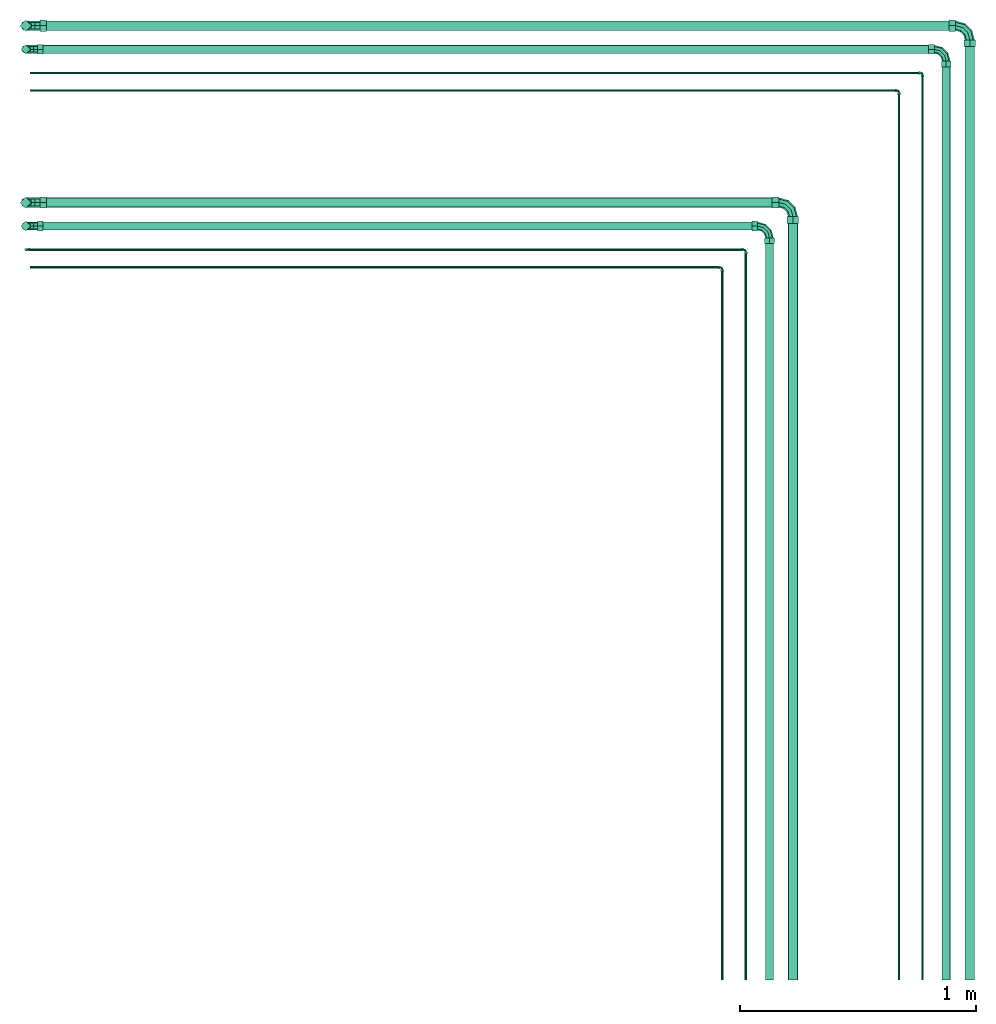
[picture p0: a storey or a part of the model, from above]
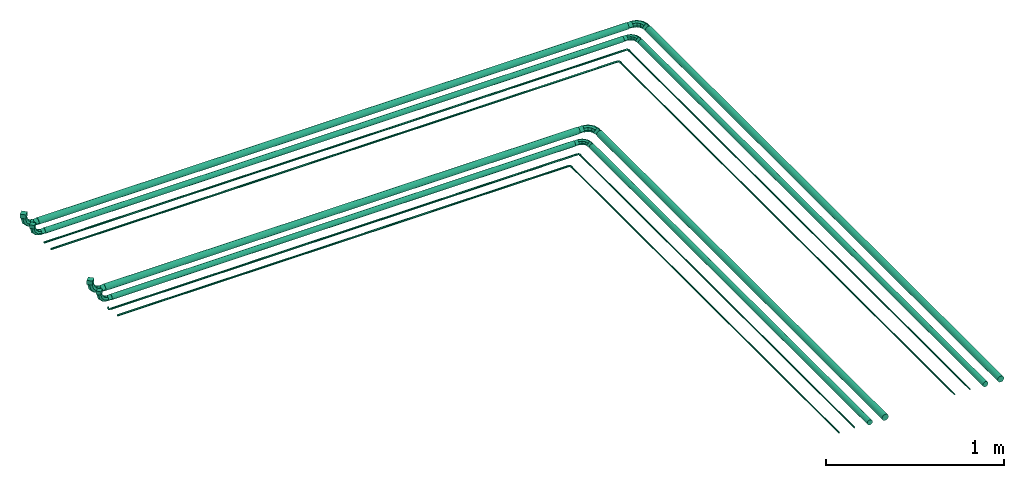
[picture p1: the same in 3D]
Properties of the parts of a building model (IFC2X3), part 1 of 7

# File
Description: ViewDefinition [CoordinationView_V2.0, QuantityTakeOffAddOnView], RevitIdentifiers [ContentGUID: b6227886-03ab-44f0-81d4-b4d026a18376, VersionGUID: a14e6cfa-9476-4cd4-931d-6547d9f84653, NumberOfSaves: 1519], CoordinateReference [CoordinateBase: Interner Ursprung, ProjectSite: Intern]
File name: 593 Vivantes - Ausbau VZ Seidelbastweg.ifc
Time: 2026-07-30T15:20:55+01:00
Author: GIEL Planungsgesellschaft mbH, info@giel.com
Organization: GIEL Planungsgesellschaft mbH
Written by: ODA SDAI 24.12
Made in: Autodesk Revit 25.4.41.14 (DEU) - IFC 25.4.41.14

# IfcProject, 0804
LongName: Mieter-Ausbau der Lagerhalle zu einem Speisenverteilzentrum

# IfcSite, Default
RefLatitude: 50, 46, 31, 241455; RefLongitude: 6, 5, 1, 991844; RefElevation: 0 mm

# IfcSite: ARC_ALL_Koordinationskörper_Doppelpyramide:ARC_ALL_Koordinationskörper_Doppelpyramide, ARC_ALL_Koordinationskörper_Doppelpyramide:ARC_ALL_Koordinationskörper_Doppelpyramide:4717062
Material: KOO_Pyramide
BaseQuantities - GrossArea: 3.23607 m2

# IfcBuildingStorey: Ebene:OKFF (3)
Name | LongName | Elevation (mm)
EG_Technik_FFB | EG_Technik_FFB | 695.653
EG_Produktion_FFB | EG_Produktion_FFB | 1730.7
Wartung_FFB | Wartung_FFB | 7130.7

# IfcCovering: Deckensystem:Kühlraum 100 (6)
In: EG_Produktion_FFB
Type - PredefinedType: CEILING
Material: GPG_Kühlraum 8 mm, GPG_Kühlraum 84 mm, GPG_Kühlraum 8 mm
Pset Bauphysik - OQ_Typ gem. Bauphysik: Pos. 2.4; U = 0,27 W/(m²/K)
Pset_FM-Vivantes - Baujahr: 1; Prüfpflicht: yes; Prüfintervall: 1; Sammelobjekt: yes; rechn. Lebensdauer: 1; Familie und Typ: Deckensystem: Kühlraum 100; Klasse: 471; Bezeichnung: Deckensystem: Kühlraum 100; AKS: i.b.; Standort: i.b.; Hersteller: i.b.; Hersteller-Typ: i.b.; Seriennummer: i.b.; Gewährleistungsgeber: 1; Betriebsstatus: i.b.; technischer Zustand: i.b.; Eigentümer: i.b.; Bemerkung: i.b.
Name (Deckensystem:Kühlraum 100:...) | GrossCeilingArea (m2)
4498795 | 284.674
4499242 | 243.11
4832303 | 16.77
4832498 | 883.613
4832682 | 76.866
4832818 | 9.5834

# IfcCovering: Deckensystem:Kühlraum 150, Deckensystem:Kühlraum 150:4499552
In: EG_Produktion_FFB
Type - PredefinedType: CEILING
Material: GPG_Kühlraum 8 mm, GPG_Kühlraum 134 mm, GPG_Kühlraum 8 mm
Pset Bauphysik - OQ_Typ gem. Bauphysik: Pos. 2.5; U = 0,18 W/(m²/K)
Pset_FM-Vivantes - Baujahr: 1; Prüfpflicht: yes; Prüfintervall: 1; Sammelobjekt: yes; rechn. Lebensdauer: 1; Familie und Typ: Deckensystem: Kühlraum 150; Klasse: 471; Bezeichnung: Deckensystem: Kühlraum 150; AKS: i.b.; Standort: i.b.; Hersteller: i.b.; Hersteller-Typ: i.b.; Seriennummer: i.b.; Gewährleistungsgeber: 1; Betriebsstatus: i.b.; technischer Zustand: i.b.; Eigentümer: i.b.; Bemerkung: i.b.
BaseQuantities - GrossCeilingArea: 107.964 m2

# IfcCovering: Rohrdämmung außen:Armaflex-Schlauch (1548)
Type - PredefinedType: INSULATION
Material: Dämmung - Armaflex-Schlauch
Pset_FM-Vivantes - Baujahr: 1; Prüfpflicht: yes; Prüfintervall: 1; Sammelobjekt: yes; rechn. Lebensdauer: 1; fahrbar: no; Familie und Typ: Rohrdämmung außen: Armaflex-Schlauch; Klasse: 471; Bezeichnung: Armaflex-Schlauch; AKS: i.b.; Standort: i.b.; Hersteller: i.b.; Hersteller-Typ: i.b.; Seriennummer: i.b.; Gewährleistungsgeber: 1; Betriebsstatus: i.b.; technischer Zustand: i.b.; Eigentümer: i.b.; Bemerkung: i.b.
Name (Rohrdämmung außen:Armaflex-Schlauch:...) | In | Systemname
8579191 | EG_Produktion_FFB | A - Kondensatleitung Gaskühler
8579194 | EG_Produktion_FFB | A - Kondensatleitung Gaskühler
8579200 | EG_Produktion_FFB | A - Kondensatleitung Gaskühler | BaseQuantities - GrossCeilingArea: 0.00418476 m2
8579203 | EG_Produktion_FFB | A - Kondensatleitung Gaskühler
8579206 | EG_Produktion_FFB | A - Kondensatleitung Gaskühler
8579212 | EG_Produktion_FFB | A - Kondensatleitung Gaskühler | BaseQuantities - GrossCeilingArea: 0.00418476 m2
8579215 | EG_Produktion_FFB | A - Kondensatleitung Gaskühler | BaseQuantities - GrossCeilingArea: 0.00418476 m2
8579218 | Wartung_FFB | A - Kondensatleitung Gaskühler
8579221 | EG_Produktion_FFB | A - Kondensatleitung Gaskühler
8579224 | EG_Produktion_FFB | A - Kondensatleitung Gaskühler
8579227 | Wartung_FFB | A - Kondensatleitung Gaskühler
8579230 | Wartung_FFB | A - Kondensatleitung Gaskühler
8579233 | Wartung_FFB | A - Kondensatleitung Gaskühler
8579236 | EG_Produktion_FFB | A - Druckleitung Gaskühler
8579239 | EG_Produktion_FFB | A - Druckleitung Gaskühler
8579242 | EG_Produktion_FFB | A - Druckleitung Gaskühler | BaseQuantities - GrossCeilingArea: 0.00502579 m2
8579245 | EG_Produktion_FFB | A - Druckleitung Gaskühler
8579248 | EG_Produktion_FFB | A - Druckleitung Gaskühler | BaseQuantities - GrossCeilingArea: 0.00502579 m2
8579251 | EG_Produktion_FFB | A - Druckleitung Gaskühler | BaseQuantities - GrossCeilingArea: 0.00502579 m2
8579254 | Wartung_FFB | A - Druckleitung Gaskühler
8579257 | Wartung_FFB | A - Druckleitung Gaskühler
8579263 | EG_Produktion_FFB | A - Druckleitung Gaskühler
8579266 | EG_Produktion_FFB | A - Druckleitung Gaskühler
8579281 | Wartung_FFB | B - Kondensatleitung Gaskühler
8579284 | Wartung_FFB | B - Druckleitung Gaskühler
8579287 | Wartung_FFB | B - Kondensatleitung Gaskühler
8579290 | Wartung_FFB | B - Druckleitung Gaskühler
8579293 | Wartung_FFB | B - Kondensatleitung Gaskühler
8579296 | Wartung_FFB | B - Druckleitung Gaskühler
8579297 | EG_Produktion_FFB | B - Druckleitung Gaskühler
8579300 | Wartung_FFB | B - Kondensatleitung Gaskühler
8579303 | Wartung_FFB | B - Druckleitung Gaskühler
8579308 | Wartung_FFB | B - Kondensatleitung Gaskühler
8579309 | Wartung_FFB | B - Kondensatleitung Gaskühler | BaseQuantities - GrossCeilingArea: 0.00418476 m2
8579312 | Wartung_FFB | B - Kondensatleitung Gaskühler
8579317 | Wartung_FFB | B - Druckleitung Gaskühler
8579318 | Wartung_FFB | B - Druckleitung Gaskühler | BaseQuantities - GrossCeilingArea: 0.00502579 m2
8579324 | EG_Produktion_FFB | B - Druckleitung Gaskühler | BaseQuantities - GrossCeilingArea: 0.00502579 m2
8579327 | EG_Produktion_FFB | B - Kondensatleitung Gaskühler | BaseQuantities - GrossCeilingArea: 0.00418476 m2
8579330 | Wartung_FFB | B - Kondensatleitung Gaskühler
8579333 | Wartung_FFB | B - Druckleitung Gaskühler
8579339 | EG_Produktion_FFB | B - Kondensatleitung Gaskühler
8579344 | EG_Produktion_FFB | B - Kondensatleitung Gaskühler
8579349 | EG_Produktion_FFB | B - Kondensatleitung Gaskühler
8579350 | EG_Produktion_FFB | B - Kondensatleitung Gaskühler | BaseQuantities - GrossCeilingArea: 0.00418476 m2
8579359 | EG_Produktion_FFB | B - Druckleitung Gaskühler
8579365 | EG_Produktion_FFB | B - Druckleitung Gaskühler | BaseQuantities - GrossCeilingArea: 0.00502579 m2
8579368 | EG_Produktion_FFB | B - Druckleitung Gaskühler
8579371 | EG_Produktion_FFB | A - FL-Str.01_NK-KK-TK
8579401 | EG_Produktion_FFB | A - FL-Str.01_NK-KK-TK
8579407 | EG_Produktion_FFB | A - FL-Str.01_NK-KK-TK
8579412 | EG_Produktion_FFB | A - FL-Str.01_NK-KK-TK
8579414 | EG_Produktion_FFB | A - FL-Str.01_NK-KK-TK | BaseQuantities - GrossCeilingArea: 0.00865886 m2
8579418 | EG_Produktion_FFB | A - FL-Str.01_NK-KK-TK
8579420 | EG_Produktion_FFB | A - FL-Str.01_NK-KK-TK | BaseQuantities - GrossCeilingArea: 0.00865886 m2
8579427 | EG_Produktion_FFB | A - FL-Str.01_NK-KK-TK
8579429 | EG_Produktion_FFB | A - FL-Str.01_NK-KK-TK | BaseQuantities - GrossCeilingArea: 0.00796711 m2
8579436 | EG_Produktion_FFB | A - FL-Str.01_NK-KK-TK
8579438 | EG_Produktion_FFB | A - FL-Str.01_NK-KK-TK | BaseQuantities - GrossCeilingArea: 0.00865886 m2
8579440 | EG_Produktion_FFB | A - FL-Str.01_NK-KK-TK | BaseQuantities - GrossCeilingArea: 0.00662464 m2
8579453 | EG_Produktion_FFB | A - FL-Str.01_NK-KK-TK
8579455 | EG_Produktion_FFB | A - FL-Str.01_NK-KK-TK | BaseQuantities - GrossCeilingArea: 0.0045539 m2
8579459 | EG_Produktion_FFB | A - FL-Str.01_NK-KK-TK
8579461 | EG_Produktion_FFB | A - FL-Str.01_NK-KK-TK | BaseQuantities - GrossCeilingArea: 0.00376881 m2
8579465 | EG_Produktion_FFB | A - FL-Str.01_NK-KK-TK
8579467 | EG_Produktion_FFB | A - FL-Str.01_NK-KK-TK | BaseQuantities - GrossCeilingArea: 0.00304559 m2
8579501 | EG_Produktion_FFB | A - FL-Str.01_NK-KK-TK
8579503 | EG_Produktion_FFB | A - FL-Str.01_NK-KK-TK | BaseQuantities - GrossCeilingArea: 0.00483791 m2
8579507 | EG_Produktion_FFB | A - FL-Str.01_NK-KK-TK
8579509 | EG_Produktion_FFB | A - FL-Str.01_NK-KK-TK | BaseQuantities - GrossCeilingArea: 0.00599476 m2
8579515 | EG_Produktion_FFB | A - FL-Str.01_NK-KK-TK
8579518 | EG_Produktion_FFB | A - FL-Str.01_NK-KK-TK
8579523 | EG_Produktion_FFB | A - FL-Str.01_NK-KK-TK
8579524 | EG_Produktion_FFB | A - FL-Str.01_NK-KK-TK | BaseQuantities - GrossCeilingArea: 0.00417616 m2
8579533 | EG_Produktion_FFB | B - FL-Str.01_NK-KK-TK
8579536 | EG_Produktion_FFB | B - FL-Str.01_NK-KK-TK
8579541 | EG_Produktion_FFB | B - FL-Str.01_NK-KK-TK
8579542 | EG_Produktion_FFB | B - FL-Str.01_NK-KK-TK | BaseQuantities - GrossCeilingArea: 0.00417616 m2
8579587 | EG_Produktion_FFB | B - FL-Str.01_NK-KK-TK
8579589 | EG_Produktion_FFB | B - FL-Str.01_NK-KK-TK | BaseQuantities - GrossCeilingArea: 0.0045539 m2
8579590 | EG_Produktion_FFB | B - FL-Str.01_NK-KK-TK
8579615 | EG_Produktion_FFB | B - FL-Str.01_NK-KK-TK
8579617 | EG_Produktion_FFB | B - FL-Str.01_NK-KK-TK | BaseQuantities - GrossCeilingArea: 0.00483791 m2
8579621 | EG_Produktion_FFB | B - FL-Str.01_NK-KK-TK
8579623 | EG_Produktion_FFB | B - FL-Str.01_NK-KK-TK | BaseQuantities - GrossCeilingArea: 0.00599476 m2
8579630 | EG_Produktion_FFB | B - FL-Str.01_NK-KK-TK
8579632 | EG_Produktion_FFB | B - FL-Str.01_NK-KK-TK | BaseQuantities - GrossCeilingArea: 0.00304559 m2
8579636 | EG_Produktion_FFB | B - FL-Str.01_NK-KK-TK
8579638 | EG_Produktion_FFB | B - FL-Str.01_NK-KK-TK | BaseQuantities - GrossCeilingArea: 0.00376881 m2
8579645 | EG_Produktion_FFB | B - FL-Str.01_NK-KK-TK
8579647 | EG_Produktion_FFB | B - FL-Str.01_NK-KK-TK | BaseQuantities - GrossCeilingArea: 0.00662464 m2
8579651 | EG_Produktion_FFB | B - FL-Str.01_NK-KK-TK
8579653 | EG_Produktion_FFB | B - FL-Str.01_NK-KK-TK | BaseQuantities - GrossCeilingArea: 0.00662464 m2
8579657 | EG_Produktion_FFB | B - FL-Str.01_NK-KK-TK
8579659 | EG_Produktion_FFB | B - FL-Str.01_NK-KK-TK | BaseQuantities - GrossCeilingArea: 0.00796711 m2
8579663 | EG_Produktion_FFB | B - FL-Str.01_NK-KK-TK
8579665 | EG_Produktion_FFB | B - FL-Str.01_NK-KK-TK | BaseQuantities - GrossCeilingArea: 0.00865886 m2
8579669 | EG_Produktion_FFB | B - FL-Str.01_NK-KK-TK
8579671 | EG_Produktion_FFB | B - FL-Str.01_NK-KK-TK | BaseQuantities - GrossCeilingArea: 0.00865886 m2
8579675 | EG_Produktion_FFB | B - FL-Str.01_NK-KK-TK
8579677 | EG_Produktion_FFB | B - FL-Str.01_NK-KK-TK | BaseQuantities - GrossCeilingArea: 0.00865886 m2
8579702 | EG_Produktion_FFB | B - FL-Str.01_NK-KK-TK
8579704 | EG_Produktion_FFB | B - FL-Str.01_NK-KK-TK | BaseQuantities - GrossCeilingArea: 0.00662464 m2
8579707 | EG_Produktion_FFB | A - FL-Str.03_NK-KK-TK
8579708 | EG_Produktion_FFB | A - FL-Str.03_NK-KK-TK
8579744 | EG_Produktion_FFB | A - FL-Str.03_NK-KK-TK
8579746 | EG_Produktion_FFB | A - FL-Str.03_NK-KK-TK | BaseQuantities - GrossCeilingArea: 0.00796711 m2
8579753 | EG_Produktion_FFB | A - FL-Str.03_NK-KK-TK
8579755 | EG_Produktion_FFB | A - FL-Str.03_NK-KK-TK | BaseQuantities - GrossCeilingArea: 0.00376881 m2
8579759 | EG_Produktion_FFB | A - FL-Str.03_NK-KK-TK
8579761 | EG_Produktion_FFB | A - FL-Str.03_NK-KK-TK | BaseQuantities - GrossCeilingArea: 0.00425419 m2
8579765 | EG_Produktion_FFB | A - FL-Str.03_NK-KK-TK
8579767 | EG_Produktion_FFB | A - FL-Str.03_NK-KK-TK | BaseQuantities - GrossCeilingArea: 0.00599476 m2
8579771 | EG_Produktion_FFB | A - FL-Str.03_NK-KK-TK
8579773 | EG_Produktion_FFB | A - FL-Str.03_NK-KK-TK | BaseQuantities - GrossCeilingArea: 0.00662464 m2
8579776 | EG_Produktion_FFB | B - FL-Str.03_NK-KK-TK
8579806 | EG_Produktion_FFB | B - FL-Str.03_NK-KK-TK | BaseQuantities - GrossCeilingArea: 0.00865886 m2
8579815 | EG_Produktion_FFB | B - FL-Str.03_NK-KK-TK
8579817 | EG_Produktion_FFB | B - FL-Str.03_NK-KK-TK | BaseQuantities - GrossCeilingArea: 0.00865886 m2
8579821 | EG_Produktion_FFB | B - FL-Str.03_NK-KK-TK
8579823 | EG_Produktion_FFB | B - FL-Str.03_NK-KK-TK | BaseQuantities - GrossCeilingArea: 0.00796711 m2
8579830 | EG_Produktion_FFB | B - FL-Str.03_NK-KK-TK
8579832 | EG_Produktion_FFB | B - FL-Str.03_NK-KK-TK | BaseQuantities - GrossCeilingArea: 0.00376881 m2
8579836 | EG_Produktion_FFB | B - FL-Str.03_NK-KK-TK
8579838 | EG_Produktion_FFB | B - FL-Str.03_NK-KK-TK | BaseQuantities - GrossCeilingArea: 0.0045539 m2
8579842 | EG_Produktion_FFB | B - FL-Str.03_NK-KK-TK
8579844 | EG_Produktion_FFB | B - FL-Str.03_NK-KK-TK | BaseQuantities - GrossCeilingArea: 0.00599476 m2
8579848 | EG_Produktion_FFB | B - FL-Str.03_NK-KK-TK
8579850 | EG_Produktion_FFB | B - FL-Str.03_NK-KK-TK | BaseQuantities - GrossCeilingArea: 0.00662464 m2
8579851 | EG_Produktion_FFB | B - FL-Str.03_NK-KK-TK
8579866 | EG_Produktion_FFB | B - FL-Str.02_NK-KK-TK
8579870 | EG_Produktion_FFB | A - FL-Str.03_NK-KK-TK
8579879 | EG_Produktion_FFB | B - FL-Str.02_NK-KK-TK
8579881 | EG_Produktion_FFB | B - FL-Str.02_NK-KK-TK | BaseQuantities - GrossCeilingArea: 0.00796711 m2
8579898 | EG_Produktion_FFB | A - FL-Str.02_NK-KK-TK
8579904 | EG_Produktion_FFB | A - FL-Str.02_NK-KK-TK
8579906 | EG_Produktion_FFB | A - FL-Str.02_NK-KK-TK | BaseQuantities - GrossCeilingArea: 0.00796711 m2
8579909 | EG_Produktion_FFB | A - FL-Str.03_NK-KK-TK
8579910 | EG_Produktion_FFB | A - FL-Str.03_NK-KK-TK
8579913 | EG_Produktion_FFB | A - FL-Str.03_NK-KK-TK
8579914 | EG_Produktion_FFB | B - FL-Str.03_NK-KK-TK
8579915 | EG_Produktion_FFB | B - FL-Str.03_NK-KK-TK
8579920 | EG_Produktion_FFB | B - FL-Str.03_NK-KK-TK
8579925 | EG_Produktion_FFB | B - FL-Str.03_NK-KK-TK | BaseQuantities - GrossCeilingArea: 0.00417616 m2
8579930 | EG_Produktion_FFB | A - FL-Str.03_NK-KK-TK | BaseQuantities - GrossCeilingArea: 0.00417616 m2
8579933 | EG_Produktion_FFB | B - FL-Str.03_NK-KK-TK
8579936 | EG_Produktion_FFB | B - FL-Str.03_NK-KK-TK
8579939 | EG_Produktion_FFB | A - FL-Str.03_NK-KK-TK
8579952 | EG_Produktion_FFB | A - FL-Str.02_NK-KK-TK
8579954 | EG_Produktion_FFB | A - FL-Str.02_NK-KK-TK | BaseQuantities - GrossCeilingArea: 0.00662464 m2
8579958 | EG_Produktion_FFB | B - FL-Str.02_NK-KK-TK
8579960 | EG_Produktion_FFB | B - FL-Str.02_NK-KK-TK | BaseQuantities - GrossCeilingArea: 0.00662464 m2
8579967 | EG_Produktion_FFB | B - FL-Str.02_NK-KK-TK
8579969 | EG_Produktion_FFB | B - FL-Str.02_NK-KK-TK | BaseQuantities - GrossCeilingArea: 0.00662464 m2
8579987 | EG_Produktion_FFB | A - FL-Str.02_NK-KK-TK
8579989 | EG_Produktion_FFB | A - FL-Str.02_NK-KK-TK | BaseQuantities - GrossCeilingArea: 0.00662464 m2
8580011 | EG_Produktion_FFB | B - FL-Str.02_NK-KK-TK
8580013 | EG_Produktion_FFB | B - FL-Str.02_NK-KK-TK | BaseQuantities - GrossCeilingArea: 0.00662464 m2
8580020 | EG_Produktion_FFB | A - FL-Str.02_NK-KK-TK
8580022 | EG_Produktion_FFB | A - FL-Str.02_NK-KK-TK | BaseQuantities - GrossCeilingArea: 0.00662464 m2
8580029 | EG_Produktion_FFB | B - FL-Str.02_NK-KK-TK
8580031 | EG_Produktion_FFB | B - FL-Str.02_NK-KK-TK | BaseQuantities - GrossCeilingArea: 0.00662464 m2
8580065 | EG_Produktion_FFB | A - FL-Str.02_NK-KK-TK
8580067 | EG_Produktion_FFB | A - FL-Str.02_NK-KK-TK | BaseQuantities - GrossCeilingArea: 0.00662464 m2
8580077 | EG_Produktion_FFB | B - FL-Str.02_NK-KK-TK
8580079 | EG_Produktion_FFB | B - FL-Str.02_NK-KK-TK | BaseQuantities - GrossCeilingArea: 0.00599476 m2
8580086 | EG_Produktion_FFB | A - FL-Str.02_NK-KK-TK
8580088 | EG_Produktion_FFB | A - FL-Str.02_NK-KK-TK | BaseQuantities - GrossCeilingArea: 0.00599476 m2
8580122 | EG_Produktion_FFB | B - FL-Str.02_NK-KK-TK
8580124 | EG_Produktion_FFB | B - FL-Str.02_NK-KK-TK | BaseQuantities - GrossCeilingArea: 0.00483791 m2
8580131 | EG_Produktion_FFB | A - FL-Str.02_NK-KK-TK
8580133 | EG_Produktion_FFB | A - FL-Str.02_NK-KK-TK | BaseQuantities - GrossCeilingArea: 0.00483791 m2
8580143 | EG_Produktion_FFB | A - FL-Str.02_NK-KK-TK
8580145 | EG_Produktion_FFB | A - FL-Str.02_NK-KK-TK | BaseQuantities - GrossCeilingArea: 0.00483791 m2
8580539 | Wartung_FFB | B - Druckleitung Gaskühler
8580560 | Wartung_FFB | A - Druckleitung Gaskühler
8580563 | Wartung_FFB | A - Druckleitung Gaskühler
8580672 | EG_Produktion_FFB | B - Kondensatleitung Gaskühler
8580677 | EG_Produktion_FFB | B - Kondensatleitung Gaskühler
8580895 | EG_Produktion_FFB | B - FL-Str.02_NK-KK-TK
8580897 | EG_Produktion_FFB | B - FL-Str.02_NK-KK-TK | BaseQuantities - GrossCeilingArea: 0.00483791 m2
8582852 | EG_Produktion_FFB | A - SL_KK
8582855 | EG_Produktion_FFB | A - SL_KK
8582861 | EG_Produktion_FFB | A - SL_KK | BaseQuantities - GrossCeilingArea: 0.00348054 m2
8582998 | EG_Produktion_FFB | A - SL_KK
8583088 | EG_Produktion_FFB | A - SL_KK
8583112 | EG_Produktion_FFB | A - SL_KK
8583330 | EG_Produktion_FFB | A - SL_KK
8583610 | EG_Produktion_FFB | A - SL_KK
8583612 | EG_Produktion_FFB | A - SL_KK | BaseQuantities - GrossCeilingArea: 0.00304559 m2
8583719 | EG_Produktion_FFB | A - SL_KK
8583721 | EG_Produktion_FFB | A - SL_KK | BaseQuantities - GrossCeilingArea: 0.00238424 m2
8583917 | EG_Produktion_FFB | A - SL_KK
8583919 | EG_Produktion_FFB | A - SL_KK | BaseQuantities - GrossCeilingArea: 0.00483791 m2
8583940 | EG_Produktion_FFB | A - SL_KK
8583942 | EG_Produktion_FFB | A - SL_KK | BaseQuantities - GrossCeilingArea: 0.00483791 m2
8584011 | EG_Produktion_FFB | A - SL_KK
8584013 | EG_Produktion_FFB | A - SL_KK | BaseQuantities - GrossCeilingArea: 0.00662464 m2
8584297 | EG_Produktion_FFB | A - SL_KK
8584299 | EG_Produktion_FFB | A - SL_KK | BaseQuantities - GrossCeilingArea: 0.00483791 m2
8584322 | EG_Produktion_FFB | A - SL_KK
8584324 | EG_Produktion_FFB | A - SL_KK | BaseQuantities - GrossCeilingArea: 0.00599476 m2
8585075 | EG_Produktion_FFB | B - SL_KK
8585077 | EG_Produktion_FFB | B - SL_KK | BaseQuantities - GrossCeilingArea: 0.00238424 m2
8585078 | EG_Produktion_FFB | B - SL_KK
8585103 | EG_Produktion_FFB | B - SL_KK
8585105 | EG_Produktion_FFB | B - SL_KK | BaseQuantities - GrossCeilingArea: 0.00304559 m2
8585109 | EG_Produktion_FFB | B - SL_KK
8585139 | EG_Produktion_FFB | B - SL_KK
8585141 | EG_Produktion_FFB | B - SL_KK | BaseQuantities - GrossCeilingArea: 0.00483791 m2
8585145 | EG_Produktion_FFB | B - SL_KK
8585147 | EG_Produktion_FFB | B - SL_KK | BaseQuantities - GrossCeilingArea: 0.00483791 m2
8585151 | EG_Produktion_FFB | B - SL_KK
8585153 | EG_Produktion_FFB | B - SL_KK | BaseQuantities - GrossCeilingArea: 0.00483791 m2
8585157 | EG_Produktion_FFB | B - SL_KK
8585159 | EG_Produktion_FFB | B - SL_KK | BaseQuantities - GrossCeilingArea: 0.00599476 m2
8585163 | EG_Produktion_FFB | B - SL_KK
8585165 | EG_Produktion_FFB | B - SL_KK | BaseQuantities - GrossCeilingArea: 0.00662464 m2
8585189 | EG_Produktion_FFB | B - SL_KK | BaseQuantities - GrossCeilingArea: 0.00483791 m2
8585996 | EG_Produktion_FFB | B - SL_KK
8585998 | EG_Produktion_FFB | B - SL_KK | BaseQuantities - GrossCeilingArea: 0.00376881 m2
8586325 | EG_Produktion_FFB | B - SL_KK
8586327 | EG_Produktion_FFB | B - SL_KK | BaseQuantities - GrossCeilingArea: 0.0045539 m2
8586419 | EG_Produktion_FFB | B - SL_KK
8586422 | EG_Produktion_FFB | B - SL_KK
8586428 | EG_Produktion_FFB | B - SL_KK | BaseQuantities - GrossCeilingArea: 0.00348054 m2
8586465 | EG_Produktion_FFB | B - SL_KK
8586564 | EG_Produktion_FFB | A - SL_NK-Str.02
8586565 | EG_Produktion_FFB | A - SL_NK-Str.02
8586601 | EG_Produktion_FFB | A - SL_NK-Str.02
8586603 | EG_Produktion_FFB | A - SL_NK-Str.02 | BaseQuantities - GrossCeilingArea: 0.00662464 m2
8586622 | EG_Produktion_FFB | A - SL_NK-Str.02
8586624 | EG_Produktion_FFB | A - SL_NK-Str.02 | BaseQuantities - GrossCeilingArea: 0.0042699 m2
8586628 | EG_Produktion_FFB | A - SL_NK-Str.02
8586630 | EG_Produktion_FFB | A - SL_NK-Str.02 | BaseQuantities - GrossCeilingArea: 0.00599476 m2
8586633 | EG_Produktion_FFB | B - SL_NK-Str.02
8586663 | EG_Produktion_FFB | B - SL_NK-Str.02 | BaseQuantities - GrossCeilingArea: 0.00865886 m2
8586672 | EG_Produktion_FFB | B - SL_NK-Str.02
8586674 | EG_Produktion_FFB | B - SL_NK-Str.02 | BaseQuantities - GrossCeilingArea: 0.00796711 m2
8586678 | EG_Produktion_FFB | B - SL_NK-Str.02
8586680 | EG_Produktion_FFB | B - SL_NK-Str.02 | BaseQuantities - GrossCeilingArea: 0.00662464 m2
8586699 | EG_Produktion_FFB | B - SL_NK-Str.02
8586701 | EG_Produktion_FFB | B - SL_NK-Str.02 | BaseQuantities - GrossCeilingArea: 0.0042699 m2
8586705 | EG_Produktion_FFB | B - SL_NK-Str.02
8586707 | EG_Produktion_FFB | B - SL_NK-Str.02 | BaseQuantities - GrossCeilingArea: 0.00599476 m2
8586708 | EG_Produktion_FFB | B - SL_NK-Str.02
8586723 | EG_Produktion_FFB | B - SL_NK-Str.01
8586755 | EG_Produktion_FFB | A - SL_NK-Str.01
8586808 | EG_Produktion_FFB | A - SL_NK-Str.01
8586850 | EG_Produktion_FFB | B - SL_NK-Str.01
8586898 | EG_Produktion_FFB | B - SL_NK-Str.01
8586900 | EG_Produktion_FFB | B - SL_NK-Str.01 | BaseQuantities - GrossCeilingArea: 0.00865886 m2
8586907 | EG_Produktion_FFB | A - SL_NK-Str.01
8586909 | EG_Produktion_FFB | A - SL_NK-Str.01 | BaseQuantities - GrossCeilingArea: 0.00865886 m2
8586964 | EG_Produktion_FFB | A - SL_NK-Str.01
8586966 | EG_Produktion_FFB | A - SL_NK-Str.01 | BaseQuantities - GrossCeilingArea: 0.00865886 m2
8586973 | EG_Produktion_FFB | B - SL_NK-Str.01
8586975 | EG_Produktion_FFB | B - SL_NK-Str.01 | BaseQuantities - GrossCeilingArea: 0.00865886 m2
8587739 | EG_Produktion_FFB | A - SL_NK-Str.01 | BaseQuantities - GrossCeilingArea: 0.0101869 m2
8587918 | EG_Produktion_FFB | B - SL_NK-Str.01 | BaseQuantities - GrossCeilingArea: 0.0101869 m2
8587940 | EG_Produktion_FFB | A - SL_NK-Str.02
8587941 | EG_Produktion_FFB | A - SL_NK-Str.02
8587945 | EG_Produktion_FFB | B - SL_NK-Str.02
8587946 | EG_Produktion_FFB | B - SL_NK-Str.02
8587956 | EG_Produktion_FFB | B - SL_NK-Str.02 | BaseQuantities - GrossCeilingArea: 0.00493511 m2
8587961 | EG_Produktion_FFB | A - SL_NK-Str.02 | BaseQuantities - GrossCeilingArea: 0.00493511 m2
8588618 | EG_Produktion_FFB | B - SL_NK-Str.02
8588629 | EG_Produktion_FFB | A - SL_NK-Str.02
8588647 | EG_Produktion_FFB | B - SL_NK-Str.02
8588657 | EG_Produktion_FFB | A - SL_NK-Str.02
8589465 | EG_Produktion_FFB | B - SL_TK
8589526 | EG_Produktion_FFB | A - SL_TK
8589761 | EG_Produktion_FFB | A - SL_TK
8589763 | EG_Produktion_FFB | A - SL_TK | BaseQuantities - GrossCeilingArea: 0.0042699 m2
8589856 | EG_Produktion_FFB | B - SL_TK
8589858 | EG_Produktion_FFB | B - SL_TK | BaseQuantities - GrossCeilingArea: 0.0042699 m2
8589893 | EG_Produktion_FFB | B - SL_TK
8589895 | EG_Produktion_FFB | B - SL_TK | BaseQuantities - GrossCeilingArea: 0.00599476 m2
8590505 | EG_Produktion_FFB | B - SL_NK-Str.01
8590507 | EG_Produktion_FFB | B - SL_NK-Str.01 | BaseQuantities - GrossCeilingArea: 0.00865886 m2
8590805 | EG_Produktion_FFB | A - SL_NK-Str.01
8590807 | EG_Produktion_FFB | A - SL_NK-Str.01 | BaseQuantities - GrossCeilingArea: 0.00865886 m2
8591208 | EG_Produktion_FFB | A - SL_TK
8591844 | EG_Produktion_FFB | B - SL_NK-Str.01
8591846 | EG_Produktion_FFB | B - SL_NK-Str.01 | BaseQuantities - GrossCeilingArea: 0.00865886 m2
8591988 | EG_Produktion_FFB | B - SL_NK-Str.01
8591990 | EG_Produktion_FFB | B - SL_NK-Str.01 | BaseQuantities - GrossCeilingArea: 0.00865886 m2
8592019 | EG_Produktion_FFB | B - SL_NK-Str.01
8592021 | EG_Produktion_FFB | B - SL_NK-Str.01 | BaseQuantities - GrossCeilingArea: 0.00865886 m2
8592221 | EG_Produktion_FFB | A - SL_NK-Str.01
8592223 | EG_Produktion_FFB | A - SL_NK-Str.01 | BaseQuantities - GrossCeilingArea: 0.00865886 m2
8592622 | EG_Produktion_FFB | A - SL_NK-Str.01
8592624 | EG_Produktion_FFB | A - SL_NK-Str.01 | BaseQuantities - GrossCeilingArea: 0.00865886 m2
8592664 | EG_Produktion_FFB | A - SL_NK-Str.01
8592666 | EG_Produktion_FFB | A - SL_NK-Str.01 | BaseQuantities - GrossCeilingArea: 0.00865886 m2
8593003 | EG_Produktion_FFB | A - SL_NK-Str.01
8593006 | EG_Produktion_FFB | A - SL_NK-Str.01 | BaseQuantities - GrossCeilingArea: 0.00493511 m2
8593009 | EG_Produktion_FFB | B - SL_NK-Str.01
8593012 | EG_Produktion_FFB | B - SL_NK-Str.01 | BaseQuantities - GrossCeilingArea: 0.00493511 m2
8593015 | EG_Produktion_FFB | A - FL-Str.02_NK-KK-TK
8593018 | EG_Produktion_FFB | A - FL-Str.02_NK-KK-TK | BaseQuantities - GrossCeilingArea: 0.00417616 m2
8593021 | EG_Produktion_FFB | B - FL-Str.02_NK-KK-TK
8593024 | EG_Produktion_FFB | B - FL-Str.02_NK-KK-TK | BaseQuantities - GrossCeilingArea: 0.00417616 m2
8593054 | EG_Produktion_FFB | A - SL_TK
8593057 | EG_Produktion_FFB | A - SL_TK | BaseQuantities - GrossCeilingArea: 0.00348054 m2
8593060 | EG_Produktion_FFB | B - SL_TK
8593063 | EG_Produktion_FFB | B - SL_TK | BaseQuantities - GrossCeilingArea: 0.00348054 m2
8593116 | EG_Produktion_FFB | B - SL_TK
8593131 | EG_Produktion_FFB | A - FL-Str.02_NK-KK-TK
8593203 | EG_Produktion_FFB | A - SL_TK
8593258 | EG_Produktion_FFB | A - SL_NK-Str.01
8593320 | EG_Produktion_FFB | B - SL_NK-Str.01
8593333 | EG_Produktion_FFB | B - FL-Str.02_NK-KK-TK
8593358 | EG_Produktion_FFB | B - SL_TK
8593482 | EG_Produktion_FFB | A - FL-Str.02_NK-KK-TK
8593487 | EG_Produktion_FFB | A - SL_TK
8593497 | EG_Produktion_FFB | B - FL-Str.02_NK-KK-TK
8593507 | EG_Produktion_FFB | B - SL_NK-Str.01
8593512 | EG_Produktion_FFB | B - SL_NK-Str.01
8593517 | EG_Produktion_FFB | B - FL-Str.02_NK-KK-TK
8593520 | EG_Produktion_FFB | B - FL-Str.02_NK-KK-TK
8593525 | EG_Produktion_FFB | B - SL_TK
8593530 | EG_Produktion_FFB | B - SL_TK
8593535 | EG_Produktion_FFB | A - SL_TK
8593543 | EG_Produktion_FFB | A - FL-Str.02_NK-KK-TK
8593546 | EG_Produktion_FFB | A - FL-Str.02_NK-KK-TK
8593551 | EG_Produktion_FFB | A - SL_NK-Str.01
8593556 | EG_Produktion_FFB | A - SL_NK-Str.01
8593917 | EG_Produktion_FFB | B - SL_NK-Str.01
8594326 | EG_Produktion_FFB | B - SL_NK-Str.02
8594527 | EG_Produktion_FFB | A - SL_NK-Str.01
8595026 | EG_Produktion_FFB | A - SL_NK-Str.02
8595057 | EG_Produktion_FFB | A - SL_NK-Str.02
8597166 | EG_Produktion_FFB | A - Druckleitung Gaskühler
8597211 | EG_Produktion_FFB | A - Kondensatleitung Gaskühler
8597212 | EG_Produktion_FFB | A - Druckleitung Gaskühler
8597250 | EG_Produktion_FFB | A - Druckleitung Gaskühler
8597341 | EG_Produktion_FFB | A - Druckleitung Gaskühler
8597344 | EG_Produktion_FFB | A - Druckleitung Gaskühler
8597352 | EG_Produktion_FFB | A - Kondensatleitung Gaskühler
8597357 | EG_Produktion_FFB | A - Kondensatleitung Gaskühler
8598244 | EG_Produktion_FFB | A - SL_KK | BaseQuantities - GrossCeilingArea: 0.00376881 m2
8599351 | EG_Produktion_FFB | A - FL-Str.03_NK-KK-TK
8599354 | EG_Produktion_FFB | A - FL-Str.03_NK-KK-TK
8599357 | EG_Produktion_FFB | A - FL-Str.03_NK-KK-TK
8599360 | EG_Produktion_FFB | A - FL-Str.03_NK-KK-TK
8599363 | EG_Produktion_FFB | A - FL-Str.03_NK-KK-TK
8599366 | EG_Produktion_FFB | A - FL-Str.03_NK-KK-TK
8599371 | EG_Produktion_FFB | A - FL-Str.03_NK-KK-TK
8599372 | EG_Produktion_FFB | A - FL-Str.03_NK-KK-TK
8599375 | EG_Produktion_FFB | A - FL-Str.03_NK-KK-TK
8599378 | EG_Produktion_FFB | B - FL-Str.03_NK-KK-TK
8599381 | EG_Produktion_FFB | B - FL-Str.03_NK-KK-TK
8599384 | EG_Produktion_FFB | B - FL-Str.03_NK-KK-TK
8599387 | EG_Produktion_FFB | B - FL-Str.03_NK-KK-TK
8599390 | EG_Produktion_FFB | B - FL-Str.03_NK-KK-TK
8599393 | EG_Produktion_FFB | B - FL-Str.03_NK-KK-TK
8599396 | EG_Produktion_FFB | B - FL-Str.03_NK-KK-TK
8599402 | EG_Produktion_FFB | A - SL_NK-Str.02
8599405 | EG_Produktion_FFB | A - SL_NK-Str.02
8599408 | EG_Produktion_FFB | A - SL_NK-Str.02
8599411 | EG_Produktion_FFB | A - SL_NK-Str.02
8599416 | EG_Produktion_FFB | A - SL_NK-Str.02
8599417 | EG_Produktion_FFB | A - SL_NK-Str.02
8599420 | EG_Produktion_FFB | A - SL_NK-Str.02
8599425 | EG_Produktion_FFB | B - SL_NK-Str.02
8599428 | EG_Produktion_FFB | B - SL_NK-Str.02
8599431 | EG_Produktion_FFB | B - SL_NK-Str.02
8599434 | EG_Produktion_FFB | B - SL_NK-Str.02
8599437 | EG_Produktion_FFB | B - SL_NK-Str.02
8599440 | EG_Produktion_FFB | B - SL_NK-Str.02
8599443 | EG_Produktion_FFB | B - SL_NK-Str.02
8599446 | EG_Produktion_FFB | B - SL_NK-Str.02
8599449 | EG_Produktion_FFB | A - SL_NK-Str.02
8599452 | EG_Produktion_FFB | A - SL_NK-Str.02
8599453 | EG_Produktion_FFB | A - SL_NK-Str.02
8599457 | EG_Produktion_FFB | B - SL_NK-Str.02
8599459 | EG_Produktion_FFB | B - SL_NK-Str.02 | BaseQuantities - GrossCeilingArea: 0.00398887 m2
8599462 | EG_Produktion_FFB | B - SL_NK-Str.02
8599466 | EG_Produktion_FFB | A - SL_NK-Str.02
8599468 | EG_Produktion_FFB | A - SL_NK-Str.02 | BaseQuantities - GrossCeilingArea: 0.00398887 m2
8599477 | EG_Produktion_FFB | A - SL_NK-Str.02
8599641 | EG_Produktion_FFB | B - SL_NK-Str.02
8599684 | EG_Produktion_FFB | B - SL_NK-Str.02
8599761 | EG_Produktion_FFB | A - FL-Str.03_NK-KK-TK | BaseQuantities - GrossCeilingArea: 0.00865886 m2
8599797 | EG_Produktion_FFB | A - FL-Str.03_NK-KK-TK
8599913 | EG_Produktion_FFB | A - SL_NK-Str.02
8599953 | EG_Produktion_FFB | A - SL_NK-Str.02
8600079 | EG_Produktion_FFB | A - SL_NK-Str.02 | BaseQuantities - GrossCeilingArea: 0.00865886 m2
8600186 | EG_Produktion_FFB | A - SL_NK-Str.02 | BaseQuantities - GrossCeilingArea: 0.00796711 m2
8600295 | EG_Produktion_FFB | A - FL-Str.03_NK-KK-TK | BaseQuantities - GrossCeilingArea: 0.00865886 m2
8601365 | EG_Produktion_FFB | A - FL-Str.03_NK-KK-TK
8602650 | EG_Produktion_FFB | A - FL-Str.01_NK-KK-TK
8602653 | EG_Produktion_FFB | A - FL-Str.01_NK-KK-TK
8602656 | EG_Produktion_FFB | A - FL-Str.01_NK-KK-TK
8602659 | EG_Produktion_FFB | A - FL-Str.01_NK-KK-TK
8602662 | EG_Produktion_FFB | A - FL-Str.01_NK-KK-TK
8602665 | EG_Produktion_FFB | A - FL-Str.01_NK-KK-TK
8602674 | EG_Produktion_FFB | A - FL-Str.01_NK-KK-TK
8602677 | EG_Produktion_FFB | A - FL-Str.01_NK-KK-TK
8602680 | EG_Produktion_FFB | A - FL-Str.01_NK-KK-TK
8602683 | EG_Produktion_FFB | A - FL-Str.01_NK-KK-TK
8602686 | EG_Produktion_FFB | A - FL-Str.01_NK-KK-TK
8602689 | EG_Produktion_FFB | A - FL-Str.01_NK-KK-TK
8602692 | EG_Produktion_FFB | A - FL-Str.01_NK-KK-TK
8602695 | EG_Produktion_FFB | A - FL-Str.01_NK-KK-TK
8602698 | EG_Produktion_FFB | A - FL-Str.01_NK-KK-TK
8602714 | EG_Produktion_FFB | A - SL_KK
8602722 | EG_Produktion_FFB | B - FL-Str.01_NK-KK-TK
8602725 | EG_Produktion_FFB | B - FL-Str.01_NK-KK-TK
8602728 | EG_Produktion_FFB | B - FL-Str.01_NK-KK-TK
8602731 | EG_Produktion_FFB | B - FL-Str.01_NK-KK-TK
8602734 | EG_Produktion_FFB | B - FL-Str.01_NK-KK-TK
8602740 | EG_Produktion_FFB | B - FL-Str.01_NK-KK-TK
8602743 | EG_Produktion_FFB | B - FL-Str.01_NK-KK-TK
8602746 | EG_Produktion_FFB | B - FL-Str.01_NK-KK-TK
8602749 | EG_Produktion_FFB | B - FL-Str.01_NK-KK-TK
8602752 | EG_Produktion_FFB | B - FL-Str.01_NK-KK-TK
8602755 | EG_Produktion_FFB | B - FL-Str.01_NK-KK-TK
8602758 | EG_Produktion_FFB | B - FL-Str.01_NK-KK-TK
8602761 | EG_Produktion_FFB | B - FL-Str.01_NK-KK-TK
8602764 | EG_Produktion_FFB | B - FL-Str.01_NK-KK-TK
8602773 | EG_Produktion_FFB | B - FL-Str.01_NK-KK-TK
8602776 | EG_Produktion_FFB | B - FL-Str.01_NK-KK-TK
8602783 | EG_Produktion_FFB | B - FL-Str.01_NK-KK-TK
8602788 | EG_Produktion_FFB | B - FL-Str.01_NK-KK-TK
8602792 | EG_Produktion_FFB | B - FL-Str.01_NK-KK-TK
8602800 | EG_Produktion_FFB | B - FL-Str.02_NK-KK-TK
8602803 | EG_Produktion_FFB | B - FL-Str.02_NK-KK-TK
8602806 | EG_Produktion_FFB | B - FL-Str.02_NK-KK-TK
8602809 | EG_Produktion_FFB | B - FL-Str.02_NK-KK-TK
8602813 | EG_Produktion_FFB | B - FL-Str.02_NK-KK-TK
8602815 | EG_Produktion_FFB | B - FL-Str.02_NK-KK-TK | BaseQuantities - GrossCeilingArea: 0.00361502 m2
8602818 | EG_Produktion_FFB | A - FL-Str.02_NK-KK-TK
8602822 | EG_Produktion_FFB | A - FL-Str.02_NK-KK-TK
8602829 | EG_Produktion_FFB | A - FL-Str.02_NK-KK-TK
8602831 | EG_Produktion_FFB | A - FL-Str.02_NK-KK-TK | BaseQuantities - GrossCeilingArea: 0.00361502 m2
8602836 | EG_Produktion_FFB | B - FL-Str.02_NK-KK-TK
8602839 | EG_Produktion_FFB | A - FL-Str.02_NK-KK-TK
8602842 | EG_Produktion_FFB | B - FL-Str.02_NK-KK-TK
8602845 | EG_Produktion_FFB | B - FL-Str.02_NK-KK-TK
8602849 | EG_Produktion_FFB | B - FL-Str.02_NK-KK-TK
8602854 | EG_Produktion_FFB | A - FL-Str.02_NK-KK-TK
8602857 | EG_Produktion_FFB | A - FL-Str.02_NK-KK-TK
8602863 | EG_Produktion_FFB | A - FL-Str.02_NK-KK-TK
8602867 | EG_Produktion_FFB | A - FL-Str.02_NK-KK-TK
8602869 | EG_Produktion_FFB | A - FL-Str.02_NK-KK-TK | BaseQuantities - GrossCeilingArea: 0.00177563 m2
8602870 | EG_Produktion_FFB | B - FL-Str.02_NK-KK-TK
8602873 | EG_Produktion_FFB | A - FL-Str.02_NK-KK-TK
8602876 | EG_Produktion_FFB | B - FL-Str.02_NK-KK-TK
8602879 | EG_Produktion_FFB | B - FL-Str.02_NK-KK-TK
8602882 | EG_Produktion_FFB | B - FL-Str.02_NK-KK-TK
8602894 | EG_Produktion_FFB | A - FL-Str.02_NK-KK-TK
8602900 | EG_Produktion_FFB | A - FL-Str.02_NK-KK-TK
8602912 | EG_Produktion_FFB | B - FL-Str.02_NK-KK-TK
8602915 | EG_Produktion_FFB | A - FL-Str.02_NK-KK-TK
8602918 | EG_Produktion_FFB | A - FL-Str.02_NK-KK-TK
8602924 | EG_Produktion_FFB | A - FL-Str.02_NK-KK-TK
8602933 | EG_Produktion_FFB | B - FL-Str.02_NK-KK-TK
8602939 | EG_Produktion_FFB | B - FL-Str.02_NK-KK-TK
8602945 | EG_Produktion_FFB | B - FL-Str.02_NK-KK-TK
8602954 | EG_Produktion_FFB | A - FL-Str.02_NK-KK-TK
8602957 | EG_Produktion_FFB | B - FL-Str.02_NK-KK-TK
8602960 | EG_Produktion_FFB | A - FL-Str.02_NK-KK-TK
8602971 | EG_Produktion_FFB | A - FL-Str.02_NK-KK-TK
8602980 | EG_Produktion_FFB | B - FL-Str.02_NK-KK-TK
8602983 | EG_Produktion_FFB | B - FL-Str.02_NK-KK-TK
8602992 | EG_Produktion_FFB | B - FL-Str.02_NK-KK-TK
8603011 | EG_Produktion_FFB | A - SL_KK
8603014 | EG_Produktion_FFB | A - SL_KK
8603015 | EG_Produktion_FFB | A - SL_KK
8603016 | EG_Produktion_FFB | A - SL_KK
8603017 | EG_Produktion_FFB | A - SL_KK
8603018 | EG_Produktion_FFB | A - SL_KK
8603022 | EG_Produktion_FFB | A - SL_KK
8603025 | EG_Produktion_FFB | A - SL_KK
8603028 | EG_Produktion_FFB | A - SL_KK
8603029 | EG_Produktion_FFB | A - SL_KK
8603034 | EG_Produktion_FFB | A - SL_KK
8603052 | EG_Produktion_FFB | B - SL_KK
8603055 | EG_Produktion_FFB | B - SL_KK
8603058 | EG_Produktion_FFB | B - SL_KK
8603061 | EG_Produktion_FFB | B - SL_KK
8603067 | EG_Produktion_FFB | B - SL_KK
8603070 | EG_Produktion_FFB | B - SL_KK
8603073 | EG_Produktion_FFB | B - SL_KK
8603076 | EG_Produktion_FFB | B - SL_KK
8603079 | EG_Produktion_FFB | B - SL_KK
8603083 | EG_Produktion_FFB | B - SL_KK
8603088 | EG_Produktion_FFB | B - SL_KK
8603092 | EG_Produktion_FFB | B - SL_KK
8603098 | EG_Produktion_FFB | B - SL_KK
8603101 | EG_Produktion_FFB | B - SL_KK
8603106 | EG_Produktion_FFB | B - SL_KK
8603109 | EG_Produktion_FFB | A - SL_NK-Str.01
8603112 | EG_Produktion_FFB | A - SL_NK-Str.01
8603123 | EG_Produktion_FFB | B - SL_NK-Str.01
8603124 | EG_Produktion_FFB | B - SL_NK-Str.01
8603145 | EG_Produktion_FFB | B - SL_TK
8603150 | EG_Produktion_FFB | A - SL_TK
8603152 | EG_Produktion_FFB | B - SL_TK
8603158 | EG_Produktion_FFB | B - SL_TK
8603164 | EG_Produktion_FFB | B - SL_TK
8603167 | EG_Produktion_FFB | A - SL_TK
8603173 | EG_Produktion_FFB | A - SL_TK
8603182 | EG_Produktion_FFB | B - SL_NK-Str.01
8603185 | EG_Produktion_FFB | A - SL_NK-Str.01
8603188 | EG_Produktion_FFB | A - SL_TK
8603194 | EG_Produktion_FFB | A - SL_TK
8603203 | EG_Produktion_FFB | B - SL_TK
8603209 | EG_Produktion_FFB | B - SL_TK
8603215 | EG_Produktion_FFB | B - SL_TK
8603218 | EG_Produktion_FFB | A - SL_NK-Str.01
8603221 | EG_Produktion_FFB | B - SL_NK-Str.01
8603224 | EG_Produktion_FFB | A - SL_NK-Str.01
8603235 | EG_Produktion_FFB | A - SL_NK-Str.01
8603242 | EG_Produktion_FFB | B - SL_NK-Str.01
8603245 | EG_Produktion_FFB | B - SL_NK-Str.01
8603251 | EG_Produktion_FFB | B - SL_NK-Str.01
8603266 | EG_Produktion_FFB | A - SL_NK-Str.01
8603272 | EG_Produktion_FFB | B - SL_NK-Str.01
8603285 | EG_Produktion_FFB | B - SL_NK-Str.01
8603288 | EG_Produktion_FFB | B - SL_NK-Str.01
8603296 | EG_Produktion_FFB | A - SL_NK-Str.01
8603299 | EG_Produktion_FFB | A - SL_NK-Str.01
8603311 | EG_Produktion_FFB | B - SL_NK-Str.01
8603314 | EG_Produktion_FFB | B - SL_NK-Str.01
8603317 | EG_Produktion_FFB | B - SL_NK-Str.01
8603320 | EG_Produktion_FFB | A - SL_NK-Str.01
8603323 | EG_Produktion_FFB | A - SL_NK-Str.01
8603326 | EG_Produktion_FFB | A - SL_NK-Str.01
8603344 | EG_Produktion_FFB | A - SL_NK-Str.01
8603346 | EG_Produktion_FFB | A - SL_NK-Str.01 | BaseQuantities - GrossCeilingArea: 0.004735 m2
8603356 | EG_Produktion_FFB | B - SL_NK-Str.01
8603358 | EG_Produktion_FFB | B - SL_NK-Str.01 | BaseQuantities - GrossCeilingArea: 0.004735 m2
8603871 | EG_Produktion_FFB | A - FL-Str.02_NK-KK-TK | BaseQuantities - GrossCeilingArea: 0.00255585 m2
8603878 | EG_Produktion_FFB | A - FL-Str.02_NK-KK-TK
8603933 | EG_Produktion_FFB | B - FL-Str.02_NK-KK-TK | BaseQuantities - GrossCeilingArea: 0.00255585 m2
8603940 | EG_Produktion_FFB | B - FL-Str.02_NK-KK-TK
8603961 | EG_Produktion_FFB | B - SL_KK
8603962 | EG_Produktion_FFB | B - SL_KK | BaseQuantities - GrossCeilingArea: 0.00348054 m2
8603972 | EG_Produktion_FFB | B - SL_KK
8603977 | EG_Produktion_FFB | B - SL_KK
8603998 | EG_Produktion_FFB | B - FL-Str.01_NK-KK-TK
8603999 | EG_Produktion_FFB | B - FL-Str.01_NK-KK-TK | BaseQuantities - GrossCeilingArea: 0.00417616 m2
8604009 | EG_Produktion_FFB | B - FL-Str.01_NK-KK-TK
8604014 | EG_Produktion_FFB | B - FL-Str.01_NK-KK-TK
8604035 | EG_Produktion_FFB | A - SL_KK
8604036 | EG_Produktion_FFB | A - SL_KK | BaseQuantities - GrossCeilingArea: 0.00348054 m2
8604046 | EG_Produktion_FFB | A - SL_KK
8604051 | EG_Produktion_FFB | A - SL_KK
8604072 | EG_Produktion_FFB | A - FL-Str.01_NK-KK-TK
8604073 | EG_Produktion_FFB | A - FL-Str.01_NK-KK-TK | BaseQuantities - GrossCeilingArea: 0.00417616 m2
8604083 | EG_Produktion_FFB | A - FL-Str.01_NK-KK-TK
8604088 | EG_Produktion_FFB | A - FL-Str.01_NK-KK-TK
8604272 | EG_Produktion_FFB | A - FL-Str.01_NK-KK-TK
8604273 | EG_Produktion_FFB | A - FL-Str.01_NK-KK-TK
8604299 | EG_Produktion_FFB | A - SL_KK
8604300 | EG_Produktion_FFB | A - SL_KK
8604373 | EG_Produktion_FFB | B - FL-Str.01_NK-KK-TK
8604457 | EG_Produktion_FFB | B - FL-Str.01_NK-KK-TK
8604484 | EG_Produktion_FFB | B - SL_KK
8604551 | EG_Produktion_FFB | A - SL_KK
8604578 | EG_Produktion_FFB | A - FL-Str.01_NK-KK-TK
8604605 | EG_Produktion_FFB | B - SL_KK
8604651 | EG_Produktion_FFB | B - FL-Str.02_NK-KK-TK
8604652 | EG_Produktion_FFB | B - FL-Str.02_NK-KK-TK
8604705 | EG_Produktion_FFB | B - SL_KK
8604752 | EG_Produktion_FFB | A - SL_KK
8604821 | EG_Produktion_FFB | A - FL-Str.01_NK-KK-TK
8604829 | EG_Produktion_FFB | A - FL-Str.01_NK-KK-TK
8604951 | EG_Produktion_FFB | A - SL_NK-Str.01
8604959 | EG_Produktion_FFB | A - SL_NK-Str.01
8605024 | EG_Produktion_FFB | B - FL-Str.01_NK-KK-TK
8605032 | EG_Produktion_FFB | B - FL-Str.01_NK-KK-TK
8605077 | EG_Produktion_FFB | B - SL_NK-Str.01
8605085 | EG_Produktion_FFB | B - SL_NK-Str.01
8605155 | EG_Produktion_FFB | A - FL-Str.02_NK-KK-TK
8605156 | EG_Produktion_FFB | A - FL-Str.02_NK-KK-TK
8605209 | EG_Produktion_FFB | B - SL_KK
8605267 | EG_Produktion_FFB | B - FL-Str.01_NK-KK-TK
8605359 | EG_Produktion_FFB | B - FL-Str.01_NK-KK-TK
8605366 | EG_Produktion_FFB | B - FL-Str.01_NK-KK-TK
8605391 | EG_Produktion_FFB | B - SL_KK
8605398 | EG_Produktion_FFB | B - SL_KK
8605483 | EG_Produktion_FFB | A - FL-Str.01_NK-KK-TK
8605515 | EG_Produktion_FFB | A - SL_KK
8605677 | EG_Produktion_FFB | A - FL-Str.01_NK-KK-TK
8605709 | EG_Produktion_FFB | A - SL_KK
8605840 | EG_Produktion_FFB | B - SL_KK
8605841 | EG_Produktion_FFB | B - SL_KK
8605867 | EG_Produktion_FFB | B - FL-Str.01_NK-KK-TK
8605868 | EG_Produktion_FFB | B - FL-Str.01_NK-KK-TK
8605895 | EG_Produktion_FFB | B - SL_KK
8605921 | EG_Produktion_FFB | B - FL-Str.01_NK-KK-TK
8605922 | EG_Produktion_FFB | B - FL-Str.01_NK-KK-TK
8606009 | EG_Produktion_FFB | A - SL_KK
8606036 | EG_Produktion_FFB | A - FL-Str.01_NK-KK-TK
8606112 | EG_Produktion_FFB | B - FL-Str.01_NK-KK-TK
8606113 | EG_Produktion_FFB | B - FL-Str.01_NK-KK-TK
8606179 | EG_Produktion_FFB | B - SL_KK
8606245 | EG_Produktion_FFB | B - SL_KK
8606246 | EG_Produktion_FFB | B - SL_KK
8606272 | EG_Produktion_FFB | B - FL-Str.01_NK-KK-TK
8606273 | EG_Produktion_FFB | B - FL-Str.01_NK-KK-TK
8606360 | EG_Produktion_FFB | A - FL-Str.01_NK-KK-TK
8606387 | EG_Produktion_FFB | A - SL_KK
8606494 | EG_Produktion_FFB | B - SL_KK
8606521 | EG_Produktion_FFB | B - FL-Str.01_NK-KK-TK
8606548 | EG_Produktion_FFB | A - SL_KK
8606575 | EG_Produktion_FFB | A - FL-Str.01_NK-KK-TK
8606698 | EG_Produktion_FFB | A - SL_KK
8606701 | EG_Produktion_FFB | A - FL-Str.01_NK-KK-TK
8606893 | EG_Produktion_FFB | A - FL-Str.01_NK-KK-TK | BaseQuantities - GrossCeilingArea: 0.0020069 m2
8606914 | EG_Produktion_FFB | A - SL_KK
8606916 | EG_Produktion_FFB | A - SL_KK | BaseQuantities - GrossCeilingArea: 0.0020069 m2
8606944 | EG_Produktion_FFB | A - SL_KK | BaseQuantities - GrossCeilingArea: 0.0045539 m2
8606998 | EG_Produktion_FFB | A - FL-Str.01_NK-KK-TK | BaseQuantities - GrossCeilingArea: 0.00662464 m2
8607192 | EG_Produktion_FFB | A - FL-Str.03_NK-KK-TK | BaseQuantities - GrossCeilingArea: 0.00227929 m2
8607258 | EG_Produktion_FFB | B - FL-Str.03_NK-KK-TK
8607259 | EG_Produktion_FFB | B - FL-Str.03_NK-KK-TK | BaseQuantities - GrossCeilingArea: 0.00227929 m2
8607300 | EG_Produktion_FFB | B - SL_NK-Str.02
8607301 | EG_Produktion_FFB | B - SL_NK-Str.02 | BaseQuantities - GrossCeilingArea: 0.00227929 m2
8607313 | EG_Produktion_FFB | B - SL_NK-Str.02
8607373 | EG_Produktion_FFB | B - FL-Str.03_NK-KK-TK
8607374 | EG_Produktion_FFB | B - FL-Str.03_NK-KK-TK | BaseQuantities - GrossCeilingArea: 0.00227929 m2
8607518 | EG_Produktion_FFB | B - SL_NK-Str.02 | BaseQuantities - GrossCeilingArea: 0.00227929 m2
8607575 | EG_Produktion_FFB | B - FL-Str.03_NK-KK-TK | BaseQuantities - GrossCeilingArea: 0.00227929 m2
8607631 | EG_Produktion_FFB | A - SL_NK-Str.02
8607632 | EG_Produktion_FFB | A - SL_NK-Str.02 | BaseQuantities - GrossCeilingArea: 0.00227929 m2
8607688 | EG_Produktion_FFB | A - FL-Str.03_NK-KK-TK
8607689 | EG_Produktion_FFB | A - FL-Str.03_NK-KK-TK | BaseQuantities - GrossCeilingArea: 0.00227929 m2
8607835 | EG_Produktion_FFB | A - SL_NK-Str.02
8607836 | EG_Produktion_FFB | A - SL_NK-Str.02 | BaseQuantities - GrossCeilingArea: 0.00227929 m2
8607862 | EG_Produktion_FFB | A - FL-Str.03_NK-KK-TK
8607863 | EG_Produktion_FFB | A - FL-Str.03_NK-KK-TK | BaseQuantities - GrossCeilingArea: 0.00227929 m2
8607889 | EG_Produktion_FFB | B - SL_NK-Str.02
8607890 | EG_Produktion_FFB | B - SL_NK-Str.02 | BaseQuantities - GrossCeilingArea: 0.00227929 m2
8607916 | EG_Produktion_FFB | B - FL-Str.03_NK-KK-TK
8607917 | EG_Produktion_FFB | B - FL-Str.03_NK-KK-TK | BaseQuantities - GrossCeilingArea: 0.00227929 m2
8608069 | EG_Produktion_FFB | B - FL-Str.03_NK-KK-TK
8608070 | EG_Produktion_FFB | B - FL-Str.03_NK-KK-TK | BaseQuantities - GrossCeilingArea: 0.00227929 m2
8608096 | EG_Produktion_FFB | B - SL_NK-Str.02
8608097 | EG_Produktion_FFB | B - SL_NK-Str.02 | BaseQuantities - GrossCeilingArea: 0.00227929 m2
8608123 | EG_Produktion_FFB | A - SL_NK-Str.02
8608124 | EG_Produktion_FFB | A - SL_NK-Str.02 | BaseQuantities - GrossCeilingArea: 0.00227929 m2
8608150 | EG_Produktion_FFB | A - FL-Str.03_NK-KK-TK
8608151 | EG_Produktion_FFB | A - FL-Str.03_NK-KK-TK | BaseQuantities - GrossCeilingArea: 0.00227929 m2
8608237 | EG_Produktion_FFB | B - SL_NK-Str.02
8608238 | EG_Produktion_FFB | B - SL_NK-Str.02 | BaseQuantities - GrossCeilingArea: 0.00227929 m2
8608282 | EG_Produktion_FFB | B - FL-Str.03_NK-KK-TK | BaseQuantities - GrossCeilingArea: 0.00227929 m2
8608343 | EG_Produktion_FFB | A - SL_NK-Str.02 | BaseQuantities - GrossCeilingArea: 0.00227929 m2
8608346 | EG_Produktion_FFB | A - SL_NK-Str.02
8608351 | EG_Produktion_FFB | A - SL_NK-Str.02
8608406 | EG_Produktion_FFB | A - SL_NK-Str.02 | BaseQuantities - GrossCeilingArea: 0.00227929 m2
8608414 | EG_Produktion_FFB | A - SL_NK-Str.02
8608472 | EG_Produktion_FFB | A - SL_NK-Str.02 | BaseQuantities - GrossCeilingArea: 0.00284825 m2
8608475 | EG_Produktion_FFB | A - SL_NK-Str.02
8608480 | EG_Produktion_FFB | A - SL_NK-Str.02
8608640 | EG_Produktion_FFB | A - FL-Str.03_NK-KK-TK | BaseQuantities - GrossCeilingArea: 0.00227929 m2
8608667 | EG_Produktion_FFB | A - FL-Str.03_NK-KK-TK | BaseQuantities - GrossCeilingArea: 0.00227929 m2
8608670 | EG_Produktion_FFB | A - FL-Str.03_NK-KK-TK
8608675 | EG_Produktion_FFB | A - FL-Str.03_NK-KK-TK
8608720 | EG_Produktion_FFB | B - FL-Str.03_NK-KK-TK
8608723 | EG_Produktion_FFB | B - SL_NK-Str.02
8608911 | EG_Produktion_FFB | B - FL-Str.03_NK-KK-TK | BaseQuantities - GrossCeilingArea: 0.00227929 m2
8608948 | EG_Produktion_FFB | B - SL_NK-Str.02 | BaseQuantities - GrossCeilingArea: 0.00227929 m2
8609158 | EG_Produktion_FFB | A - SL_NK-Str.01
8609161 | EG_Produktion_FFB | A - SL_NK-Str.01
8609166 | EG_Produktion_FFB | A - SL_NK-Str.01
8609191 | EG_Produktion_FFB | A - FL-Str.02_NK-KK-TK
8609198 | EG_Produktion_FFB | A - FL-Str.02_NK-KK-TK
8609363 | EG_Produktion_FFB | B - SL_TK
8609390 | EG_Produktion_FFB | B - SL_NK-Str.01
8609423 | EG_Produktion_FFB | B - FL-Str.02_NK-KK-TK
8609454 | EG_Produktion_FFB | B - FL-Str.02_NK-KK-TK
8609455 | EG_Produktion_FFB | B - FL-Str.02_NK-KK-TK
8609522 | EG_Produktion_FFB | A - FL-Str.02_NK-KK-TK
8609551 | EG_Produktion_FFB | A - SL_NK-Str.01
8609731 | EG_Produktion_FFB | B - FL-Str.02_NK-KK-TK
8609739 | EG_Produktion_FFB | B - FL-Str.02_NK-KK-TK
8609764 | EG_Produktion_FFB | B - SL_TK | BaseQuantities - GrossCeilingArea: 0.00227929 m2
8609772 | EG_Produktion_FFB | B - SL_TK
8609797 | EG_Produktion_FFB | B - SL_NK-Str.01
8609861 | EG_Produktion_FFB | A - SL_TK
8609862 | EG_Produktion_FFB | A - SL_TK | BaseQuantities - GrossCeilingArea: 0.00227929 m2
8609874 | EG_Produktion_FFB | A - SL_TK
8609939 | EG_Produktion_FFB | A - FL-Str.02_NK-KK-TK
8609947 | EG_Produktion_FFB | A - FL-Str.02_NK-KK-TK
8610032 | EG_Produktion_FFB | A - SL_NK-Str.01
8610059 | EG_Produktion_FFB | A - FL-Str.02_NK-KK-TK
8610107 | EG_Produktion_FFB | B - SL_TK
8610108 | EG_Produktion_FFB | B - SL_TK | BaseQuantities - GrossCeilingArea: 0.00227929 m2
8610120 | EG_Produktion_FFB | B - SL_TK
8610191 | EG_Produktion_FFB | B - FL-Str.02_NK-KK-TK
8610199 | EG_Produktion_FFB | B - FL-Str.02_NK-KK-TK
8610343 | EG_Produktion_FFB | A - SL_NK-Str.01
8610344 | EG_Produktion_FFB | A - SL_NK-Str.01
8610371 | EG_Produktion_FFB | A - FL-Str.02_NK-KK-TK
8610379 | EG_Produktion_FFB | A - FL-Str.02_NK-KK-TK
8610404 | EG_Produktion_FFB | A - SL_TK | BaseQuantities - GrossCeilingArea: 0.00227929 m2
8610412 | EG_Produktion_FFB | A - SL_TK
8610437 | EG_Produktion_FFB | A - FL-Str.02_NK-KK-TK
8610464 | EG_Produktion_FFB | A - SL_NK-Str.01
8610550 | EG_Produktion_FFB | B - FL-Str.02_NK-KK-TK
8610551 | EG_Produktion_FFB | B - FL-Str.02_NK-KK-TK
8610577 | EG_Produktion_FFB | B - SL_NK-Str.01
8610578 | EG_Produktion_FFB | B - SL_NK-Str.01
8610853 | EG_Produktion_FFB | A - SL_NK-Str.01
8610855 | EG_Produktion_FFB | A - SL_NK-Str.01 | BaseQuantities - GrossCeilingArea: 0.00450836 m2
8610897 | EG_Produktion_FFB | A - FL-Str.02_NK-KK-TK
8610899 | EG_Produktion_FFB | A - FL-Str.02_NK-KK-TK | BaseQuantities - GrossCeilingArea: 0.00370189 m2
8610981 | EG_Produktion_FFB | A - FL-Str.02_NK-KK-TK
8610990 | EG_Produktion_FFB | A - SL_NK-Str.01
8610998 | EG_Produktion_FFB | A - FL-Str.02_NK-KK-TK
8611004 | EG_Produktion_FFB | B - FL-Str.02_NK-KK-TK
8611005 | EG_Produktion_FFB | B - FL-Str.02_NK-KK-TK
8611015 | EG_Produktion_FFB | A - SL_NK-Str.01
8611018 | EG_Produktion_FFB | A - SL_NK-Str.01
8611019 | EG_Produktion_FFB | A - SL_NK-Str.01
8611024 | EG_Produktion_FFB | B - SL_NK-Str.01
8611027 | EG_Produktion_FFB | B - SL_NK-Str.01
8611028 | EG_Produktion_FFB | B - SL_NK-Str.01
8611031 | EG_Produktion_FFB | A - SL_NK-Str.01
8611047 | EG_Produktion_FFB | B - SL_NK-Str.01
8611049 | EG_Produktion_FFB | B - SL_NK-Str.01 | BaseQuantities - GrossCeilingArea: 0.0042699 m2
8611053 | EG_Produktion_FFB | A - SL_NK-Str.01
8611055 | EG_Produktion_FFB | A - SL_NK-Str.01 | BaseQuantities - GrossCeilingArea: 0.0042699 m2
8611058 | EG_Produktion_FFB | A - SL_NK-Str.01
8611178 | EG_Produktion_FFB | A - FL-Str.02_NK-KK-TK
8611180 | EG_Produktion_FFB | A - FL-Str.02_NK-KK-TK | BaseQuantities - GrossCeilingArea: 0.00279252 m2
8611186 | EG_Produktion_FFB | A - FL-Str.02_NK-KK-TK | BaseQuantities - GrossCeilingArea: 0.00227929 m2
8611193 | EG_Produktion_FFB | A - FL-Str.02_NK-KK-TK
8611215 | EG_Produktion_FFB | A - SL_NK-Str.01
8611217 | EG_Produktion_FFB | A - SL_NK-Str.01 | BaseQuantities - GrossCeilingArea: 0.00279252 m2
8611223 | EG_Produktion_FFB | A - SL_NK-Str.01 | BaseQuantities - GrossCeilingArea: 0.00227929 m2
8611230 | EG_Produktion_FFB | A - SL_NK-Str.01
8611326 | EG_Produktion_FFB | A - SL_NK-Str.01
8611327 | EG_Produktion_FFB | A - SL_NK-Str.01
8611414 | EG_Produktion_FFB | B - FL-Str.02_NK-KK-TK
8611457 | EG_Produktion_FFB | B - SL_NK-Str.01
8611458 | EG_Produktion_FFB | B - SL_NK-Str.01
8611485 | EG_Produktion_FFB | B - SL_NK-Str.01
8611531 | EG_Produktion_FFB | B - SL_NK-Str.01
8611532 | EG_Produktion_FFB | B - SL_NK-Str.01
8611579 | EG_Produktion_FFB | B - SL_KK
8611580 | EG_Produktion_FFB | B - SL_KK
8611633 | EG_Produktion_FFB | A - SL_KK
8611645 | EG_Produktion_FFB | A - SL_KK
8611690 | EG_Produktion_FFB | A - FL-Str.01_NK-KK-TK
8611757 | EG_Produktion_FFB | B - FL-Str.01_NK-KK-TK
8611824 | EG_Produktion_FFB | A - FL-Str.01_NK-KK-TK
8611870 | EG_Produktion_FFB | A - FL-Str.01_NK-KK-TK
8611871 | EG_Produktion_FFB | A - FL-Str.01_NK-KK-TK
8611883 | EG_Produktion_FFB | A - FL-Str.01_NK-KK-TK
8611937 | EG_Produktion_FFB | B - FL-Str.01_NK-KK-TK
8611938 | EG_Produktion_FFB | B - FL-Str.01_NK-KK-TK
8611985 | EG_Produktion_FFB | B - FL-Str.01_NK-KK-TK
8611997 | EG_Produktion_FFB | B - FL-Str.01_NK-KK-TK
8612150 | EG_Produktion_FFB | B - FL-Str.02_NK-KK-TK | BaseQuantities - GrossCeilingArea: 0.0042699 m2
8612156 | EG_Produktion_FFB | B - FL-Str.02_NK-KK-TK
8612237 | EG_Produktion_FFB | B - FL-Str.02_NK-KK-TK
8612239 | EG_Produktion_FFB | B - FL-Str.02_NK-KK-TK | BaseQuantities - GrossCeilingArea: 0.00262184 m2
8612300 | EG_Produktion_FFB | B - SL_NK-Str.01 | BaseQuantities - GrossCeilingArea: 0.00796711 m2
8612306 | EG_Produktion_FFB | B - SL_NK-Str.01 | BaseQuantities - GrossCeilingArea: 0.00227929 m2
8612436 | EG_Produktion_FFB | A - SL_NK-Str.01 | BaseQuantities - GrossCeilingArea: 0.00536488 m2
8612442 | EG_Produktion_FFB | A - SL_NK-Str.01
8612509 | EG_Produktion_FFB | A - FL-Str.02_NK-KK-TK | BaseQuantities - GrossCeilingArea: 0.00279252 m2
8612515 | EG_Produktion_FFB | A - FL-Str.02_NK-KK-TK
8612683 | EG_Produktion_FFB | A - SL_NK-Str.01
8612685 | EG_Produktion_FFB | A - SL_NK-Str.01 | BaseQuantities - GrossCeilingArea: 0.00262184 m2
8612714 | EG_Produktion_FFB | A - FL-Str.02_NK-KK-TK
8612716 | EG_Produktion_FFB | A - FL-Str.02_NK-KK-TK | BaseQuantities - GrossCeilingArea: 0.00262184 m2
8613126 | EG_Produktion_FFB | B - SL_NK-Str.01
8613191 | EG_Produktion_FFB | B - SL_NK-Str.01
8613193 | EG_Produktion_FFB | B - SL_NK-Str.01 | BaseQuantities - GrossCeilingArea: 0.00279252 m2
8613341 | EG_Produktion_FFB | B - SL_NK-Str.01 | BaseQuantities - GrossCeilingArea: 0.00284825 m2
8613348 | EG_Produktion_FFB | B - SL_NK-Str.01
8613395 | EG_Produktion_FFB | A - SL_NK-Str.01 | BaseQuantities - GrossCeilingArea: 0.00284825 m2
8613402 | EG_Produktion_FFB | A - SL_NK-Str.01
8613482 | EG_Produktion_FFB | B - SL_NK-Str.01
8613694 | EG_Produktion_FFB | B - SL_NK-Str.01
8613696 | EG_Produktion_FFB | B - SL_NK-Str.01 | BaseQuantities - GrossCeilingArea: 0.00347525 m2
8613702 | EG_Produktion_FFB | B - SL_NK-Str.01 | BaseQuantities - GrossCeilingArea: 0.00348054 m2
8613739 | EG_Produktion_FFB | B - FL-Str.02_NK-KK-TK
8613741 | EG_Produktion_FFB | B - FL-Str.02_NK-KK-TK | BaseQuantities - GrossCeilingArea: 0.00279252 m2
8613747 | EG_Produktion_FFB | B - FL-Str.02_NK-KK-TK | BaseQuantities - GrossCeilingArea: 0.00227929 m2
8613859 | EG_Produktion_FFB | B - SL_NK-Str.01
8614008 | EG_Produktion_FFB | B - FL-Str.02_NK-KK-TK | BaseQuantities - GrossCeilingArea: 0.00279252 m2
8614639 | EG_Produktion_FFB | A - FL-Str.02_NK-KK-TK | BaseQuantities - GrossCeilingArea: 0.00284825 m2
8614678 | EG_Produktion_FFB | A - SL_NK-Str.01 | BaseQuantities - GrossCeilingArea: 0.00417616 m2
8614850 | EG_Produktion_FFB | A - FL-Str.02_NK-KK-TK
8614851 | EG_Produktion_FFB | B - FL-Str.02_NK-KK-TK
8614856 | EG_Produktion_FFB | A - SL_NK-Str.01
8614857 | EG_Produktion_FFB | B - SL_NK-Str.01
8614889 | EG_Produktion_FFB | B - FL-Str.02_NK-KK-TK
8614890 | EG_Produktion_FFB | B - FL-Str.02_NK-KK-TK | BaseQuantities - GrossCeilingArea: 0.00284825 m2
8614902 | EG_Produktion_FFB | B - FL-Str.02_NK-KK-TK
8614935 | EG_Produktion_FFB | B - SL_NK-Str.01 | BaseQuantities - GrossCeilingArea: 0.00417616 m2
8614947 | EG_Produktion_FFB | B - SL_NK-Str.01
8614983 | EG_Produktion_FFB | A - SL_NK-Str.01 | BaseQuantities - GrossCeilingArea: 0.00417616 m2
8614995 | EG_Produktion_FFB | A - SL_NK-Str.01
8615031 | EG_Produktion_FFB | A - FL-Str.02_NK-KK-TK | BaseQuantities - GrossCeilingArea: 0.00284825 m2
8615043 | EG_Produktion_FFB | A - FL-Str.02_NK-KK-TK
8615070 | EG_Produktion_FFB | A - SL_NK-Str.01
8615075 | EG_Produktion_FFB | A - SL_NK-Str.01
8615098 | EG_Produktion_FFB | A - FL-Str.02_NK-KK-TK
8615103 | EG_Produktion_FFB | A - FL-Str.02_NK-KK-TK
8615110 | EG_Produktion_FFB | B - SL_NK-Str.01
8615115 | EG_Produktion_FFB | B - SL_NK-Str.01
8615118 | EG_Produktion_FFB | B - FL-Str.02_NK-KK-TK
8615451 | EG_Produktion_FFB | A - SL_TK
8615577 | EG_Produktion_FFB | A - SL_TK | BaseQuantities - GrossCeilingArea: 0.00599476 m2
8615583 | EG_Produktion_FFB | A - SL_TK
8615623 | EG_Produktion_FFB | A - SL_TK
8616145 | EG_Produktion_FFB | A - FL-Str.02_NK-KK-TK
8616179 | EG_Produktion_FFB | A - SL_KK
8616211 | EG_Produktion_FFB | A - SL_KK
8616643 | EG_Produktion_FFB | B - SL_KK
8616709 | EG_Produktion_FFB | B - FL-Str.01_NK-KK-TK
8616829 | EG_Produktion_FFB | B - SL_KK
8616832 | EG_Produktion_FFB | B - FL-Str.01_NK-KK-TK
8616853 | EG_Produktion_FFB | B - SL_KK
8617133 | EG_Produktion_FFB | B - FL-Str.01_NK-KK-TK
8617136 | EG_Produktion_FFB | B - SL_KK
8617443 | EG_Produktion_FFB | B - SL_KK
8617468 | EG_Produktion_FFB | B - FL-Str.01_NK-KK-TK
8617703 | EG_Produktion_FFB | A - FL-Str.01_NK-KK-TK
8617706 | EG_Produktion_FFB | A - SL_KK
8617831 | EG_Produktion_FFB | A - SL_KK
8617839 | EG_Produktion_FFB | A - FL-Str.01_NK-KK-TK
8617868 | EG_Produktion_FFB | A - FL-Str.01_NK-KK-TK
8617870 | EG_Produktion_FFB | A - FL-Str.01_NK-KK-TK | BaseQuantities - GrossCeilingArea: 0.00214664 m2
8617876 | EG_Produktion_FFB | A - FL-Str.01_NK-KK-TK
8617879 | EG_Produktion_FFB | A - FL-Str.01_NK-KK-TK
8617884 | EG_Produktion_FFB | A - FL-Str.01_NK-KK-TK
8617904 | EG_Produktion_FFB | A - SL_KK
8617906 | EG_Produktion_FFB | A - SL_KK | BaseQuantities - GrossCeilingArea: 0.00214664 m2
8617912 | EG_Produktion_FFB | A - SL_KK
8617915 | EG_Produktion_FFB | A - SL_KK
8617920 | EG_Produktion_FFB | A - SL_KK
8618022 | EG_Produktion_FFB | A - FL-Str.01_NK-KK-TK
8618024 | EG_Produktion_FFB | A - FL-Str.01_NK-KK-TK | BaseQuantities - GrossCeilingArea: 0.00214664 m2
8618030 | EG_Produktion_FFB | A - FL-Str.01_NK-KK-TK
8618033 | EG_Produktion_FFB | A - FL-Str.01_NK-KK-TK
8618038 | EG_Produktion_FFB | A - FL-Str.01_NK-KK-TK
8618069 | EG_Produktion_FFB | A - SL_NK-Str.01
8618071 | EG_Produktion_FFB | A - SL_NK-Str.01 | BaseQuantities - GrossCeilingArea: 0.00214664 m2
8618077 | EG_Produktion_FFB | A - SL_NK-Str.01
8618080 | EG_Produktion_FFB | A - SL_NK-Str.01
8618085 | EG_Produktion_FFB | A - SL_NK-Str.01
8618203 | EG_Produktion_FFB | B - SL_NK-Str.01
8618205 | EG_Produktion_FFB | B - SL_NK-Str.01 | BaseQuantities - GrossCeilingArea: 0.00214664 m2
8618211 | EG_Produktion_FFB | B - SL_NK-Str.01
8618214 | EG_Produktion_FFB | B - SL_NK-Str.01
8618219 | EG_Produktion_FFB | B - SL_NK-Str.01
8618247 | EG_Produktion_FFB | B - FL-Str.01_NK-KK-TK
8618249 | EG_Produktion_FFB | B - FL-Str.01_NK-KK-TK | BaseQuantities - GrossCeilingArea: 0.00214664 m2
8618255 | EG_Produktion_FFB | B - FL-Str.01_NK-KK-TK
8618258 | EG_Produktion_FFB | B - FL-Str.01_NK-KK-TK
8618263 | EG_Produktion_FFB | B - FL-Str.01_NK-KK-TK
8618364 | EG_Produktion_FFB | A - FL-Str.02_NK-KK-TK
8618602 | EG_Produktion_FFB | B - SL_KK
8618622 | EG_Produktion_FFB | B - FL-Str.01_NK-KK-TK
8618680 | EG_Produktion_FFB | B - FL-Str.01_NK-KK-TK
8618683 | EG_Produktion_FFB | B - SL_KK
8618692 | EG_Produktion_FFB | B - FL-Str.01_NK-KK-TK
8618698 | EG_Produktion_FFB | B - FL-Str.01_NK-KK-TK
8618703 | EG_Produktion_FFB | B - FL-Str.01_NK-KK-TK
8618711 | EG_Produktion_FFB | B - SL_KK
8618714 | EG_Produktion_FFB | B - SL_KK
8618717 | EG_Produktion_FFB | B - SL_KK
8618790 | EG_Produktion_FFB | B - SL_KK
8618793 | EG_Produktion_FFB | B - FL-Str.01_NK-KK-TK
8618806 | EG_Produktion_FFB | B - SL_KK
8618809 | EG_Produktion_FFB | B - FL-Str.01_NK-KK-TK
8619066 | EG_Produktion_FFB | B - FL-Str.01_NK-KK-TK
8619067 | EG_Produktion_FFB | B - FL-Str.01_NK-KK-TK
8619072 | EG_Produktion_FFB | B - FL-Str.01_NK-KK-TK
8619096 | EG_Produktion_FFB | B - SL_KK
8619097 | EG_Produktion_FFB | B - SL_KK
8619102 | EG_Produktion_FFB | B - SL_KK
8619119 | EG_Produktion_FFB | A - FL-Str.01_NK-KK-TK
8619122 | EG_Produktion_FFB | A - SL_KK
8619138 | EG_Produktion_FFB | B - FL-Str.01_NK-KK-TK
8619141 | EG_Produktion_FFB | B - SL_KK
8619155 | EG_Produktion_FFB | A - FL-Str.01_NK-KK-TK
8619158 | EG_Produktion_FFB | A - SL_KK
8619172 | EG_Produktion_FFB | B - FL-Str.01_NK-KK-TK
8619175 | EG_Produktion_FFB | B - SL_KK
8619277 | EG_Produktion_FFB | A - FL-Str.01_NK-KK-TK
8619278 | EG_Produktion_FFB | A - FL-Str.01_NK-KK-TK
8619288 | EG_Produktion_FFB | A - FL-Str.01_NK-KK-TK
8619293 | EG_Produktion_FFB | A - FL-Str.01_NK-KK-TK
8619315 | EG_Produktion_FFB | A - SL_KK
8619316 | EG_Produktion_FFB | A - SL_KK
8619326 | EG_Produktion_FFB | A - SL_KK
8619331 | EG_Produktion_FFB | A - SL_KK
8619383 | EG_Produktion_FFB | B - FL-Str.01_NK-KK-TK
8619384 | EG_Produktion_FFB | B - FL-Str.01_NK-KK-TK
8619394 | EG_Produktion_FFB | B - FL-Str.01_NK-KK-TK
8619399 | EG_Produktion_FFB | B - FL-Str.01_NK-KK-TK
8619420 | EG_Produktion_FFB | B - SL_KK
8619421 | EG_Produktion_FFB | B - SL_KK
8619431 | EG_Produktion_FFB | B - SL_KK
8619436 | EG_Produktion_FFB | B - SL_KK
8619454 | EG_Produktion_FFB | A - FL-Str.01_NK-KK-TK
8619457 | EG_Produktion_FFB | A - SL_KK
8619523 | EG_Produktion_FFB | A - FL-Str.01_NK-KK-TK
8619524 | EG_Produktion_FFB | A - FL-Str.01_NK-KK-TK
8619529 | EG_Produktion_FFB | A - FL-Str.01_NK-KK-TK
8619553 | EG_Produktion_FFB | A - SL_KK
8619554 | EG_Produktion_FFB | A - SL_KK
8619559 | EG_Produktion_FFB | A - SL_KK
8619663 | EG_Produktion_FFB | B - FL-Str.01_NK-KK-TK
8619664 | EG_Produktion_FFB | B - FL-Str.01_NK-KK-TK
8619669 | EG_Produktion_FFB | B - FL-Str.01_NK-KK-TK
8619713 | EG_Produktion_FFB | B - SL_KK
8619714 | EG_Produktion_FFB | B - SL_KK
8619719 | EG_Produktion_FFB | B - SL_KK
8619773 | EG_Produktion_FFB | A - FL-Str.01_NK-KK-TK
8619774 | EG_Produktion_FFB | A - FL-Str.01_NK-KK-TK
8619784 | EG_Produktion_FFB | A - FL-Str.01_NK-KK-TK
8619789 | EG_Produktion_FFB | A - FL-Str.01_NK-KK-TK
8619811 | EG_Produktion_FFB | A - SL_KK
8619812 | EG_Produktion_FFB | A - SL_KK
8619822 | EG_Produktion_FFB | A - SL_KK
8619827 | EG_Produktion_FFB | A - SL_KK
8619892 | EG_Produktion_FFB | B - SL_KK
8619893 | EG_Produktion_FFB | B - SL_KK
8619898 | EG_Produktion_FFB | B - SL_KK
8619923 | EG_Produktion_FFB | B - FL-Str.01_NK-KK-TK
8619924 | EG_Produktion_FFB | B - FL-Str.01_NK-KK-TK
8619929 | EG_Produktion_FFB | B - FL-Str.01_NK-KK-TK
8619949 | EG_Produktion_FFB | B - SL_KK
8619952 | EG_Produktion_FFB | B - FL-Str.01_NK-KK-TK
8619970 | EG_Produktion_FFB | A - SL_KK
8619973 | EG_Produktion_FFB | A - FL-Str.01_NK-KK-TK
8619995 | EG_Produktion_FFB | B - SL_KK
8619998 | EG_Produktion_FFB | B - FL-Str.01_NK-KK-TK
8620090 | EG_Produktion_FFB | B - SL_KK
8620091 | EG_Produktion_FFB | B - SL_KK
8620101 | EG_Produktion_FFB | B - SL_KK
8620106 | EG_Produktion_FFB | B - SL_KK
8620143 | EG_Produktion_FFB | B - FL-Str.01_NK-KK-TK
8620144 | EG_Produktion_FFB | B - FL-Str.01_NK-KK-TK
8620154 | EG_Produktion_FFB | B - FL-Str.01_NK-KK-TK
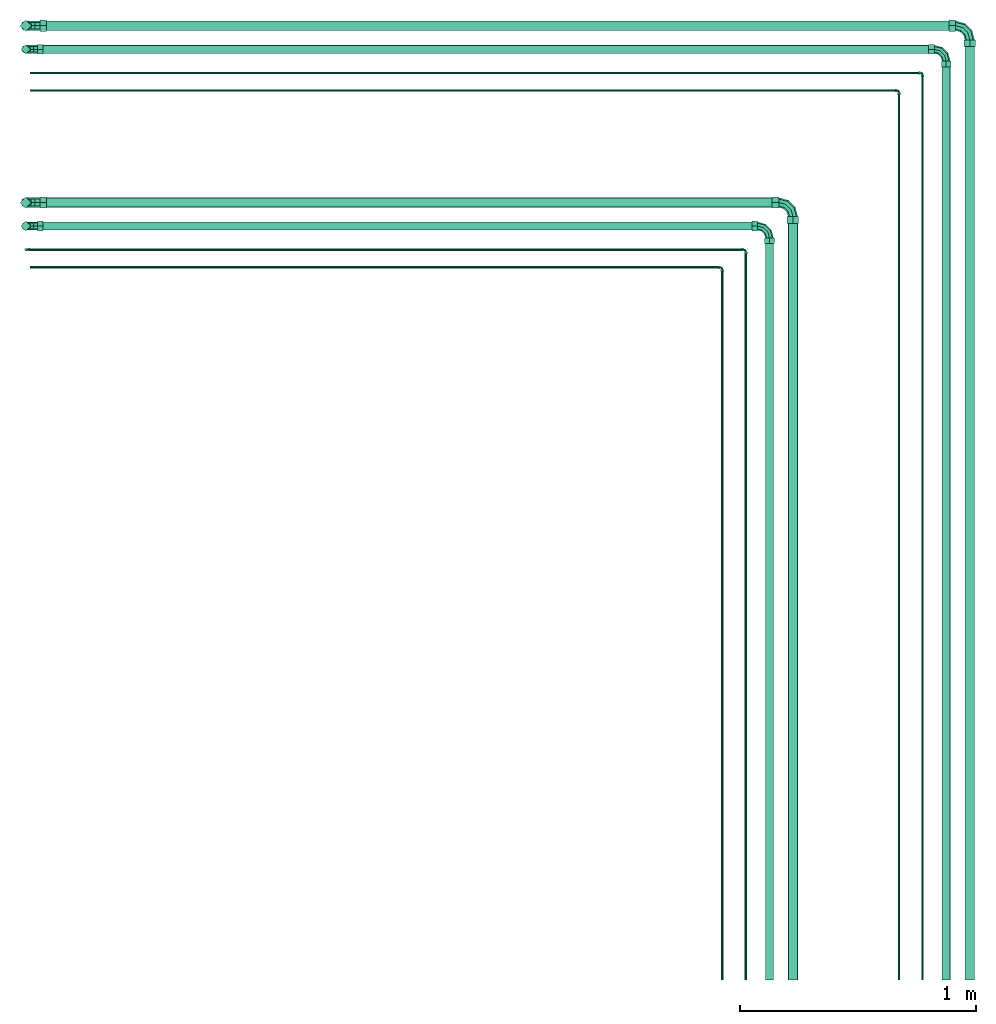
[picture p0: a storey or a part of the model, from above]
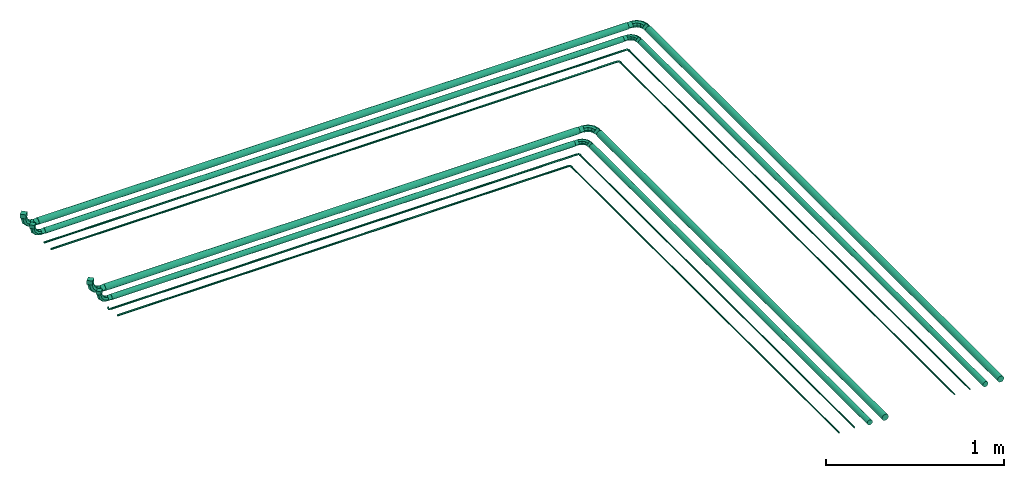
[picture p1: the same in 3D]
Properties of the parts of a building model (IFC2X3), part 2 of 7

# IfcCovering: Rohrdämmung außen:Armaflex-Schlauch (1548)
Name (Rohrdämmung außen:Armaflex-Schlauch:...) | In | Systemname
8620159 | EG_Produktion_FFB | B - FL-Str.01_NK-KK-TK
8620228 | EG_Produktion_FFB | A - SL_KK
8620229 | EG_Produktion_FFB | A - SL_KK
8620239 | EG_Produktion_FFB | A - SL_KK
8620244 | EG_Produktion_FFB | A - SL_KK
8620266 | EG_Produktion_FFB | A - FL-Str.01_NK-KK-TK
8620267 | EG_Produktion_FFB | A - FL-Str.01_NK-KK-TK
8620277 | EG_Produktion_FFB | A - FL-Str.01_NK-KK-TK
8620282 | EG_Produktion_FFB | A - FL-Str.01_NK-KK-TK
8620367 | EG_Produktion_FFB | B - FL-Str.01_NK-KK-TK
8620368 | EG_Produktion_FFB | B - FL-Str.01_NK-KK-TK
8620376 | EG_Produktion_FFB | B - FL-Str.01_NK-KK-TK
8620381 | EG_Produktion_FFB | B - FL-Str.01_NK-KK-TK
8620403 | EG_Produktion_FFB | B - SL_KK
8620404 | EG_Produktion_FFB | B - SL_KK
8620412 | EG_Produktion_FFB | B - SL_KK
8620417 | EG_Produktion_FFB | B - SL_KK
8620451 | EG_Produktion_FFB | A - FL-Str.01_NK-KK-TK
8620512 | EG_Produktion_FFB | A - SL_KK
8620522 | EG_Produktion_FFB | A - SL_KK
8620527 | EG_Produktion_FFB | A - SL_KK
8620550 | EG_Produktion_FFB | A - FL-Str.01_NK-KK-TK
8620551 | EG_Produktion_FFB | A - FL-Str.01_NK-KK-TK
8620561 | EG_Produktion_FFB | A - FL-Str.01_NK-KK-TK
8620566 | EG_Produktion_FFB | A - FL-Str.01_NK-KK-TK
8620639 | EG_Produktion_FFB | A - SL_KK
8620642 | EG_Produktion_FFB | A - FL-Str.01_NK-KK-TK
8620708 | EG_Produktion_FFB | A - SL_KK
8620709 | EG_Produktion_FFB | A - SL_KK
8620721 | EG_Produktion_FFB | A - SL_KK
8620744 | EG_Produktion_FFB | A - FL-Str.01_NK-KK-TK
8620745 | EG_Produktion_FFB | A - FL-Str.01_NK-KK-TK
8620757 | EG_Produktion_FFB | A - FL-Str.01_NK-KK-TK
8620777 | EG_Produktion_FFB | A - FL-Str.01_NK-KK-TK
8620780 | EG_Produktion_FFB | A - SL_KK
8620797 | EG_Produktion_FFB | B - FL-Str.01_NK-KK-TK
8620902 | EG_Produktion_FFB | A - FL-Str.01_NK-KK-TK
8620903 | EG_Produktion_FFB | A - FL-Str.01_NK-KK-TK
8620915 | EG_Produktion_FFB | A - FL-Str.01_NK-KK-TK
8620937 | EG_Produktion_FFB | A - SL_KK
8620938 | EG_Produktion_FFB | A - SL_KK
8620950 | EG_Produktion_FFB | A - SL_KK
8621005 | EG_Produktion_FFB | B - SL_KK
8621008 | EG_Produktion_FFB | B - FL-Str.01_NK-KK-TK
8621059 | EG_Produktion_FFB | B - SL_KK
8621127 | EG_Produktion_FFB | B - SL_KK
8621147 | EG_Produktion_FFB | B - SL_KK
8621148 | EG_Produktion_FFB | B - SL_KK
8621156 | EG_Produktion_FFB | B - SL_KK
8621161 | EG_Produktion_FFB | B - SL_KK
8621185 | EG_Produktion_FFB | B - FL-Str.01_NK-KK-TK
8621186 | EG_Produktion_FFB | B - FL-Str.01_NK-KK-TK
8621194 | EG_Produktion_FFB | B - FL-Str.01_NK-KK-TK
8621199 | EG_Produktion_FFB | B - FL-Str.01_NK-KK-TK
8621266 | EG_Produktion_FFB | A - SL_NK-Str.02
8621269 | EG_Produktion_FFB | A - FL-Str.03_NK-KK-TK
8621303 | EG_Produktion_FFB | A - SL_NK-Str.02
8621306 | EG_Produktion_FFB | A - FL-Str.03_NK-KK-TK
8621322 | EG_Produktion_FFB | A - SL_NK-Str.02
8621325 | EG_Produktion_FFB | A - FL-Str.03_NK-KK-TK
8621343 | EG_Produktion_FFB | A - FL-Str.03_NK-KK-TK
8621346 | EG_Produktion_FFB | A - SL_NK-Str.02
8621360 | EG_Produktion_FFB | A - SL_NK-Str.01
8621363 | EG_Produktion_FFB | A - FL-Str.03_NK-KK-TK
8621379 | EG_Produktion_FFB | A - SL_NK-Str.01
8621382 | EG_Produktion_FFB | A - FL-Str.03_NK-KK-TK
8621396 | EG_Produktion_FFB | B - FL-Str.03_NK-KK-TK
8621399 | EG_Produktion_FFB | B - SL_NK-Str.01
8621413 | EG_Produktion_FFB | B - FL-Str.03_NK-KK-TK
8621416 | EG_Produktion_FFB | B - SL_NK-Str.01
8621434 | EG_Produktion_FFB | B - FL-Str.03_NK-KK-TK
8621437 | EG_Produktion_FFB | B - SL_NK-Str.02
8621453 | EG_Produktion_FFB | B - SL_NK-Str.02
8621456 | EG_Produktion_FFB | B - FL-Str.03_NK-KK-TK
8621474 | EG_Produktion_FFB | B - FL-Str.03_NK-KK-TK
8621477 | EG_Produktion_FFB | B - SL_NK-Str.02
8621491 | EG_Produktion_FFB | B - FL-Str.03_NK-KK-TK
8621494 | EG_Produktion_FFB | B - SL_NK-Str.02
8621508 | EG_Produktion_FFB | B - FL-Str.03_NK-KK-TK
8621511 | EG_Produktion_FFB | B - SL_NK-Str.02
8621614 | EG_Produktion_FFB | B - SL_NK-Str.02
8621616 | EG_Produktion_FFB | B - SL_NK-Str.02 | BaseQuantities - GrossCeilingArea: 0.00227929 m2
8621691 | EG_Produktion_FFB | B - FL-Str.03_NK-KK-TK | BaseQuantities - GrossCeilingArea: 0.00227929 m2
8621701 | EG_Produktion_FFB | B - FL-Str.03_NK-KK-TK
8621706 | EG_Produktion_FFB | B - FL-Str.03_NK-KK-TK
8621797 | EG_Produktion_FFB | B - FL-Str.03_NK-KK-TK
8621799 | EG_Produktion_FFB | B - FL-Str.03_NK-KK-TK | BaseQuantities - GrossCeilingArea: 0.00227929 m2
8621843 | EG_Produktion_FFB | B - SL_NK-Str.02
8621845 | EG_Produktion_FFB | B - SL_NK-Str.02 | BaseQuantities - GrossCeilingArea: 0.00227929 m2
8621938 | EG_Produktion_FFB | B - FL-Str.03_NK-KK-TK
8621940 | EG_Produktion_FFB | B - FL-Str.03_NK-KK-TK | BaseQuantities - GrossCeilingArea: 0.00227929 m2
8621945 | EG_Produktion_FFB | B - FL-Str.03_NK-KK-TK
8621984 | EG_Produktion_FFB | B - SL_NK-Str.02
8621986 | EG_Produktion_FFB | B - SL_NK-Str.02 | BaseQuantities - GrossCeilingArea: 0.00227929 m2
8621991 | EG_Produktion_FFB | B - SL_NK-Str.02
8622044 | EG_Produktion_FFB | B - SL_NK-Str.02
8622047 | EG_Produktion_FFB | B - FL-Str.03_NK-KK-TK
8622283 | EG_Produktion_FFB | B - FL-Str.03_NK-KK-TK
8622284 | EG_Produktion_FFB | B - FL-Str.03_NK-KK-TK | BaseQuantities - GrossCeilingArea: 0.00227929 m2
8622289 | EG_Produktion_FFB | B - FL-Str.03_NK-KK-TK
8622327 | EG_Produktion_FFB | B - SL_NK-Str.02
8622328 | EG_Produktion_FFB | B - SL_NK-Str.02 | BaseQuantities - GrossCeilingArea: 0.00227929 m2
8622333 | EG_Produktion_FFB | B - SL_NK-Str.02
8622346 | EG_Produktion_FFB | B - SL_NK-Str.02
8622351 | EG_Produktion_FFB | B - SL_NK-Str.02
8622354 | EG_Produktion_FFB | B - FL-Str.03_NK-KK-TK
8622359 | EG_Produktion_FFB | B - FL-Str.03_NK-KK-TK
8622383 | EG_Produktion_FFB | B - FL-Str.03_NK-KK-TK | BaseQuantities - GrossCeilingArea: 0.0026581 m2
8622386 | EG_Produktion_FFB | B - FL-Str.03_NK-KK-TK
8622389 | EG_Produktion_FFB | B - SL_NK-Str.02 | BaseQuantities - GrossCeilingArea: 0.0026581 m2
8622392 | EG_Produktion_FFB | B - SL_NK-Str.02
8622429 | EG_Produktion_FFB | B - SL_NK-Str.02
8622449 | EG_Produktion_FFB | B - FL-Str.03_NK-KK-TK
8622483 | EG_Produktion_FFB | B - SL_NK-Str.02
8622511 | EG_Produktion_FFB | B - FL-Str.03_NK-KK-TK
8622599 | EG_Produktion_FFB | A - FL-Str.03_NK-KK-TK
8622600 | EG_Produktion_FFB | A - FL-Str.03_NK-KK-TK | BaseQuantities - GrossCeilingArea: 0.00227929 m2
8622605 | EG_Produktion_FFB | A - FL-Str.03_NK-KK-TK
8622638 | EG_Produktion_FFB | A - SL_NK-Str.02
8622639 | EG_Produktion_FFB | A - SL_NK-Str.02 | BaseQuantities - GrossCeilingArea: 0.00227929 m2
8622644 | EG_Produktion_FFB | A - SL_NK-Str.02
8622731 | EG_Produktion_FFB | A - FL-Str.03_NK-KK-TK
8622732 | EG_Produktion_FFB | A - FL-Str.03_NK-KK-TK | BaseQuantities - GrossCeilingArea: 0.00227929 m2
8622737 | EG_Produktion_FFB | A - FL-Str.03_NK-KK-TK
8622770 | EG_Produktion_FFB | A - SL_NK-Str.02
8622771 | EG_Produktion_FFB | A - SL_NK-Str.02 | BaseQuantities - GrossCeilingArea: 0.00227929 m2
8622863 | EG_Produktion_FFB | A - SL_NK-Str.02
8622864 | EG_Produktion_FFB | A - SL_NK-Str.02 | BaseQuantities - GrossCeilingArea: 0.00227929 m2
8622869 | EG_Produktion_FFB | A - SL_NK-Str.02
8622902 | EG_Produktion_FFB | A - FL-Str.03_NK-KK-TK
8622903 | EG_Produktion_FFB | A - FL-Str.03_NK-KK-TK | BaseQuantities - GrossCeilingArea: 0.00227929 m2
8622908 | EG_Produktion_FFB | A - FL-Str.03_NK-KK-TK
8623220 | EG_Produktion_FFB | A - FL-Str.03_NK-KK-TK
8623221 | EG_Produktion_FFB | A - FL-Str.03_NK-KK-TK | BaseQuantities - GrossCeilingArea: 0.00227929 m2
8623231 | EG_Produktion_FFB | A - FL-Str.03_NK-KK-TK
8623236 | EG_Produktion_FFB | A - FL-Str.03_NK-KK-TK
8623293 | EG_Produktion_FFB | A - SL_NK-Str.01
8623294 | EG_Produktion_FFB | A - SL_NK-Str.01 | BaseQuantities - GrossCeilingArea: 0.00227929 m2
8623299 | EG_Produktion_FFB | A - SL_NK-Str.01
8623387 | EG_Produktion_FFB | A - FL-Str.03_NK-KK-TK
8623388 | EG_Produktion_FFB | A - FL-Str.03_NK-KK-TK | BaseQuantities - GrossCeilingArea: 0.00227929 m2
8623393 | EG_Produktion_FFB | A - FL-Str.03_NK-KK-TK
8623427 | EG_Produktion_FFB | A - SL_NK-Str.01 | BaseQuantities - GrossCeilingArea: 0.00227929 m2
8623432 | EG_Produktion_FFB | A - SL_NK-Str.01
8623540 | EG_Produktion_FFB | B - FL-Str.03_NK-KK-TK
8623543 | EG_Produktion_FFB | B - SL_NK-Str.01
8623605 | EG_Produktion_FFB | B - FL-Str.03_NK-KK-TK
8623656 | EG_Produktion_FFB | B - FL-Str.03_NK-KK-TK
8623657 | EG_Produktion_FFB | B - FL-Str.03_NK-KK-TK | BaseQuantities - GrossCeilingArea: 0.00227929 m2
8623665 | EG_Produktion_FFB | B - FL-Str.03_NK-KK-TK
8623670 | EG_Produktion_FFB | B - FL-Str.03_NK-KK-TK
8623702 | EG_Produktion_FFB | B - SL_NK-Str.01
8623703 | EG_Produktion_FFB | B - SL_NK-Str.01 | BaseQuantities - GrossCeilingArea: 0.00227929 m2
8623716 | EG_Produktion_FFB | B - SL_NK-Str.01
8623859 | EG_Produktion_FFB | B - SL_NK-Str.01
8623860 | EG_Produktion_FFB | B - SL_NK-Str.01 | BaseQuantities - GrossCeilingArea: 0.00227929 m2
8623865 | EG_Produktion_FFB | B - SL_NK-Str.01
8623897 | EG_Produktion_FFB | B - FL-Str.03_NK-KK-TK
8623898 | EG_Produktion_FFB | B - FL-Str.03_NK-KK-TK | BaseQuantities - GrossCeilingArea: 0.00227929 m2
8623903 | EG_Produktion_FFB | B - FL-Str.03_NK-KK-TK
8623989 | EG_Produktion_FFB | B - SL_NK-Str.02
8623990 | EG_Produktion_FFB | B - SL_NK-Str.02 | BaseQuantities - GrossCeilingArea: 0.00227929 m2
8623995 | EG_Produktion_FFB | B - SL_NK-Str.02
8624027 | EG_Produktion_FFB | B - FL-Str.03_NK-KK-TK
8624028 | EG_Produktion_FFB | B - FL-Str.03_NK-KK-TK | BaseQuantities - GrossCeilingArea: 0.00227929 m2
8624033 | EG_Produktion_FFB | B - FL-Str.03_NK-KK-TK
8624141 | EG_Produktion_FFB | A - SL_NK-Str.01 | BaseQuantities - GrossCeilingArea: 0.00227929 m2
8624146 | EG_Produktion_FFB | A - SL_NK-Str.01
8624151 | EG_Produktion_FFB | A - SL_NK-Str.01
8624273 | EG_Produktion_FFB | B - SL_NK-Str.01 | BaseQuantities - GrossCeilingArea: 0.00227929 m2
8624276 | EG_Produktion_FFB | B - SL_NK-Str.01
8624281 | EG_Produktion_FFB | B - SL_NK-Str.01
8624373 | EG_Produktion_FFB | B - SL_NK-Str.01
8624374 | EG_Produktion_FFB | B - SL_NK-Str.01 | BaseQuantities - GrossCeilingArea: 0.00227929 m2
8624386 | EG_Produktion_FFB | B - SL_NK-Str.01
8624487 | EG_Produktion_FFB | B - SL_NK-Str.02
8624488 | EG_Produktion_FFB | B - FL-Str.02_NK-KK-TK
8624656 | EG_Produktion_FFB | B - SL_NK-Str.02
8624657 | EG_Produktion_FFB | B - FL-Str.02_NK-KK-TK
8624675 | EG_Produktion_FFB | B - FL-Str.03_NK-KK-TK
8624676 | EG_Produktion_FFB | B - SL_NK-Str.02
8624692 | EG_Produktion_FFB | A - FL-Str.03_NK-KK-TK
8624693 | EG_Produktion_FFB | A - SL_NK-Str.02
8624709 | EG_Produktion_FFB | A - FL-Str.03_NK-KK-TK
8624710 | EG_Produktion_FFB | A - SL_NK-Str.02
8624828 | EG_Produktion_FFB | A - SL_NK-Str.02
8624829 | EG_Produktion_FFB | A - SL_NK-Str.02 | BaseQuantities - GrossCeilingArea: 0.00227929 m2
8624834 | EG_Produktion_FFB | A - SL_NK-Str.02
8624869 | EG_Produktion_FFB | A - FL-Str.03_NK-KK-TK
8624870 | EG_Produktion_FFB | A - FL-Str.03_NK-KK-TK | BaseQuantities - GrossCeilingArea: 0.00227929 m2
8624875 | EG_Produktion_FFB | A - FL-Str.03_NK-KK-TK
8624958 | EG_Produktion_FFB | A - FL-Str.03_NK-KK-TK
8624959 | EG_Produktion_FFB | A - FL-Str.03_NK-KK-TK | BaseQuantities - GrossCeilingArea: 0.00227929 m2
8624969 | EG_Produktion_FFB | A - FL-Str.03_NK-KK-TK
8624974 | EG_Produktion_FFB | A - FL-Str.03_NK-KK-TK
8625014 | EG_Produktion_FFB | A - SL_NK-Str.02
8625015 | EG_Produktion_FFB | A - SL_NK-Str.02 | BaseQuantities - GrossCeilingArea: 0.00227929 m2
8625023 | EG_Produktion_FFB | A - SL_NK-Str.02
8625028 | EG_Produktion_FFB | A - SL_NK-Str.02
8625082 | EG_Produktion_FFB | B - SL_NK-Str.02
8625083 | EG_Produktion_FFB | B - SL_NK-Str.02 | BaseQuantities - GrossCeilingArea: 0.00227929 m2
8625093 | EG_Produktion_FFB | B - SL_NK-Str.02
8625098 | EG_Produktion_FFB | B - SL_NK-Str.02
8625140 | EG_Produktion_FFB | B - FL-Str.03_NK-KK-TK
8625141 | EG_Produktion_FFB | B - FL-Str.03_NK-KK-TK | BaseQuantities - GrossCeilingArea: 0.00227929 m2
8625151 | EG_Produktion_FFB | B - FL-Str.03_NK-KK-TK
8625156 | EG_Produktion_FFB | B - FL-Str.03_NK-KK-TK
8625255 | EG_Produktion_FFB | B - FL-Str.02_NK-KK-TK
8625256 | EG_Produktion_FFB | B - FL-Str.02_NK-KK-TK | BaseQuantities - GrossCeilingArea: 0.00227929 m2
8625261 | EG_Produktion_FFB | B - FL-Str.02_NK-KK-TK
8625295 | EG_Produktion_FFB | B - SL_NK-Str.02
8625296 | EG_Produktion_FFB | B - SL_NK-Str.02 | BaseQuantities - GrossCeilingArea: 0.00227929 m2
8625308 | EG_Produktion_FFB | B - SL_NK-Str.02
8625399 | EG_Produktion_FFB | B - SL_NK-Str.02
8625400 | EG_Produktion_FFB | B - SL_NK-Str.02 | BaseQuantities - GrossCeilingArea: 0.00227929 m2
8625405 | EG_Produktion_FFB | B - SL_NK-Str.02
8625439 | EG_Produktion_FFB | B - FL-Str.02_NK-KK-TK
8625440 | EG_Produktion_FFB | B - FL-Str.02_NK-KK-TK | BaseQuantities - GrossCeilingArea: 0.00227929 m2
8625445 | EG_Produktion_FFB | B - FL-Str.02_NK-KK-TK
8625876 | EG_Produktion_FFB | B - SL_NK-Str.02 | BaseQuantities - GrossCeilingArea: 0.00284825 m2
8625883 | EG_Produktion_FFB | B - SL_NK-Str.02
8625980 | EG_Produktion_FFB | A - FL-Str.02_NK-KK-TK
8625981 | EG_Produktion_FFB | A - SL_NK-Str.02
8626139 | EG_Produktion_FFB | A - FL-Str.02_NK-KK-TK
8626140 | EG_Produktion_FFB | A - FL-Str.02_NK-KK-TK | BaseQuantities - GrossCeilingArea: 0.00227929 m2
8626145 | EG_Produktion_FFB | A - FL-Str.02_NK-KK-TK
8626177 | EG_Produktion_FFB | A - SL_NK-Str.02
8626178 | EG_Produktion_FFB | A - SL_NK-Str.02 | BaseQuantities - GrossCeilingArea: 0.00227929 m2
8626183 | EG_Produktion_FFB | A - SL_NK-Str.02
8626216 | EG_Produktion_FFB | A - FL-Str.02_NK-KK-TK
8626217 | EG_Produktion_FFB | A - SL_NK-Str.02
8626290 | EG_Produktion_FFB | A - FL-Str.02_NK-KK-TK
8626314 | EG_Produktion_FFB | A - SL_NK-Str.02 | BaseQuantities - GrossCeilingArea: 0.00227929 m2
8626319 | EG_Produktion_FFB | A - SL_NK-Str.02
8626354 | EG_Produktion_FFB | A - FL-Str.02_NK-KK-TK | BaseQuantities - GrossCeilingArea: 0.00227929 m2
8626359 | EG_Produktion_FFB | A - FL-Str.02_NK-KK-TK
8626502 | EG_Produktion_FFB | A - FL-Str.03_NK-KK-TK
8626505 | EG_Produktion_FFB | A - SL_NK-Str.02
8626668 | EG_Produktion_FFB | A - SL_NK-Str.02
8626669 | EG_Produktion_FFB | A - SL_NK-Str.02 | BaseQuantities - GrossCeilingArea: 0.00227929 m2
8626677 | EG_Produktion_FFB | A - SL_NK-Str.02
8626682 | EG_Produktion_FFB | A - SL_NK-Str.02
8626714 | EG_Produktion_FFB | A - FL-Str.03_NK-KK-TK
8626715 | EG_Produktion_FFB | A - FL-Str.03_NK-KK-TK | BaseQuantities - GrossCeilingArea: 0.00227929 m2
8626728 | EG_Produktion_FFB | A - FL-Str.03_NK-KK-TK
8626829 | EG_Produktion_FFB | A - FL-Str.03_NK-KK-TK
8626886 | EG_Produktion_FFB | B - FL-Str.02_NK-KK-TK
8626887 | EG_Produktion_FFB | B - SL_TK
8627043 | EG_Produktion_FFB | B - FL-Str.02_NK-KK-TK
8627044 | EG_Produktion_FFB | B - FL-Str.02_NK-KK-TK
8627056 | EG_Produktion_FFB | B - FL-Str.02_NK-KK-TK
8627088 | EG_Produktion_FFB | B - SL_TK
8627089 | EG_Produktion_FFB | B - SL_TK
8627099 | EG_Produktion_FFB | B - SL_TK
8627104 | EG_Produktion_FFB | B - SL_TK
8627152 | EG_Produktion_FFB | B - FL-Str.02_NK-KK-TK
8627154 | EG_Produktion_FFB | B - FL-Str.02_NK-KK-TK | BaseQuantities - GrossCeilingArea: 0.0020069 m2
8627160 | EG_Produktion_FFB | B - FL-Str.02_NK-KK-TK
8627163 | EG_Produktion_FFB | B - FL-Str.02_NK-KK-TK
8627168 | EG_Produktion_FFB | B - FL-Str.02_NK-KK-TK
8627198 | EG_Produktion_FFB | B - SL_TK
8627200 | EG_Produktion_FFB | B - SL_TK | BaseQuantities - GrossCeilingArea: 0.00228639 m2
8627206 | EG_Produktion_FFB | B - SL_TK | BaseQuantities - GrossCeilingArea: 0.00227929 m2
8627209 | EG_Produktion_FFB | B - SL_TK
8627214 | EG_Produktion_FFB | B - SL_TK
8627294 | EG_Produktion_FFB | A - SL_TK
8627295 | EG_Produktion_FFB | A - SL_TK
8627305 | EG_Produktion_FFB | A - SL_TK
8627310 | EG_Produktion_FFB | A - SL_TK
8627340 | EG_Produktion_FFB | A - FL-Str.02_NK-KK-TK
8627341 | EG_Produktion_FFB | A - FL-Str.02_NK-KK-TK
8627353 | EG_Produktion_FFB | A - FL-Str.02_NK-KK-TK
8627544 | EG_Produktion_FFB | B - FL-Str.02_NK-KK-TK | BaseQuantities - GrossCeilingArea: 0.0020069 m2
8627549 | EG_Produktion_FFB | B - FL-Str.02_NK-KK-TK
8627550 | EG_Produktion_FFB | B - FL-Str.02_NK-KK-TK
8627594 | EG_Produktion_FFB | B - FL-Str.02_NK-KK-TK
8627625 | EG_Produktion_FFB | B - SL_NK-Str.01
8627626 | EG_Produktion_FFB | B - SL_NK-Str.01
8627636 | EG_Produktion_FFB | B - SL_NK-Str.01
8627641 | EG_Produktion_FFB | B - SL_NK-Str.01
8627682 | EG_Produktion_FFB | B - FL-Str.01_NK-KK-TK
8627685 | EG_Produktion_FFB | B - SL_KK
8627802 | EG_Produktion_FFB | B - SL_KK
8627803 | EG_Produktion_FFB | B - SL_KK
8627811 | EG_Produktion_FFB | B - SL_KK
8627816 | EG_Produktion_FFB | B - SL_KK
8627840 | EG_Produktion_FFB | B - FL-Str.01_NK-KK-TK
8627841 | EG_Produktion_FFB | B - FL-Str.01_NK-KK-TK
8627849 | EG_Produktion_FFB | B - FL-Str.01_NK-KK-TK
8627854 | EG_Produktion_FFB | B - FL-Str.01_NK-KK-TK
8627913 | EG_Produktion_FFB | A - FL-Str.01_NK-KK-TK
8627916 | EG_Produktion_FFB | A - FL-Str.01_NK-KK-TK
8628218 | EG_Produktion_FFB | B - FL-Str.01_NK-KK-TK
8628219 | EG_Produktion_FFB | B - SL_KK
8628377 | EG_Produktion_FFB | B - FL-Str.01_NK-KK-TK
8628378 | EG_Produktion_FFB | B - FL-Str.01_NK-KK-TK
8628411 | EG_Produktion_FFB | B - SL_KK
8628412 | EG_Produktion_FFB | B - SL_KK
8628543 | EG_Produktion_FFB | B - SL_KK | BaseQuantities - GrossCeilingArea: 0.00238424 m2
8628549 | EG_Produktion_FFB | B - SL_KK
8628554 | EG_Produktion_FFB | B - SL_KK
8628559 | EG_Produktion_FFB | B - SL_KK
8628601 | EG_Produktion_FFB | B - SL_KK
8628688 | EG_Produktion_FFB | B - FL-Str.01_NK-KK-TK | BaseQuantities - GrossCeilingArea: 0.00238424 m2
8628694 | EG_Produktion_FFB | B - FL-Str.01_NK-KK-TK
8628699 | EG_Produktion_FFB | B - FL-Str.01_NK-KK-TK
8628704 | EG_Produktion_FFB | B - FL-Str.01_NK-KK-TK
8628756 | EG_Produktion_FFB | B - FL-Str.01_NK-KK-TK
8628797 | EG_Produktion_FFB | A - SL_KK
8628799 | EG_Produktion_FFB | A - SL_KK | BaseQuantities - GrossCeilingArea: 0.00214664 m2
8628805 | EG_Produktion_FFB | A - SL_KK
8628810 | EG_Produktion_FFB | A - SL_KK
8628815 | EG_Produktion_FFB | A - SL_KK
8628850 | EG_Produktion_FFB | A - FL-Str.01_NK-KK-TK
8628852 | EG_Produktion_FFB | A - FL-Str.01_NK-KK-TK | BaseQuantities - GrossCeilingArea: 0.00214664 m2
8628858 | EG_Produktion_FFB | A - FL-Str.01_NK-KK-TK
8628863 | EG_Produktion_FFB | A - FL-Str.01_NK-KK-TK
8628868 | EG_Produktion_FFB | A - FL-Str.01_NK-KK-TK
8629113 | EG_Produktion_FFB | B - SL_KK | BaseQuantities - GrossCeilingArea: 0.00238424 m2
8629118 | EG_Produktion_FFB | B - SL_KK
8629119 | EG_Produktion_FFB | B - SL_KK
8629152 | EG_Produktion_FFB | B - FL-Str.01_NK-KK-TK | BaseQuantities - GrossCeilingArea: 0.00238424 m2
8629157 | EG_Produktion_FFB | B - FL-Str.01_NK-KK-TK
8629158 | EG_Produktion_FFB | B - FL-Str.01_NK-KK-TK
8629235 | EG_Produktion_FFB | B - SL_KK
8629238 | EG_Produktion_FFB | B - FL-Str.01_NK-KK-TK
8629306 | EG_Produktion_FFB | B - FL-Str.01_NK-KK-TK
8629307 | EG_Produktion_FFB | B - FL-Str.01_NK-KK-TK
8629319 | EG_Produktion_FFB | B - FL-Str.01_NK-KK-TK
8629342 | EG_Produktion_FFB | B - SL_KK
8629343 | EG_Produktion_FFB | B - SL_KK
8629355 | EG_Produktion_FFB | B - SL_KK
8629660 | EG_Produktion_FFB | B - FL-Str.02_NK-KK-TK
8629662 | EG_Produktion_FFB | B - FL-Str.02_NK-KK-TK | BaseQuantities - GrossCeilingArea: 0.0020069 m2
8629668 | EG_Produktion_FFB | B - FL-Str.02_NK-KK-TK
8629671 | EG_Produktion_FFB | B - FL-Str.02_NK-KK-TK
8629676 | EG_Produktion_FFB | B - FL-Str.02_NK-KK-TK
8629704 | EG_Produktion_FFB | B - SL_TK
8629706 | EG_Produktion_FFB | B - SL_TK | BaseQuantities - GrossCeilingArea: 0.00228639 m2
8629712 | EG_Produktion_FFB | B - SL_TK | BaseQuantities - GrossCeilingArea: 0.00227929 m2
8629715 | EG_Produktion_FFB | B - SL_TK
8629720 | EG_Produktion_FFB | B - SL_TK
8629750 | EG_Produktion_FFB | A - FL-Str.02_NK-KK-TK
8629751 | EG_Produktion_FFB | A - SL_TK
8629833 | EG_Produktion_FFB | A - SL_TK
8629835 | EG_Produktion_FFB | A - SL_TK | BaseQuantities - GrossCeilingArea: 0.00228639 m2
8629841 | EG_Produktion_FFB | A - SL_TK | BaseQuantities - GrossCeilingArea: 0.00227929 m2
8629844 | EG_Produktion_FFB | A - SL_TK
8629849 | EG_Produktion_FFB | A - SL_TK
8629877 | EG_Produktion_FFB | A - FL-Str.02_NK-KK-TK
8629879 | EG_Produktion_FFB | A - FL-Str.02_NK-KK-TK | BaseQuantities - GrossCeilingArea: 0.0020069 m2
8629885 | EG_Produktion_FFB | A - FL-Str.02_NK-KK-TK
8629888 | EG_Produktion_FFB | A - FL-Str.02_NK-KK-TK
8629893 | EG_Produktion_FFB | A - FL-Str.02_NK-KK-TK
8629946 | EG_Produktion_FFB | A - FL-Str.02_NK-KK-TK
8629947 | EG_Produktion_FFB | A - SL_TK
8630046 | EG_Produktion_FFB | A - SL_TK
8630048 | EG_Produktion_FFB | A - SL_TK | BaseQuantities - GrossCeilingArea: 0.00228639 m2
8630054 | EG_Produktion_FFB | A - SL_TK | BaseQuantities - GrossCeilingArea: 0.00227929 m2
8630057 | EG_Produktion_FFB | A - SL_TK
8630062 | EG_Produktion_FFB | A - SL_TK
8630090 | EG_Produktion_FFB | A - FL-Str.02_NK-KK-TK
8630092 | EG_Produktion_FFB | A - FL-Str.02_NK-KK-TK | BaseQuantities - GrossCeilingArea: 0.0020069 m2
8630098 | EG_Produktion_FFB | A - FL-Str.02_NK-KK-TK
8630101 | EG_Produktion_FFB | A - FL-Str.02_NK-KK-TK
8630106 | EG_Produktion_FFB | A - FL-Str.02_NK-KK-TK
8630297 | EG_Produktion_FFB | B - SL_KK
8630341 | EG_Produktion_FFB | B - SL_KK
8630342 | EG_Produktion_FFB | B - SL_KK
8630352 | EG_Produktion_FFB | B - SL_KK
8630357 | EG_Produktion_FFB | B - SL_KK
8630495 | EG_Produktion_FFB | A - SL_KK
8630545 | EG_Produktion_FFB | A - SL_KK
8630615 | EG_Produktion_FFB | A - FL-Str.02_NK-KK-TK
8630845 | EG_Produktion_FFB | A - SL_KK
8630846 | EG_Produktion_FFB | A - SL_KK
8630851 | EG_Produktion_FFB | A - SL_KK
8630876 | EG_Produktion_FFB | A - FL-Str.02_NK-KK-TK
8630877 | EG_Produktion_FFB | A - FL-Str.02_NK-KK-TK
8630882 | EG_Produktion_FFB | A - FL-Str.02_NK-KK-TK
8630995 | EG_Produktion_FFB | A - SL_KK
8630996 | EG_Produktion_FFB | A - SL_KK
8631001 | EG_Produktion_FFB | A - SL_KK
8631027 | EG_Produktion_FFB | A - FL-Str.02_NK-KK-TK
8631028 | EG_Produktion_FFB | A - FL-Str.02_NK-KK-TK
8631033 | EG_Produktion_FFB | A - FL-Str.02_NK-KK-TK
8631106 | EG_Produktion_FFB | B - SL_KK
8631144 | EG_Produktion_FFB | B - SL_KK
8631145 | EG_Produktion_FFB | B - SL_KK
8631155 | EG_Produktion_FFB | B - SL_KK
8631160 | EG_Produktion_FFB | B - SL_KK
8631172 | EG_Produktion_FFB | B - FL-Str.01_NK-KK-TK
8631175 | EG_Produktion_FFB | B - SL_NK-Str.01
8631258 | EG_Produktion_FFB | B - FL-Str.01_NK-KK-TK
8631259 | EG_Produktion_FFB | B - FL-Str.01_NK-KK-TK | BaseQuantities - GrossCeilingArea: 0.0023431 m2
8631260 | EG_Produktion_FFB | B - FL-Str.01_NK-KK-TK
8631270 | EG_Produktion_FFB | B - FL-Str.01_NK-KK-TK
8631275 | EG_Produktion_FFB | B - FL-Str.01_NK-KK-TK
8631308 | EG_Produktion_FFB | B - SL_NK-Str.01
8631309 | EG_Produktion_FFB | B - SL_NK-Str.01 | BaseQuantities - GrossCeilingArea: 0.0023431 m2
8631310 | EG_Produktion_FFB | B - SL_NK-Str.01
8631320 | EG_Produktion_FFB | B - SL_NK-Str.01
8631325 | EG_Produktion_FFB | B - SL_NK-Str.01
8631347 | EG_Produktion_FFB | B - FL-Str.01_NK-KK-TK
8631350 | EG_Produktion_FFB | B - SL_NK-Str.01
8631370 | EG_Produktion_FFB | B - FL-Str.01_NK-KK-TK
8631373 | EG_Produktion_FFB | B - SL_NK-Str.01
8631387 | EG_Produktion_FFB | A - SL_NK-Str.01
8631390 | EG_Produktion_FFB | A - FL-Str.01_NK-KK-TK
8631414 | EG_Produktion_FFB | A - FL-Str.01_NK-KK-TK
8631417 | EG_Produktion_FFB | A - SL_NK-Str.01
8631433 | EG_Produktion_FFB | A - SL_NK-Str.01
8631436 | EG_Produktion_FFB | A - FL-Str.01_NK-KK-TK
8631548 | EG_Produktion_FFB | A - SL_NK-Str.01
8631549 | EG_Produktion_FFB | A - SL_NK-Str.01 | BaseQuantities - GrossCeilingArea: 0.0023431 m2
8631550 | EG_Produktion_FFB | A - SL_NK-Str.01
8631560 | EG_Produktion_FFB | A - SL_NK-Str.01
8631565 | EG_Produktion_FFB | A - SL_NK-Str.01
8631598 | EG_Produktion_FFB | A - FL-Str.01_NK-KK-TK
8631599 | EG_Produktion_FFB | A - FL-Str.01_NK-KK-TK | BaseQuantities - GrossCeilingArea: 0.0023431 m2
8631600 | EG_Produktion_FFB | A - FL-Str.01_NK-KK-TK
8631610 | EG_Produktion_FFB | A - FL-Str.01_NK-KK-TK
8631615 | EG_Produktion_FFB | A - FL-Str.01_NK-KK-TK
8631706 | EG_Produktion_FFB | A - FL-Str.01_NK-KK-TK
8631707 | EG_Produktion_FFB | A - FL-Str.01_NK-KK-TK | BaseQuantities - GrossCeilingArea: 0.0023431 m2
8631708 | EG_Produktion_FFB | A - FL-Str.01_NK-KK-TK
8631718 | EG_Produktion_FFB | A - FL-Str.01_NK-KK-TK
8631723 | EG_Produktion_FFB | A - FL-Str.01_NK-KK-TK
8631758 | EG_Produktion_FFB | A - SL_NK-Str.01
8631759 | EG_Produktion_FFB | A - SL_NK-Str.01 | BaseQuantities - GrossCeilingArea: 0.0023431 m2
8631760 | EG_Produktion_FFB | A - SL_NK-Str.01
8631765 | EG_Produktion_FFB | A - SL_NK-Str.01
8631906 | EG_Produktion_FFB | A - SL_NK-Str.01
8631907 | EG_Produktion_FFB | A - SL_NK-Str.01 | BaseQuantities - GrossCeilingArea: 0.0023431 m2
8631908 | EG_Produktion_FFB | A - SL_NK-Str.01
8631913 | EG_Produktion_FFB | A - SL_NK-Str.01
8631948 | EG_Produktion_FFB | A - FL-Str.01_NK-KK-TK
8631949 | EG_Produktion_FFB | A - FL-Str.01_NK-KK-TK | BaseQuantities - GrossCeilingArea: 0.0023431 m2
8631950 | EG_Produktion_FFB | A - FL-Str.01_NK-KK-TK
8631955 | EG_Produktion_FFB | A - FL-Str.01_NK-KK-TK
8632072 | EG_Produktion_FFB | B - FL-Str.01_NK-KK-TK
8632073 | EG_Produktion_FFB | B - FL-Str.01_NK-KK-TK | BaseQuantities - GrossCeilingArea: 0.0023431 m2
8632074 | EG_Produktion_FFB | B - FL-Str.01_NK-KK-TK
8632084 | EG_Produktion_FFB | B - FL-Str.01_NK-KK-TK
8632089 | EG_Produktion_FFB | B - FL-Str.01_NK-KK-TK
8632122 | EG_Produktion_FFB | B - SL_NK-Str.01
8632123 | EG_Produktion_FFB | B - SL_NK-Str.01 | BaseQuantities - GrossCeilingArea: 0.0023431 m2
8632124 | EG_Produktion_FFB | B - SL_NK-Str.01
8632134 | EG_Produktion_FFB | B - SL_NK-Str.01
8632139 | EG_Produktion_FFB | B - SL_NK-Str.01
8632257 | EG_Produktion_FFB | B - FL-Str.01_NK-KK-TK
8632258 | EG_Produktion_FFB | B - FL-Str.01_NK-KK-TK | BaseQuantities - GrossCeilingArea: 0.0023431 m2
8632259 | EG_Produktion_FFB | B - FL-Str.01_NK-KK-TK
8632264 | EG_Produktion_FFB | B - FL-Str.01_NK-KK-TK
8632298 | EG_Produktion_FFB | B - SL_NK-Str.01
8632299 | EG_Produktion_FFB | B - SL_NK-Str.01 | BaseQuantities - GrossCeilingArea: 0.0023431 m2
8632300 | EG_Produktion_FFB | B - SL_NK-Str.01
8632305 | EG_Produktion_FFB | B - SL_NK-Str.01
8632409 | EG_Produktion_FFB | A - FL-Str.02_NK-KK-TK
8632412 | EG_Produktion_FFB | A - SL_NK-Str.01
8632426 | EG_Produktion_FFB | B - FL-Str.02_NK-KK-TK
8632429 | EG_Produktion_FFB | B - SL_NK-Str.01
8632541 | EG_Produktion_FFB | B - FL-Str.02_NK-KK-TK
8632542 | EG_Produktion_FFB | B - FL-Str.02_NK-KK-TK
8632552 | EG_Produktion_FFB | B - FL-Str.02_NK-KK-TK
8632557 | EG_Produktion_FFB | B - FL-Str.02_NK-KK-TK
8632588 | EG_Produktion_FFB | B - SL_NK-Str.01
8632589 | EG_Produktion_FFB | B - SL_NK-Str.01
8632594 | EG_Produktion_FFB | B - SL_NK-Str.01
8632692 | EG_Produktion_FFB | A - SL_NK-Str.01
8632695 | EG_Produktion_FFB | A - FL-Str.02_NK-KK-TK
8632786 | EG_Produktion_FFB | A - FL-Str.02_NK-KK-TK
8632787 | EG_Produktion_FFB | A - FL-Str.02_NK-KK-TK
8632797 | EG_Produktion_FFB | A - FL-Str.02_NK-KK-TK
8632802 | EG_Produktion_FFB | A - FL-Str.02_NK-KK-TK
8632832 | EG_Produktion_FFB | A - SL_NK-Str.01
8632833 | EG_Produktion_FFB | A - SL_NK-Str.01
8632843 | EG_Produktion_FFB | A - SL_NK-Str.01
8632848 | EG_Produktion_FFB | A - SL_NK-Str.01
8632864 | EG_Produktion_FFB | B - SL_NK-Str.01
8632867 | EG_Produktion_FFB | B - FL-Str.02_NK-KK-TK
8632955 | EG_Produktion_FFB | B - FL-Str.02_NK-KK-TK
8632956 | EG_Produktion_FFB | B - FL-Str.02_NK-KK-TK
8632961 | EG_Produktion_FFB | B - FL-Str.02_NK-KK-TK
8632990 | EG_Produktion_FFB | B - SL_NK-Str.01
8632991 | EG_Produktion_FFB | B - SL_NK-Str.01
8632996 | EG_Produktion_FFB | B - SL_NK-Str.01
8633112 | EG_Produktion_FFB | A - SL_NK-Str.01
8633113 | EG_Produktion_FFB | A - SL_NK-Str.01
8633123 | EG_Produktion_FFB | A - SL_NK-Str.01
8633128 | EG_Produktion_FFB | A - SL_NK-Str.01
8633160 | EG_Produktion_FFB | A - FL-Str.02_NK-KK-TK
8633161 | EG_Produktion_FFB | A - FL-Str.02_NK-KK-TK
8633171 | EG_Produktion_FFB | A - FL-Str.02_NK-KK-TK
8633176 | EG_Produktion_FFB | A - FL-Str.02_NK-KK-TK
8633219 | EG_Produktion_FFB | A - FL-Str.02_NK-KK-TK
8633220 | EG_Produktion_FFB | A - SL_NK-Str.01
8633438 | EG_Produktion_FFB | A - SL_NK-Str.01
8633470 | EG_Produktion_FFB | A - FL-Str.02_NK-KK-TK
8633471 | EG_Produktion_FFB | A - SL_NK-Str.01
8633478 | EG_Produktion_FFB | A - SL_NK-Str.01
8633560 | EG_Produktion_FFB | A - SL_NK-Str.01
8633561 | EG_Produktion_FFB | A - SL_NK-Str.01
8633569 | EG_Produktion_FFB | A - SL_NK-Str.01
8633574 | EG_Produktion_FFB | A - SL_NK-Str.01
8633629 | EG_Produktion_FFB | A - FL-Str.02_NK-KK-TK
8633630 | EG_Produktion_FFB | A - FL-Str.02_NK-KK-TK
8633638 | EG_Produktion_FFB | A - FL-Str.02_NK-KK-TK
8633643 | EG_Produktion_FFB | A - FL-Str.02_NK-KK-TK
8633666 | EG_Produktion_FFB | B - SL_NK-Str.01
8633671 | EG_Produktion_FFB | B - FL-Str.02_NK-KK-TK
8633672 | EG_Produktion_FFB | B - SL_NK-Str.01
8633678 | EG_Produktion_FFB | B - SL_NK-Str.01
8633681 | EG_Produktion_FFB | B - SL_NK-Str.01
8633684 | EG_Produktion_FFB | B - SL_NK-Str.01
8633690 | EG_Produktion_FFB | B - FL-Str.02_NK-KK-TK
8633710 | EG_Produktion_FFB | B - FL-Str.02_NK-KK-TK
8633715 | EG_Produktion_FFB | B - FL-Str.02_NK-KK-TK
8633718 | EG_Produktion_FFB | B - SL_NK-Str.01
8634066 | EG_Produktion_FFB | A - FL-Str.01_NK-KK-TK
8634069 | EG_Produktion_FFB | A - SL_KK
8634091 | EG_Produktion_FFB | A - SL_KK
8634154 | EG_Produktion_FFB | A - FL-Str.01_NK-KK-TK
8634320 | EG_Produktion_FFB | A - SL_KK
8634321 | EG_Produktion_FFB | A - SL_KK
8634348 | EG_Produktion_FFB | A - SL_KK
8634349 | EG_Produktion_FFB | A - SL_KK
8634359 | EG_Produktion_FFB | A - SL_KK
8634364 | EG_Produktion_FFB | A - SL_KK
8634388 | EG_Produktion_FFB | A - FL-Str.01_NK-KK-TK
8634389 | EG_Produktion_FFB | A - FL-Str.01_NK-KK-TK | BaseQuantities - GrossCeilingArea: 0.00284825 m2
8634467 | EG_Produktion_FFB | A - FL-Str.01_NK-KK-TK
8634468 | EG_Produktion_FFB | A - FL-Str.01_NK-KK-TK | BaseQuantities - GrossCeilingArea: 0.00284825 m2
8634478 | EG_Produktion_FFB | A - FL-Str.01_NK-KK-TK
8634483 | EG_Produktion_FFB | A - FL-Str.01_NK-KK-TK
8634744 | EG_Produktion_FFB | A - SL_NK-Str.02
8634755 | EG_Produktion_FFB | A - FL-Str.02_NK-KK-TK
8634760 | EG_Produktion_FFB | A - FL-Str.02_NK-KK-TK
8634843 | EG_Produktion_FFB | A - SL_NK-Str.02
8634861 | EG_Produktion_FFB | A - SL_NK-Str.02
8679506 | EG_Produktion_FFB | B - FL-Str.04_NK
8679534 | EG_Produktion_FFB | B - FL-Str.04_NK
8679566 | EG_Produktion_FFB | B - FL-Str.04_NK
8679633 | EG_Produktion_FFB | B - FL-Str.04_NK
8679634 | EG_Produktion_FFB | B - FL-Str.04_NK
8679819 | EG_Produktion_FFB | B - FL-Str.04_NK
8679842 | EG_Produktion_FFB | B - FL-Str.04_NK
8680024 | EG_Produktion_FFB | B - SL_NK-Str.03
8680055 | EG_Produktion_FFB | B - SL_NK-Str.03
8680058 | EG_Produktion_FFB | B - SL_NK-Str.03
8680066 | EG_Produktion_FFB | B - SL_NK-Str.03
8680069 | EG_Produktion_FFB | B - SL_NK-Str.03
8680090 | EG_Produktion_FFB | B - SL_NK-Str.03
8680109 | EG_Produktion_FFB | B - SL_NK-Str.03
8680114 | EG_Produktion_FFB | B - SL_NK-Str.03
8680133 | EG_Produktion_FFB | A - FL-Str.04_NK
8680159 | EG_Produktion_FFB | A - FL-Str.04_NK
8680184 | EG_Produktion_FFB | A - FL-Str.04_NK
8680187 | EG_Produktion_FFB | A - FL-Str.04_NK
8680192 | EG_Produktion_FFB | A - FL-Str.04_NK
8680195 | EG_Produktion_FFB | A - FL-Str.04_NK
8680210 | EG_Produktion_FFB | A - FL-Str.04_NK
8680215 | EG_Produktion_FFB | A - FL-Str.04_NK
8680230 | EG_Produktion_FFB | A - SL_NK-Str.03
8680260 | EG_Produktion_FFB | A - SL_NK-Str.03
8680285 | EG_Produktion_FFB | A - SL_NK-Str.03
8680288 | EG_Produktion_FFB | A - SL_NK-Str.03
8680293 | EG_Produktion_FFB | A - SL_NK-Str.03
8680311 | EG_Produktion_FFB | A - SL_NK-Str.03
8680316 | EG_Produktion_FFB | A - SL_NK-Str.03
8680495 | EG_Produktion_FFB | B - SL_NK-Str.03
8680496 | EG_Produktion_FFB | B - SL_NK-Str.03
8680501 | EG_Produktion_FFB | B - SL_NK-Str.03
8680522 | EG_Produktion_FFB | B - FL-Str.04_NK
8680523 | EG_Produktion_FFB | B - FL-Str.04_NK
8680533 | EG_Produktion_FFB | B - FL-Str.04_NK
8680538 | EG_Produktion_FFB | B - FL-Str.04_NK
8680584 | EG_Produktion_FFB | A - SL_NK-Str.03
8680585 | EG_Produktion_FFB | A - SL_NK-Str.03
8680595 | EG_Produktion_FFB | A - SL_NK-Str.03
8680600 | EG_Produktion_FFB | A - SL_NK-Str.03
8680639 | EG_Produktion_FFB | A - FL-Str.04_NK
8680640 | EG_Produktion_FFB | A - FL-Str.04_NK
8680645 | EG_Produktion_FFB | A - FL-Str.04_NK
10081970 | EG_Produktion_FFB | B - Druckleitung Gaskühler
10082038 | EG_Produktion_FFB | B - Druckleitung Gaskühler
10082041 | EG_Produktion_FFB | B - Druckleitung Gaskühler
10082053 | EG_Produktion_FFB | B - Druckleitung Gaskühler
10082103 | EG_Produktion_FFB | B - Druckleitung Gaskühler
10082106 | EG_Produktion_FFB | B - Druckleitung Gaskühler
10082162 | EG_Produktion_FFB | A - Kondensatleitung Gaskühler
10082181 | EG_Produktion_FFB | A - Kondensatleitung Gaskühler
10082186 | EG_Produktion_FFB | A - Kondensatleitung Gaskühler
10082201 | EG_Produktion_FFB | A - Druckleitung Gaskühler
10082242 | EG_Produktion_FFB | A - Druckleitung Gaskühler
10082272 | EG_Produktion_FFB | A - Druckleitung Gaskühler | BaseQuantities - GrossCeilingArea: 0.00600406 m2
10082273 | EG_Produktion_FFB | A - Druckleitung Gaskühler
10082278 | EG_Produktion_FFB | A - Druckleitung Gaskühler
10082316 | EG_Produktion_FFB | A - Druckleitung Gaskühler
10082321 | EG_Produktion_FFB | A - Druckleitung Gaskühler
10082322 | EG_Produktion_FFB | A - Druckleitung Gaskühler

# IfcDistributionPort (3410)
Description: Flow
Name | FlowDirection | Group
OutPort_5125915_2 | SOURCE | K_Rücklauf 1
InPort_5125915_3 | SINK | K_Vorlauf 2
OutPort_5139542_2 | SOURCE
InPort_5139542_3 | SINK
OutPort_5139601_2 | SOURCE
InPort_5139601_3 | SINK
OutPort_5139609_2 | SOURCE
InPort_5139609_3 | SINK
OutPort_5139617_2 | SOURCE
InPort_5139617_3 | SINK
OutPort_5140140_2 | SOURCE
InPort_5140140_3 | SINK
OutPort_5140294_2 | SOURCE
InPort_5140294_3 | SINK
OutPort_5140409_2 | SOURCE
InPort_5140409_3 | SINK
OutPort_5140547_2 | SOURCE
InPort_5140547_3 | SINK
OutPort_5140553_2 | SOURCE
InPort_5140553_3 | SINK
OutPort_5140563_2 | SOURCE
InPort_5140563_3 | SINK
OutPort_5140571_2 | SOURCE
InPort_5140571_3 | SINK
OutPort_5140577_2 | SOURCE
InPort_5140577_3 | SINK
OutPort_5140737_2 | SOURCE
InPort_5140737_3 | SINK
OutPort_5140738_2 | SOURCE
InPort_5140738_3 | SINK
OutPort_5140739_2 | SOURCE
InPort_5140739_3 | SINK
OutPort_5140740_2 | SOURCE
InPort_5140740_3 | SINK
OutPort_5140776_2 | SOURCE
InPort_5140776_3 | SINK
OutPort_5140777_2 | SOURCE
InPort_5140777_3 | SINK
OutPort_5140803_2 | SOURCE
InPort_5140803_3 | SINK
OutPort_5140856_2 | SOURCE
InPort_5140856_3 | SINK
OutPort_5140974_2 | SOURCE
InPort_5140974_3 | SINK
OutPort_5140982_2 | SOURCE
InPort_5140982_3 | SINK
OutPort_5141008_2 | SOURCE
InPort_5141008_3 | SINK
OutPort_5141046_2 | SOURCE
InPort_5141046_3 | SINK
OutPort_5141189_2 | SOURCE
InPort_5141189_3 | SINK
OutPort_5141258_2 | SOURCE
InPort_5141258_3 | SINK
OutPort_5141259_2 | SOURCE
InPort_5141259_3 | SINK
OutPort_5141293_2 | SOURCE
InPort_5141293_3 | SINK
OutPort_5141294_2 | SOURCE
InPort_5141294_3 | SINK
OutPort_5141310_2 | SOURCE
InPort_5141310_3 | SINK
OutPort_5141311_2 | SOURCE
InPort_5141311_3 | SINK
OutPort_5141345_2 | SOURCE
InPort_5141345_3 | SINK
OutPort_5141451_2 | SOURCE
InPort_5141451_3 | SINK
OutPort_5141511_2 | SOURCE
InPort_5141511_3 | SINK
OutPort_5141537_2 | SOURCE
InPort_5141537_3 | SINK
OutPort_5141585_2 | SOURCE
InPort_5141585_3 | SINK
OutPort_5141593_2 | SOURCE
InPort_5141593_3 | SINK
OutPort_5141601_2 | SOURCE
InPort_5141601_3 | SINK
OutPort_5141887_2 | SOURCE
InPort_5141887_3 | SINK
OutPort_5141888_2 | SOURCE
InPort_5141888_3 | SINK
OutPort_5141889_2 | SOURCE
InPort_5141889_3 | SINK
OutPort_5141922_2 | SOURCE
InPort_5141922_3 | SINK
OutPort_5141998_2 | SOURCE
InPort_5141998_3 | SINK
OutPort_5142062_2 | SOURCE
InPort_5142062_3 | SINK
OutPort_5142063_2 | SOURCE
InPort_5142063_3 | SINK
OutPort_5142081_2 | SOURCE
InPort_5142081_3 | SINK
OutPort_5142082_2 | SOURCE
InPort_5142082_3 | SINK
OutPort_5142105_2 | SOURCE
InPort_5142105_3 | SINK
OutPort_5142106_2 | SOURCE
InPort_5142106_3 | SINK
OutPort_5142135_2 | SOURCE
InPort_5142135_3 | SINK
OutPort_5142229_2 | SOURCE
InPort_5142229_3 | SINK
OutPort_5142267_2 | SOURCE
InPort_5142267_3 | SINK
OutPort_5142391_2 | SOURCE
InPort_5142391_3 | SINK
OutPort_5142507_2 | SOURCE
InPort_5142507_3 | SINK
OutPort_5142508_2 | SOURCE
InPort_5142508_3 | SINK
OutPort_5142534_2 | SOURCE
InPort_5142534_3 | SINK
OutPort_5142905_2 | SOURCE
InPort_5142905_3 | SINK
OutPort_5142951_2 | SOURCE
InPort_5142951_3 | SINK
OutPort_5143086_2 | SOURCE
InPort_5143086_3 | SINK
OutPort_5143160_2 | SOURCE
InPort_5143160_3 | SINK
OutPort_5143203_2 | SOURCE
InPort_5143203_3 | SINK
OutPort_5143227_2 | SOURCE
InPort_5143227_3 | SINK
OutPort_5143228_2 | SOURCE
InPort_5143228_3 | SINK
OutPort_5143268_2 | SOURCE
InPort_5143268_3 | SINK
OutPort_5143334_2 | SOURCE
InPort_5143334_3 | SINK
OutPort_5143444_2 | SOURCE
InPort_5143444_3 | SINK
OutPort_5143445_2 | SOURCE
InPort_5143445_3 | SINK
OutPort_5143575_2 | SOURCE
InPort_5143575_3 | SINK
OutPort_5143665_2 | SOURCE
InPort_5143665_3 | SINK
OutPort_5143673_2 | SOURCE
InPort_5143673_3 | SINK
OutPort_5143817_2 | SOURCE
InPort_5143817_3 | SINK
OutPort_5143825_2 | SOURCE
InPort_5143825_3 | SINK
OutPort_5143833_2 | SOURCE
InPort_5143833_3 | SINK
OutPort_5144114_2 | SOURCE
InPort_5144114_3 | SINK
OutPort_5144115_2 | SOURCE
InPort_5144115_3 | SINK
OutPort_5144116_2 | SOURCE
InPort_5144116_3 | SINK
OutPort_5144117_2 | SOURCE
InPort_5144117_3 | SINK
OutPort_5144118_2 | SOURCE
InPort_5144118_3 | SINK
OutPort_5144119_2 | SOURCE
InPort_5144119_3 | SINK
OutPort_5144147_2 | SOURCE
InPort_5144147_3 | SINK
OutPort_5144148_2 | SOURCE
InPort_5144148_3 | SINK
Port_8579189_0 | SOURCEANDSINK | A - Kondensatleitung Gaskühler
Port_8597350_2 | SOURCEANDSINK | A - Kondensatleitung Gaskühler
Port_8579189_1 | SOURCEANDSINK | A - Kondensatleitung Gaskühler
Port_10082179_1 | SOURCEANDSINK | A - Kondensatleitung Gaskühler
Port_8579192_0 | SOURCEANDSINK | A - Kondensatleitung Gaskühler
Port_8579201_2 | SOURCEANDSINK | A - Kondensatleitung Gaskühler
Port_8579192_1 | SOURCEANDSINK | A - Kondensatleitung Gaskühler
Port_8579195_0 | SOURCEANDSINK | A - Kondensatleitung Gaskühler
Port_10082182_1 | SOURCEANDSINK | A - Kondensatleitung Gaskühler
Port_8579195_1 | SOURCEANDSINK | A - Kondensatleitung Gaskühler
Port_8579201_1 | SOURCEANDSINK | A - Kondensatleitung Gaskühler
Port_8579204_0 | SOURCEANDSINK | A - Kondensatleitung Gaskühler
Port_8579222_1 | SOURCEANDSINK | A - Kondensatleitung Gaskühler
Port_8579204_1 | SOURCEANDSINK | A - Kondensatleitung Gaskühler
Port_8579219_2 | SOURCEANDSINK | A - Kondensatleitung Gaskühler
Port_8579207_0 | SOURCEANDSINK | A - Kondensatleitung Gaskühler
Port_8597353_1 | SOURCEANDSINK | A - Kondensatleitung Gaskühler
Port_8579207_1 | SOURCEANDSINK | A - Kondensatleitung Gaskühler
Port_8579219_1 | SOURCEANDSINK | A - Kondensatleitung Gaskühler
Port_8579213_0 | SOURCEANDSINK | A - Kondensatleitung Gaskühler
Port_8579231_1 | SOURCEANDSINK | A - Kondensatleitung Gaskühler
Port_8579213_1 | SOURCEANDSINK | A - Kondensatleitung Gaskühler
Port_8579222_2 | SOURCEANDSINK | A - Kondensatleitung Gaskühler
Port_8579216_0 | SOURCEANDSINK | A - Kondensatleitung Gaskühler
Port_8579228_2 | SOURCEANDSINK | A - Kondensatleitung Gaskühler
Port_8579216_1 | SOURCEANDSINK | A - Kondensatleitung Gaskühler
Port_8579231_2 | SOURCEANDSINK | A - Kondensatleitung Gaskühler
Port_8579225_0 | SOURCEANDSINK | A - Kondensatleitung Gaskühler
Port_8579225_1 | SOURCEANDSINK | A - Kondensatleitung Gaskühler
Port_8579228_1 | SOURCEANDSINK | A - Kondensatleitung Gaskühler
Port_8579234_0 | SOURCEANDSINK | A - Druckleitung Gaskühler
Port_8597248_2 | SOURCEANDSINK | A - Druckleitung Gaskühler
Port_8579234_1 | SOURCEANDSINK | A - Druckleitung Gaskühler
Port_10082319_1 | SOURCEANDSINK | A - Druckleitung Gaskühler
Port_8579237_0 | SOURCEANDSINK | A - Druckleitung Gaskühler
Port_10082274_1 | SOURCEANDSINK | A - Druckleitung Gaskühler
Port_8579237_1 | SOURCEANDSINK | A - Druckleitung Gaskühler
Port_8579240_0 | SOURCEANDSINK | A - Druckleitung Gaskühler
Port_10082269_2 | SOURCEANDSINK | A - Druckleitung Gaskühler
Port_8579240_1 | SOURCEANDSINK | A - Druckleitung Gaskühler
Port_10082274_2 | SOURCEANDSINK | A - Druckleitung Gaskühler
Port_8579243_0 | SOURCEANDSINK | A - Druckleitung Gaskühler
Port_8579264_1 | SOURCEANDSINK | A - Druckleitung Gaskühler
Port_8579243_1 | SOURCEANDSINK | A - Druckleitung Gaskühler
Port_8579261_2 | SOURCEANDSINK | A - Druckleitung Gaskühler
Port_8579246_0 | SOURCEANDSINK | A - Druckleitung Gaskühler
Port_8597337_1 | SOURCEANDSINK | A - Druckleitung Gaskühler
Port_8579246_1 | SOURCEANDSINK | A - Druckleitung Gaskühler
Port_8579264_2 | SOURCEANDSINK | A - Druckleitung Gaskühler
Port_8579249_0 | SOURCEANDSINK | A - Druckleitung Gaskühler
Port_8579261_1 | SOURCEANDSINK | A - Druckleitung Gaskühler
Port_8579249_1 | SOURCEANDSINK | A - Druckleitung Gaskühler
Port_8580556_1 | SOURCEANDSINK | A - Druckleitung Gaskühler
Port_8579252_0 | SOURCEANDSINK | A - Druckleitung Gaskühler
Port_8580556_2 | SOURCEANDSINK | A - Druckleitung Gaskühler
Port_8579252_1 | SOURCEANDSINK | A - Druckleitung Gaskühler
Port_8580561_2 | SOURCEANDSINK | A - Druckleitung Gaskühler
Port_8579255_0 | SOURCEANDSINK | A - Druckleitung Gaskühler
Port_8580561_1 | SOURCEANDSINK | A - Druckleitung Gaskühler
Port_8579255_1 | SOURCEANDSINK | A - Druckleitung Gaskühler
Port_8579279_0 | SOURCEANDSINK | B - Kondensatleitung Gaskühler
Port_8579310_2 | SOURCEANDSINK | B - Kondensatleitung Gaskühler
Port_8579279_1 | SOURCEANDSINK | B - Kondensatleitung Gaskühler
Port_8579282_0 | SOURCEANDSINK | B - Druckleitung Gaskühler
Port_8580535_2 | SOURCEANDSINK | B - Druckleitung Gaskühler
Port_8579282_1 | SOURCEANDSINK | B - Druckleitung Gaskühler
Port_8579285_0 | SOURCEANDSINK | B - Kondensatleitung Gaskühler
Port_8579298_1 | SOURCEANDSINK | B - Kondensatleitung Gaskühler
Port_8579285_1 | SOURCEANDSINK | B - Kondensatleitung Gaskühler
Port_8579306_1 | SOURCEANDSINK | B - Kondensatleitung Gaskühler
Port_8579288_0 | SOURCEANDSINK | B - Druckleitung Gaskühler
Port_8579301_1 | SOURCEANDSINK | B - Druckleitung Gaskühler
Port_8579288_1 | SOURCEANDSINK | B - Druckleitung Gaskühler
Port_8579315_1 | SOURCEANDSINK | B - Druckleitung Gaskühler
Port_8579291_0 | SOURCEANDSINK | B - Kondensatleitung Gaskühler
Port_8579328_1 | SOURCEANDSINK | B - Kondensatleitung Gaskühler
Port_8579291_1 | SOURCEANDSINK | B - Kondensatleitung Gaskühler
Port_8579298_2 | SOURCEANDSINK | B - Kondensatleitung Gaskühler
Port_8579294_0 | SOURCEANDSINK | B - Druckleitung Gaskühler
Port_8579301_2 | SOURCEANDSINK | B - Druckleitung Gaskühler
Port_8579294_1 | SOURCEANDSINK | B - Druckleitung Gaskühler
Port_8579331_1 | SOURCEANDSINK | B - Druckleitung Gaskühler
Port_8579304_0 | SOURCEANDSINK | B - Kondensatleitung Gaskühler
Port_8579306_2 | SOURCEANDSINK | B - Kondensatleitung Gaskühler
Port_8579304_1 | SOURCEANDSINK | B - Kondensatleitung Gaskühler
Port_8579310_1 | SOURCEANDSINK | B - Kondensatleitung Gaskühler
Port_8579313_0 | SOURCEANDSINK | B - Druckleitung Gaskühler
Port_8579315_2 | SOURCEANDSINK | B - Druckleitung Gaskühler
Port_8579313_1 | SOURCEANDSINK | B - Druckleitung Gaskühler
Port_8580535_1 | SOURCEANDSINK | B - Druckleitung Gaskühler
Port_8579322_0 | SOURCEANDSINK | B - Druckleitung Gaskühler
Port_8579331_2 | SOURCEANDSINK | B - Druckleitung Gaskühler
Port_8579322_1 | SOURCEANDSINK | B - Druckleitung Gaskühler
Port_10082099_1 | SOURCEANDSINK | B - Druckleitung Gaskühler
Port_8579325_0 | SOURCEANDSINK | B - Kondensatleitung Gaskühler
Port_8579328_2 | SOURCEANDSINK | B - Kondensatleitung Gaskühler
Port_8579325_1 | SOURCEANDSINK | B - Kondensatleitung Gaskühler
Port_8580673_1 | SOURCEANDSINK | B - Kondensatleitung Gaskühler
Port_8579337_0 | SOURCEANDSINK | B - Kondensatleitung Gaskühler
Port_8579347_1 | SOURCEANDSINK | B - Kondensatleitung Gaskühler
Port_8579337_1 | SOURCEANDSINK | B - Kondensatleitung Gaskühler
Port_8579340_0 | SOURCEANDSINK | B - Druckleitung Gaskühler
Port_10082039_2 | SOURCEANDSINK | B - Druckleitung Gaskühler
Port_8579340_1 | SOURCEANDSINK | B - Druckleitung Gaskühler
Port_10082104_1 | SOURCEANDSINK | B - Druckleitung Gaskühler
Port_8579342_0 | SOURCEANDSINK | B - Kondensatleitung Gaskühler
Port_8580668_2 | SOURCEANDSINK | B - Kondensatleitung Gaskühler
Port_8579342_1 | SOURCEANDSINK | B - Kondensatleitung Gaskühler
Port_8580673_2 | SOURCEANDSINK | B - Kondensatleitung Gaskühler
Port_8579345_0 | SOURCEANDSINK | B - Kondensatleitung Gaskühler
Port_8579347_2 | SOURCEANDSINK | B - Kondensatleitung Gaskühler
Port_8579345_1 | SOURCEANDSINK | B - Kondensatleitung Gaskühler
Port_8580668_1 | SOURCEANDSINK | B - Kondensatleitung Gaskühler
Port_8579357_0 | SOURCEANDSINK | B - Druckleitung Gaskühler
Port_8579366_2 | SOURCEANDSINK | B - Druckleitung Gaskühler
Port_8579357_1 | SOURCEANDSINK | B - Druckleitung Gaskühler
Port_8579360_0 | SOURCEANDSINK | B - Druckleitung Gaskühler
Port_10082034_1 | SOURCEANDSINK | B - Druckleitung Gaskühler
Port_8579360_1 | SOURCEANDSINK | B - Druckleitung Gaskühler
Port_8579366_1 | SOURCEANDSINK | B - Druckleitung Gaskühler
Port_8579369_0 | SOURCEANDSINK | A - FL-Str.01_NK-KK-TK
Port_8579415_4 | SOURCEANDSINK | A - FL-Str.01_NK-KK-TK
Port_8579369_1 | SOURCEANDSINK | A - FL-Str.01_NK-KK-TK
Port_8604070_1 | SOURCEANDSINK | A - FL-Str.01_NK-KK-TK
Port_8579399_0 | SOURCEANDSINK | A - FL-Str.01_NK-KK-TK
Port_8579504_4 | SOURCEANDSINK | A - FL-Str.01_NK-KK-TK
Port_8579399_1 | SOURCEANDSINK | A - FL-Str.01_NK-KK-TK
Port_8606993_4 | SOURCEANDSINK | A - FL-Str.01_NK-KK-TK
Port_8579404_4 | SOURCEANDSINK | A - FL-Str.01_NK-KK-TK
Port_8579425_0 | SOURCEANDSINK | A - FL-Str.01_NK-KK-TK
Port_8579404_5 | SOURCEANDSINK | A - FL-Str.01_NK-KK-TK
Port_8606994_0 | SOURCEANDSINK | A - FL-Str.01_NK-KK-TK
Port_8579404_6 | SOURCEANDSINK | A - FL-Str.01_NK-KK-TK
Port_8606029_0 | SOURCEANDSINK | A - FL-Str.01_NK-KK-TK
Port_8579409_4 | SOURCEANDSINK | A - FL-Str.01_NK-KK-TK
Port_8579434_0 | SOURCEANDSINK | A - FL-Str.01_NK-KK-TK
Port_8579409_5 | SOURCEANDSINK | A - FL-Str.01_NK-KK-TK
Port_8579410_1 | SOURCEANDSINK | A - FL-Str.01_NK-KK-TK
Port_8579409_6 | SOURCEANDSINK | A - FL-Str.01_NK-KK-TK
Port_8606568_0 | SOURCEANDSINK | A - FL-Str.01_NK-KK-TK
Port_8579410_0 | SOURCEANDSINK | A - FL-Str.01_NK-KK-TK
Port_8579424_4 | SOURCEANDSINK | A - FL-Str.01_NK-KK-TK
Port_8579415_5 | SOURCEANDSINK | A - FL-Str.01_NK-KK-TK
Port_8579416_1 | SOURCEANDSINK | A - FL-Str.01_NK-KK-TK
Port_8579415_6 | SOURCEANDSINK | A - FL-Str.01_NK-KK-TK
Port_8604266_0 | SOURCEANDSINK | A - FL-Str.01_NK-KK-TK
Port_8579416_0 | SOURCEANDSINK | A - FL-Str.01_NK-KK-TK
Port_8579433_4 | SOURCEANDSINK | A - FL-Str.01_NK-KK-TK
Port_8579424_5 | SOURCEANDSINK | A - FL-Str.01_NK-KK-TK
Port_8579425_1 | SOURCEANDSINK | A - FL-Str.01_NK-KK-TK
Port_8579424_6 | SOURCEANDSINK | A - FL-Str.01_NK-KK-TK
Port_8606353_0 | SOURCEANDSINK | A - FL-Str.01_NK-KK-TK
Port_8579433_5 | SOURCEANDSINK | A - FL-Str.01_NK-KK-TK
Port_8579434_1 | SOURCEANDSINK | A - FL-Str.01_NK-KK-TK
Port_8579433_6 | SOURCEANDSINK | A - FL-Str.01_NK-KK-TK
Port_8604571_0 | SOURCEANDSINK | A - FL-Str.01_NK-KK-TK
Port_8579450_4 | SOURCEANDSINK | A - FL-Str.01_NK-KK-TK
Port_8634119_0 | SOURCEANDSINK | A - FL-Str.01_NK-KK-TK
Port_8579450_5 | SOURCEANDSINK | A - FL-Str.01_NK-KK-TK
Port_8579451_1 | SOURCEANDSINK | A - FL-Str.01_NK-KK-TK
Port_8579450_6 | SOURCEANDSINK | A - FL-Str.01_NK-KK-TK
Port_8605670_0 | SOURCEANDSINK | A - FL-Str.01_NK-KK-TK
Port_8579451_0 | SOURCEANDSINK | A - FL-Str.01_NK-KK-TK
Port_8579456_4 | SOURCEANDSINK | A - FL-Str.01_NK-KK-TK
Port_8579456_5 | SOURCEANDSINK | A - FL-Str.01_NK-KK-TK
Port_8579457_1 | SOURCEANDSINK | A - FL-Str.01_NK-KK-TK
Port_8579456_6 | SOURCEANDSINK | A - FL-Str.01_NK-KK-TK
Port_8611683_0 | SOURCEANDSINK | A - FL-Str.01_NK-KK-TK
Port_8579457_0 | SOURCEANDSINK | A - FL-Str.01_NK-KK-TK
Port_8579462_4 | SOURCEANDSINK | A - FL-Str.01_NK-KK-TK
Port_8579462_5 | SOURCEANDSINK | A - FL-Str.01_NK-KK-TK
Port_8579463_0 | SOURCEANDSINK | A - FL-Str.01_NK-KK-TK
Port_8579462_6 | SOURCEANDSINK | A - FL-Str.01_NK-KK-TK
Port_8611817_0 | SOURCEANDSINK | A - FL-Str.01_NK-KK-TK
Port_8579463_1 | SOURCEANDSINK | A - FL-Str.01_NK-KK-TK
Port_8611879_2 | SOURCEANDSINK | A - FL-Str.01_NK-KK-TK
Port_8579498_4 | SOURCEANDSINK | A - FL-Str.01_NK-KK-TK
Port_8579505_0 | SOURCEANDSINK | A - FL-Str.01_NK-KK-TK
Port_8579498_5 | SOURCEANDSINK | A - FL-Str.01_NK-KK-TK
Port_8579499_0 | SOURCEANDSINK | A - FL-Str.01_NK-KK-TK
Port_8579498_6 | SOURCEANDSINK | A - FL-Str.01_NK-KK-TK
Port_8605476_0 | SOURCEANDSINK | A - FL-Str.01_NK-KK-TK
Port_8579499_1 | SOURCEANDSINK | A - FL-Str.01_NK-KK-TK
Port_8634384_1 | SOURCEANDSINK | A - FL-Str.01_NK-KK-TK
Port_8579504_5 | SOURCEANDSINK | A - FL-Str.01_NK-KK-TK
Port_8579505_1 | SOURCEANDSINK | A - FL-Str.01_NK-KK-TK
Port_8579504_6 | SOURCEANDSINK | A - FL-Str.01_NK-KK-TK
Port_8604814_0 | SOURCEANDSINK | A - FL-Str.01_NK-KK-TK
Port_8579513_0 | SOURCEANDSINK | A - FL-Str.01_NK-KK-TK
Port_8579521_1 | SOURCEANDSINK | A - FL-Str.01_NK-KK-TK
Port_8579513_1 | SOURCEANDSINK | A - FL-Str.01_NK-KK-TK
Port_8579516_0 | SOURCEANDSINK | A - FL-Str.01_NK-KK-TK
Port_8604079_2 | SOURCEANDSINK | A - FL-Str.01_NK-KK-TK
Port_8579516_1 | SOURCEANDSINK | A - FL-Str.01_NK-KK-TK
Port_8604084_2 | SOURCEANDSINK | A - FL-Str.01_NK-KK-TK
Port_8579519_0 | SOURCEANDSINK | A - FL-Str.01_NK-KK-TK
Port_8579521_2 | SOURCEANDSINK | A - FL-Str.01_NK-KK-TK
Port_8579519_1 | SOURCEANDSINK | A - FL-Str.01_NK-KK-TK
Port_8604079_1 | SOURCEANDSINK | A - FL-Str.01_NK-KK-TK
Port_8579531_0 | SOURCEANDSINK | B - FL-Str.01_NK-KK-TK
Port_8579539_1 | SOURCEANDSINK | B - FL-Str.01_NK-KK-TK
Port_8579531_1 | SOURCEANDSINK | B - FL-Str.01_NK-KK-TK
Port_8579534_0 | SOURCEANDSINK | B - FL-Str.01_NK-KK-TK
Port_8604005_2 | SOURCEANDSINK | B - FL-Str.01_NK-KK-TK
Port_8579534_1 | SOURCEANDSINK | B - FL-Str.01_NK-KK-TK
Port_8604010_2 | SOURCEANDSINK | B - FL-Str.01_NK-KK-TK
Port_8579537_0 | SOURCEANDSINK | B - FL-Str.01_NK-KK-TK
Port_8579539_2 | SOURCEANDSINK | B - FL-Str.01_NK-KK-TK
Port_8579537_1 | SOURCEANDSINK | B - FL-Str.01_NK-KK-TK
Port_8604005_1 | SOURCEANDSINK | B - FL-Str.01_NK-KK-TK
Port_8579567_0 | SOURCEANDSINK | B - FL-Str.01_NK-KK-TK
Port_8579642_4 | SOURCEANDSINK | B - FL-Str.01_NK-KK-TK
Port_8579567_1 | SOURCEANDSINK | B - FL-Str.01_NK-KK-TK
Port_8579618_4 | SOURCEANDSINK | B - FL-Str.01_NK-KK-TK
Port_8579584_4 | SOURCEANDSINK | B - FL-Str.01_NK-KK-TK
Port_8579613_0 | SOURCEANDSINK | B - FL-Str.01_NK-KK-TK
Port_8579584_5 | SOURCEANDSINK | B - FL-Str.01_NK-KK-TK
Port_8579634_0 | SOURCEANDSINK | B - FL-Str.01_NK-KK-TK
Port_8579584_6 | SOURCEANDSINK | B - FL-Str.01_NK-KK-TK
Port_8605352_0 | SOURCEANDSINK | B - FL-Str.01_NK-KK-TK
Port_8579585_0 | SOURCEANDSINK | B - FL-Str.01_NK-KK-TK
Port_8579627_4 | SOURCEANDSINK | B - FL-Str.01_NK-KK-TK
Port_8579585_1 | SOURCEANDSINK | B - FL-Str.01_NK-KK-TK
Port_8611993_2 | SOURCEANDSINK | B - FL-Str.01_NK-KK-TK
Port_8579612_4 | SOURCEANDSINK | B - FL-Str.01_NK-KK-TK
Port_8579619_0 | SOURCEANDSINK | B - FL-Str.01_NK-KK-TK
Port_8579612_5 | SOURCEANDSINK | B - FL-Str.01_NK-KK-TK
Port_8579613_1 | SOURCEANDSINK | B - FL-Str.01_NK-KK-TK
Port_8579612_6 | SOURCEANDSINK | B - FL-Str.01_NK-KK-TK
Port_8605260_0 | SOURCEANDSINK | B - FL-Str.01_NK-KK-TK
Port_8579618_5 | SOURCEANDSINK | B - FL-Str.01_NK-KK-TK
Port_8579619_1 | SOURCEANDSINK | B - FL-Str.01_NK-KK-TK
Port_8579618_6 | SOURCEANDSINK | B - FL-Str.01_NK-KK-TK
Port_8605017_0 | SOURCEANDSINK | B - FL-Str.01_NK-KK-TK
Port_8579627_5 | SOURCEANDSINK | B - FL-Str.01_NK-KK-TK
Port_8579628_1 | SOURCEANDSINK | B - FL-Str.01_NK-KK-TK
Port_8579627_6 | SOURCEANDSINK | B - FL-Str.01_NK-KK-TK
Port_8611931_0 | SOURCEANDSINK | B - FL-Str.01_NK-KK-TK
Port_8579628_0 | SOURCEANDSINK | B - FL-Str.01_NK-KK-TK
Port_8579633_4 | SOURCEANDSINK | B - FL-Str.01_NK-KK-TK
Port_8579633_5 | SOURCEANDSINK | B - FL-Str.01_NK-KK-TK
Port_8579634_1 | SOURCEANDSINK | B - FL-Str.01_NK-KK-TK
Port_8579633_6 | SOURCEANDSINK | B - FL-Str.01_NK-KK-TK
Port_8611750_0 | SOURCEANDSINK | B - FL-Str.01_NK-KK-TK
Port_8579642_5 | SOURCEANDSINK | B - FL-Str.01_NK-KK-TK
Port_8579643_1 | SOURCEANDSINK | B - FL-Str.01_NK-KK-TK
Port_8579642_6 | SOURCEANDSINK | B - FL-Str.01_NK-KK-TK
Port_8605861_0 | SOURCEANDSINK | B - FL-Str.01_NK-KK-TK
Port_8579643_0 | SOURCEANDSINK | B - FL-Str.01_NK-KK-TK
Port_8579699_4 | SOURCEANDSINK | B - FL-Str.01_NK-KK-TK
Port_8579648_4 | SOURCEANDSINK | B - FL-Str.01_NK-KK-TK
Port_8579700_0 | SOURCEANDSINK | B - FL-Str.01_NK-KK-TK
Port_8579648_5 | SOURCEANDSINK | B - FL-Str.01_NK-KK-TK
Port_8579649_1 | SOURCEANDSINK | B - FL-Str.01_NK-KK-TK
Port_8579648_6 | SOURCEANDSINK | B - FL-Str.01_NK-KK-TK
Port_8606106_0 | SOURCEANDSINK | B - FL-Str.01_NK-KK-TK
Port_8579649_0 | SOURCEANDSINK | B - FL-Str.01_NK-KK-TK
Port_8579654_4 | SOURCEANDSINK | B - FL-Str.01_NK-KK-TK
Port_8579654_5 | SOURCEANDSINK | B - FL-Str.01_NK-KK-TK
Port_8579655_0 | SOURCEANDSINK | B - FL-Str.01_NK-KK-TK
Port_8579654_6 | SOURCEANDSINK | B - FL-Str.01_NK-KK-TK
Port_8606266_0 | SOURCEANDSINK | B - FL-Str.01_NK-KK-TK
Port_8579655_1 | SOURCEANDSINK | B - FL-Str.01_NK-KK-TK
Port_8579660_4 | SOURCEANDSINK | B - FL-Str.01_NK-KK-TK
Port_8579660_5 | SOURCEANDSINK | B - FL-Str.01_NK-KK-TK
Port_8579661_1 | SOURCEANDSINK | B - FL-Str.01_NK-KK-TK
Port_8579660_6 | SOURCEANDSINK | B - FL-Str.01_NK-KK-TK
Port_8606514_0 | SOURCEANDSINK | B - FL-Str.01_NK-KK-TK
Port_8579661_0 | SOURCEANDSINK | B - FL-Str.01_NK-KK-TK
Port_8579666_4 | SOURCEANDSINK | B - FL-Str.01_NK-KK-TK
Port_8579666_5 | SOURCEANDSINK | B - FL-Str.01_NK-KK-TK
Port_8579667_1 | SOURCEANDSINK | B - FL-Str.01_NK-KK-TK
Port_8579666_6 | SOURCEANDSINK | B - FL-Str.01_NK-KK-TK
Port_8604450_0 | SOURCEANDSINK | B - FL-Str.01_NK-KK-TK
Port_8579667_0 | SOURCEANDSINK | B - FL-Str.01_NK-KK-TK
Port_8579672_4 | SOURCEANDSINK | B - FL-Str.01_NK-KK-TK
Port_8579672_5 | SOURCEANDSINK | B - FL-Str.01_NK-KK-TK
Port_8579673_1 | SOURCEANDSINK | B - FL-Str.01_NK-KK-TK
Port_8579672_6 | SOURCEANDSINK | B - FL-Str.01_NK-KK-TK
Port_8604366_0 | SOURCEANDSINK | B - FL-Str.01_NK-KK-TK
Port_8579673_0 | SOURCEANDSINK | B - FL-Str.01_NK-KK-TK
Port_8603996_1 | SOURCEANDSINK | B - FL-Str.01_NK-KK-TK
Port_8579699_5 | SOURCEANDSINK | B - FL-Str.01_NK-KK-TK
Port_8579700_1 | SOURCEANDSINK | B - FL-Str.01_NK-KK-TK
Port_8579699_6 | SOURCEANDSINK | B - FL-Str.01_NK-KK-TK
Port_8605915_0 | SOURCEANDSINK | B - FL-Str.01_NK-KK-TK
Port_8579705_0 | SOURCEANDSINK | A - FL-Str.03_NK-KK-TK
Port_8579750_4 | SOURCEANDSINK | A - FL-Str.03_NK-KK-TK
Port_8579705_1 | SOURCEANDSINK | A - FL-Str.03_NK-KK-TK
Port_8601363_2 | SOURCEANDSINK | A - FL-Str.03_NK-KK-TK
Port_8579741_0 | SOURCEANDSINK | A - FL-Str.03_NK-KK-TK
Port_8579743_5 | SOURCEANDSINK | A - FL-Str.03_NK-KK-TK
Port_8579741_1 | SOURCEANDSINK | A - FL-Str.03_NK-KK-TK
Port_8600290_4 | SOURCEANDSINK | A - FL-Str.03_NK-KK-TK
Port_8579743_4 | SOURCEANDSINK | A - FL-Str.03_NK-KK-TK
Port_8579769_0 | SOURCEANDSINK | A - FL-Str.03_NK-KK-TK
Port_8579743_6 | SOURCEANDSINK | A - FL-Str.03_NK-KK-TK
Port_8608144_0 | SOURCEANDSINK | A - FL-Str.03_NK-KK-TK
Port_8579750_5 | SOURCEANDSINK | A - FL-Str.03_NK-KK-TK
Port_8579751_1 | SOURCEANDSINK | A - FL-Str.03_NK-KK-TK
Port_8579750_6 | SOURCEANDSINK | A - FL-Str.03_NK-KK-TK
Port_8607185_0 | SOURCEANDSINK | A - FL-Str.03_NK-KK-TK
Port_8579751_0 | SOURCEANDSINK | A - FL-Str.03_NK-KK-TK
Port_8579756_4 | SOURCEANDSINK | A - FL-Str.03_NK-KK-TK
Port_8579756_5 | SOURCEANDSINK | A - FL-Str.03_NK-KK-TK
Port_8579757_1 | SOURCEANDSINK | A - FL-Str.03_NK-KK-TK
Port_8579756_6 | SOURCEANDSINK | A - FL-Str.03_NK-KK-TK
Port_8599358_1 | SOURCEANDSINK | A - FL-Str.03_NK-KK-TK
Port_8579757_0 | SOURCEANDSINK | A - FL-Str.03_NK-KK-TK
Port_8579762_4 | SOURCEANDSINK | A - FL-Str.03_NK-KK-TK
Port_8579762_5 | SOURCEANDSINK | A - FL-Str.03_NK-KK-TK
Port_8579763_1 | SOURCEANDSINK | A - FL-Str.03_NK-KK-TK
Port_8579762_6 | SOURCEANDSINK | A - FL-Str.03_NK-KK-TK
Port_8607682_0 | SOURCEANDSINK | A - FL-Str.03_NK-KK-TK
Port_8579763_0 | SOURCEANDSINK | A - FL-Str.03_NK-KK-TK
Port_8579768_4 | SOURCEANDSINK | A - FL-Str.03_NK-KK-TK
Port_8579768_5 | SOURCEANDSINK | A - FL-Str.03_NK-KK-TK
Port_8579769_1 | SOURCEANDSINK | A - FL-Str.03_NK-KK-TK
Port_8579768_6 | SOURCEANDSINK | A - FL-Str.03_NK-KK-TK
Port_8607856_0 | SOURCEANDSINK | A - FL-Str.03_NK-KK-TK
Port_8579774_0 | SOURCEANDSINK | B - FL-Str.03_NK-KK-TK
Port_8579827_4 | SOURCEANDSINK | B - FL-Str.03_NK-KK-TK
Port_8579774_1 | SOURCEANDSINK | B - FL-Str.03_NK-KK-TK
Port_8623603_1 | SOURCEANDSINK | B - FL-Str.03_NK-KK-TK
Port_8579802_4 | SOURCEANDSINK | B - FL-Str.03_NK-KK-TK
Port_8579813_0 | SOURCEANDSINK | B - FL-Str.03_NK-KK-TK
Port_8579802_5 | SOURCEANDSINK | B - FL-Str.03_NK-KK-TK
Port_8579803_0 | SOURCEANDSINK | B - FL-Str.03_NK-KK-TK
Port_8579802_6 | SOURCEANDSINK | B - FL-Str.03_NK-KK-TK
Port_8608904_0 | SOURCEANDSINK | B - FL-Str.03_NK-KK-TK
Port_8579803_1 | SOURCEANDSINK | B - FL-Str.03_NK-KK-TK
Port_8579934_1 | SOURCEANDSINK | B - FL-Str.03_NK-KK-TK
Port_8579812_4 | SOURCEANDSINK | B - FL-Str.03_NK-KK-TK
Port_8579819_0 | SOURCEANDSINK | B - FL-Str.03_NK-KK-TK
Port_8579812_5 | SOURCEANDSINK | B - FL-Str.03_NK-KK-TK
Port_8579813_1 | SOURCEANDSINK | B - FL-Str.03_NK-KK-TK
Port_8579812_6 | SOURCEANDSINK | B - FL-Str.03_NK-KK-TK
Port_8608275_0 | SOURCEANDSINK | B - FL-Str.03_NK-KK-TK
Port_8579818_4 | SOURCEANDSINK | B - FL-Str.03_NK-KK-TK
Port_8579846_0 | SOURCEANDSINK | B - FL-Str.03_NK-KK-TK
Port_8579818_5 | SOURCEANDSINK | B - FL-Str.03_NK-KK-TK
Port_8579819_1 | SOURCEANDSINK | B - FL-Str.03_NK-KK-TK
Port_8579818_6 | SOURCEANDSINK | B - FL-Str.03_NK-KK-TK
Port_8608063_0 | SOURCEANDSINK | B - FL-Str.03_NK-KK-TK
Port_8579827_5 | SOURCEANDSINK | B - FL-Str.03_NK-KK-TK
Port_8579828_1 | SOURCEANDSINK | B - FL-Str.03_NK-KK-TK
Port_8579827_6 | SOURCEANDSINK | B - FL-Str.03_NK-KK-TK
Port_8607252_0 | SOURCEANDSINK | B - FL-Str.03_NK-KK-TK
Port_8579828_0 | SOURCEANDSINK | B - FL-Str.03_NK-KK-TK
Port_8579833_4 | SOURCEANDSINK | B - FL-Str.03_NK-KK-TK
Port_8579833_5 | SOURCEANDSINK | B - FL-Str.03_NK-KK-TK
Port_8579834_1 | SOURCEANDSINK | B - FL-Str.03_NK-KK-TK
Port_8579833_6 | SOURCEANDSINK | B - FL-Str.03_NK-KK-TK
Port_8607367_0 | SOURCEANDSINK | B - FL-Str.03_NK-KK-TK
Port_8579834_0 | SOURCEANDSINK | B - FL-Str.03_NK-KK-TK
Port_8579839_4 | SOURCEANDSINK | B - FL-Str.03_NK-KK-TK
Port_8579839_5 | SOURCEANDSINK | B - FL-Str.03_NK-KK-TK
Port_8579840_1 | SOURCEANDSINK | B - FL-Str.03_NK-KK-TK
Port_8579839_6 | SOURCEANDSINK | B - FL-Str.03_NK-KK-TK
Port_8607568_0 | SOURCEANDSINK | B - FL-Str.03_NK-KK-TK
Port_8579840_0 | SOURCEANDSINK | B - FL-Str.03_NK-KK-TK
Port_8579845_4 | SOURCEANDSINK | B - FL-Str.03_NK-KK-TK
Port_8579845_5 | SOURCEANDSINK | B - FL-Str.03_NK-KK-TK
Port_8579846_1 | SOURCEANDSINK | B - FL-Str.03_NK-KK-TK
Port_8579845_6 | SOURCEANDSINK | B - FL-Str.03_NK-KK-TK
Port_8607910_0 | SOURCEANDSINK | B - FL-Str.03_NK-KK-TK
Port_8579868_0 | SOURCEANDSINK | A - FL-Str.03_NK-KK-TK
Port_8599793_2 | SOURCEANDSINK | A - FL-Str.03_NK-KK-TK
Port_8579868_1 | SOURCEANDSINK | A - FL-Str.03_NK-KK-TK
Port_8599756_4 | SOURCEANDSINK | A - FL-Str.03_NK-KK-TK
Port_8579876_4 | SOURCEANDSINK | B - FL-Str.02_NK-KK-TK
Port_8579956_0 | SOURCEANDSINK | B - FL-Str.02_NK-KK-TK
Port_8579876_5 | SOURCEANDSINK | B - FL-Str.02_NK-KK-TK
Port_8579877_1 | SOURCEANDSINK | B - FL-Str.02_NK-KK-TK
Port_8579876_6 | SOURCEANDSINK | B - FL-Str.02_NK-KK-TK
Port_8603926_0 | SOURCEANDSINK | B - FL-Str.02_NK-KK-TK
Port_8579877_0 | SOURCEANDSINK | B - FL-Str.02_NK-KK-TK
Port_8593518_2 | SOURCEANDSINK | B - FL-Str.02_NK-KK-TK
Port_8579901_4 | SOURCEANDSINK | A - FL-Str.02_NK-KK-TK
Port_8579950_0 | SOURCEANDSINK | A - FL-Str.02_NK-KK-TK
Port_8579901_5 | SOURCEANDSINK | A - FL-Str.02_NK-KK-TK
Port_8579902_0 | SOURCEANDSINK | A - FL-Str.02_NK-KK-TK
Port_8579901_6 | SOURCEANDSINK | A - FL-Str.02_NK-KK-TK
Port_8603864_0 | SOURCEANDSINK | A - FL-Str.02_NK-KK-TK
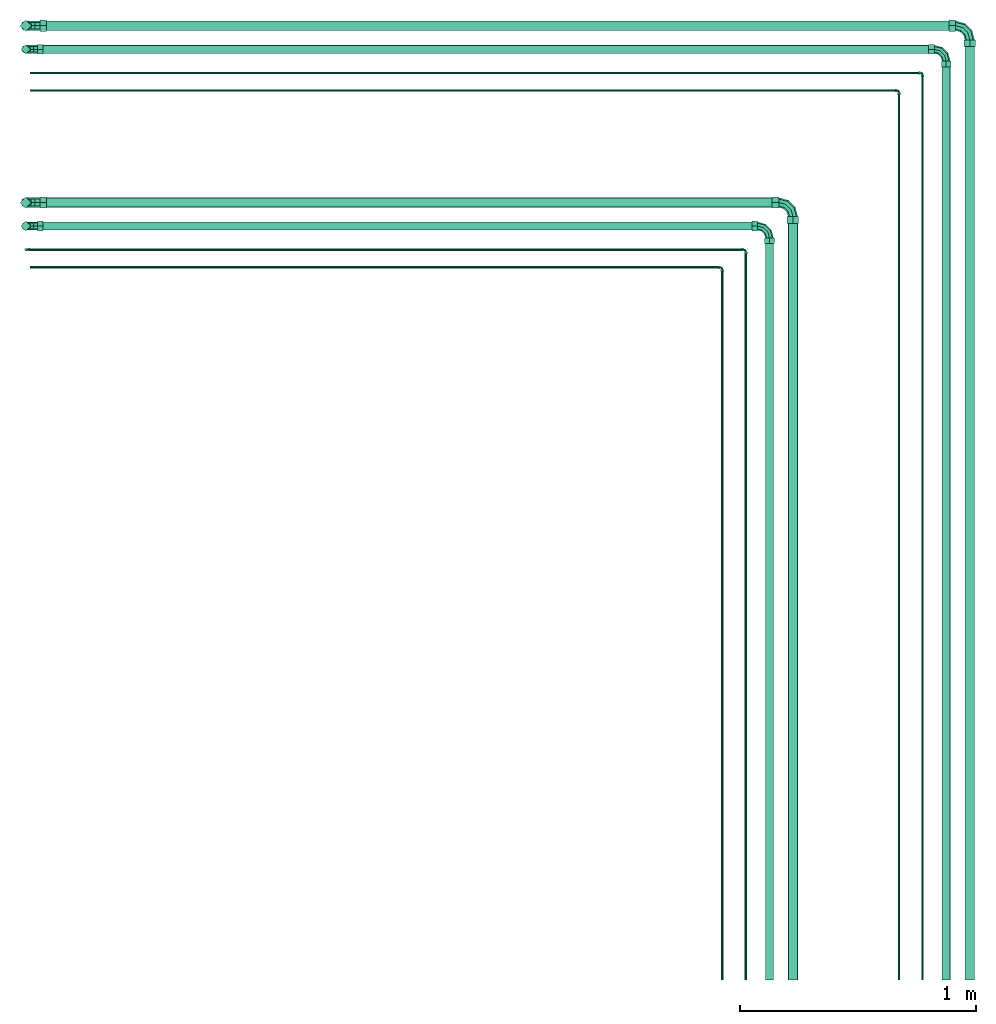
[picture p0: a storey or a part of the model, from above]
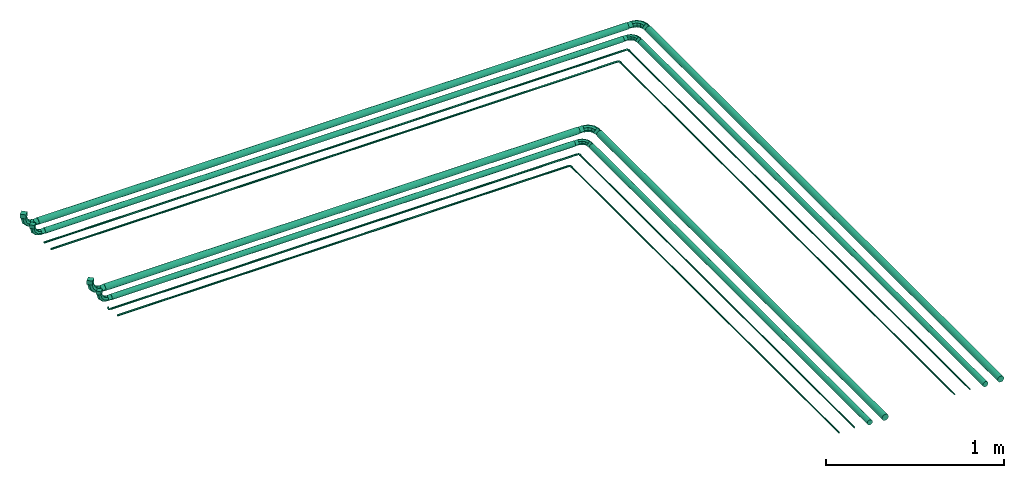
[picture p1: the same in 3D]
Properties of the parts of a building model (IFC2X3), part 3 of 7

# IfcDistributionPort (3410)
Name | FlowDirection | Group
Port_8579902_1 | SOURCEANDSINK | A - FL-Str.02_NK-KK-TK
Port_8593544_2 | SOURCEANDSINK | A - FL-Str.02_NK-KK-TK
Port_8579907_0 | SOURCEANDSINK | A - FL-Str.03_NK-KK-TK
Port_8579911_1 | SOURCEANDSINK | A - FL-Str.03_NK-KK-TK
Port_8579907_1 | SOURCEANDSINK | A - FL-Str.03_NK-KK-TK
Port_8579911_2 | SOURCEANDSINK | A - FL-Str.03_NK-KK-TK
Port_8579928_0 | SOURCEANDSINK | A - FL-Str.03_NK-KK-TK
Port_8579916_0 | SOURCEANDSINK | B - FL-Str.03_NK-KK-TK
Port_8579918_1 | SOURCEANDSINK | B - FL-Str.03_NK-KK-TK
Port_8579916_1 | SOURCEANDSINK | B - FL-Str.03_NK-KK-TK
Port_8579918_2 | SOURCEANDSINK | B - FL-Str.03_NK-KK-TK
Port_8579923_0 | SOURCEANDSINK | B - FL-Str.03_NK-KK-TK
Port_8579921_0 | SOURCEANDSINK | B - FL-Str.03_NK-KK-TK
Port_8579931_2 | SOURCEANDSINK | B - FL-Str.03_NK-KK-TK
Port_8579921_1 | SOURCEANDSINK | B - FL-Str.03_NK-KK-TK
Port_8579934_2 | SOURCEANDSINK | B - FL-Str.03_NK-KK-TK
Port_8579923_1 | SOURCEANDSINK | B - FL-Str.03_NK-KK-TK
Port_8579931_1 | SOURCEANDSINK | B - FL-Str.03_NK-KK-TK
Port_8579926_0 | SOURCEANDSINK | A - FL-Str.03_NK-KK-TK
Port_8579937_2 | SOURCEANDSINK | A - FL-Str.03_NK-KK-TK
Port_8579926_1 | SOURCEANDSINK | A - FL-Str.03_NK-KK-TK
Port_8599793_1 | SOURCEANDSINK | A - FL-Str.03_NK-KK-TK
Port_8579928_1 | SOURCEANDSINK | A - FL-Str.03_NK-KK-TK
Port_8579937_1 | SOURCEANDSINK | A - FL-Str.03_NK-KK-TK
Port_8579949_4 | SOURCEANDSINK | A - FL-Str.02_NK-KK-TK
Port_8579985_0 | SOURCEANDSINK | A - FL-Str.02_NK-KK-TK
Port_8579949_5 | SOURCEANDSINK | A - FL-Str.02_NK-KK-TK
Port_8579950_1 | SOURCEANDSINK | A - FL-Str.02_NK-KK-TK
Port_8579949_6 | SOURCEANDSINK | A - FL-Str.02_NK-KK-TK
Port_8605149_0 | SOURCEANDSINK | A - FL-Str.02_NK-KK-TK
Port_8579955_4 | SOURCEANDSINK | B - FL-Str.02_NK-KK-TK
Port_8579965_0 | SOURCEANDSINK | B - FL-Str.02_NK-KK-TK
Port_8579955_5 | SOURCEANDSINK | B - FL-Str.02_NK-KK-TK
Port_8579956_1 | SOURCEANDSINK | B - FL-Str.02_NK-KK-TK
Port_8579955_6 | SOURCEANDSINK | B - FL-Str.02_NK-KK-TK
Port_8604645_0 | SOURCEANDSINK | B - FL-Str.02_NK-KK-TK
Port_8579964_4 | SOURCEANDSINK | B - FL-Str.02_NK-KK-TK
Port_8580009_0 | SOURCEANDSINK | B - FL-Str.02_NK-KK-TK
Port_8579964_5 | SOURCEANDSINK | B - FL-Str.02_NK-KK-TK
Port_8579965_1 | SOURCEANDSINK | B - FL-Str.02_NK-KK-TK
Port_8579964_6 | SOURCEANDSINK | B - FL-Str.02_NK-KK-TK
Port_8609416_0 | SOURCEANDSINK | B - FL-Str.02_NK-KK-TK
Port_8579984_4 | SOURCEANDSINK | A - FL-Str.02_NK-KK-TK
Port_8580018_0 | SOURCEANDSINK | A - FL-Str.02_NK-KK-TK
Port_8579984_5 | SOURCEANDSINK | A - FL-Str.02_NK-KK-TK
Port_8579985_1 | SOURCEANDSINK | A - FL-Str.02_NK-KK-TK
Port_8579984_6 | SOURCEANDSINK | A - FL-Str.02_NK-KK-TK
Port_8609184_0 | SOURCEANDSINK | A - FL-Str.02_NK-KK-TK
Port_8580008_4 | SOURCEANDSINK | B - FL-Str.02_NK-KK-TK
Port_8580027_0 | SOURCEANDSINK | B - FL-Str.02_NK-KK-TK
Port_8580008_5 | SOURCEANDSINK | B - FL-Str.02_NK-KK-TK
Port_8580009_1 | SOURCEANDSINK | B - FL-Str.02_NK-KK-TK
Port_8580008_6 | SOURCEANDSINK | B - FL-Str.02_NK-KK-TK
Port_8609448_0 | SOURCEANDSINK | B - FL-Str.02_NK-KK-TK
Port_8580017_4 | SOURCEANDSINK | A - FL-Str.02_NK-KK-TK
Port_8580063_0 | SOURCEANDSINK | A - FL-Str.02_NK-KK-TK
Port_8580017_5 | SOURCEANDSINK | A - FL-Str.02_NK-KK-TK
Port_8580018_1 | SOURCEANDSINK | A - FL-Str.02_NK-KK-TK
Port_8580017_6 | SOURCEANDSINK | A - FL-Str.02_NK-KK-TK
Port_8609515_0 | SOURCEANDSINK | A - FL-Str.02_NK-KK-TK
Port_8580026_4 | SOURCEANDSINK | B - FL-Str.02_NK-KK-TK
Port_8580075_0 | SOURCEANDSINK | B - FL-Str.02_NK-KK-TK
Port_8580026_5 | SOURCEANDSINK | B - FL-Str.02_NK-KK-TK
Port_8580027_1 | SOURCEANDSINK | B - FL-Str.02_NK-KK-TK
Port_8580026_6 | SOURCEANDSINK | B - FL-Str.02_NK-KK-TK
Port_8609724_0 | SOURCEANDSINK | B - FL-Str.02_NK-KK-TK
Port_8580062_4 | SOURCEANDSINK | A - FL-Str.02_NK-KK-TK
Port_8580084_0 | SOURCEANDSINK | A - FL-Str.02_NK-KK-TK
Port_8580062_5 | SOURCEANDSINK | A - FL-Str.02_NK-KK-TK
Port_8580063_1 | SOURCEANDSINK | A - FL-Str.02_NK-KK-TK
Port_8580062_6 | SOURCEANDSINK | A - FL-Str.02_NK-KK-TK
Port_8610364_0 | SOURCEANDSINK | A - FL-Str.02_NK-KK-TK
Port_8580074_4 | SOURCEANDSINK | B - FL-Str.02_NK-KK-TK
Port_8580120_0 | SOURCEANDSINK | B - FL-Str.02_NK-KK-TK
Port_8580074_5 | SOURCEANDSINK | B - FL-Str.02_NK-KK-TK
Port_8580075_1 | SOURCEANDSINK | B - FL-Str.02_NK-KK-TK
Port_8580074_6 | SOURCEANDSINK | B - FL-Str.02_NK-KK-TK
Port_8610544_0 | SOURCEANDSINK | B - FL-Str.02_NK-KK-TK
Port_8580083_4 | SOURCEANDSINK | A - FL-Str.02_NK-KK-TK
Port_8580129_0 | SOURCEANDSINK | A - FL-Str.02_NK-KK-TK
Port_8580083_5 | SOURCEANDSINK | A - FL-Str.02_NK-KK-TK
Port_8580084_1 | SOURCEANDSINK | A - FL-Str.02_NK-KK-TK
Port_8580083_6 | SOURCEANDSINK | A - FL-Str.02_NK-KK-TK
Port_8610430_0 | SOURCEANDSINK | A - FL-Str.02_NK-KK-TK
Port_8580119_4 | SOURCEANDSINK | B - FL-Str.02_NK-KK-TK
Port_8580893_0 | SOURCEANDSINK | B - FL-Str.02_NK-KK-TK
Port_8580119_5 | SOURCEANDSINK | B - FL-Str.02_NK-KK-TK
Port_8580120_1 | SOURCEANDSINK | B - FL-Str.02_NK-KK-TK
Port_8580119_6 | SOURCEANDSINK | B - FL-Str.02_NK-KK-TK
Port_8610184_0 | SOURCEANDSINK | B - FL-Str.02_NK-KK-TK
Port_8580128_4 | SOURCEANDSINK | A - FL-Str.02_NK-KK-TK
Port_8580141_0 | SOURCEANDSINK | A - FL-Str.02_NK-KK-TK
Port_8580128_5 | SOURCEANDSINK | A - FL-Str.02_NK-KK-TK
Port_8580129_1 | SOURCEANDSINK | A - FL-Str.02_NK-KK-TK
Port_8580128_6 | SOURCEANDSINK | A - FL-Str.02_NK-KK-TK
Port_8609932_0 | SOURCEANDSINK | A - FL-Str.02_NK-KK-TK
Port_8580140_4 | SOURCEANDSINK | A - FL-Str.02_NK-KK-TK
Port_8614428_0 | SOURCEANDSINK | A - FL-Str.02_NK-KK-TK
Port_8580140_5 | SOURCEANDSINK | A - FL-Str.02_NK-KK-TK
Port_8580141_1 | SOURCEANDSINK | A - FL-Str.02_NK-KK-TK
Port_8580140_6 | SOURCEANDSINK | A - FL-Str.02_NK-KK-TK
Port_8610052_0 | SOURCEANDSINK | A - FL-Str.02_NK-KK-TK
Port_8580892_4 | SOURCEANDSINK | B - FL-Str.02_NK-KK-TK
Port_8614490_0 | SOURCEANDSINK | B - FL-Str.02_NK-KK-TK
Port_8580892_5 | SOURCEANDSINK | B - FL-Str.02_NK-KK-TK
Port_8580893_1 | SOURCEANDSINK | B - FL-Str.02_NK-KK-TK
Port_8580892_6 | SOURCEANDSINK | B - FL-Str.02_NK-KK-TK
Port_8611407_0 | SOURCEANDSINK | B - FL-Str.02_NK-KK-TK
Port_8582813_0 | SOURCEANDSINK | A - SL_KK
Port_8583716_4 | SOURCEANDSINK | A - SL_KK
Port_8582813_1 | SOURCEANDSINK | A - SL_KK
Port_8611641_2 | SOURCEANDSINK | A - SL_KK
Port_8582850_0 | SOURCEANDSINK | A - SL_KK
Port_8582994_2 | SOURCEANDSINK | A - SL_KK
Port_8582850_1 | SOURCEANDSINK | A - SL_KK
Port_8582853_0 | SOURCEANDSINK | A - SL_KK
Port_8604042_2 | SOURCEANDSINK | A - SL_KK
Port_8582853_1 | SOURCEANDSINK | A - SL_KK
Port_8604047_2 | SOURCEANDSINK | A - SL_KK
Port_8582856_0 | SOURCEANDSINK | A - SL_KK
Port_8582994_1 | SOURCEANDSINK | A - SL_KK
Port_8582856_1 | SOURCEANDSINK | A - SL_KK
Port_8604042_1 | SOURCEANDSINK | A - SL_KK
Port_8583607_4 | SOURCEANDSINK | A - SL_KK
Port_8634135_0 | SOURCEANDSINK | A - SL_KK
Port_8583607_5 | SOURCEANDSINK | A - SL_KK
Port_8583608_0 | SOURCEANDSINK | A - SL_KK
Port_8583607_6 | SOURCEANDSINK | A - SL_KK
Port_8605508_0 | SOURCEANDSINK | A - SL_KK
Port_8583608_1 | SOURCEANDSINK | A - SL_KK
Port_8598239_4 | SOURCEANDSINK | A - SL_KK
Port_8583716_5 | SOURCEANDSINK | A - SL_KK
Port_8583717_0 | SOURCEANDSINK | A - SL_KK
Port_8583716_6 | SOURCEANDSINK | A - SL_KK
Port_8605702_0 | SOURCEANDSINK | A - SL_KK
Port_8583717_1 | SOURCEANDSINK | A - SL_KK
Port_8634316_1 | SOURCEANDSINK | A - SL_KK
Port_8583914_4 | SOURCEANDSINK | A - SL_KK
Port_8606940_0 | SOURCEANDSINK | A - SL_KK
Port_8583914_5 | SOURCEANDSINK | A - SL_KK
Port_8583915_1 | SOURCEANDSINK | A - SL_KK
Port_8583914_6 | SOURCEANDSINK | A - SL_KK
Port_8606002_0 | SOURCEANDSINK | A - SL_KK
Port_8583915_0 | SOURCEANDSINK | A - SL_KK
Port_8584294_4 | SOURCEANDSINK | A - SL_KK
Port_8583937_4 | SOURCEANDSINK | A - SL_KK
Port_8584295_0 | SOURCEANDSINK | A - SL_KK
Port_8583937_5 | SOURCEANDSINK | A - SL_KK
Port_8584320_0 | SOURCEANDSINK | A - SL_KK
Port_8583937_6 | SOURCEANDSINK | A - SL_KK
Port_8606541_0 | SOURCEANDSINK | A - SL_KK
Port_8583938_0 | SOURCEANDSINK | A - SL_KK
Port_8584008_4 | SOURCEANDSINK | A - SL_KK
Port_8583938_1 | SOURCEANDSINK | A - SL_KK
Port_8604033_1 | SOURCEANDSINK | A - SL_KK
Port_8584008_5 | SOURCEANDSINK | A - SL_KK
Port_8584009_1 | SOURCEANDSINK | A - SL_KK
Port_8584008_6 | SOURCEANDSINK | A - SL_KK
Port_8604293_0 | SOURCEANDSINK | A - SL_KK
Port_8584009_0 | SOURCEANDSINK | A - SL_KK
Port_8584319_4 | SOURCEANDSINK | A - SL_KK
Port_8584294_5 | SOURCEANDSINK | A - SL_KK
Port_8584295_1 | SOURCEANDSINK | A - SL_KK
Port_8584294_6 | SOURCEANDSINK | A - SL_KK
Port_8606380_0 | SOURCEANDSINK | A - SL_KK
Port_8584319_5 | SOURCEANDSINK | A - SL_KK
Port_8584320_1 | SOURCEANDSINK | A - SL_KK
Port_8584319_6 | SOURCEANDSINK | A - SL_KK
Port_8604544_0 | SOURCEANDSINK | A - SL_KK
Port_8585072_4 | SOURCEANDSINK | B - SL_KK
Port_8585101_0 | SOURCEANDSINK | B - SL_KK
Port_8585072_5 | SOURCEANDSINK | B - SL_KK
Port_8585122_0 | SOURCEANDSINK | B - SL_KK
Port_8585072_6 | SOURCEANDSINK | B - SL_KK
Port_8605384_0 | SOURCEANDSINK | B - SL_KK
Port_8585100_4 | SOURCEANDSINK | B - SL_KK
Port_8585994_0 | SOURCEANDSINK | B - SL_KK
Port_8585100_5 | SOURCEANDSINK | B - SL_KK
Port_8585101_1 | SOURCEANDSINK | B - SL_KK
Port_8585100_6 | SOURCEANDSINK | B - SL_KK
Port_8605202_0 | SOURCEANDSINK | B - SL_KK
Port_8585107_0 | SOURCEANDSINK | B - SL_KK
Port_8586322_4 | SOURCEANDSINK | B - SL_KK
Port_8585107_1 | SOURCEANDSINK | B - SL_KK
Port_8585184_4 | SOURCEANDSINK | B - SL_KK
Port_8585122_1 | SOURCEANDSINK | B - SL_KK
Port_8611577_1 | SOURCEANDSINK | B - SL_KK
Port_8585136_4 | SOURCEANDSINK | B - SL_KK
Port_8585185_0 | SOURCEANDSINK | B - SL_KK
Port_8585136_5 | SOURCEANDSINK | B - SL_KK
Port_8585137_1 | SOURCEANDSINK | B - SL_KK
Port_8585136_6 | SOURCEANDSINK | B - SL_KK
Port_8606172_0 | SOURCEANDSINK | B - SL_KK
Port_8585137_0 | SOURCEANDSINK | B - SL_KK
Port_8585142_4 | SOURCEANDSINK | B - SL_KK
Port_8585142_5 | SOURCEANDSINK | B - SL_KK
Port_8585143_0 | SOURCEANDSINK | B - SL_KK
Port_8585142_6 | SOURCEANDSINK | B - SL_KK
Port_8606239_0 | SOURCEANDSINK | B - SL_KK
Port_8585143_1 | SOURCEANDSINK | B - SL_KK
Port_8585148_4 | SOURCEANDSINK | B - SL_KK
Port_8585148_5 | SOURCEANDSINK | B - SL_KK
Port_8585149_1 | SOURCEANDSINK | B - SL_KK
Port_8585148_6 | SOURCEANDSINK | B - SL_KK
Port_8606487_0 | SOURCEANDSINK | B - SL_KK
Port_8585149_0 | SOURCEANDSINK | B - SL_KK
Port_8585154_4 | SOURCEANDSINK | B - SL_KK
Port_8585154_5 | SOURCEANDSINK | B - SL_KK
Port_8585155_1 | SOURCEANDSINK | B - SL_KK
Port_8585154_6 | SOURCEANDSINK | B - SL_KK
Port_8604477_0 | SOURCEANDSINK | B - SL_KK
Port_8585155_0 | SOURCEANDSINK | B - SL_KK
Port_8585160_4 | SOURCEANDSINK | B - SL_KK
Port_8585160_5 | SOURCEANDSINK | B - SL_KK
Port_8585161_1 | SOURCEANDSINK | B - SL_KK
Port_8585160_6 | SOURCEANDSINK | B - SL_KK
Port_8604598_0 | SOURCEANDSINK | B - SL_KK
Port_8585161_0 | SOURCEANDSINK | B - SL_KK
Port_8603959_1 | SOURCEANDSINK | B - SL_KK
Port_8585184_5 | SOURCEANDSINK | B - SL_KK
Port_8585185_1 | SOURCEANDSINK | B - SL_KK
Port_8585184_6 | SOURCEANDSINK | B - SL_KK
Port_8605888_0 | SOURCEANDSINK | B - SL_KK
Port_8585993_4 | SOURCEANDSINK | B - SL_KK
Port_8586323_0 | SOURCEANDSINK | B - SL_KK
Port_8585993_5 | SOURCEANDSINK | B - SL_KK
Port_8585994_1 | SOURCEANDSINK | B - SL_KK
Port_8585993_6 | SOURCEANDSINK | B - SL_KK
Port_8604698_0 | SOURCEANDSINK | B - SL_KK
Port_8586322_5 | SOURCEANDSINK | B - SL_KK
Port_8586323_1 | SOURCEANDSINK | B - SL_KK
Port_8586322_6 | SOURCEANDSINK | B - SL_KK
Port_8605834_0 | SOURCEANDSINK | B - SL_KK
Port_8586417_0 | SOURCEANDSINK | B - SL_KK
Port_8586461_2 | SOURCEANDSINK | B - SL_KK
Port_8586417_1 | SOURCEANDSINK | B - SL_KK
Port_8586420_0 | SOURCEANDSINK | B - SL_KK
Port_8603968_2 | SOURCEANDSINK | B - SL_KK
Port_8586420_1 | SOURCEANDSINK | B - SL_KK
Port_8603973_2 | SOURCEANDSINK | B - SL_KK
Port_8586423_0 | SOURCEANDSINK | B - SL_KK
Port_8586461_1 | SOURCEANDSINK | B - SL_KK
Port_8586423_1 | SOURCEANDSINK | B - SL_KK
Port_8603968_1 | SOURCEANDSINK | B - SL_KK
Port_8586600_4 | SOURCEANDSINK | A - SL_NK-Str.02
Port_8586626_0 | SOURCEANDSINK | A - SL_NK-Str.02
Port_8586600_5 | SOURCEANDSINK | A - SL_NK-Str.02
Port_8595055_0 | SOURCEANDSINK | A - SL_NK-Str.02
Port_8586600_6 | SOURCEANDSINK | A - SL_NK-Str.02
Port_8608117_0 | SOURCEANDSINK | A - SL_NK-Str.02
Port_8586614_0 | SOURCEANDSINK | A - SL_NK-Str.02
Port_8586619_4 | SOURCEANDSINK | A - SL_NK-Str.02
Port_8586614_1 | SOURCEANDSINK | A - SL_NK-Str.02
Port_8634841_2 | SOURCEANDSINK | A - SL_NK-Str.02
Port_8586619_5 | SOURCEANDSINK | A - SL_NK-Str.02
Port_8586620_1 | SOURCEANDSINK | A - SL_NK-Str.02
Port_8586619_6 | SOURCEANDSINK | A - SL_NK-Str.02
Port_8607625_0 | SOURCEANDSINK | A - SL_NK-Str.02
Port_8586620_0 | SOURCEANDSINK | A - SL_NK-Str.02
Port_8586625_4 | SOURCEANDSINK | A - SL_NK-Str.02
Port_8586625_5 | SOURCEANDSINK | A - SL_NK-Str.02
Port_8586626_1 | SOURCEANDSINK | A - SL_NK-Str.02
Port_8586625_6 | SOURCEANDSINK | A - SL_NK-Str.02
Port_8607829_0 | SOURCEANDSINK | A - SL_NK-Str.02
Port_8586659_4 | SOURCEANDSINK | B - SL_NK-Str.02
Port_8586670_0 | SOURCEANDSINK | B - SL_NK-Str.02
Port_8586659_5 | SOURCEANDSINK | B - SL_NK-Str.02
Port_8599637_0 | SOURCEANDSINK | B - SL_NK-Str.02
Port_8586659_6 | SOURCEANDSINK | B - SL_NK-Str.02
Port_8608941_0 | SOURCEANDSINK | B - SL_NK-Str.02
Port_8586660_0 | SOURCEANDSINK | B - SL_NK-Str.02
Port_8599680_2 | SOURCEANDSINK | B - SL_NK-Str.02
Port_8586660_1 | SOURCEANDSINK | B - SL_NK-Str.02
Port_8599636_4 | SOURCEANDSINK | B - SL_NK-Str.02
Port_8586669_4 | SOURCEANDSINK | B - SL_NK-Str.02
Port_8586676_0 | SOURCEANDSINK | B - SL_NK-Str.02
Port_8586669_5 | SOURCEANDSINK | B - SL_NK-Str.02
Port_8586670_1 | SOURCEANDSINK | B - SL_NK-Str.02
Port_8586669_6 | SOURCEANDSINK | B - SL_NK-Str.02
Port_8608231_0 | SOURCEANDSINK | B - SL_NK-Str.02
Port_8586675_4 | SOURCEANDSINK | B - SL_NK-Str.02
Port_8586703_0 | SOURCEANDSINK | B - SL_NK-Str.02
Port_8586675_5 | SOURCEANDSINK | B - SL_NK-Str.02
Port_8586676_1 | SOURCEANDSINK | B - SL_NK-Str.02
Port_8586675_6 | SOURCEANDSINK | B - SL_NK-Str.02
Port_8608090_0 | SOURCEANDSINK | B - SL_NK-Str.02
Port_8586691_0 | SOURCEANDSINK | B - SL_NK-Str.02
Port_8586696_4 | SOURCEANDSINK | B - SL_NK-Str.02
Port_8586691_1 | SOURCEANDSINK | B - SL_NK-Str.02
Port_8607309_2 | SOURCEANDSINK | B - SL_NK-Str.02
Port_8586696_5 | SOURCEANDSINK | B - SL_NK-Str.02
Port_8586697_1 | SOURCEANDSINK | B - SL_NK-Str.02
Port_8586696_6 | SOURCEANDSINK | B - SL_NK-Str.02
Port_8607511_0 | SOURCEANDSINK | B - SL_NK-Str.02
Port_8586697_0 | SOURCEANDSINK | B - SL_NK-Str.02
Port_8586702_4 | SOURCEANDSINK | B - SL_NK-Str.02
Port_8586702_5 | SOURCEANDSINK | B - SL_NK-Str.02
Port_8586703_1 | SOURCEANDSINK | B - SL_NK-Str.02
Port_8586702_6 | SOURCEANDSINK | B - SL_NK-Str.02
Port_8607883_0 | SOURCEANDSINK | B - SL_NK-Str.02
Port_8586725_0 | SOURCEANDSINK | A - SL_NK-Str.02
Port_8599949_2 | SOURCEANDSINK | A - SL_NK-Str.02
Port_8586725_1 | SOURCEANDSINK | A - SL_NK-Str.02
Port_8599907_4 | SOURCEANDSINK | A - SL_NK-Str.02
Port_8586734_0 | SOURCEANDSINK | B - SL_NK-Str.01
Port_8593915_2 | SOURCEANDSINK | B - SL_NK-Str.01
Port_8586734_1 | SOURCEANDSINK | B - SL_NK-Str.01
Port_8587913_4 | SOURCEANDSINK | B - SL_NK-Str.01
Port_8586759_0 | SOURCEANDSINK | A - SL_NK-Str.01
Port_8594525_2 | SOURCEANDSINK | A - SL_NK-Str.01
Port_8586759_1 | SOURCEANDSINK | A - SL_NK-Str.01
Port_8587733_4 | SOURCEANDSINK | A - SL_NK-Str.01
Port_8586839_0 | SOURCEANDSINK | A - SL_NK-Str.01
Port_8590802_4 | SOURCEANDSINK | A - SL_NK-Str.01
Port_8586839_1 | SOURCEANDSINK | A - SL_NK-Str.01
Port_8587733_5 | SOURCEANDSINK | A - SL_NK-Str.01
Port_8586895_4 | SOURCEANDSINK | B - SL_NK-Str.01
Port_8591986_0 | SOURCEANDSINK | B - SL_NK-Str.01
Port_8586895_5 | SOURCEANDSINK | B - SL_NK-Str.01
Port_8591842_0 | SOURCEANDSINK | B - SL_NK-Str.01
Port_8586895_6 | SOURCEANDSINK | B - SL_NK-Str.01
Port_8610571_0 | SOURCEANDSINK | B - SL_NK-Str.01
Port_8586896_0 | SOURCEANDSINK | B - SL_NK-Str.01
Port_8590502_4 | SOURCEANDSINK | B - SL_NK-Str.01
Port_8586896_1 | SOURCEANDSINK | B - SL_NK-Str.01
Port_8587913_5 | SOURCEANDSINK | B - SL_NK-Str.01
Port_8586904_4 | SOURCEANDSINK | A - SL_NK-Str.01
Port_8592219_0 | SOURCEANDSINK | A - SL_NK-Str.01
Port_8586904_5 | SOURCEANDSINK | A - SL_NK-Str.01
Port_8592620_0 | SOURCEANDSINK | A - SL_NK-Str.01
Port_8586904_6 | SOURCEANDSINK | A - SL_NK-Str.01
Port_8610457_0 | SOURCEANDSINK | A - SL_NK-Str.01
Port_8586941_0 | SOURCEANDSINK | B - SL_NK-Str.01
Port_8591985_4 | SOURCEANDSINK | B - SL_NK-Str.01
Port_8586941_1 | SOURCEANDSINK | B - SL_NK-Str.01
Port_8586970_5 | SOURCEANDSINK | B - SL_NK-Str.01
Port_8586950_0 | SOURCEANDSINK | A - SL_NK-Str.01
Port_8592218_4 | SOURCEANDSINK | A - SL_NK-Str.01
Port_8586950_1 | SOURCEANDSINK | A - SL_NK-Str.01
Port_8586961_5 | SOURCEANDSINK | A - SL_NK-Str.01
Port_8586961_4 | SOURCEANDSINK | A - SL_NK-Str.01
Port_8614468_0 | SOURCEANDSINK | A - SL_NK-Str.01
Port_8586961_6 | SOURCEANDSINK | A - SL_NK-Str.01
Port_8610025_0 | SOURCEANDSINK | A - SL_NK-Str.01
Port_8586970_4 | SOURCEANDSINK | B - SL_NK-Str.01
Port_8592017_0 | SOURCEANDSINK | B - SL_NK-Str.01
Port_8586970_6 | SOURCEANDSINK | B - SL_NK-Str.01
Port_8611451_0 | SOURCEANDSINK | B - SL_NK-Str.01
Port_8587733_6 | SOURCEANDSINK | A - SL_NK-Str.01
Port_8604944_0 | SOURCEANDSINK | A - SL_NK-Str.01
Port_8587913_6 | SOURCEANDSINK | B - SL_NK-Str.01
Port_8605070_0 | SOURCEANDSINK | B - SL_NK-Str.01
Port_8587938_0 | SOURCEANDSINK | A - SL_NK-Str.02
Port_8588627_1 | SOURCEANDSINK | A - SL_NK-Str.02
Port_8587938_1 | SOURCEANDSINK | A - SL_NK-Str.02
Port_8587947_0 | SOURCEANDSINK | B - SL_NK-Str.02
Port_8588616_1 | SOURCEANDSINK | B - SL_NK-Str.02
Port_8587947_1 | SOURCEANDSINK | B - SL_NK-Str.02
Port_8587952_0 | SOURCEANDSINK | B - SL_NK-Str.02
Port_8599680_1 | SOURCEANDSINK | B - SL_NK-Str.02
Port_8587952_1 | SOURCEANDSINK | B - SL_NK-Str.02
Port_8588643_2 | SOURCEANDSINK | B - SL_NK-Str.02
Port_8587954_0 | SOURCEANDSINK | B - SL_NK-Str.02
Port_8588616_2 | SOURCEANDSINK | B - SL_NK-Str.02
Port_8587954_1 | SOURCEANDSINK | B - SL_NK-Str.02
Port_8588643_1 | SOURCEANDSINK | B - SL_NK-Str.02
Port_8587957_0 | SOURCEANDSINK | A - SL_NK-Str.02
Port_8599949_1 | SOURCEANDSINK | A - SL_NK-Str.02
Port_8587957_1 | SOURCEANDSINK | A - SL_NK-Str.02
Port_8588653_2 | SOURCEANDSINK | A - SL_NK-Str.02
Port_8587959_0 | SOURCEANDSINK | A - SL_NK-Str.02
Port_8588653_1 | SOURCEANDSINK | A - SL_NK-Str.02
Port_8587959_1 | SOURCEANDSINK | A - SL_NK-Str.02
Port_8588627_2 | SOURCEANDSINK | A - SL_NK-Str.02
Port_8589466_0 | SOURCEANDSINK | B - SL_TK
Port_8593114_2 | SOURCEANDSINK | B - SL_TK
Port_8589466_1 | SOURCEANDSINK | B - SL_TK
Port_8589890_4 | SOURCEANDSINK | B - SL_TK
Port_8589527_0 | SOURCEANDSINK | A - SL_TK
Port_8589758_4 | SOURCEANDSINK | A - SL_TK
Port_8589527_1 | SOURCEANDSINK | A - SL_TK
Port_8609870_2 | SOURCEANDSINK | A - SL_TK
Port_8589758_5 | SOURCEANDSINK | A - SL_TK
Port_8615573_0 | SOURCEANDSINK | A - SL_TK
Port_8589758_6 | SOURCEANDSINK | A - SL_TK
Port_8610397_0 | SOURCEANDSINK | A - SL_TK
Port_8589759_0 | SOURCEANDSINK | A - SL_TK
Port_8615621_2 | SOURCEANDSINK | A - SL_TK
Port_8589759_1 | SOURCEANDSINK | A - SL_TK
Port_8615572_4 | SOURCEANDSINK | A - SL_TK
Port_8589853_4 | SOURCEANDSINK | B - SL_TK
Port_8589891_0 | SOURCEANDSINK | B - SL_TK
Port_8589853_5 | SOURCEANDSINK | B - SL_TK
Port_8589854_0 | SOURCEANDSINK | B - SL_TK
Port_8589853_6 | SOURCEANDSINK | B - SL_TK
Port_8609757_0 | SOURCEANDSINK | B - SL_TK
Port_8589854_1 | SOURCEANDSINK | B - SL_TK
Port_8610116_2 | SOURCEANDSINK | B - SL_TK
Port_8589890_5 | SOURCEANDSINK | B - SL_TK
Port_8589891_1 | SOURCEANDSINK | B - SL_TK
Port_8589890_6 | SOURCEANDSINK | B - SL_TK
Port_8609356_0 | SOURCEANDSINK | B - SL_TK
Port_8590502_5 | SOURCEANDSINK | B - SL_NK-Str.01
Port_8590503_1 | SOURCEANDSINK | B - SL_NK-Str.01
Port_8590502_6 | SOURCEANDSINK | B - SL_NK-Str.01
Port_8609383_0 | SOURCEANDSINK | B - SL_NK-Str.01
Port_8590503_0 | SOURCEANDSINK | B - SL_NK-Str.01
Port_8591841_4 | SOURCEANDSINK | B - SL_NK-Str.01
Port_8590802_5 | SOURCEANDSINK | A - SL_NK-Str.01
Port_8590803_1 | SOURCEANDSINK | A - SL_NK-Str.01
Port_8590802_6 | SOURCEANDSINK | A - SL_NK-Str.01
Port_8609151_0 | SOURCEANDSINK | A - SL_NK-Str.01
Port_8590803_0 | SOURCEANDSINK | A - SL_NK-Str.01
Port_8592661_4 | SOURCEANDSINK | A - SL_NK-Str.01
Port_8591841_5 | SOURCEANDSINK | B - SL_NK-Str.01
Port_8591842_1 | SOURCEANDSINK | B - SL_NK-Str.01
Port_8591841_6 | SOURCEANDSINK | B - SL_NK-Str.01
Port_8609790_0 | SOURCEANDSINK | B - SL_NK-Str.01
Port_8591985_5 | SOURCEANDSINK | B - SL_NK-Str.01
Port_8591986_1 | SOURCEANDSINK | B - SL_NK-Str.01
Port_8591985_6 | SOURCEANDSINK | B - SL_NK-Str.01
Port_8611525_0 | SOURCEANDSINK | B - SL_NK-Str.01
Port_8592016_4 | SOURCEANDSINK | B - SL_NK-Str.01
Port_8614603_0 | SOURCEANDSINK | B - SL_NK-Str.01
Port_8592016_5 | SOURCEANDSINK | B - SL_NK-Str.01
Port_8592017_1 | SOURCEANDSINK | B - SL_NK-Str.01
Port_8592016_6 | SOURCEANDSINK | B - SL_NK-Str.01
Port_8611478_0 | SOURCEANDSINK | B - SL_NK-Str.01
Port_8592218_5 | SOURCEANDSINK | A - SL_NK-Str.01
Port_8592219_1 | SOURCEANDSINK | A - SL_NK-Str.01
Port_8592218_6 | SOURCEANDSINK | A - SL_NK-Str.01
Port_8611320_0 | SOURCEANDSINK | A - SL_NK-Str.01
Port_8592619_4 | SOURCEANDSINK | A - SL_NK-Str.01
Port_8592662_0 | SOURCEANDSINK | A - SL_NK-Str.01
Port_8592619_5 | SOURCEANDSINK | A - SL_NK-Str.01
Port_8592620_1 | SOURCEANDSINK | A - SL_NK-Str.01
Port_8592619_6 | SOURCEANDSINK | A - SL_NK-Str.01
Port_8610337_0 | SOURCEANDSINK | A - SL_NK-Str.01
Port_8592661_5 | SOURCEANDSINK | A - SL_NK-Str.01
Port_8592662_1 | SOURCEANDSINK | A - SL_NK-Str.01
Port_8592661_6 | SOURCEANDSINK | A - SL_NK-Str.01
Port_8609544_0 | SOURCEANDSINK | A - SL_NK-Str.01
Port_8593001_0 | SOURCEANDSINK | A - SL_NK-Str.01
Port_8593552_1 | SOURCEANDSINK | A - SL_NK-Str.01
Port_8593001_1 | SOURCEANDSINK | A - SL_NK-Str.01
Port_8593004_0 | SOURCEANDSINK | A - SL_NK-Str.01
Port_8593547_2 | SOURCEANDSINK | A - SL_NK-Str.01
Port_8593004_1 | SOURCEANDSINK | A - SL_NK-Str.01
Port_8593552_2 | SOURCEANDSINK | A - SL_NK-Str.01
Port_8593007_0 | SOURCEANDSINK | B - SL_NK-Str.01
Port_8593508_1 | SOURCEANDSINK | B - SL_NK-Str.01
Port_8593007_1 | SOURCEANDSINK | B - SL_NK-Str.01
Port_8593010_0 | SOURCEANDSINK | B - SL_NK-Str.01
Port_8593503_2 | SOURCEANDSINK | B - SL_NK-Str.01
Port_8593010_1 | SOURCEANDSINK | B - SL_NK-Str.01
Port_8593508_2 | SOURCEANDSINK | B - SL_NK-Str.01
Port_8593013_0 | SOURCEANDSINK | A - FL-Str.02_NK-KK-TK
Port_8593478_1 | SOURCEANDSINK | A - FL-Str.02_NK-KK-TK
Port_8593013_1 | SOURCEANDSINK | A - FL-Str.02_NK-KK-TK
Port_8593016_0 | SOURCEANDSINK | A - FL-Str.02_NK-KK-TK
Port_8593478_2 | SOURCEANDSINK | A - FL-Str.02_NK-KK-TK
Port_8593016_1 | SOURCEANDSINK | A - FL-Str.02_NK-KK-TK
Port_8593539_1 | SOURCEANDSINK | A - FL-Str.02_NK-KK-TK
Port_8593019_0 | SOURCEANDSINK | B - FL-Str.02_NK-KK-TK
Port_8593493_1 | SOURCEANDSINK | B - FL-Str.02_NK-KK-TK
Port_8593019_1 | SOURCEANDSINK | B - FL-Str.02_NK-KK-TK
Port_8593022_0 | SOURCEANDSINK | B - FL-Str.02_NK-KK-TK
Port_8593493_2 | SOURCEANDSINK | B - FL-Str.02_NK-KK-TK
Port_8593022_1 | SOURCEANDSINK | B - FL-Str.02_NK-KK-TK
Port_8593513_1 | SOURCEANDSINK | B - FL-Str.02_NK-KK-TK
Port_8593052_0 | SOURCEANDSINK | A - SL_TK
Port_8593483_1 | SOURCEANDSINK | A - SL_TK
Port_8593052_1 | SOURCEANDSINK | A - SL_TK
Port_8593055_0 | SOURCEANDSINK | A - SL_TK
Port_8593483_2 | SOURCEANDSINK | A - SL_TK
Port_8593055_1 | SOURCEANDSINK | A - SL_TK
Port_8593531_1 | SOURCEANDSINK | A - SL_TK
Port_8593058_0 | SOURCEANDSINK | B - SL_TK
Port_8593526_1 | SOURCEANDSINK | B - SL_TK
Port_8593058_1 | SOURCEANDSINK | B - SL_TK
Port_8593061_0 | SOURCEANDSINK | B - SL_TK
Port_8593521_2 | SOURCEANDSINK | B - SL_TK
Port_8593061_1 | SOURCEANDSINK | B - SL_TK
Port_8593526_2 | SOURCEANDSINK | B - SL_TK
Port_8593085_0 | SOURCEANDSINK | B - FL-Str.02_NK-KK-TK
Port_8593513_2 | SOURCEANDSINK | B - FL-Str.02_NK-KK-TK
Port_8593085_1 | SOURCEANDSINK | B - FL-Str.02_NK-KK-TK
Port_8593518_1 | SOURCEANDSINK | B - FL-Str.02_NK-KK-TK
Port_8593088_0 | SOURCEANDSINK | B - SL_NK-Str.01
Port_8593503_1 | SOURCEANDSINK | B - SL_NK-Str.01
Port_8593088_1 | SOURCEANDSINK | B - SL_NK-Str.01
Port_8593915_1 | SOURCEANDSINK | B - SL_NK-Str.01
Port_8593090_0 | SOURCEANDSINK | B - SL_TK
Port_8593521_1 | SOURCEANDSINK | B - SL_TK
Port_8593090_1 | SOURCEANDSINK | B - SL_TK
Port_8593114_1 | SOURCEANDSINK | B - SL_TK
Port_8593135_0 | SOURCEANDSINK | A - SL_NK-Str.01
Port_8593547_1 | SOURCEANDSINK | A - SL_NK-Str.01
Port_8593135_1 | SOURCEANDSINK | A - SL_NK-Str.01
Port_8594525_1 | SOURCEANDSINK | A - SL_NK-Str.01
Port_8593137_0 | SOURCEANDSINK | A - SL_TK
Port_8593531_2 | SOURCEANDSINK | A - SL_TK
Port_8593137_1 | SOURCEANDSINK | A - SL_TK
Port_8615621_1 | SOURCEANDSINK | A - SL_TK
Port_8593230_0 | SOURCEANDSINK | A - FL-Str.02_NK-KK-TK
Port_8593539_2 | SOURCEANDSINK | A - FL-Str.02_NK-KK-TK
Port_8593230_1 | SOURCEANDSINK | A - FL-Str.02_NK-KK-TK
Port_8593544_1 | SOURCEANDSINK | A - FL-Str.02_NK-KK-TK
Port_8595055_1 | SOURCEANDSINK | A - SL_NK-Str.02
Port_8600181_4 | SOURCEANDSINK | A - SL_NK-Str.02
Port_8596979_0 | SOURCEANDSINK | A - Druckleitung Gaskühler
Port_8597337_2 | SOURCEANDSINK | A - Druckleitung Gaskühler
Port_8596979_1 | SOURCEANDSINK | A - Druckleitung Gaskühler
Port_8597342_2 | SOURCEANDSINK | A - Druckleitung Gaskühler
Port_8597207_0 | SOURCEANDSINK | A - Kondensatleitung Gaskühler
Port_8597350_1 | SOURCEANDSINK | A - Kondensatleitung Gaskühler
Port_8597207_1 | SOURCEANDSINK | A - Kondensatleitung Gaskühler
Port_8597353_2 | SOURCEANDSINK | A - Kondensatleitung Gaskühler
Port_8597209_0 | SOURCEANDSINK | A - Druckleitung Gaskühler
Port_8597342_1 | SOURCEANDSINK | A - Druckleitung Gaskühler
Port_8597209_1 | SOURCEANDSINK | A - Druckleitung Gaskühler
Port_8597248_1 | SOURCEANDSINK | A - Druckleitung Gaskühler
Port_8598239_5 | SOURCEANDSINK | A - SL_KK
Port_8598240_0 | SOURCEANDSINK | A - SL_KK
Port_8598239_6 | SOURCEANDSINK | A - SL_KK
Port_8604745_0 | SOURCEANDSINK | A - SL_KK
Port_8598240_1 | SOURCEANDSINK | A - SL_KK
Port_8606939_4 | SOURCEANDSINK | A - SL_KK
Port_8599349_0 | SOURCEANDSINK | A - FL-Str.03_NK-KK-TK
Port_8608146_2 | SOURCEANDSINK | A - FL-Str.03_NK-KK-TK
Port_8599349_1 | SOURCEANDSINK | A - FL-Str.03_NK-KK-TK
Port_8622729_1 | SOURCEANDSINK | A - FL-Str.03_NK-KK-TK
Port_8599352_0 | SOURCEANDSINK | A - FL-Str.03_NK-KK-TK
Port_8607858_2 | SOURCEANDSINK | A - FL-Str.03_NK-KK-TK
Port_8599352_1 | SOURCEANDSINK | A - FL-Str.03_NK-KK-TK
Port_8622597_1 | SOURCEANDSINK | A - FL-Str.03_NK-KK-TK
Port_8599355_0 | SOURCEANDSINK | A - FL-Str.03_NK-KK-TK
Port_8607684_2 | SOURCEANDSINK | A - FL-Str.03_NK-KK-TK
Port_8599355_1 | SOURCEANDSINK | A - FL-Str.03_NK-KK-TK
Port_8622900_1 | SOURCEANDSINK | A - FL-Str.03_NK-KK-TK
Port_8599358_0 | SOURCEANDSINK | A - FL-Str.03_NK-KK-TK
Port_8626827_1 | SOURCEANDSINK | A - FL-Str.03_NK-KK-TK
Port_8599361_0 | SOURCEANDSINK | A - FL-Str.03_NK-KK-TK
Port_8623227_2 | SOURCEANDSINK | A - FL-Str.03_NK-KK-TK
Port_8599361_1 | SOURCEANDSINK | A - FL-Str.03_NK-KK-TK
Port_8623232_2 | SOURCEANDSINK | A - FL-Str.03_NK-KK-TK
Port_8599364_0 | SOURCEANDSINK | A - FL-Str.03_NK-KK-TK
Port_8601363_1 | SOURCEANDSINK | A - FL-Str.03_NK-KK-TK
Port_8599364_1 | SOURCEANDSINK | A - FL-Str.03_NK-KK-TK
Port_8623385_1 | SOURCEANDSINK | A - FL-Str.03_NK-KK-TK
Port_8599367_0 | SOURCEANDSINK | A - FL-Str.03_NK-KK-TK
Port_8608668_1 | SOURCEANDSINK | A - FL-Str.03_NK-KK-TK
Port_8599367_1 | SOURCEANDSINK | A - FL-Str.03_NK-KK-TK
Port_8608671_2 | SOURCEANDSINK | A - FL-Str.03_NK-KK-TK
Port_8599369_0 | SOURCEANDSINK | A - FL-Str.03_NK-KK-TK
Port_8624965_2 | SOURCEANDSINK | A - FL-Str.03_NK-KK-TK
Port_8599369_1 | SOURCEANDSINK | A - FL-Str.03_NK-KK-TK
Port_8624970_2 | SOURCEANDSINK | A - FL-Str.03_NK-KK-TK
Port_8599373_0 | SOURCEANDSINK | A - FL-Str.03_NK-KK-TK
Port_8608668_2 | SOURCEANDSINK | A - FL-Str.03_NK-KK-TK
Port_8599373_1 | SOURCEANDSINK | A - FL-Str.03_NK-KK-TK
Port_8624867_1 | SOURCEANDSINK | A - FL-Str.03_NK-KK-TK
Port_8599376_0 | SOURCEANDSINK | B - FL-Str.03_NK-KK-TK
Port_8621697_2 | SOURCEANDSINK | B - FL-Str.03_NK-KK-TK
Port_8599376_1 | SOURCEANDSINK | B - FL-Str.03_NK-KK-TK
Port_8621702_2 | SOURCEANDSINK | B - FL-Str.03_NK-KK-TK
Port_8599379_0 | SOURCEANDSINK | B - FL-Str.03_NK-KK-TK
Port_8608065_2 | SOURCEANDSINK | B - FL-Str.03_NK-KK-TK
Port_8599379_1 | SOURCEANDSINK | B - FL-Str.03_NK-KK-TK
Port_8621793_1 | SOURCEANDSINK | B - FL-Str.03_NK-KK-TK
Port_8599382_0 | SOURCEANDSINK | B - FL-Str.03_NK-KK-TK
Port_8607912_2 | SOURCEANDSINK | B - FL-Str.03_NK-KK-TK
Port_8599382_1 | SOURCEANDSINK | B - FL-Str.03_NK-KK-TK
Port_8621934_1 | SOURCEANDSINK | B - FL-Str.03_NK-KK-TK
Port_8599385_0 | SOURCEANDSINK | B - FL-Str.03_NK-KK-TK
Port_8622352_1 | SOURCEANDSINK | B - FL-Str.03_NK-KK-TK
Port_8599385_1 | SOURCEANDSINK | B - FL-Str.03_NK-KK-TK
Port_8622355_2 | SOURCEANDSINK | B - FL-Str.03_NK-KK-TK
Port_8599388_0 | SOURCEANDSINK | B - FL-Str.03_NK-KK-TK
Port_8607369_2 | SOURCEANDSINK | B - FL-Str.03_NK-KK-TK
Port_8599388_1 | SOURCEANDSINK | B - FL-Str.03_NK-KK-TK
Port_8624025_1 | SOURCEANDSINK | B - FL-Str.03_NK-KK-TK
Port_8599391_0 | SOURCEANDSINK | B - FL-Str.03_NK-KK-TK
Port_8607254_2 | SOURCEANDSINK | B - FL-Str.03_NK-KK-TK
Port_8599391_1 | SOURCEANDSINK | B - FL-Str.03_NK-KK-TK
Port_8623895_1 | SOURCEANDSINK | B - FL-Str.03_NK-KK-TK
Port_8599394_0 | SOURCEANDSINK | B - FL-Str.03_NK-KK-TK
Port_8623663_2 | SOURCEANDSINK | B - FL-Str.03_NK-KK-TK
Port_8599394_1 | SOURCEANDSINK | B - FL-Str.03_NK-KK-TK
Port_8623603_2 | SOURCEANDSINK | B - FL-Str.03_NK-KK-TK
Port_8599400_0 | SOURCEANDSINK | A - SL_NK-Str.02
Port_8608119_2 | SOURCEANDSINK | A - SL_NK-Str.02
Port_8599400_1 | SOURCEANDSINK | A - SL_NK-Str.02
Port_8622768_1 | SOURCEANDSINK | A - SL_NK-Str.02
Port_8599403_0 | SOURCEANDSINK | A - SL_NK-Str.02
Port_8607831_2 | SOURCEANDSINK | A - SL_NK-Str.02
Port_8599403_1 | SOURCEANDSINK | A - SL_NK-Str.02
Port_8622636_1 | SOURCEANDSINK | A - SL_NK-Str.02
Port_8599406_0 | SOURCEANDSINK | A - SL_NK-Str.02
Port_8607627_2 | SOURCEANDSINK | A - SL_NK-Str.02
Port_8599406_1 | SOURCEANDSINK | A - SL_NK-Str.02
Port_8622861_1 | SOURCEANDSINK | A - SL_NK-Str.02
Port_8599409_0 | SOURCEANDSINK | A - SL_NK-Str.02
Port_8626675_1 | SOURCEANDSINK | A - SL_NK-Str.02
Port_8599409_1 | SOURCEANDSINK | A - SL_NK-Str.02
Port_8634841_1 | SOURCEANDSINK | A - SL_NK-Str.02
Port_8599412_0 | SOURCEANDSINK | A - SL_NK-Str.02
Port_8608344_1 | SOURCEANDSINK | A - SL_NK-Str.02
Port_8599412_1 | SOURCEANDSINK | A - SL_NK-Str.02
Port_8608347_2 | SOURCEANDSINK | A - SL_NK-Str.02
Port_8599414_0 | SOURCEANDSINK | A - SL_NK-Str.02
Port_8625021_1 | SOURCEANDSINK | A - SL_NK-Str.02
Port_8599414_1 | SOURCEANDSINK | A - SL_NK-Str.02
Port_8608410_2 | SOURCEANDSINK | A - SL_NK-Str.02
Port_8599418_0 | SOURCEANDSINK | A - SL_NK-Str.02
Port_8608344_2 | SOURCEANDSINK | A - SL_NK-Str.02
Port_8599418_1 | SOURCEANDSINK | A - SL_NK-Str.02
Port_8624826_1 | SOURCEANDSINK | A - SL_NK-Str.02
Port_8599421_0 | SOURCEANDSINK | B - SL_NK-Str.02
Port_8599456_5 | SOURCEANDSINK | B - SL_NK-Str.02
Port_8599421_1 | SOURCEANDSINK | B - SL_NK-Str.02
Port_8625879_2 | SOURCEANDSINK | B - SL_NK-Str.02
Port_8599423_0 | SOURCEANDSINK | B - SL_NK-Str.02
Port_8608233_2 | SOURCEANDSINK | B - SL_NK-Str.02
Port_8599423_1 | SOURCEANDSINK | B - SL_NK-Str.02
Port_8621609_1 | SOURCEANDSINK | B - SL_NK-Str.02
Port_8599426_0 | SOURCEANDSINK | B - SL_NK-Str.02
Port_8608092_2 | SOURCEANDSINK | B - SL_NK-Str.02
Port_8599426_1 | SOURCEANDSINK | B - SL_NK-Str.02
Port_8621839_1 | SOURCEANDSINK | B - SL_NK-Str.02
Port_8599429_0 | SOURCEANDSINK | B - SL_NK-Str.02
Port_8607885_2 | SOURCEANDSINK | B - SL_NK-Str.02
Port_8599429_1 | SOURCEANDSINK | B - SL_NK-Str.02
Port_8621980_1 | SOURCEANDSINK | B - SL_NK-Str.02
Port_8599432_0 | SOURCEANDSINK | B - SL_NK-Str.02
Port_8622344_1 | SOURCEANDSINK | B - SL_NK-Str.02
Port_8599432_1 | SOURCEANDSINK | B - SL_NK-Str.02
Port_8622347_2 | SOURCEANDSINK | B - SL_NK-Str.02
Port_8599435_0 | SOURCEANDSINK | B - SL_NK-Str.02
Port_8607298_1 | SOURCEANDSINK | B - SL_NK-Str.02
Port_8599435_1 | SOURCEANDSINK | B - SL_NK-Str.02
Port_8623987_1 | SOURCEANDSINK | B - SL_NK-Str.02
Port_8599438_0 | SOURCEANDSINK | B - SL_NK-Str.02
Port_8599456_6 | SOURCEANDSINK | B - SL_NK-Str.02
Port_8599438_1 | SOURCEANDSINK | B - SL_NK-Str.02
Port_8625304_2 | SOURCEANDSINK | B - SL_NK-Str.02
Port_8599441_0 | SOURCEANDSINK | B - SL_NK-Str.02
Port_8599460_2 | SOURCEANDSINK | B - SL_NK-Str.02
Port_8599441_1 | SOURCEANDSINK | B - SL_NK-Str.02
Port_8625397_1 | SOURCEANDSINK | B - SL_NK-Str.02
Port_8599444_0 | SOURCEANDSINK | B - SL_NK-Str.02
Port_8599456_4 | SOURCEANDSINK | B - SL_NK-Str.02
Port_8599444_1 | SOURCEANDSINK | B - SL_NK-Str.02
Port_8599460_1 | SOURCEANDSINK | B - SL_NK-Str.02
Port_8599447_0 | SOURCEANDSINK | A - SL_NK-Str.02
Port_8599463_6 | SOURCEANDSINK | A - SL_NK-Str.02
Port_8599447_1 | SOURCEANDSINK | A - SL_NK-Str.02
Port_8626175_1 | SOURCEANDSINK | A - SL_NK-Str.02
Port_8599454_0 | SOURCEANDSINK | A - SL_NK-Str.02
Port_8608473_1 | SOURCEANDSINK | A - SL_NK-Str.02
Port_8599454_1 | SOURCEANDSINK | A - SL_NK-Str.02
Port_8608476_2 | SOURCEANDSINK | A - SL_NK-Str.02
Port_8599463_4 | SOURCEANDSINK | A - SL_NK-Str.02
Port_8626285_0 | SOURCEANDSINK | A - SL_NK-Str.02
Port_8599463_5 | SOURCEANDSINK | A - SL_NK-Str.02
Port_8599464_1 | SOURCEANDSINK | A - SL_NK-Str.02
Port_8599464_0 | SOURCEANDSINK | A - SL_NK-Str.02
Port_8608473_2 | SOURCEANDSINK | A - SL_NK-Str.02
Port_8599475_0 | SOURCEANDSINK | A - SL_NK-Str.02
Port_8625021_2 | SOURCEANDSINK | A - SL_NK-Str.02
Port_8599475_1 | SOURCEANDSINK | A - SL_NK-Str.02
Port_8625024_2 | SOURCEANDSINK | A - SL_NK-Str.02
Port_8599636_5 | SOURCEANDSINK | B - SL_NK-Str.02
Port_8599637_1 | SOURCEANDSINK | B - SL_NK-Str.02
Port_8599636_6 | SOURCEANDSINK | B - SL_NK-Str.02
Port_8625869_0 | SOURCEANDSINK | B - SL_NK-Str.02
Port_8599756_5 | SOURCEANDSINK | A - FL-Str.03_NK-KK-TK
Port_8600291_0 | SOURCEANDSINK | A - FL-Str.03_NK-KK-TK
Port_8599756_6 | SOURCEANDSINK | A - FL-Str.03_NK-KK-TK
Port_8608633_0 | SOURCEANDSINK | A - FL-Str.03_NK-KK-TK
Port_8599907_5 | SOURCEANDSINK | A - SL_NK-Str.02
Port_8600075_1 | SOURCEANDSINK | A - SL_NK-Str.02
Port_8599907_6 | SOURCEANDSINK | A - SL_NK-Str.02
Port_8608465_0 | SOURCEANDSINK | A - SL_NK-Str.02
Port_8600074_4 | SOURCEANDSINK | A - SL_NK-Str.02
Port_8600182_0 | SOURCEANDSINK | A - SL_NK-Str.02
Port_8600074_5 | SOURCEANDSINK | A - SL_NK-Str.02
Port_8600075_0 | SOURCEANDSINK | A - SL_NK-Str.02
Port_8600074_6 | SOURCEANDSINK | A - SL_NK-Str.02
Port_8608399_0 | SOURCEANDSINK | A - SL_NK-Str.02
Port_8600181_5 | SOURCEANDSINK | A - SL_NK-Str.02
Port_8600182_1 | SOURCEANDSINK | A - SL_NK-Str.02
Port_8600181_6 | SOURCEANDSINK | A - SL_NK-Str.02
Port_8608336_0 | SOURCEANDSINK | A - SL_NK-Str.02
Port_8600290_5 | SOURCEANDSINK | A - FL-Str.03_NK-KK-TK
Port_8600291_1 | SOURCEANDSINK | A - FL-Str.03_NK-KK-TK
Port_8600290_6 | SOURCEANDSINK | A - FL-Str.03_NK-KK-TK
Port_8608660_0 | SOURCEANDSINK | A - FL-Str.03_NK-KK-TK
Port_8602648_0 | SOURCEANDSINK | A - FL-Str.01_NK-KK-TK
Port_8604268_2 | SOURCEANDSINK | A - FL-Str.01_NK-KK-TK
Port_8602648_1 | SOURCEANDSINK | A - FL-Str.01_NK-KK-TK
Port_8619521_1 | SOURCEANDSINK | A - FL-Str.01_NK-KK-TK
Port_8602651_0 | SOURCEANDSINK | A - FL-Str.01_NK-KK-TK
Port_8619284_2 | SOURCEANDSINK | A - FL-Str.01_NK-KK-TK
Port_8602651_1 | SOURCEANDSINK | A - FL-Str.01_NK-KK-TK
Port_8619289_2 | SOURCEANDSINK | A - FL-Str.01_NK-KK-TK
Port_8602654_0 | SOURCEANDSINK | A - FL-Str.01_NK-KK-TK
Port_8619780_2 | SOURCEANDSINK | A - FL-Str.01_NK-KK-TK
Port_8602654_1 | SOURCEANDSINK | A - FL-Str.01_NK-KK-TK
Port_8619785_2 | SOURCEANDSINK | A - FL-Str.01_NK-KK-TK
Port_8602657_0 | SOURCEANDSINK | A - FL-Str.01_NK-KK-TK
Port_8606888_4 | SOURCEANDSINK | A - FL-Str.01_NK-KK-TK
Port_8602657_1 | SOURCEANDSINK | A - FL-Str.01_NK-KK-TK
Port_8620911_2 | SOURCEANDSINK | A - FL-Str.01_NK-KK-TK
Port_8602660_0 | SOURCEANDSINK | A - FL-Str.01_NK-KK-TK
Port_8617877_2 | SOURCEANDSINK | A - FL-Str.01_NK-KK-TK
Port_8602660_1 | SOURCEANDSINK | A - FL-Str.01_NK-KK-TK
Port_8617835_2 | SOURCEANDSINK | A - FL-Str.01_NK-KK-TK
Port_8602667_0 | SOURCEANDSINK | A - FL-Str.01_NK-KK-TK
Port_8617865_4 | SOURCEANDSINK | A - FL-Str.01_NK-KK-TK
Port_8602667_1 | SOURCEANDSINK | A - FL-Str.01_NK-KK-TK
Port_8602675_0 | SOURCEANDSINK | A - FL-Str.01_NK-KK-TK
Port_8620557_2 | SOURCEANDSINK | A - FL-Str.01_NK-KK-TK
Port_8602675_1 | SOURCEANDSINK | A - FL-Str.01_NK-KK-TK
Port_8620562_2 | SOURCEANDSINK | A - FL-Str.01_NK-KK-TK
Port_8602678_0 | SOURCEANDSINK | A - FL-Str.01_NK-KK-TK
Port_8620273_2 | SOURCEANDSINK | A - FL-Str.01_NK-KK-TK
Port_8602678_1 | SOURCEANDSINK | A - FL-Str.01_NK-KK-TK
Port_8620278_2 | SOURCEANDSINK | A - FL-Str.01_NK-KK-TK
Port_8602681_0 | SOURCEANDSINK | A - FL-Str.01_NK-KK-TK
Port_8631606_2 | SOURCEANDSINK | A - FL-Str.01_NK-KK-TK
Port_8602681_1 | SOURCEANDSINK | A - FL-Str.01_NK-KK-TK
Port_8631611_2 | SOURCEANDSINK | A - FL-Str.01_NK-KK-TK
Port_8602684_0 | SOURCEANDSINK | A - FL-Str.01_NK-KK-TK
Port_8631714_2 | SOURCEANDSINK | A - FL-Str.01_NK-KK-TK
Port_8602684_1 | SOURCEANDSINK | A - FL-Str.01_NK-KK-TK
Port_8631719_2 | SOURCEANDSINK | A - FL-Str.01_NK-KK-TK
Port_8602687_0 | SOURCEANDSINK | A - FL-Str.01_NK-KK-TK
Port_8611868_1 | SOURCEANDSINK | A - FL-Str.01_NK-KK-TK
Port_8602687_1 | SOURCEANDSINK | A - FL-Str.01_NK-KK-TK
Port_8631944_1 | SOURCEANDSINK | A - FL-Str.01_NK-KK-TK
Port_8602690_0 | SOURCEANDSINK | A - FL-Str.01_NK-KK-TK
Port_8618031_2 | SOURCEANDSINK | A - FL-Str.01_NK-KK-TK
Port_8602690_1 | SOURCEANDSINK | A - FL-Str.01_NK-KK-TK
Port_8604825_2 | SOURCEANDSINK | A - FL-Str.01_NK-KK-TK
Port_8602696_0 | SOURCEANDSINK | A - FL-Str.01_NK-KK-TK
Port_8618031_1 | SOURCEANDSINK | A - FL-Str.01_NK-KK-TK
Port_8602696_1 | SOURCEANDSINK | A - FL-Str.01_NK-KK-TK
Port_8618034_2 | SOURCEANDSINK | A - FL-Str.01_NK-KK-TK
Port_8602700_0 | SOURCEANDSINK | A - FL-Str.01_NK-KK-TK
Port_8618019_4 | SOURCEANDSINK | A - FL-Str.01_NK-KK-TK
Port_8602700_1 | SOURCEANDSINK | A - FL-Str.01_NK-KK-TK
Port_8602705_0 | SOURCEANDSINK | A - FL-Str.01_NK-KK-TK
Port_8628859_2 | SOURCEANDSINK | A - FL-Str.01_NK-KK-TK
Port_8602705_1 | SOURCEANDSINK | A - FL-Str.01_NK-KK-TK
Port_8628864_2 | SOURCEANDSINK | A - FL-Str.01_NK-KK-TK
Port_8602708_0 | SOURCEANDSINK | A - SL_KK
Port_8628794_4 | SOURCEANDSINK | A - SL_KK
Port_8602708_1 | SOURCEANDSINK | A - SL_KK
Port_8602720_0 | SOURCEANDSINK | B - FL-Str.01_NK-KK-TK
Port_8619390_2 | SOURCEANDSINK | B - FL-Str.01_NK-KK-TK
Port_8602720_1 | SOURCEANDSINK | B - FL-Str.01_NK-KK-TK
Port_8619395_2 | SOURCEANDSINK | B - FL-Str.01_NK-KK-TK
Port_8602723_0 | SOURCEANDSINK | B - FL-Str.01_NK-KK-TK
Port_8606268_2 | SOURCEANDSINK | B - FL-Str.01_NK-KK-TK
Port_8602723_1 | SOURCEANDSINK | B - FL-Str.01_NK-KK-TK
Port_8619661_1 | SOURCEANDSINK | B - FL-Str.01_NK-KK-TK
Port_8602726_0 | SOURCEANDSINK | B - FL-Str.01_NK-KK-TK
Port_8605863_2 | SOURCEANDSINK | B - FL-Str.01_NK-KK-TK
Port_8602726_1 | SOURCEANDSINK | B - FL-Str.01_NK-KK-TK
Port_8619064_1 | SOURCEANDSINK | B - FL-Str.01_NK-KK-TK
Port_8602729_0 | SOURCEANDSINK | B - FL-Str.01_NK-KK-TK
Port_8605917_2 | SOURCEANDSINK | B - FL-Str.01_NK-KK-TK
Port_8602729_1 | SOURCEANDSINK | B - FL-Str.01_NK-KK-TK
Port_8621192_1 | SOURCEANDSINK | B - FL-Str.01_NK-KK-TK
Port_8602738_0 | SOURCEANDSINK | B - FL-Str.01_NK-KK-TK
Port_8606108_2 | SOURCEANDSINK | B - FL-Str.01_NK-KK-TK
Port_8602738_1 | SOURCEANDSINK | B - FL-Str.01_NK-KK-TK
Port_8619921_1 | SOURCEANDSINK | B - FL-Str.01_NK-KK-TK
Port_8602741_0 | SOURCEANDSINK | B - FL-Str.01_NK-KK-TK
Port_8618696_1 | SOURCEANDSINK | B - FL-Str.01_NK-KK-TK
Port_8602741_1 | SOURCEANDSINK | B - FL-Str.01_NK-KK-TK
Port_8618699_2 | SOURCEANDSINK | B - FL-Str.01_NK-KK-TK
Port_8602744_0 | SOURCEANDSINK | B - FL-Str.01_NK-KK-TK
Port_8620150_2 | SOURCEANDSINK | B - FL-Str.01_NK-KK-TK
Port_8602744_1 | SOURCEANDSINK | B - FL-Str.01_NK-KK-TK
Port_8620155_2 | SOURCEANDSINK | B - FL-Str.01_NK-KK-TK
Port_8602747_0 | SOURCEANDSINK | B - FL-Str.01_NK-KK-TK
Port_8631266_2 | SOURCEANDSINK | B - FL-Str.01_NK-KK-TK
Port_8602747_1 | SOURCEANDSINK | B - FL-Str.01_NK-KK-TK
Port_8631271_2 | SOURCEANDSINK | B - FL-Str.01_NK-KK-TK
Port_8602750_0 | SOURCEANDSINK | B - FL-Str.01_NK-KK-TK
Port_8611933_2 | SOURCEANDSINK | B - FL-Str.01_NK-KK-TK
Port_8602750_1 | SOURCEANDSINK | B - FL-Str.01_NK-KK-TK
Port_8632253_1 | SOURCEANDSINK | B - FL-Str.01_NK-KK-TK
Port_8602753_0 | SOURCEANDSINK | B - FL-Str.01_NK-KK-TK
Port_8632080_2 | SOURCEANDSINK | B - FL-Str.01_NK-KK-TK
Port_8602753_1 | SOURCEANDSINK | B - FL-Str.01_NK-KK-TK
Port_8632085_2 | SOURCEANDSINK | B - FL-Str.01_NK-KK-TK
Port_8602756_0 | SOURCEANDSINK | B - FL-Str.01_NK-KK-TK
Port_8618256_2 | SOURCEANDSINK | B - FL-Str.01_NK-KK-TK
Port_8602756_1 | SOURCEANDSINK | B - FL-Str.01_NK-KK-TK
Port_8605028_2 | SOURCEANDSINK | B - FL-Str.01_NK-KK-TK
Port_8602762_0 | SOURCEANDSINK | B - FL-Str.01_NK-KK-TK
Port_8618256_1 | SOURCEANDSINK | B - FL-Str.01_NK-KK-TK
Port_8602762_1 | SOURCEANDSINK | B - FL-Str.01_NK-KK-TK
Port_8618259_2 | SOURCEANDSINK | B - FL-Str.01_NK-KK-TK
Port_8602766_0 | SOURCEANDSINK | B - FL-Str.01_NK-KK-TK
Port_8618244_4 | SOURCEANDSINK | B - FL-Str.01_NK-KK-TK
Port_8602766_1 | SOURCEANDSINK | B - FL-Str.01_NK-KK-TK
Port_8602774_0 | SOURCEANDSINK | B - FL-Str.01_NK-KK-TK
Port_8628695_2 | SOURCEANDSINK | B - FL-Str.01_NK-KK-TK
Port_8602774_1 | SOURCEANDSINK | B - FL-Str.01_NK-KK-TK
Port_8628700_2 | SOURCEANDSINK | B - FL-Str.01_NK-KK-TK
Port_8602781_0 | SOURCEANDSINK | B - FL-Str.01_NK-KK-TK
Port_8628752_2 | SOURCEANDSINK | B - FL-Str.01_NK-KK-TK
Port_8602781_1 | SOURCEANDSINK | B - FL-Str.01_NK-KK-TK
Port_8628683_4 | SOURCEANDSINK | B - FL-Str.01_NK-KK-TK
Port_8602786_0 | SOURCEANDSINK | B - FL-Str.01_NK-KK-TK
Port_8629153_2 | SOURCEANDSINK | B - FL-Str.01_NK-KK-TK
Port_8602786_1 | SOURCEANDSINK | B - FL-Str.01_NK-KK-TK
Port_8602790_0 | SOURCEANDSINK | B - FL-Str.01_NK-KK-TK
Port_8629147_4 | SOURCEANDSINK | B - FL-Str.01_NK-KK-TK
Port_8602790_1 | SOURCEANDSINK | B - FL-Str.01_NK-KK-TK
Port_8629315_2 | SOURCEANDSINK | B - FL-Str.01_NK-KK-TK
Port_8602798_0 | SOURCEANDSINK | B - FL-Str.02_NK-KK-TK
Port_8602810_4 | SOURCEANDSINK | B - FL-Str.02_NK-KK-TK
Port_8602798_1 | SOURCEANDSINK | B - FL-Str.02_NK-KK-TK
Port_8603936_2 | SOURCEANDSINK | B - FL-Str.02_NK-KK-TK
Port_8602801_0 | SOURCEANDSINK | B - FL-Str.02_NK-KK-TK
Port_8602807_2 | SOURCEANDSINK | B - FL-Str.02_NK-KK-TK
Port_8602801_1 | SOURCEANDSINK | B - FL-Str.02_NK-KK-TK
Port_8625253_1 | SOURCEANDSINK | B - FL-Str.02_NK-KK-TK
Port_8602804_0 | SOURCEANDSINK | B - FL-Str.02_NK-KK-TK
Port_8602810_6 | SOURCEANDSINK | B - FL-Str.02_NK-KK-TK
Port_8602804_1 | SOURCEANDSINK | B - FL-Str.02_NK-KK-TK
Port_8625437_1 | SOURCEANDSINK | B - FL-Str.02_NK-KK-TK
Port_8602807_1 | SOURCEANDSINK | B - FL-Str.02_NK-KK-TK
Port_8602811_0 | SOURCEANDSINK | B - FL-Str.02_NK-KK-TK
Port_8602810_5 | SOURCEANDSINK | B - FL-Str.02_NK-KK-TK
Port_8602811_1 | SOURCEANDSINK | B - FL-Str.02_NK-KK-TK
Port_8602816_0 | SOURCEANDSINK | A - FL-Str.02_NK-KK-TK
Port_8602826_6 | SOURCEANDSINK | A - FL-Str.02_NK-KK-TK
Port_8602816_1 | SOURCEANDSINK | A - FL-Str.02_NK-KK-TK
Port_8626135_1 | SOURCEANDSINK | A - FL-Str.02_NK-KK-TK
Port_8602820_0 | SOURCEANDSINK | A - FL-Str.02_NK-KK-TK
Port_8634753_1 | SOURCEANDSINK | A - FL-Str.02_NK-KK-TK
Port_8602820_1 | SOURCEANDSINK | A - FL-Str.02_NK-KK-TK
Port_8634756_2 | SOURCEANDSINK | A - FL-Str.02_NK-KK-TK
Port_8602826_4 | SOURCEANDSINK | A - FL-Str.02_NK-KK-TK
Port_8602832_0 | SOURCEANDSINK | A - FL-Str.02_NK-KK-TK
Port_8602826_5 | SOURCEANDSINK | A - FL-Str.02_NK-KK-TK
Port_8602827_0 | SOURCEANDSINK | A - FL-Str.02_NK-KK-TK
Port_8602827_1 | SOURCEANDSINK | A - FL-Str.02_NK-KK-TK
Port_8634753_2 | SOURCEANDSINK | A - FL-Str.02_NK-KK-TK
Port_8602832_1 | SOURCEANDSINK | A - FL-Str.02_NK-KK-TK
Port_8603874_2 | SOURCEANDSINK | A - FL-Str.02_NK-KK-TK
Port_8602834_0 | SOURCEANDSINK | B - FL-Str.02_NK-KK-TK
Port_8604647_2 | SOURCEANDSINK | B - FL-Str.02_NK-KK-TK
Port_8602834_1 | SOURCEANDSINK | B - FL-Str.02_NK-KK-TK
Port_8602837_0 | SOURCEANDSINK | A - FL-Str.02_NK-KK-TK
Port_8605151_2 | SOURCEANDSINK | A - FL-Str.02_NK-KK-TK
Port_8602837_1 | SOURCEANDSINK | A - FL-Str.02_NK-KK-TK
Port_8630874_1 | SOURCEANDSINK | A - FL-Str.02_NK-KK-TK
Port_8602843_0 | SOURCEANDSINK | B - FL-Str.02_NK-KK-TK
Port_8627545_2 | SOURCEANDSINK | B - FL-Str.02_NK-KK-TK
Port_8602843_1 | SOURCEANDSINK | B - FL-Str.02_NK-KK-TK
Port_8602847_0 | SOURCEANDSINK | B - FL-Str.02_NK-KK-TK
Port_8627590_2 | SOURCEANDSINK | B - FL-Str.02_NK-KK-TK
Port_8602847_1 | SOURCEANDSINK | B - FL-Str.02_NK-KK-TK
Port_8627539_4 | SOURCEANDSINK | B - FL-Str.02_NK-KK-TK
Port_8602852_0 | SOURCEANDSINK | A - FL-Str.02_NK-KK-TK
Port_8602864_4 | SOURCEANDSINK | A - FL-Str.02_NK-KK-TK
Port_8602852_1 | SOURCEANDSINK | A - FL-Str.02_NK-KK-TK
Port_8627349_2 | SOURCEANDSINK | A - FL-Str.02_NK-KK-TK
Port_8602855_0 | SOURCEANDSINK | A - FL-Str.02_NK-KK-TK
Port_8627338_1 | SOURCEANDSINK | A - FL-Str.02_NK-KK-TK
Port_8602855_1 | SOURCEANDSINK | A - FL-Str.02_NK-KK-TK
Port_8602861_0 | SOURCEANDSINK | A - FL-Str.02_NK-KK-TK
Port_8602864_6 | SOURCEANDSINK | A - FL-Str.02_NK-KK-TK
Port_8602861_1 | SOURCEANDSINK | A - FL-Str.02_NK-KK-TK
Port_8602864_5 | SOURCEANDSINK | A - FL-Str.02_NK-KK-TK
Port_8602865_0 | SOURCEANDSINK | A - FL-Str.02_NK-KK-TK
Port_8602865_1 | SOURCEANDSINK | A - FL-Str.02_NK-KK-TK
Port_8609194_2 | SOURCEANDSINK | A - FL-Str.02_NK-KK-TK
Port_8602871_0 | SOURCEANDSINK | B - FL-Str.02_NK-KK-TK
Port_8609450_2 | SOURCEANDSINK | B - FL-Str.02_NK-KK-TK
Port_8602871_1 | SOURCEANDSINK | B - FL-Str.02_NK-KK-TK
Port_8602874_0 | SOURCEANDSINK | A - FL-Str.02_NK-KK-TK
Port_8616141_2 | SOURCEANDSINK | A - FL-Str.02_NK-KK-TK
Port_8602874_1 | SOURCEANDSINK | A - FL-Str.02_NK-KK-TK
Port_8631025_1 | SOURCEANDSINK | A - FL-Str.02_NK-KK-TK
Port_8602877_0 | SOURCEANDSINK | B - FL-Str.02_NK-KK-TK
Port_8627161_1 | SOURCEANDSINK | B - FL-Str.02_NK-KK-TK
Port_8602877_1 | SOURCEANDSINK | B - FL-Str.02_NK-KK-TK
Port_8609735_2 | SOURCEANDSINK | B - FL-Str.02_NK-KK-TK
Port_8602883_0 | SOURCEANDSINK | B - FL-Str.02_NK-KK-TK
Port_8627161_2 | SOURCEANDSINK | B - FL-Str.02_NK-KK-TK
Port_8602883_1 | SOURCEANDSINK | B - FL-Str.02_NK-KK-TK
Port_8627164_2 | SOURCEANDSINK | B - FL-Str.02_NK-KK-TK
Port_8602886_0 | SOURCEANDSINK | B - FL-Str.02_NK-KK-TK
Port_8627149_4 | SOURCEANDSINK | B - FL-Str.02_NK-KK-TK
Port_8602886_1 | SOURCEANDSINK | B - FL-Str.02_NK-KK-TK
Port_8602895_0 | SOURCEANDSINK | A - FL-Str.02_NK-KK-TK
Port_8629886_2 | SOURCEANDSINK | A - FL-Str.02_NK-KK-TK
Port_8602895_1 | SOURCEANDSINK | A - FL-Str.02_NK-KK-TK
Port_8610375_2 | SOURCEANDSINK | A - FL-Str.02_NK-KK-TK
Port_8602901_0 | SOURCEANDSINK | A - FL-Str.02_NK-KK-TK
Port_8629886_1 | SOURCEANDSINK | A - FL-Str.02_NK-KK-TK
Port_8602901_1 | SOURCEANDSINK | A - FL-Str.02_NK-KK-TK
Port_8629889_2 | SOURCEANDSINK | A - FL-Str.02_NK-KK-TK
Port_8602913_0 | SOURCEANDSINK | B - FL-Str.02_NK-KK-TK
Port_8610546_2 | SOURCEANDSINK | B - FL-Str.02_NK-KK-TK
Port_8602913_1 | SOURCEANDSINK | B - FL-Str.02_NK-KK-TK
Port_8632953_1 | SOURCEANDSINK | B - FL-Str.02_NK-KK-TK
Port_8602916_0 | SOURCEANDSINK | A - FL-Str.02_NK-KK-TK
Port_8632793_2 | SOURCEANDSINK | A - FL-Str.02_NK-KK-TK
Port_8602916_1 | SOURCEANDSINK | A - FL-Str.02_NK-KK-TK
Port_8632798_2 | SOURCEANDSINK | A - FL-Str.02_NK-KK-TK
Port_8602919_0 | SOURCEANDSINK | A - FL-Str.02_NK-KK-TK
Port_8630099_2 | SOURCEANDSINK | A - FL-Str.02_NK-KK-TK
Port_8602919_1 | SOURCEANDSINK | A - FL-Str.02_NK-KK-TK
Port_8609943_2 | SOURCEANDSINK | A - FL-Str.02_NK-KK-TK
Port_8602925_0 | SOURCEANDSINK | A - FL-Str.02_NK-KK-TK
Port_8630099_1 | SOURCEANDSINK | A - FL-Str.02_NK-KK-TK
Port_8602925_1 | SOURCEANDSINK | A - FL-Str.02_NK-KK-TK
Port_8630102_2 | SOURCEANDSINK | A - FL-Str.02_NK-KK-TK
Port_8602934_0 | SOURCEANDSINK | B - FL-Str.02_NK-KK-TK
Port_8629669_1 | SOURCEANDSINK | B - FL-Str.02_NK-KK-TK
Port_8602934_1 | SOURCEANDSINK | B - FL-Str.02_NK-KK-TK
Port_8610195_2 | SOURCEANDSINK | B - FL-Str.02_NK-KK-TK
Port_8602937_0 | SOURCEANDSINK | B - FL-Str.02_NK-KK-TK
Port_8629657_4 | SOURCEANDSINK | B - FL-Str.02_NK-KK-TK
Port_8602937_1 | SOURCEANDSINK | B - FL-Str.02_NK-KK-TK
Port_8602940_0 | SOURCEANDSINK | B - FL-Str.02_NK-KK-TK
Port_8629669_2 | SOURCEANDSINK | B - FL-Str.02_NK-KK-TK
Port_8602940_1 | SOURCEANDSINK | B - FL-Str.02_NK-KK-TK
Port_8629672_2 | SOURCEANDSINK | B - FL-Str.02_NK-KK-TK
Port_8602955_0 | SOURCEANDSINK | A - FL-Str.02_NK-KK-TK
Port_8633167_2 | SOURCEANDSINK | A - FL-Str.02_NK-KK-TK
Port_8602955_1 | SOURCEANDSINK | A - FL-Str.02_NK-KK-TK
Port_8633172_2 | SOURCEANDSINK | A - FL-Str.02_NK-KK-TK
Port_8602958_0 | SOURCEANDSINK | B - FL-Str.02_NK-KK-TK
Port_8632548_2 | SOURCEANDSINK | B - FL-Str.02_NK-KK-TK
Port_8602958_1 | SOURCEANDSINK | B - FL-Str.02_NK-KK-TK
Port_8632553_2 | SOURCEANDSINK | B - FL-Str.02_NK-KK-TK
Port_8602961_0 | SOURCEANDSINK | A - FL-Str.02_NK-KK-TK
Port_8612504_4 | SOURCEANDSINK | A - FL-Str.02_NK-KK-TK
Port_8602961_1 | SOURCEANDSINK | A - FL-Str.02_NK-KK-TK
Port_8633636_2 | SOURCEANDSINK | A - FL-Str.02_NK-KK-TK
Port_8602972_0 | SOURCEANDSINK | A - FL-Str.02_NK-KK-TK
Port_8610894_5 | SOURCEANDSINK | A - FL-Str.02_NK-KK-TK
Port_8602972_1 | SOURCEANDSINK | A - FL-Str.02_NK-KK-TK
Port_8611189_2 | SOURCEANDSINK | A - FL-Str.02_NK-KK-TK
Port_8602981_0 | SOURCEANDSINK | B - FL-Str.02_NK-KK-TK
Port_8614003_4 | SOURCEANDSINK | B - FL-Str.02_NK-KK-TK
Port_8602981_1 | SOURCEANDSINK | B - FL-Str.02_NK-KK-TK
Port_8633708_2 | SOURCEANDSINK | B - FL-Str.02_NK-KK-TK
Port_8602998_0 | SOURCEANDSINK | A - SL_KK
Port_8604295_2 | SOURCEANDSINK | A - SL_KK
Port_8602998_1 | SOURCEANDSINK | A - SL_KK
Port_8619551_1 | SOURCEANDSINK | A - SL_KK
Port_8603000_0 | SOURCEANDSINK | A - SL_KK
Port_8619322_2 | SOURCEANDSINK | A - SL_KK
Port_8603000_1 | SOURCEANDSINK | A - SL_KK
Port_8619327_2 | SOURCEANDSINK | A - SL_KK
Port_8603002_0 | SOURCEANDSINK | A - SL_KK
Port_8619818_2 | SOURCEANDSINK | A - SL_KK
Port_8603002_1 | SOURCEANDSINK | A - SL_KK
Port_8619823_2 | SOURCEANDSINK | A - SL_KK
Port_8603004_0 | SOURCEANDSINK | A - SL_KK
Port_8606911_5 | SOURCEANDSINK | A - SL_KK
Port_8603004_1 | SOURCEANDSINK | A - SL_KK
Port_8620946_2 | SOURCEANDSINK | A - SL_KK
Port_8603007_0 | SOURCEANDSINK | A - SL_KK
Port_8606911_4 | SOURCEANDSINK | A - SL_KK
Port_8603007_1 | SOURCEANDSINK | A - SL_KK
Port_8620717_2 | SOURCEANDSINK | A - SL_KK
Port_8603009_0 | SOURCEANDSINK | A - SL_KK
Port_8620518_2 | SOURCEANDSINK | A - SL_KK
Port_8603009_1 | SOURCEANDSINK | A - SL_KK
Port_8620523_2 | SOURCEANDSINK | A - SL_KK
Port_8603012_0 | SOURCEANDSINK | A - SL_KK
Port_8620235_2 | SOURCEANDSINK | A - SL_KK
Port_8603012_1 | SOURCEANDSINK | A - SL_KK
Port_8620240_2 | SOURCEANDSINK | A - SL_KK
Port_8603020_0 | SOURCEANDSINK | A - SL_KK
Port_8630491_2 | SOURCEANDSINK | A - SL_KK
Port_8603020_1 | SOURCEANDSINK | A - SL_KK
Port_8630843_1 | SOURCEANDSINK | A - SL_KK
Port_8603023_0 | SOURCEANDSINK | A - SL_KK
Port_8616207_2 | SOURCEANDSINK | A - SL_KK
Port_8603023_1 | SOURCEANDSINK | A - SL_KK
Port_8630993_1 | SOURCEANDSINK | A - SL_KK
Port_8603026_0 | SOURCEANDSINK | A - SL_KK
Port_8617913_2 | SOURCEANDSINK | A - SL_KK
Port_8603026_1 | SOURCEANDSINK | A - SL_KK
Port_8617827_2 | SOURCEANDSINK | A - SL_KK
Port_8603032_0 | SOURCEANDSINK | A - SL_KK
Port_8628806_2 | SOURCEANDSINK | A - SL_KK
Port_8603032_1 | SOURCEANDSINK | A - SL_KK
Port_8628811_2 | SOURCEANDSINK | A - SL_KK
Port_8603035_0 | SOURCEANDSINK | A - FL-Str.01_NK-KK-TK
Port_8628847_4 | SOURCEANDSINK | A - FL-Str.01_NK-KK-TK
Port_8603035_1 | SOURCEANDSINK | A - FL-Str.01_NK-KK-TK
Port_8603039_0 | SOURCEANDSINK | A - SL_KK
Port_8617901_4 | SOURCEANDSINK | A - SL_KK
Port_8603039_1 | SOURCEANDSINK | A - SL_KK
Port_8603050_0 | SOURCEANDSINK | B - SL_KK
Port_8619427_2 | SOURCEANDSINK | B - SL_KK
Port_8603050_1 | SOURCEANDSINK | B - SL_KK
Port_8619432_2 | SOURCEANDSINK | B - SL_KK
Port_8603053_0 | SOURCEANDSINK | B - SL_KK
Port_8606241_2 | SOURCEANDSINK | B - SL_KK
Port_8603053_1 | SOURCEANDSINK | B - SL_KK
Port_8619711_1 | SOURCEANDSINK | B - SL_KK
Port_8603056_0 | SOURCEANDSINK | B - SL_KK
Port_8621154_1 | SOURCEANDSINK | B - SL_KK
Port_8603056_1 | SOURCEANDSINK | B - SL_KK
Port_8621123_2 | SOURCEANDSINK | B - SL_KK
Port_8603065_0 | SOURCEANDSINK | B - SL_KK
Port_8616849_2 | SOURCEANDSINK | B - SL_KK
Port_8603065_1 | SOURCEANDSINK | B - SL_KK
Port_8619890_1 | SOURCEANDSINK | B - SL_KK
Port_8603068_0 | SOURCEANDSINK | B - SL_KK
Port_8618712_1 | SOURCEANDSINK | B - SL_KK
Port_8603068_1 | SOURCEANDSINK | B - SL_KK
Port_8618804_1 | SOURCEANDSINK | B - SL_KK
Port_8603071_0 | SOURCEANDSINK | B - SL_KK
Port_8620097_2 | SOURCEANDSINK | B - SL_KK
Port_8603071_1 | SOURCEANDSINK | B - SL_KK
Port_8620102_2 | SOURCEANDSINK | B - SL_KK
Port_8603077_0 | SOURCEANDSINK | B - SL_KK
Port_8628550_2 | SOURCEANDSINK | B - SL_KK
Port_8603077_1 | SOURCEANDSINK | B - SL_KK
Port_8628555_2 | SOURCEANDSINK | B - SL_KK
Port_8603081_0 | SOURCEANDSINK | B - SL_KK
Port_8628597_2 | SOURCEANDSINK | B - SL_KK
Port_8603081_1 | SOURCEANDSINK | B - SL_KK
Port_8628538_4 | SOURCEANDSINK | B - SL_KK
Port_8603086_0 | SOURCEANDSINK | B - SL_KK
Port_8629114_2 | SOURCEANDSINK | B - SL_KK
Port_8603086_1 | SOURCEANDSINK | B - SL_KK
Port_8603090_0 | SOURCEANDSINK | B - SL_KK
Port_8629107_4 | SOURCEANDSINK | B - SL_KK
Port_8603090_1 | SOURCEANDSINK | B - SL_KK
Port_8629351_2 | SOURCEANDSINK | B - SL_KK
Port_8603099_0 | SOURCEANDSINK | B - SL_KK
Port_8631151_2 | SOURCEANDSINK | B - SL_KK
Port_8603099_1 | SOURCEANDSINK | B - SL_KK
Port_8631156_2 | SOURCEANDSINK | B - SL_KK
Port_8603102_0 | SOURCEANDSINK | B - SL_KK
Port_8630348_2 | SOURCEANDSINK | B - SL_KK
Port_8603102_1 | SOURCEANDSINK | B - SL_KK
Port_8630353_2 | SOURCEANDSINK | B - SL_KK
Port_8603104_0 | SOURCEANDSINK | B - SL_KK
Port_8605836_2 | SOURCEANDSINK | B - SL_KK
Port_8603104_1 | SOURCEANDSINK | B - SL_KK
Port_8619094_1 | SOURCEANDSINK | B - SL_KK
Port_8603110_0 | SOURCEANDSINK | A - SL_NK-Str.01
Port_8618078_2 | SOURCEANDSINK | A - SL_NK-Str.01
Port_8603110_1 | SOURCEANDSINK | A - SL_NK-Str.01
Port_8618081_2 | SOURCEANDSINK | A - SL_NK-Str.01
Port_8603114_0 | SOURCEANDSINK | A - SL_NK-Str.01
Port_8618066_4 | SOURCEANDSINK | A - SL_NK-Str.01
Port_8603114_1 | SOURCEANDSINK | A - SL_NK-Str.01
Port_8603121_0 | SOURCEANDSINK | B - SL_NK-Str.01
Port_8618212_1 | SOURCEANDSINK | B - SL_NK-Str.01
Port_8603121_1 | SOURCEANDSINK | B - SL_NK-Str.01
Port_8618215_2 | SOURCEANDSINK | B - SL_NK-Str.01
Port_8603143_0 | SOURCEANDSINK | B - SL_TK
Port_8627095_2 | SOURCEANDSINK | B - SL_TK
Port_8603143_1 | SOURCEANDSINK | B - SL_TK
Port_8627100_2 | SOURCEANDSINK | B - SL_TK
Port_8603148_0 | SOURCEANDSINK | A - SL_TK
Port_8627292_1 | SOURCEANDSINK | A - SL_TK
Port_8603148_1 | SOURCEANDSINK | A - SL_TK
Port_8603153_0 | SOURCEANDSINK | B - SL_TK
Port_8627207_1 | SOURCEANDSINK | B - SL_TK
Port_8603153_1 | SOURCEANDSINK | B - SL_TK
Port_8609768_2 | SOURCEANDSINK | B - SL_TK
Port_8603156_0 | SOURCEANDSINK | B - SL_TK
Port_8627195_4 | SOURCEANDSINK | B - SL_TK
Port_8603156_1 | SOURCEANDSINK | B - SL_TK
Port_8603159_0 | SOURCEANDSINK | B - SL_TK
Port_8627207_2 | SOURCEANDSINK | B - SL_TK
Port_8603159_1 | SOURCEANDSINK | B - SL_TK
Port_8627210_2 | SOURCEANDSINK | B - SL_TK
Port_8603168_0 | SOURCEANDSINK | A - SL_TK
Port_8629842_2 | SOURCEANDSINK | A - SL_TK
Port_8603168_1 | SOURCEANDSINK | A - SL_TK
Port_8610408_2 | SOURCEANDSINK | A - SL_TK
Port_8603174_0 | SOURCEANDSINK | A - SL_TK
Port_8629842_1 | SOURCEANDSINK | A - SL_TK
Port_8603174_1 | SOURCEANDSINK | A - SL_TK
Port_8629845_2 | SOURCEANDSINK | A - SL_TK
Port_8603183_0 | SOURCEANDSINK | B - SL_NK-Str.01
Port_8610573_2 | SOURCEANDSINK | B - SL_NK-Str.01
Port_8603183_1 | SOURCEANDSINK | B - SL_NK-Str.01
Port_8632988_1 | SOURCEANDSINK | B - SL_NK-Str.01
Port_8603186_0 | SOURCEANDSINK | A - SL_NK-Str.01
Port_8632839_2 | SOURCEANDSINK | A - SL_NK-Str.01
Port_8603186_1 | SOURCEANDSINK | A - SL_NK-Str.01
Port_8632844_2 | SOURCEANDSINK | A - SL_NK-Str.01
Port_8603189_0 | SOURCEANDSINK | A - SL_TK
Port_8630055_2 | SOURCEANDSINK | A - SL_TK
Port_8603189_1 | SOURCEANDSINK | A - SL_TK
Port_8609859_1 | SOURCEANDSINK | A - SL_TK
Port_8603195_0 | SOURCEANDSINK | A - SL_TK
Port_8630055_1 | SOURCEANDSINK | A - SL_TK
Port_8603195_1 | SOURCEANDSINK | A - SL_TK
Port_8630058_2 | SOURCEANDSINK | A - SL_TK
Port_8603204_0 | SOURCEANDSINK | B - SL_TK
Port_8629713_1 | SOURCEANDSINK | B - SL_TK
Port_8603204_1 | SOURCEANDSINK | B - SL_TK
Port_8610105_1 | SOURCEANDSINK | B - SL_TK
Port_8603207_0 | SOURCEANDSINK | B - SL_TK
Port_8629701_4 | SOURCEANDSINK | B - SL_TK
Port_8603207_1 | SOURCEANDSINK | B - SL_TK
Port_8603210_0 | SOURCEANDSINK | B - SL_TK
Port_8629713_2 | SOURCEANDSINK | B - SL_TK
Port_8603210_1 | SOURCEANDSINK | B - SL_TK
Port_8629716_2 | SOURCEANDSINK | B - SL_TK
Port_8603219_0 | SOURCEANDSINK | A - SL_NK-Str.01
Port_8633119_2 | SOURCEANDSINK | A - SL_NK-Str.01
Port_8603219_1 | SOURCEANDSINK | A - SL_NK-Str.01
Port_8633124_2 | SOURCEANDSINK | A - SL_NK-Str.01
Port_8603222_0 | SOURCEANDSINK | B - SL_NK-Str.01
Port_8611453_2 | SOURCEANDSINK | B - SL_NK-Str.01
Port_8603222_1 | SOURCEANDSINK | B - SL_NK-Str.01
Port_8632586_1 | SOURCEANDSINK | B - SL_NK-Str.01
Port_8603225_0 | SOURCEANDSINK | A - SL_NK-Str.01
Port_8633476_2 | SOURCEANDSINK | A - SL_NK-Str.01
Port_8603225_1 | SOURCEANDSINK | A - SL_NK-Str.01
Port_8603341_4 | SOURCEANDSINK | A - SL_NK-Str.01
Port_8603236_0 | SOURCEANDSINK | A - SL_NK-Str.01
Port_8610850_5 | SOURCEANDSINK | A - SL_NK-Str.01
Port_8603236_1 | SOURCEANDSINK | A - SL_NK-Str.01
Port_8611226_2 | SOURCEANDSINK | A - SL_NK-Str.01
Port_8603243_0 | SOURCEANDSINK | B - SL_NK-Str.01
Port_8633716_2 | SOURCEANDSINK | B - SL_NK-Str.01
Port_8603243_1 | SOURCEANDSINK | B - SL_NK-Str.01
Port_8603353_4 | SOURCEANDSINK | B - SL_NK-Str.01
Port_8603259_0 | SOURCEANDSINK | B - SL_NK-Str.01
Port_8618200_4 | SOURCEANDSINK | B - SL_NK-Str.01
Port_8603259_1 | SOURCEANDSINK | B - SL_NK-Str.01
Port_8603264_0 | SOURCEANDSINK | A - SL_NK-Str.01
Port_8618078_1 | SOURCEANDSINK | A - SL_NK-Str.01
Port_8603264_1 | SOURCEANDSINK | A - SL_NK-Str.01
Port_8604955_2 | SOURCEANDSINK | A - SL_NK-Str.01
Port_8603270_0 | SOURCEANDSINK | B - SL_NK-Str.01
Port_8618212_2 | SOURCEANDSINK | B - SL_NK-Str.01
Port_8603270_1 | SOURCEANDSINK | B - SL_NK-Str.01
Port_8605081_2 | SOURCEANDSINK | B - SL_NK-Str.01
Port_8603286_0 | SOURCEANDSINK | B - SL_NK-Str.01
Port_8627632_2 | SOURCEANDSINK | B - SL_NK-Str.01
Port_8603286_1 | SOURCEANDSINK | B - SL_NK-Str.01
Port_8627637_2 | SOURCEANDSINK | B - SL_NK-Str.01
Port_8603289_0 | SOURCEANDSINK | B - SL_NK-Str.01
Port_8627623_1 | SOURCEANDSINK | B - SL_NK-Str.01
Port_8603289_1 | SOURCEANDSINK | B - SL_NK-Str.01
Port_8603294_0 | SOURCEANDSINK | A - SL_NK-Str.01
Port_8609159_2 | SOURCEANDSINK | A - SL_NK-Str.01
Port_8603294_1 | SOURCEANDSINK | A - SL_NK-Str.01
Port_8609162_2 | SOURCEANDSINK | A - SL_NK-Str.01
Port_8603297_0 | SOURCEANDSINK | A - SL_NK-Str.01
Port_8609159_1 | SOURCEANDSINK | A - SL_NK-Str.01
Port_8603297_1 | SOURCEANDSINK | A - SL_NK-Str.01
Port_8603309_0 | SOURCEANDSINK | B - SL_NK-Str.01
Port_8631316_2 | SOURCEANDSINK | B - SL_NK-Str.01
Port_8603309_1 | SOURCEANDSINK | B - SL_NK-Str.01
Port_8631321_2 | SOURCEANDSINK | B - SL_NK-Str.01
Port_8603312_0 | SOURCEANDSINK | B - SL_NK-Str.01
Port_8611527_2 | SOURCEANDSINK | B - SL_NK-Str.01
Port_8603312_1 | SOURCEANDSINK | B - SL_NK-Str.01
Port_8632294_1 | SOURCEANDSINK | B - SL_NK-Str.01
Port_8603315_0 | SOURCEANDSINK | B - SL_NK-Str.01
Port_8632130_2 | SOURCEANDSINK | B - SL_NK-Str.01
Port_8603315_1 | SOURCEANDSINK | B - SL_NK-Str.01
Port_8632135_2 | SOURCEANDSINK | B - SL_NK-Str.01
Port_8603318_0 | SOURCEANDSINK | A - SL_NK-Str.01
Port_8611322_2 | SOURCEANDSINK | A - SL_NK-Str.01
Port_8603318_1 | SOURCEANDSINK | A - SL_NK-Str.01
Port_8631902_1 | SOURCEANDSINK | A - SL_NK-Str.01
Port_8603321_0 | SOURCEANDSINK | A - SL_NK-Str.01
Port_8610339_2 | SOURCEANDSINK | A - SL_NK-Str.01
Port_8603321_1 | SOURCEANDSINK | A - SL_NK-Str.01
Port_8631753_1 | SOURCEANDSINK | A - SL_NK-Str.01
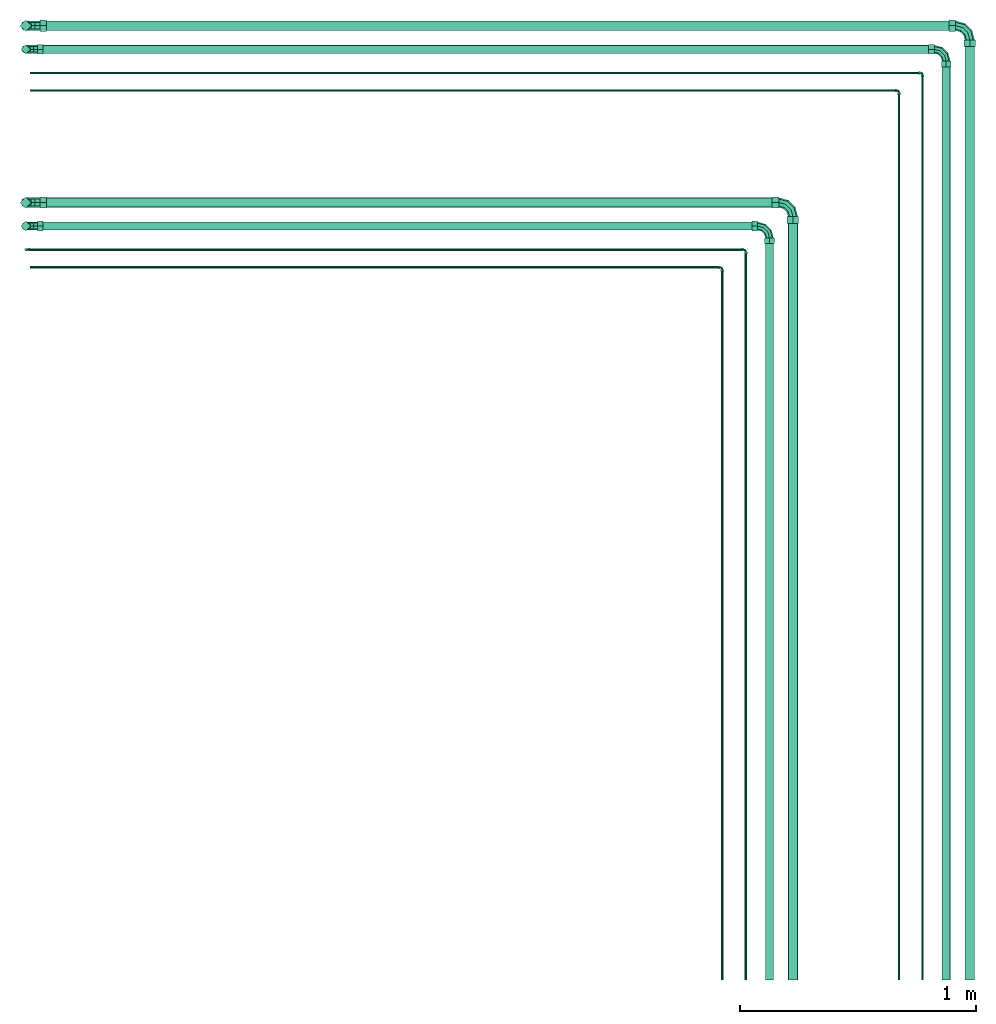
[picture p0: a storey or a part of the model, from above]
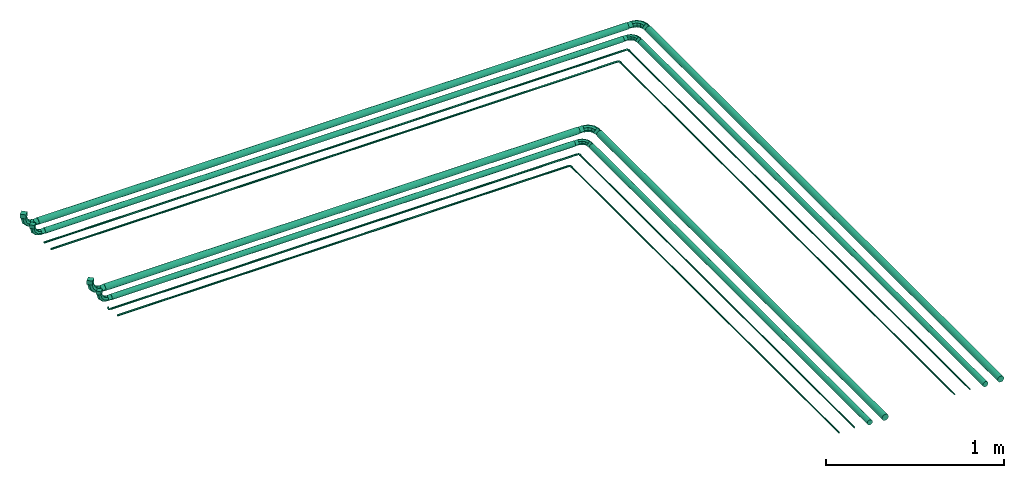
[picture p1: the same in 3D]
Properties of the parts of a building model (IFC2X3), part 4 of 7

# IfcDistributionPort (3410)
Name | FlowDirection | Group
Port_8603324_0 | SOURCEANDSINK | A - SL_NK-Str.01
Port_8631556_2 | SOURCEANDSINK | A - SL_NK-Str.01
Port_8603324_1 | SOURCEANDSINK | A - SL_NK-Str.01
Port_8631561_2 | SOURCEANDSINK | A - SL_NK-Str.01
Port_8603341_5 | SOURCEANDSINK | A - SL_NK-Str.01
Port_8603342_0 | SOURCEANDSINK | A - SL_NK-Str.01
Port_8603341_6 | SOURCEANDSINK | A - SL_NK-Str.01
Port_8613388_0 | SOURCEANDSINK | A - SL_NK-Str.01
Port_8603342_1 | SOURCEANDSINK | A - SL_NK-Str.01
Port_8612431_4 | SOURCEANDSINK | A - SL_NK-Str.01
Port_8603353_5 | SOURCEANDSINK | B - SL_NK-Str.01
Port_8603354_0 | SOURCEANDSINK | B - SL_NK-Str.01
Port_8603353_6 | SOURCEANDSINK | B - SL_NK-Str.01
Port_8613334_0 | SOURCEANDSINK | B - SL_NK-Str.01
Port_8603354_1 | SOURCEANDSINK | B - SL_NK-Str.01
Port_8613854_4 | SOURCEANDSINK | B - SL_NK-Str.01
Port_8603864_1 | SOURCEANDSINK | A - FL-Str.02_NK-KK-TK
Port_8603874_1 | SOURCEANDSINK | A - FL-Str.02_NK-KK-TK
Port_8603926_1 | SOURCEANDSINK | B - FL-Str.02_NK-KK-TK
Port_8603936_1 | SOURCEANDSINK | B - FL-Str.02_NK-KK-TK
Port_8603957_0 | SOURCEANDSINK | B - SL_KK
Port_8603959_2 | SOURCEANDSINK | B - SL_KK
Port_8603957_1 | SOURCEANDSINK | B - SL_KK
Port_8603973_1 | SOURCEANDSINK | B - SL_KK
Port_8603994_0 | SOURCEANDSINK | B - FL-Str.01_NK-KK-TK
Port_8603996_2 | SOURCEANDSINK | B - FL-Str.01_NK-KK-TK
Port_8603994_1 | SOURCEANDSINK | B - FL-Str.01_NK-KK-TK
Port_8604010_1 | SOURCEANDSINK | B - FL-Str.01_NK-KK-TK
Port_8604031_0 | SOURCEANDSINK | A - SL_KK
Port_8604033_2 | SOURCEANDSINK | A - SL_KK
Port_8604031_1 | SOURCEANDSINK | A - SL_KK
Port_8604047_1 | SOURCEANDSINK | A - SL_KK
Port_8604068_0 | SOURCEANDSINK | A - FL-Str.01_NK-KK-TK
Port_8604070_2 | SOURCEANDSINK | A - FL-Str.01_NK-KK-TK
Port_8604068_1 | SOURCEANDSINK | A - FL-Str.01_NK-KK-TK
Port_8604084_1 | SOURCEANDSINK | A - FL-Str.01_NK-KK-TK
Port_8604266_1 | SOURCEANDSINK | A - FL-Str.01_NK-KK-TK
Port_8604268_1 | SOURCEANDSINK | A - FL-Str.01_NK-KK-TK
Port_8604293_1 | SOURCEANDSINK | A - SL_KK
Port_8604295_1 | SOURCEANDSINK | A - SL_KK
Port_8604366_1 | SOURCEANDSINK | B - FL-Str.01_NK-KK-TK
Port_8620150_1 | SOURCEANDSINK | B - FL-Str.01_NK-KK-TK
Port_8604450_1 | SOURCEANDSINK | B - FL-Str.01_NK-KK-TK
Port_8619390_1 | SOURCEANDSINK | B - FL-Str.01_NK-KK-TK
Port_8604477_1 | SOURCEANDSINK | B - SL_KK
Port_8619427_1 | SOURCEANDSINK | B - SL_KK
Port_8604544_1 | SOURCEANDSINK | A - SL_KK
Port_8620235_1 | SOURCEANDSINK | A - SL_KK
Port_8604571_1 | SOURCEANDSINK | A - FL-Str.01_NK-KK-TK
Port_8620273_1 | SOURCEANDSINK | A - FL-Str.01_NK-KK-TK
Port_8604598_1 | SOURCEANDSINK | B - SL_KK
Port_8620097_1 | SOURCEANDSINK | B - SL_KK
Port_8604645_1 | SOURCEANDSINK | B - FL-Str.02_NK-KK-TK
Port_8604647_1 | SOURCEANDSINK | B - FL-Str.02_NK-KK-TK
Port_8604698_1 | SOURCEANDSINK | B - SL_KK
Port_8630348_1 | SOURCEANDSINK | B - SL_KK
Port_8604745_1 | SOURCEANDSINK | A - SL_KK
Port_8630491_1 | SOURCEANDSINK | A - SL_KK
Port_8604814_1 | SOURCEANDSINK | A - FL-Str.01_NK-KK-TK
Port_8604825_1 | SOURCEANDSINK | A - FL-Str.01_NK-KK-TK
Port_8604944_1 | SOURCEANDSINK | A - SL_NK-Str.01
Port_8604955_1 | SOURCEANDSINK | A - SL_NK-Str.01
Port_8605017_1 | SOURCEANDSINK | B - FL-Str.01_NK-KK-TK
Port_8605028_1 | SOURCEANDSINK | B - FL-Str.01_NK-KK-TK
Port_8605070_1 | SOURCEANDSINK | B - SL_NK-Str.01
Port_8605081_1 | SOURCEANDSINK | B - SL_NK-Str.01
Port_8605149_1 | SOURCEANDSINK | A - FL-Str.02_NK-KK-TK
Port_8605151_1 | SOURCEANDSINK | A - FL-Str.02_NK-KK-TK
Port_8605202_1 | SOURCEANDSINK | B - SL_KK
Port_8628597_1 | SOURCEANDSINK | B - SL_KK
Port_8605260_1 | SOURCEANDSINK | B - FL-Str.01_NK-KK-TK
Port_8628752_1 | SOURCEANDSINK | B - FL-Str.01_NK-KK-TK
Port_8605352_1 | SOURCEANDSINK | B - FL-Str.01_NK-KK-TK
Port_8605362_1 | SOURCEANDSINK | B - FL-Str.01_NK-KK-TK
Port_8605362_2 | SOURCEANDSINK | B - FL-Str.01_NK-KK-TK
Port_8629148_0 | SOURCEANDSINK | B - FL-Str.01_NK-KK-TK
Port_8605384_1 | SOURCEANDSINK | B - SL_KK
Port_8605394_1 | SOURCEANDSINK | B - SL_KK
Port_8605394_2 | SOURCEANDSINK | B - SL_KK
Port_8629108_0 | SOURCEANDSINK | B - SL_KK
Port_8605476_1 | SOURCEANDSINK | A - FL-Str.01_NK-KK-TK
Port_8628859_1 | SOURCEANDSINK | A - FL-Str.01_NK-KK-TK
Port_8605508_1 | SOURCEANDSINK | A - SL_KK
Port_8628806_1 | SOURCEANDSINK | A - SL_KK
Port_8605670_1 | SOURCEANDSINK | A - FL-Str.01_NK-KK-TK
Port_8617835_1 | SOURCEANDSINK | A - FL-Str.01_NK-KK-TK
Port_8605702_1 | SOURCEANDSINK | A - SL_KK
Port_8617827_1 | SOURCEANDSINK | A - SL_KK
Port_8605834_1 | SOURCEANDSINK | B - SL_KK
Port_8605836_1 | SOURCEANDSINK | B - SL_KK
Port_8605861_1 | SOURCEANDSINK | B - FL-Str.01_NK-KK-TK
Port_8605863_1 | SOURCEANDSINK | B - FL-Str.01_NK-KK-TK
Port_8605888_1 | SOURCEANDSINK | B - SL_KK
Port_8621123_1 | SOURCEANDSINK | B - SL_KK
Port_8605915_1 | SOURCEANDSINK | B - FL-Str.01_NK-KK-TK
Port_8605917_1 | SOURCEANDSINK | B - FL-Str.01_NK-KK-TK
Port_8606002_1 | SOURCEANDSINK | A - SL_KK
Port_8619818_1 | SOURCEANDSINK | A - SL_KK
Port_8606029_1 | SOURCEANDSINK | A - FL-Str.01_NK-KK-TK
Port_8619780_1 | SOURCEANDSINK | A - FL-Str.01_NK-KK-TK
Port_8606106_1 | SOURCEANDSINK | B - FL-Str.01_NK-KK-TK
Port_8606108_1 | SOURCEANDSINK | B - FL-Str.01_NK-KK-TK
Port_8606172_1 | SOURCEANDSINK | B - SL_KK
Port_8616849_1 | SOURCEANDSINK | B - SL_KK
Port_8606239_1 | SOURCEANDSINK | B - SL_KK
Port_8606241_1 | SOURCEANDSINK | B - SL_KK
Port_8606266_1 | SOURCEANDSINK | B - FL-Str.01_NK-KK-TK
Port_8606268_1 | SOURCEANDSINK | B - FL-Str.01_NK-KK-TK
Port_8606353_1 | SOURCEANDSINK | A - FL-Str.01_NK-KK-TK
Port_8620557_1 | SOURCEANDSINK | A - FL-Str.01_NK-KK-TK
Port_8606380_1 | SOURCEANDSINK | A - SL_KK
Port_8620518_1 | SOURCEANDSINK | A - SL_KK
Port_8606487_1 | SOURCEANDSINK | B - SL_KK
Port_8618707_1 | SOURCEANDSINK | B - SL_KK
Port_8606514_1 | SOURCEANDSINK | B - FL-Str.01_NK-KK-TK
Port_8618699_1 | SOURCEANDSINK | B - FL-Str.01_NK-KK-TK
Port_8606541_1 | SOURCEANDSINK | A - SL_KK
Port_8619322_1 | SOURCEANDSINK | A - SL_KK
Port_8606568_1 | SOURCEANDSINK | A - FL-Str.01_NK-KK-TK
Port_8619284_1 | SOURCEANDSINK | A - FL-Str.01_NK-KK-TK
Port_8606696_0 | SOURCEANDSINK | A - SL_KK
Port_8606911_6 | SOURCEANDSINK | A - SL_KK
Port_8606696_1 | SOURCEANDSINK | A - SL_KK
Port_8606939_6 | SOURCEANDSINK | A - SL_KK
Port_8606699_0 | SOURCEANDSINK | A - FL-Str.01_NK-KK-TK
Port_8606888_6 | SOURCEANDSINK | A - FL-Str.01_NK-KK-TK
Port_8606699_1 | SOURCEANDSINK | A - FL-Str.01_NK-KK-TK
Port_8606993_6 | SOURCEANDSINK | A - FL-Str.01_NK-KK-TK
Port_8606888_5 | SOURCEANDSINK | A - FL-Str.01_NK-KK-TK
Port_8606889_0 | SOURCEANDSINK | A - FL-Str.01_NK-KK-TK
Port_8606889_1 | SOURCEANDSINK | A - FL-Str.01_NK-KK-TK
Port_8620753_2 | SOURCEANDSINK | A - FL-Str.01_NK-KK-TK
Port_8606939_5 | SOURCEANDSINK | A - SL_KK
Port_8606940_1 | SOURCEANDSINK | A - SL_KK
Port_8606993_5 | SOURCEANDSINK | A - FL-Str.01_NK-KK-TK
Port_8606994_1 | SOURCEANDSINK | A - FL-Str.01_NK-KK-TK
Port_8607185_1 | SOURCEANDSINK | A - FL-Str.03_NK-KK-TK
Port_8623227_1 | SOURCEANDSINK | A - FL-Str.03_NK-KK-TK
Port_8607252_1 | SOURCEANDSINK | B - FL-Str.03_NK-KK-TK
Port_8607254_1 | SOURCEANDSINK | B - FL-Str.03_NK-KK-TK
Port_8607296_0 | SOURCEANDSINK | B - SL_NK-Str.02
Port_8607298_2 | SOURCEANDSINK | B - SL_NK-Str.02
Port_8607296_1 | SOURCEANDSINK | B - SL_NK-Str.02
Port_8607309_1 | SOURCEANDSINK | B - SL_NK-Str.02
Port_8607367_1 | SOURCEANDSINK | B - FL-Str.03_NK-KK-TK
Port_8607369_1 | SOURCEANDSINK | B - FL-Str.03_NK-KK-TK
Port_8607511_1 | SOURCEANDSINK | B - SL_NK-Str.02
Port_8622347_1 | SOURCEANDSINK | B - SL_NK-Str.02
Port_8607568_1 | SOURCEANDSINK | B - FL-Str.03_NK-KK-TK
Port_8622355_1 | SOURCEANDSINK | B - FL-Str.03_NK-KK-TK
Port_8607625_1 | SOURCEANDSINK | A - SL_NK-Str.02
Port_8607627_1 | SOURCEANDSINK | A - SL_NK-Str.02
Port_8607682_1 | SOURCEANDSINK | A - FL-Str.03_NK-KK-TK
Port_8607684_1 | SOURCEANDSINK | A - FL-Str.03_NK-KK-TK
Port_8607829_1 | SOURCEANDSINK | A - SL_NK-Str.02
Port_8607831_1 | SOURCEANDSINK | A - SL_NK-Str.02
Port_8607856_1 | SOURCEANDSINK | A - FL-Str.03_NK-KK-TK
Port_8607858_1 | SOURCEANDSINK | A - FL-Str.03_NK-KK-TK
Port_8607883_1 | SOURCEANDSINK | B - SL_NK-Str.02
Port_8607885_1 | SOURCEANDSINK | B - SL_NK-Str.02
Port_8607910_1 | SOURCEANDSINK | B - FL-Str.03_NK-KK-TK
Port_8607912_1 | SOURCEANDSINK | B - FL-Str.03_NK-KK-TK
Port_8608063_1 | SOURCEANDSINK | B - FL-Str.03_NK-KK-TK
Port_8608065_1 | SOURCEANDSINK | B - FL-Str.03_NK-KK-TK
Port_8608090_1 | SOURCEANDSINK | B - SL_NK-Str.02
Port_8608092_1 | SOURCEANDSINK | B - SL_NK-Str.02
Port_8608117_1 | SOURCEANDSINK | A - SL_NK-Str.02
Port_8608119_1 | SOURCEANDSINK | A - SL_NK-Str.02
Port_8608144_1 | SOURCEANDSINK | A - FL-Str.03_NK-KK-TK
Port_8608146_1 | SOURCEANDSINK | A - FL-Str.03_NK-KK-TK
Port_8608231_1 | SOURCEANDSINK | B - SL_NK-Str.02
Port_8608233_1 | SOURCEANDSINK | B - SL_NK-Str.02
Port_8608275_1 | SOURCEANDSINK | B - FL-Str.03_NK-KK-TK
Port_8621697_1 | SOURCEANDSINK | B - FL-Str.03_NK-KK-TK
Port_8608336_1 | SOURCEANDSINK | A - SL_NK-Str.02
Port_8608347_1 | SOURCEANDSINK | A - SL_NK-Str.02
Port_8608399_1 | SOURCEANDSINK | A - SL_NK-Str.02
Port_8608410_1 | SOURCEANDSINK | A - SL_NK-Str.02
Port_8608465_1 | SOURCEANDSINK | A - SL_NK-Str.02
Port_8608476_1 | SOURCEANDSINK | A - SL_NK-Str.02
Port_8608633_1 | SOURCEANDSINK | A - FL-Str.03_NK-KK-TK
Port_8624965_1 | SOURCEANDSINK | A - FL-Str.03_NK-KK-TK
Port_8608660_1 | SOURCEANDSINK | A - FL-Str.03_NK-KK-TK
Port_8608671_1 | SOURCEANDSINK | A - FL-Str.03_NK-KK-TK
Port_8608766_0 | SOURCEANDSINK | B - SL_NK-Str.02
Port_8625089_2 | SOURCEANDSINK | B - SL_NK-Str.02
Port_8608766_1 | SOURCEANDSINK | B - SL_NK-Str.02
Port_8625094_2 | SOURCEANDSINK | B - SL_NK-Str.02
Port_8608801_0 | SOURCEANDSINK | B - FL-Str.03_NK-KK-TK
Port_8625147_2 | SOURCEANDSINK | B - FL-Str.03_NK-KK-TK
Port_8608801_1 | SOURCEANDSINK | B - FL-Str.03_NK-KK-TK
Port_8625152_2 | SOURCEANDSINK | B - FL-Str.03_NK-KK-TK
Port_8608904_1 | SOURCEANDSINK | B - FL-Str.03_NK-KK-TK
Port_8625147_1 | SOURCEANDSINK | B - FL-Str.03_NK-KK-TK
Port_8608941_1 | SOURCEANDSINK | B - SL_NK-Str.02
Port_8625089_1 | SOURCEANDSINK | B - SL_NK-Str.02
Port_8609151_1 | SOURCEANDSINK | A - SL_NK-Str.01
Port_8609162_1 | SOURCEANDSINK | A - SL_NK-Str.01
Port_8609184_1 | SOURCEANDSINK | A - FL-Str.02_NK-KK-TK
Port_8609194_1 | SOURCEANDSINK | A - FL-Str.02_NK-KK-TK
Port_8609356_1 | SOURCEANDSINK | B - SL_TK
Port_8627095_1 | SOURCEANDSINK | B - SL_TK
Port_8609383_1 | SOURCEANDSINK | B - SL_NK-Str.01
Port_8627632_1 | SOURCEANDSINK | B - SL_NK-Str.01
Port_8609416_1 | SOURCEANDSINK | B - FL-Str.02_NK-KK-TK
Port_8627590_1 | SOURCEANDSINK | B - FL-Str.02_NK-KK-TK
Port_8609448_1 | SOURCEANDSINK | B - FL-Str.02_NK-KK-TK
Port_8609450_1 | SOURCEANDSINK | B - FL-Str.02_NK-KK-TK
Port_8609515_1 | SOURCEANDSINK | A - FL-Str.02_NK-KK-TK
Port_8616141_1 | SOURCEANDSINK | A - FL-Str.02_NK-KK-TK
Port_8609544_1 | SOURCEANDSINK | A - SL_NK-Str.01
Port_8631556_1 | SOURCEANDSINK | A - SL_NK-Str.01
Port_8609724_1 | SOURCEANDSINK | B - FL-Str.02_NK-KK-TK
Port_8609735_1 | SOURCEANDSINK | B - FL-Str.02_NK-KK-TK
Port_8609757_1 | SOURCEANDSINK | B - SL_TK
Port_8609768_1 | SOURCEANDSINK | B - SL_TK
Port_8609790_1 | SOURCEANDSINK | B - SL_NK-Str.01
Port_8631316_1 | SOURCEANDSINK | B - SL_NK-Str.01
Port_8609857_0 | SOURCEANDSINK | A - SL_TK
Port_8609859_2 | SOURCEANDSINK | A - SL_TK
Port_8609857_1 | SOURCEANDSINK | A - SL_TK
Port_8609870_1 | SOURCEANDSINK | A - SL_TK
Port_8609932_1 | SOURCEANDSINK | A - FL-Str.02_NK-KK-TK
Port_8609943_1 | SOURCEANDSINK | A - FL-Str.02_NK-KK-TK
Port_8610025_1 | SOURCEANDSINK | A - SL_NK-Str.01
Port_8633119_1 | SOURCEANDSINK | A - SL_NK-Str.01
Port_8610052_1 | SOURCEANDSINK | A - FL-Str.02_NK-KK-TK
Port_8633167_1 | SOURCEANDSINK | A - FL-Str.02_NK-KK-TK
Port_8610103_0 | SOURCEANDSINK | B - SL_TK
Port_8610105_2 | SOURCEANDSINK | B - SL_TK
Port_8610103_1 | SOURCEANDSINK | B - SL_TK
Port_8610116_1 | SOURCEANDSINK | B - SL_TK
Port_8610184_1 | SOURCEANDSINK | B - FL-Str.02_NK-KK-TK
Port_8610195_1 | SOURCEANDSINK | B - FL-Str.02_NK-KK-TK
Port_8610337_1 | SOURCEANDSINK | A - SL_NK-Str.01
Port_8610339_1 | SOURCEANDSINK | A - SL_NK-Str.01
Port_8610364_1 | SOURCEANDSINK | A - FL-Str.02_NK-KK-TK
Port_8610375_1 | SOURCEANDSINK | A - FL-Str.02_NK-KK-TK
Port_8610397_1 | SOURCEANDSINK | A - SL_TK
Port_8610408_1 | SOURCEANDSINK | A - SL_TK
Port_8610430_1 | SOURCEANDSINK | A - FL-Str.02_NK-KK-TK
Port_8632793_1 | SOURCEANDSINK | A - FL-Str.02_NK-KK-TK
Port_8610457_1 | SOURCEANDSINK | A - SL_NK-Str.01
Port_8632839_1 | SOURCEANDSINK | A - SL_NK-Str.01
Port_8610544_1 | SOURCEANDSINK | B - FL-Str.02_NK-KK-TK
Port_8610546_1 | SOURCEANDSINK | B - FL-Str.02_NK-KK-TK
Port_8610571_1 | SOURCEANDSINK | B - SL_NK-Str.01
Port_8610573_1 | SOURCEANDSINK | B - SL_NK-Str.01
Port_8610850_4 | SOURCEANDSINK | A - SL_NK-Str.01
Port_8612432_0 | SOURCEANDSINK | A - SL_NK-Str.01
Port_8610850_6 | SOURCEANDSINK | A - SL_NK-Str.01
Port_8614671_0 | SOURCEANDSINK | A - SL_NK-Str.01
Port_8610894_4 | SOURCEANDSINK | A - FL-Str.02_NK-KK-TK
Port_8612505_0 | SOURCEANDSINK | A - FL-Str.02_NK-KK-TK
Port_8610894_6 | SOURCEANDSINK | A - FL-Str.02_NK-KK-TK
Port_8614632_0 | SOURCEANDSINK | A - FL-Str.02_NK-KK-TK
Port_8610976_0 | SOURCEANDSINK | A - FL-Str.02_NK-KK-TK
Port_8611175_4 | SOURCEANDSINK | A - FL-Str.02_NK-KK-TK
Port_8610976_1 | SOURCEANDSINK | A - FL-Str.02_NK-KK-TK
Port_8610985_0 | SOURCEANDSINK | A - SL_NK-Str.01
Port_8611212_4 | SOURCEANDSINK | A - SL_NK-Str.01
Port_8610985_1 | SOURCEANDSINK | A - SL_NK-Str.01
Port_8610993_0 | SOURCEANDSINK | A - FL-Str.02_NK-KK-TK
Port_8612711_5 | SOURCEANDSINK | A - FL-Str.02_NK-KK-TK
Port_8610993_1 | SOURCEANDSINK | A - FL-Str.02_NK-KK-TK
Port_8610996_0 | SOURCEANDSINK | A - FL-Str.02_NK-KK-TK
Port_8612711_4 | SOURCEANDSINK | A - FL-Str.02_NK-KK-TK
Port_8610996_1 | SOURCEANDSINK | A - FL-Str.02_NK-KK-TK
Port_8611000_0 | SOURCEANDSINK | B - FL-Str.02_NK-KK-TK
Port_8612234_5 | SOURCEANDSINK | B - FL-Str.02_NK-KK-TK
Port_8611000_1 | SOURCEANDSINK | B - FL-Str.02_NK-KK-TK
Port_8611002_0 | SOURCEANDSINK | B - FL-Str.02_NK-KK-TK
Port_8612234_4 | SOURCEANDSINK | B - FL-Str.02_NK-KK-TK
Port_8611002_1 | SOURCEANDSINK | B - FL-Str.02_NK-KK-TK
Port_8611008_0 | SOURCEANDSINK | B - FL-Str.02_NK-KK-TK
Port_8613736_4 | SOURCEANDSINK | B - FL-Str.02_NK-KK-TK
Port_8611008_1 | SOURCEANDSINK | B - FL-Str.02_NK-KK-TK
Port_8611011_0 | SOURCEANDSINK | A - SL_NK-Str.01
Port_8611050_4 | SOURCEANDSINK | A - SL_NK-Str.01
Port_8611011_1 | SOURCEANDSINK | A - SL_NK-Str.01
Port_8613398_2 | SOURCEANDSINK | A - SL_NK-Str.01
Port_8611013_0 | SOURCEANDSINK | A - SL_NK-Str.01
Port_8611056_2 | SOURCEANDSINK | A - SL_NK-Str.01
Port_8611013_1 | SOURCEANDSINK | A - SL_NK-Str.01
Port_8623291_1 | SOURCEANDSINK | A - SL_NK-Str.01
Port_8611016_0 | SOURCEANDSINK | A - SL_NK-Str.01
Port_8624142_2 | SOURCEANDSINK | A - SL_NK-Str.01
Port_8611016_1 | SOURCEANDSINK | A - SL_NK-Str.01
Port_8624147_2 | SOURCEANDSINK | A - SL_NK-Str.01
Port_8611020_0 | SOURCEANDSINK | B - SL_NK-Str.01
Port_8611044_4 | SOURCEANDSINK | B - SL_NK-Str.01
Port_8611020_1 | SOURCEANDSINK | B - SL_NK-Str.01
Port_8613344_2 | SOURCEANDSINK | B - SL_NK-Str.01
Port_8611022_0 | SOURCEANDSINK | B - SL_NK-Str.01
Port_8623857_1 | SOURCEANDSINK | B - SL_NK-Str.01
Port_8611022_1 | SOURCEANDSINK | B - SL_NK-Str.01
Port_8624371_1 | SOURCEANDSINK | B - SL_NK-Str.01
Port_8611025_0 | SOURCEANDSINK | B - SL_NK-Str.01
Port_8624274_2 | SOURCEANDSINK | B - SL_NK-Str.01
Port_8611025_1 | SOURCEANDSINK | B - SL_NK-Str.01
Port_8624277_2 | SOURCEANDSINK | B - SL_NK-Str.01
Port_8611029_0 | SOURCEANDSINK | A - SL_NK-Str.01
Port_8612680_4 | SOURCEANDSINK | A - SL_NK-Str.01
Port_8611029_1 | SOURCEANDSINK | A - SL_NK-Str.01
Port_8611032_0 | SOURCEANDSINK | A - SL_NK-Str.01
Port_8612680_5 | SOURCEANDSINK | A - SL_NK-Str.01
Port_8611032_1 | SOURCEANDSINK | A - SL_NK-Str.01
Port_8611044_5 | SOURCEANDSINK | B - SL_NK-Str.01
Port_8611045_0 | SOURCEANDSINK | B - SL_NK-Str.01
Port_8611044_6 | SOURCEANDSINK | B - SL_NK-Str.01
Port_8624266_0 | SOURCEANDSINK | B - SL_NK-Str.01
Port_8611045_1 | SOURCEANDSINK | B - SL_NK-Str.01
Port_8624382_2 | SOURCEANDSINK | B - SL_NK-Str.01
Port_8611050_5 | SOURCEANDSINK | A - SL_NK-Str.01
Port_8611051_1 | SOURCEANDSINK | A - SL_NK-Str.01
Port_8611050_6 | SOURCEANDSINK | A - SL_NK-Str.01
Port_8624134_0 | SOURCEANDSINK | A - SL_NK-Str.01
Port_8611051_0 | SOURCEANDSINK | A - SL_NK-Str.01
Port_8611056_1 | SOURCEANDSINK | A - SL_NK-Str.01
Port_8611173_0 | SOURCEANDSINK | A - FL-Str.02_NK-KK-TK
Port_8611175_6 | SOURCEANDSINK | A - FL-Str.02_NK-KK-TK
Port_8611173_1 | SOURCEANDSINK | A - FL-Str.02_NK-KK-TK
Port_8611189_1 | SOURCEANDSINK | A - FL-Str.02_NK-KK-TK
Port_8611175_5 | SOURCEANDSINK | A - FL-Str.02_NK-KK-TK
Port_8611176_1 | SOURCEANDSINK | A - FL-Str.02_NK-KK-TK
Port_8611176_0 | SOURCEANDSINK | A - FL-Str.02_NK-KK-TK
Port_8611210_0 | SOURCEANDSINK | A - SL_NK-Str.01
Port_8611212_6 | SOURCEANDSINK | A - SL_NK-Str.01
Port_8611210_1 | SOURCEANDSINK | A - SL_NK-Str.01
Port_8611226_1 | SOURCEANDSINK | A - SL_NK-Str.01
Port_8611212_5 | SOURCEANDSINK | A - SL_NK-Str.01
Port_8611213_1 | SOURCEANDSINK | A - SL_NK-Str.01
Port_8611213_0 | SOURCEANDSINK | A - SL_NK-Str.01
Port_8611320_1 | SOURCEANDSINK | A - SL_NK-Str.01
Port_8611322_1 | SOURCEANDSINK | A - SL_NK-Str.01
Port_8611407_1 | SOURCEANDSINK | B - FL-Str.02_NK-KK-TK
Port_8632548_1 | SOURCEANDSINK | B - FL-Str.02_NK-KK-TK
Port_8611451_1 | SOURCEANDSINK | B - SL_NK-Str.01
Port_8611453_1 | SOURCEANDSINK | B - SL_NK-Str.01
Port_8611478_1 | SOURCEANDSINK | B - SL_NK-Str.01
Port_8632130_1 | SOURCEANDSINK | B - SL_NK-Str.01
Port_8611525_1 | SOURCEANDSINK | B - SL_NK-Str.01
Port_8611527_1 | SOURCEANDSINK | B - SL_NK-Str.01
Port_8611575_0 | SOURCEANDSINK | B - SL_KK
Port_8611577_2 | SOURCEANDSINK | B - SL_KK
Port_8611575_1 | SOURCEANDSINK | B - SL_KK
Port_8631151_1 | SOURCEANDSINK | B - SL_KK
Port_8611628_0 | SOURCEANDSINK | A - SL_KK
Port_8616207_1 | SOURCEANDSINK | A - SL_KK
Port_8611628_1 | SOURCEANDSINK | A - SL_KK
Port_8611641_1 | SOURCEANDSINK | A - SL_KK
Port_8611683_1 | SOURCEANDSINK | A - FL-Str.01_NK-KK-TK
Port_8631606_1 | SOURCEANDSINK | A - FL-Str.01_NK-KK-TK
Port_8611750_1 | SOURCEANDSINK | B - FL-Str.01_NK-KK-TK
Port_8631266_1 | SOURCEANDSINK | B - FL-Str.01_NK-KK-TK
Port_8611817_1 | SOURCEANDSINK | A - FL-Str.01_NK-KK-TK
Port_8631714_1 | SOURCEANDSINK | A - FL-Str.01_NK-KK-TK
Port_8611866_0 | SOURCEANDSINK | A - FL-Str.01_NK-KK-TK
Port_8611868_2 | SOURCEANDSINK | A - FL-Str.01_NK-KK-TK
Port_8611866_1 | SOURCEANDSINK | A - FL-Str.01_NK-KK-TK
Port_8611879_1 | SOURCEANDSINK | A - FL-Str.01_NK-KK-TK
Port_8611931_1 | SOURCEANDSINK | B - FL-Str.01_NK-KK-TK
Port_8611933_1 | SOURCEANDSINK | B - FL-Str.01_NK-KK-TK
Port_8611980_0 | SOURCEANDSINK | B - FL-Str.01_NK-KK-TK
Port_8632080_1 | SOURCEANDSINK | B - FL-Str.01_NK-KK-TK
Port_8611980_1 | SOURCEANDSINK | B - FL-Str.01_NK-KK-TK
Port_8611993_1 | SOURCEANDSINK | B - FL-Str.01_NK-KK-TK
Port_8612143_0 | SOURCEANDSINK | B - FL-Str.02_NK-KK-TK
Port_8612145_6 | SOURCEANDSINK | B - FL-Str.02_NK-KK-TK
Port_8612143_1 | SOURCEANDSINK | B - FL-Str.02_NK-KK-TK
Port_8612234_6 | SOURCEANDSINK | B - FL-Str.02_NK-KK-TK
Port_8612145_4 | SOURCEANDSINK | B - FL-Str.02_NK-KK-TK
Port_8614004_0 | SOURCEANDSINK | B - FL-Str.02_NK-KK-TK
Port_8612145_5 | SOURCEANDSINK | B - FL-Str.02_NK-KK-TK
Port_8612146_1 | SOURCEANDSINK | B - FL-Str.02_NK-KK-TK
Port_8612146_0 | SOURCEANDSINK | B - FL-Str.02_NK-KK-TK
Port_8615116_2 | SOURCEANDSINK | B - FL-Str.02_NK-KK-TK
Port_8612293_0 | SOURCEANDSINK | B - SL_NK-Str.01
Port_8612295_6 | SOURCEANDSINK | B - SL_NK-Str.01
Port_8612293_1 | SOURCEANDSINK | B - SL_NK-Str.01
Port_8613188_6 | SOURCEANDSINK | B - SL_NK-Str.01
Port_8612295_4 | SOURCEANDSINK | B - SL_NK-Str.01
Port_8613855_0 | SOURCEANDSINK | B - SL_NK-Str.01
Port_8612295_5 | SOURCEANDSINK | B - SL_NK-Str.01
Port_8612296_1 | SOURCEANDSINK | B - SL_NK-Str.01
Port_8612296_0 | SOURCEANDSINK | B - SL_NK-Str.01
Port_8615108_2 | SOURCEANDSINK | B - SL_NK-Str.01
Port_8612429_0 | SOURCEANDSINK | A - SL_NK-Str.01
Port_8612431_6 | SOURCEANDSINK | A - SL_NK-Str.01
Port_8612429_1 | SOURCEANDSINK | A - SL_NK-Str.01
Port_8612680_6 | SOURCEANDSINK | A - SL_NK-Str.01
Port_8612431_5 | SOURCEANDSINK | A - SL_NK-Str.01
Port_8612432_1 | SOURCEANDSINK | A - SL_NK-Str.01
Port_8612502_0 | SOURCEANDSINK | A - FL-Str.02_NK-KK-TK
Port_8612504_6 | SOURCEANDSINK | A - FL-Str.02_NK-KK-TK
Port_8612502_1 | SOURCEANDSINK | A - FL-Str.02_NK-KK-TK
Port_8612711_6 | SOURCEANDSINK | A - FL-Str.02_NK-KK-TK
Port_8612504_5 | SOURCEANDSINK | A - FL-Str.02_NK-KK-TK
Port_8612505_1 | SOURCEANDSINK | A - FL-Str.02_NK-KK-TK
Port_8613124_0 | SOURCEANDSINK | B - SL_NK-Str.01
Port_8613188_4 | SOURCEANDSINK | B - SL_NK-Str.01
Port_8613124_1 | SOURCEANDSINK | B - SL_NK-Str.01
Port_8613188_5 | SOURCEANDSINK | B - SL_NK-Str.01
Port_8613189_1 | SOURCEANDSINK | B - SL_NK-Str.01
Port_8613189_0 | SOURCEANDSINK | B - SL_NK-Str.01
Port_8613334_1 | SOURCEANDSINK | B - SL_NK-Str.01
Port_8613344_1 | SOURCEANDSINK | B - SL_NK-Str.01
Port_8613388_1 | SOURCEANDSINK | A - SL_NK-Str.01
Port_8613398_1 | SOURCEANDSINK | A - SL_NK-Str.01
Port_8613485_0 | SOURCEANDSINK | B - SL_NK-Str.01
Port_8613691_4 | SOURCEANDSINK | B - SL_NK-Str.01
Port_8613485_1 | SOURCEANDSINK | B - SL_NK-Str.01
Port_8613689_0 | SOURCEANDSINK | B - SL_NK-Str.01
Port_8613691_6 | SOURCEANDSINK | B - SL_NK-Str.01
Port_8613689_1 | SOURCEANDSINK | B - SL_NK-Str.01
Port_8613854_6 | SOURCEANDSINK | B - SL_NK-Str.01
Port_8613691_5 | SOURCEANDSINK | B - SL_NK-Str.01
Port_8613692_1 | SOURCEANDSINK | B - SL_NK-Str.01
Port_8613692_0 | SOURCEANDSINK | B - SL_NK-Str.01
Port_8613734_0 | SOURCEANDSINK | B - FL-Str.02_NK-KK-TK
Port_8613736_6 | SOURCEANDSINK | B - FL-Str.02_NK-KK-TK
Port_8613734_1 | SOURCEANDSINK | B - FL-Str.02_NK-KK-TK
Port_8614003_6 | SOURCEANDSINK | B - FL-Str.02_NK-KK-TK
Port_8613736_5 | SOURCEANDSINK | B - FL-Str.02_NK-KK-TK
Port_8613737_1 | SOURCEANDSINK | B - FL-Str.02_NK-KK-TK
Port_8613737_0 | SOURCEANDSINK | B - FL-Str.02_NK-KK-TK
Port_8613854_5 | SOURCEANDSINK | B - SL_NK-Str.01
Port_8613855_1 | SOURCEANDSINK | B - SL_NK-Str.01
Port_8614003_5 | SOURCEANDSINK | B - FL-Str.02_NK-KK-TK
Port_8614004_1 | SOURCEANDSINK | B - FL-Str.02_NK-KK-TK
Port_8614428_1 | SOURCEANDSINK | A - FL-Str.02_NK-KK-TK
Port_8615039_2 | SOURCEANDSINK | A - FL-Str.02_NK-KK-TK
Port_8614468_1 | SOURCEANDSINK | A - SL_NK-Str.01
Port_8614991_2 | SOURCEANDSINK | A - SL_NK-Str.01
Port_8614490_1 | SOURCEANDSINK | B - FL-Str.02_NK-KK-TK
Port_8614898_2 | SOURCEANDSINK | B - FL-Str.02_NK-KK-TK
Port_8614603_1 | SOURCEANDSINK | B - SL_NK-Str.01
Port_8614943_2 | SOURCEANDSINK | B - SL_NK-Str.01
Port_8614632_1 | SOURCEANDSINK | A - FL-Str.02_NK-KK-TK
Port_8615099_1 | SOURCEANDSINK | A - FL-Str.02_NK-KK-TK
Port_8614671_1 | SOURCEANDSINK | A - SL_NK-Str.01
Port_8615071_1 | SOURCEANDSINK | A - SL_NK-Str.01
Port_8614846_0 | SOURCEANDSINK | B - FL-Str.02_NK-KK-TK
Port_8614885_1 | SOURCEANDSINK | B - FL-Str.02_NK-KK-TK
Port_8614846_1 | SOURCEANDSINK | B - FL-Str.02_NK-KK-TK
Port_8615116_1 | SOURCEANDSINK | B - FL-Str.02_NK-KK-TK
Port_8614848_0 | SOURCEANDSINK | A - FL-Str.02_NK-KK-TK
Port_8615094_2 | SOURCEANDSINK | A - FL-Str.02_NK-KK-TK
Port_8614848_1 | SOURCEANDSINK | A - FL-Str.02_NK-KK-TK
Port_8615099_2 | SOURCEANDSINK | A - FL-Str.02_NK-KK-TK
Port_8614852_0 | SOURCEANDSINK | B - SL_NK-Str.01
Port_8615108_1 | SOURCEANDSINK | B - SL_NK-Str.01
Port_8614852_1 | SOURCEANDSINK | B - SL_NK-Str.01
Port_8615111_2 | SOURCEANDSINK | B - SL_NK-Str.01
Port_8614854_0 | SOURCEANDSINK | A - SL_NK-Str.01
Port_8615066_2 | SOURCEANDSINK | A - SL_NK-Str.01
Port_8614854_1 | SOURCEANDSINK | A - SL_NK-Str.01
Port_8615071_2 | SOURCEANDSINK | A - SL_NK-Str.01
Port_8614883_0 | SOURCEANDSINK | B - FL-Str.02_NK-KK-TK
Port_8614885_2 | SOURCEANDSINK | B - FL-Str.02_NK-KK-TK
Port_8614883_1 | SOURCEANDSINK | B - FL-Str.02_NK-KK-TK
Port_8614898_1 | SOURCEANDSINK | B - FL-Str.02_NK-KK-TK
Port_8614928_0 | SOURCEANDSINK | B - SL_NK-Str.01
Port_8615111_1 | SOURCEANDSINK | B - SL_NK-Str.01
Port_8614928_1 | SOURCEANDSINK | B - SL_NK-Str.01
Port_8614943_1 | SOURCEANDSINK | B - SL_NK-Str.01
Port_8614976_0 | SOURCEANDSINK | A - SL_NK-Str.01
Port_8615066_1 | SOURCEANDSINK | A - SL_NK-Str.01
Port_8614976_1 | SOURCEANDSINK | A - SL_NK-Str.01
Port_8614991_1 | SOURCEANDSINK | A - SL_NK-Str.01
Port_8615024_0 | SOURCEANDSINK | A - FL-Str.02_NK-KK-TK
Port_8615094_1 | SOURCEANDSINK | A - FL-Str.02_NK-KK-TK
Port_8615024_1 | SOURCEANDSINK | A - FL-Str.02_NK-KK-TK
Port_8615039_1 | SOURCEANDSINK | A - FL-Str.02_NK-KK-TK
Port_8615449_0 | SOURCEANDSINK | A - SL_TK
Port_8627301_2 | SOURCEANDSINK | A - SL_TK
Port_8615449_1 | SOURCEANDSINK | A - SL_TK
Port_8627306_2 | SOURCEANDSINK | A - SL_TK
Port_8615570_0 | SOURCEANDSINK | A - SL_TK
Port_8615572_6 | SOURCEANDSINK | A - SL_TK
Port_8615570_1 | SOURCEANDSINK | A - SL_TK
Port_8627301_1 | SOURCEANDSINK | A - SL_TK
Port_8615572_5 | SOURCEANDSINK | A - SL_TK
Port_8615573_1 | SOURCEANDSINK | A - SL_TK
Port_8616180_0 | SOURCEANDSINK | A - SL_KK
Port_8630997_2 | SOURCEANDSINK | A - SL_KK
Port_8616180_1 | SOURCEANDSINK | A - SL_KK
Port_8616638_0 | SOURCEANDSINK | B - FL-Str.01_NK-KK-TK
Port_8620374_1 | SOURCEANDSINK | B - FL-Str.01_NK-KK-TK
Port_8616638_1 | SOURCEANDSINK | B - FL-Str.01_NK-KK-TK
Port_8620377_2 | SOURCEANDSINK | B - FL-Str.01_NK-KK-TK
Port_8616690_0 | SOURCEANDSINK | B - SL_KK
Port_8620410_1 | SOURCEANDSINK | B - SL_KK
Port_8616690_1 | SOURCEANDSINK | B - SL_KK
Port_8620413_2 | SOURCEANDSINK | B - SL_KK
Port_8616827_0 | SOURCEANDSINK | B - FL-Str.01_NK-KK-TK
Port_8619925_2 | SOURCEANDSINK | B - FL-Str.01_NK-KK-TK
Port_8616827_1 | SOURCEANDSINK | B - FL-Str.01_NK-KK-TK
Port_8616830_0 | SOURCEANDSINK | B - SL_KK
Port_8619894_2 | SOURCEANDSINK | B - SL_KK
Port_8616830_1 | SOURCEANDSINK | B - SL_KK
Port_8617131_0 | SOURCEANDSINK | B - FL-Str.01_NK-KK-TK
Port_8619068_2 | SOURCEANDSINK | B - FL-Str.01_NK-KK-TK
Port_8617131_1 | SOURCEANDSINK | B - FL-Str.01_NK-KK-TK
Port_8617134_0 | SOURCEANDSINK | B - SL_KK
Port_8619098_2 | SOURCEANDSINK | B - SL_KK
Port_8617134_1 | SOURCEANDSINK | B - SL_KK
Port_8617386_0 | SOURCEANDSINK | B - FL-Str.01_NK-KK-TK
Port_8627847_1 | SOURCEANDSINK | B - FL-Str.01_NK-KK-TK
Port_8617386_1 | SOURCEANDSINK | B - FL-Str.01_NK-KK-TK
Port_8627850_2 | SOURCEANDSINK | B - FL-Str.01_NK-KK-TK
Port_8617389_0 | SOURCEANDSINK | B - SL_KK
Port_8627809_1 | SOURCEANDSINK | B - SL_KK
Port_8617389_1 | SOURCEANDSINK | B - SL_KK
Port_8627812_2 | SOURCEANDSINK | B - SL_KK
Port_8617764_0 | SOURCEANDSINK | A - SL_KK
Port_8617913_1 | SOURCEANDSINK | A - SL_KK
Port_8617764_1 | SOURCEANDSINK | A - SL_KK
Port_8617916_2 | SOURCEANDSINK | A - SL_KK
Port_8617805_0 | SOURCEANDSINK | A - FL-Str.01_NK-KK-TK
Port_8617877_1 | SOURCEANDSINK | A - FL-Str.01_NK-KK-TK
Port_8617805_1 | SOURCEANDSINK | A - FL-Str.01_NK-KK-TK
Port_8617880_2 | SOURCEANDSINK | A - FL-Str.01_NK-KK-TK
Port_8617863_0 | SOURCEANDSINK | A - FL-Str.01_NK-KK-TK
Port_8617865_6 | SOURCEANDSINK | A - FL-Str.01_NK-KK-TK
Port_8617863_1 | SOURCEANDSINK | A - FL-Str.01_NK-KK-TK
Port_8617880_1 | SOURCEANDSINK | A - FL-Str.01_NK-KK-TK
Port_8617865_5 | SOURCEANDSINK | A - FL-Str.01_NK-KK-TK
Port_8617866_1 | SOURCEANDSINK | A - FL-Str.01_NK-KK-TK
Port_8617866_0 | SOURCEANDSINK | A - FL-Str.01_NK-KK-TK
Port_8617899_0 | SOURCEANDSINK | A - SL_KK
Port_8617901_6 | SOURCEANDSINK | A - SL_KK
Port_8617899_1 | SOURCEANDSINK | A - SL_KK
Port_8617916_1 | SOURCEANDSINK | A - SL_KK
Port_8617901_5 | SOURCEANDSINK | A - SL_KK
Port_8617902_1 | SOURCEANDSINK | A - SL_KK
Port_8617902_0 | SOURCEANDSINK | A - SL_KK
Port_8618017_0 | SOURCEANDSINK | A - FL-Str.01_NK-KK-TK
Port_8618019_6 | SOURCEANDSINK | A - FL-Str.01_NK-KK-TK
Port_8618017_1 | SOURCEANDSINK | A - FL-Str.01_NK-KK-TK
Port_8618034_1 | SOURCEANDSINK | A - FL-Str.01_NK-KK-TK
Port_8618019_5 | SOURCEANDSINK | A - FL-Str.01_NK-KK-TK
Port_8618020_1 | SOURCEANDSINK | A - FL-Str.01_NK-KK-TK
Port_8618020_0 | SOURCEANDSINK | A - FL-Str.01_NK-KK-TK
Port_8618064_0 | SOURCEANDSINK | A - SL_NK-Str.01
Port_8618066_6 | SOURCEANDSINK | A - SL_NK-Str.01
Port_8618064_1 | SOURCEANDSINK | A - SL_NK-Str.01
Port_8618081_1 | SOURCEANDSINK | A - SL_NK-Str.01
Port_8618066_5 | SOURCEANDSINK | A - SL_NK-Str.01
Port_8618067_1 | SOURCEANDSINK | A - SL_NK-Str.01
Port_8618067_0 | SOURCEANDSINK | A - SL_NK-Str.01
Port_8618198_0 | SOURCEANDSINK | B - SL_NK-Str.01
Port_8618200_6 | SOURCEANDSINK | B - SL_NK-Str.01
Port_8618198_1 | SOURCEANDSINK | B - SL_NK-Str.01
Port_8618215_1 | SOURCEANDSINK | B - SL_NK-Str.01
Port_8618200_5 | SOURCEANDSINK | B - SL_NK-Str.01
Port_8618201_1 | SOURCEANDSINK | B - SL_NK-Str.01
Port_8618201_0 | SOURCEANDSINK | B - SL_NK-Str.01
Port_8618242_0 | SOURCEANDSINK | B - FL-Str.01_NK-KK-TK
Port_8618244_6 | SOURCEANDSINK | B - FL-Str.01_NK-KK-TK
Port_8618242_1 | SOURCEANDSINK | B - FL-Str.01_NK-KK-TK
Port_8618259_1 | SOURCEANDSINK | B - FL-Str.01_NK-KK-TK
Port_8618244_5 | SOURCEANDSINK | B - FL-Str.01_NK-KK-TK
Port_8618245_1 | SOURCEANDSINK | B - FL-Str.01_NK-KK-TK
Port_8618245_0 | SOURCEANDSINK | B - FL-Str.01_NK-KK-TK
Port_8618365_0 | SOURCEANDSINK | A - FL-Str.02_NK-KK-TK
Port_8631029_2 | SOURCEANDSINK | A - FL-Str.02_NK-KK-TK
Port_8618365_1 | SOURCEANDSINK | A - FL-Str.02_NK-KK-TK
Port_8618600_0 | SOURCEANDSINK | B - SL_KK
Port_8618715_1 | SOURCEANDSINK | B - SL_KK
Port_8618600_1 | SOURCEANDSINK | B - SL_KK
Port_8618707_2 | SOURCEANDSINK | B - SL_KK
Port_8618620_0 | SOURCEANDSINK | B - FL-Str.01_NK-KK-TK
Port_8618690_1 | SOURCEANDSINK | B - FL-Str.01_NK-KK-TK
Port_8618620_1 | SOURCEANDSINK | B - FL-Str.01_NK-KK-TK
Port_8618807_1 | SOURCEANDSINK | B - FL-Str.01_NK-KK-TK
Port_8618681_0 | SOURCEANDSINK | B - SL_KK
Port_8618712_2 | SOURCEANDSINK | B - SL_KK
Port_8618681_1 | SOURCEANDSINK | B - SL_KK
Port_8618715_2 | SOURCEANDSINK | B - SL_KK
Port_8618684_0 | SOURCEANDSINK | B - FL-Str.01_NK-KK-TK
Port_8618696_2 | SOURCEANDSINK | B - FL-Str.01_NK-KK-TK
Port_8618684_1 | SOURCEANDSINK | B - FL-Str.01_NK-KK-TK
Port_8618690_2 | SOURCEANDSINK | B - FL-Str.01_NK-KK-TK
Port_8618788_0 | SOURCEANDSINK | B - FL-Str.01_NK-KK-TK
Port_8618807_2 | SOURCEANDSINK | B - FL-Str.01_NK-KK-TK
Port_8618788_1 | SOURCEANDSINK | B - FL-Str.01_NK-KK-TK
Port_8620374_2 | SOURCEANDSINK | B - FL-Str.01_NK-KK-TK
Port_8618791_0 | SOURCEANDSINK | B - SL_KK
Port_8618804_2 | SOURCEANDSINK | B - SL_KK
Port_8618791_1 | SOURCEANDSINK | B - SL_KK
Port_8620410_2 | SOURCEANDSINK | B - SL_KK
Port_8619062_0 | SOURCEANDSINK | B - FL-Str.01_NK-KK-TK
Port_8619064_2 | SOURCEANDSINK | B - FL-Str.01_NK-KK-TK
Port_8619062_1 | SOURCEANDSINK | B - FL-Str.01_NK-KK-TK
Port_8619068_1 | SOURCEANDSINK | B - FL-Str.01_NK-KK-TK
Port_8619092_0 | SOURCEANDSINK | B - SL_KK
Port_8619094_2 | SOURCEANDSINK | B - SL_KK
Port_8619092_1 | SOURCEANDSINK | B - SL_KK
Port_8619098_1 | SOURCEANDSINK | B - SL_KK
Port_8619117_0 | SOURCEANDSINK | A - FL-Str.01_NK-KK-TK
Port_8619771_1 | SOURCEANDSINK | A - FL-Str.01_NK-KK-TK
Port_8619117_1 | SOURCEANDSINK | A - FL-Str.01_NK-KK-TK
Port_8619120_0 | SOURCEANDSINK | A - SL_KK
Port_8619809_1 | SOURCEANDSINK | A - SL_KK
Port_8619120_1 | SOURCEANDSINK | A - SL_KK
Port_8619136_0 | SOURCEANDSINK | B - FL-Str.01_NK-KK-TK
Port_8619665_2 | SOURCEANDSINK | B - FL-Str.01_NK-KK-TK
Port_8619136_1 | SOURCEANDSINK | B - FL-Str.01_NK-KK-TK
Port_8619139_0 | SOURCEANDSINK | B - SL_KK
Port_8619715_2 | SOURCEANDSINK | B - SL_KK
Port_8619139_1 | SOURCEANDSINK | B - SL_KK
Port_8619153_0 | SOURCEANDSINK | A - FL-Str.01_NK-KK-TK
Port_8619275_1 | SOURCEANDSINK | A - FL-Str.01_NK-KK-TK
Port_8619153_1 | SOURCEANDSINK | A - FL-Str.01_NK-KK-TK
Port_8619156_0 | SOURCEANDSINK | A - SL_KK
Port_8619313_1 | SOURCEANDSINK | A - SL_KK
Port_8619156_1 | SOURCEANDSINK | A - SL_KK
Port_8619170_0 | SOURCEANDSINK | B - FL-Str.01_NK-KK-TK
Port_8619381_1 | SOURCEANDSINK | B - FL-Str.01_NK-KK-TK
Port_8619170_1 | SOURCEANDSINK | B - FL-Str.01_NK-KK-TK
Port_8619173_0 | SOURCEANDSINK | B - SL_KK
Port_8619418_1 | SOURCEANDSINK | B - SL_KK
Port_8619173_1 | SOURCEANDSINK | B - SL_KK
Port_8619273_0 | SOURCEANDSINK | A - FL-Str.01_NK-KK-TK
Port_8619275_2 | SOURCEANDSINK | A - FL-Str.01_NK-KK-TK
Port_8619273_1 | SOURCEANDSINK | A - FL-Str.01_NK-KK-TK
Port_8619289_1 | SOURCEANDSINK | A - FL-Str.01_NK-KK-TK
Port_8619311_0 | SOURCEANDSINK | A - SL_KK
Port_8619313_2 | SOURCEANDSINK | A - SL_KK
Port_8619311_1 | SOURCEANDSINK | A - SL_KK
Port_8619327_1 | SOURCEANDSINK | A - SL_KK
Port_8619379_0 | SOURCEANDSINK | B - FL-Str.01_NK-KK-TK
Port_8619381_2 | SOURCEANDSINK | B - FL-Str.01_NK-KK-TK
Port_8619379_1 | SOURCEANDSINK | B - FL-Str.01_NK-KK-TK
Port_8619395_1 | SOURCEANDSINK | B - FL-Str.01_NK-KK-TK
Port_8619416_0 | SOURCEANDSINK | B - SL_KK
Port_8619418_2 | SOURCEANDSINK | B - SL_KK
Port_8619416_1 | SOURCEANDSINK | B - SL_KK
Port_8619432_1 | SOURCEANDSINK | B - SL_KK
Port_8619452_0 | SOURCEANDSINK | A - FL-Str.01_NK-KK-TK
Port_8619525_2 | SOURCEANDSINK | A - FL-Str.01_NK-KK-TK
Port_8619452_1 | SOURCEANDSINK | A - FL-Str.01_NK-KK-TK
Port_8619455_0 | SOURCEANDSINK | A - SL_KK
Port_8619555_2 | SOURCEANDSINK | A - SL_KK
Port_8619455_1 | SOURCEANDSINK | A - SL_KK
Port_8619519_0 | SOURCEANDSINK | A - FL-Str.01_NK-KK-TK
Port_8619521_2 | SOURCEANDSINK | A - FL-Str.01_NK-KK-TK
Port_8619519_1 | SOURCEANDSINK | A - FL-Str.01_NK-KK-TK
Port_8619525_1 | SOURCEANDSINK | A - FL-Str.01_NK-KK-TK
Port_8619549_0 | SOURCEANDSINK | A - SL_KK
Port_8619551_2 | SOURCEANDSINK | A - SL_KK
Port_8619549_1 | SOURCEANDSINK | A - SL_KK
Port_8619555_1 | SOURCEANDSINK | A - SL_KK
Port_8619659_0 | SOURCEANDSINK | B - FL-Str.01_NK-KK-TK
Port_8619661_2 | SOURCEANDSINK | B - FL-Str.01_NK-KK-TK
Port_8619659_1 | SOURCEANDSINK | B - FL-Str.01_NK-KK-TK
Port_8619665_1 | SOURCEANDSINK | B - FL-Str.01_NK-KK-TK
Port_8619709_0 | SOURCEANDSINK | B - SL_KK
Port_8619711_2 | SOURCEANDSINK | B - SL_KK
Port_8619709_1 | SOURCEANDSINK | B - SL_KK
Port_8619715_1 | SOURCEANDSINK | B - SL_KK
Port_8619769_0 | SOURCEANDSINK | A - FL-Str.01_NK-KK-TK
Port_8619771_2 | SOURCEANDSINK | A - FL-Str.01_NK-KK-TK
Port_8619769_1 | SOURCEANDSINK | A - FL-Str.01_NK-KK-TK
Port_8619785_1 | SOURCEANDSINK | A - FL-Str.01_NK-KK-TK
Port_8619807_0 | SOURCEANDSINK | A - SL_KK
Port_8619809_2 | SOURCEANDSINK | A - SL_KK
Port_8619807_1 | SOURCEANDSINK | A - SL_KK
Port_8619823_1 | SOURCEANDSINK | A - SL_KK
Port_8619888_0 | SOURCEANDSINK | B - SL_KK
Port_8619890_2 | SOURCEANDSINK | B - SL_KK
Port_8619888_1 | SOURCEANDSINK | B - SL_KK
Port_8619894_1 | SOURCEANDSINK | B - SL_KK
Port_8619919_0 | SOURCEANDSINK | B - FL-Str.01_NK-KK-TK
Port_8619921_2 | SOURCEANDSINK | B - FL-Str.01_NK-KK-TK
Port_8619919_1 | SOURCEANDSINK | B - FL-Str.01_NK-KK-TK
Port_8619925_1 | SOURCEANDSINK | B - FL-Str.01_NK-KK-TK
Port_8619947_0 | SOURCEANDSINK | B - FL-Str.01_NK-KK-TK
Port_8620365_1 | SOURCEANDSINK | B - FL-Str.01_NK-KK-TK
Port_8619947_1 | SOURCEANDSINK | B - FL-Str.01_NK-KK-TK
Port_8619950_0 | SOURCEANDSINK | B - SL_KK
Port_8620401_1 | SOURCEANDSINK | B - SL_KK
Port_8619950_1 | SOURCEANDSINK | B - SL_KK
Port_8619968_0 | SOURCEANDSINK | A - FL-Str.01_NK-KK-TK
Port_8620264_1 | SOURCEANDSINK | A - FL-Str.01_NK-KK-TK
Port_8619968_1 | SOURCEANDSINK | A - FL-Str.01_NK-KK-TK
Port_8619971_0 | SOURCEANDSINK | A - SL_KK
Port_8620226_1 | SOURCEANDSINK | A - SL_KK
Port_8619971_1 | SOURCEANDSINK | A - SL_KK
Port_8619993_0 | SOURCEANDSINK | B - FL-Str.01_NK-KK-TK
Port_8620141_1 | SOURCEANDSINK | B - FL-Str.01_NK-KK-TK
Port_8619993_1 | SOURCEANDSINK | B - FL-Str.01_NK-KK-TK
Port_8619996_0 | SOURCEANDSINK | B - SL_KK
Port_8620088_1 | SOURCEANDSINK | B - SL_KK
Port_8619996_1 | SOURCEANDSINK | B - SL_KK
Port_8620086_0 | SOURCEANDSINK | B - SL_KK
Port_8620088_2 | SOURCEANDSINK | B - SL_KK
Port_8620086_1 | SOURCEANDSINK | B - SL_KK
Port_8620102_1 | SOURCEANDSINK | B - SL_KK
Port_8620139_0 | SOURCEANDSINK | B - FL-Str.01_NK-KK-TK
Port_8620141_2 | SOURCEANDSINK | B - FL-Str.01_NK-KK-TK
Port_8620139_1 | SOURCEANDSINK | B - FL-Str.01_NK-KK-TK
Port_8620155_1 | SOURCEANDSINK | B - FL-Str.01_NK-KK-TK
Port_8620224_0 | SOURCEANDSINK | A - SL_KK
Port_8620226_2 | SOURCEANDSINK | A - SL_KK
Port_8620224_1 | SOURCEANDSINK | A - SL_KK
Port_8620240_1 | SOURCEANDSINK | A - SL_KK
Port_8620262_0 | SOURCEANDSINK | A - FL-Str.01_NK-KK-TK
Port_8620264_2 | SOURCEANDSINK | A - FL-Str.01_NK-KK-TK
Port_8620262_1 | SOURCEANDSINK | A - FL-Str.01_NK-KK-TK
Port_8620278_1 | SOURCEANDSINK | A - FL-Str.01_NK-KK-TK
Port_8620363_0 | SOURCEANDSINK | B - FL-Str.01_NK-KK-TK
Port_8620365_2 | SOURCEANDSINK | B - FL-Str.01_NK-KK-TK
Port_8620363_1 | SOURCEANDSINK | B - FL-Str.01_NK-KK-TK
Port_8620377_1 | SOURCEANDSINK | B - FL-Str.01_NK-KK-TK
Port_8620399_0 | SOURCEANDSINK | B - SL_KK
Port_8620401_2 | SOURCEANDSINK | B - SL_KK
Port_8620399_1 | SOURCEANDSINK | B - SL_KK
Port_8620413_1 | SOURCEANDSINK | B - SL_KK
Port_8620446_0 | SOURCEANDSINK | A - FL-Str.01_NK-KK-TK
Port_8620548_1 | SOURCEANDSINK | A - FL-Str.01_NK-KK-TK
Port_8620446_1 | SOURCEANDSINK | A - FL-Str.01_NK-KK-TK
Port_8620507_0 | SOURCEANDSINK | A - SL_KK
Port_8620507_1 | SOURCEANDSINK | A - SL_KK
Port_8620523_1 | SOURCEANDSINK | A - SL_KK
Port_8620546_0 | SOURCEANDSINK | A - FL-Str.01_NK-KK-TK
Port_8620548_2 | SOURCEANDSINK | A - FL-Str.01_NK-KK-TK
Port_8620546_1 | SOURCEANDSINK | A - FL-Str.01_NK-KK-TK
Port_8620562_1 | SOURCEANDSINK | A - FL-Str.01_NK-KK-TK
Port_8620637_0 | SOURCEANDSINK | A - FL-Str.01_NK-KK-TK
Port_8620742_1 | SOURCEANDSINK | A - FL-Str.01_NK-KK-TK
Port_8620637_1 | SOURCEANDSINK | A - FL-Str.01_NK-KK-TK
Port_8620640_0 | SOURCEANDSINK | A - SL_KK
Port_8620706_1 | SOURCEANDSINK | A - SL_KK
Port_8620640_1 | SOURCEANDSINK | A - SL_KK
Port_8620704_0 | SOURCEANDSINK | A - SL_KK
Port_8620706_2 | SOURCEANDSINK | A - SL_KK
Port_8620704_1 | SOURCEANDSINK | A - SL_KK
Port_8620717_1 | SOURCEANDSINK | A - SL_KK
Port_8620740_0 | SOURCEANDSINK | A - FL-Str.01_NK-KK-TK
Port_8620742_2 | SOURCEANDSINK | A - FL-Str.01_NK-KK-TK
Port_8620740_1 | SOURCEANDSINK | A - FL-Str.01_NK-KK-TK
Port_8620753_1 | SOURCEANDSINK | A - FL-Str.01_NK-KK-TK
Port_8620775_0 | SOURCEANDSINK | A - FL-Str.01_NK-KK-TK
Port_8620900_1 | SOURCEANDSINK | A - FL-Str.01_NK-KK-TK
Port_8620775_1 | SOURCEANDSINK | A - FL-Str.01_NK-KK-TK
Port_8620778_0 | SOURCEANDSINK | A - SL_KK
Port_8620935_1 | SOURCEANDSINK | A - SL_KK
Port_8620778_1 | SOURCEANDSINK | A - SL_KK
Port_8620792_0 | SOURCEANDSINK | B - SL_KK
Port_8621143_1 | SOURCEANDSINK | B - SL_KK
Port_8620792_1 | SOURCEANDSINK | B - SL_KK
Port_8620795_0 | SOURCEANDSINK | B - FL-Str.01_NK-KK-TK
Port_8621181_1 | SOURCEANDSINK | B - FL-Str.01_NK-KK-TK
Port_8620795_1 | SOURCEANDSINK | B - FL-Str.01_NK-KK-TK
Port_8620898_0 | SOURCEANDSINK | A - FL-Str.01_NK-KK-TK
Port_8620900_2 | SOURCEANDSINK | A - FL-Str.01_NK-KK-TK
Port_8620898_1 | SOURCEANDSINK | A - FL-Str.01_NK-KK-TK
Port_8620911_1 | SOURCEANDSINK | A - FL-Str.01_NK-KK-TK
Port_8620933_0 | SOURCEANDSINK | A - SL_KK
Port_8620935_2 | SOURCEANDSINK | A - SL_KK
Port_8620933_1 | SOURCEANDSINK | A - SL_KK
Port_8620946_1 | SOURCEANDSINK | A - SL_KK
Port_8621003_0 | SOURCEANDSINK | B - SL_KK
Port_8621154_2 | SOURCEANDSINK | B - SL_KK
Port_8621003_1 | SOURCEANDSINK | B - SL_KK
Port_8621157_2 | SOURCEANDSINK | B - SL_KK
Port_8621006_0 | SOURCEANDSINK | B - FL-Str.01_NK-KK-TK
Port_8621192_2 | SOURCEANDSINK | B - FL-Str.01_NK-KK-TK
Port_8621006_1 | SOURCEANDSINK | B - FL-Str.01_NK-KK-TK
Port_8621195_2 | SOURCEANDSINK | B - FL-Str.01_NK-KK-TK
Port_8621141_0 | SOURCEANDSINK | B - SL_KK
Port_8621143_2 | SOURCEANDSINK | B - SL_KK
Port_8621141_1 | SOURCEANDSINK | B - SL_KK
Port_8621157_1 | SOURCEANDSINK | B - SL_KK
Port_8621179_0 | SOURCEANDSINK | B - FL-Str.01_NK-KK-TK
Port_8621181_2 | SOURCEANDSINK | B - FL-Str.01_NK-KK-TK
Port_8621179_1 | SOURCEANDSINK | B - FL-Str.01_NK-KK-TK
Port_8621195_1 | SOURCEANDSINK | B - FL-Str.01_NK-KK-TK
Port_8621264_0 | SOURCEANDSINK | A - SL_NK-Str.02
Port_8634857_2 | SOURCEANDSINK | A - SL_NK-Str.02
Port_8621264_1 | SOURCEANDSINK | A - SL_NK-Str.02
Port_8621267_0 | SOURCEANDSINK | A - FL-Str.03_NK-KK-TK
Port_8622733_2 | SOURCEANDSINK | A - FL-Str.03_NK-KK-TK
Port_8621267_1 | SOURCEANDSINK | A - FL-Str.03_NK-KK-TK
Port_8621301_0 | SOURCEANDSINK | A - SL_NK-Str.02
Port_8622640_2 | SOURCEANDSINK | A - SL_NK-Str.02
Port_8621301_1 | SOURCEANDSINK | A - SL_NK-Str.02
Port_8621304_0 | SOURCEANDSINK | A - FL-Str.03_NK-KK-TK
Port_8622601_2 | SOURCEANDSINK | A - FL-Str.03_NK-KK-TK
Port_8621304_1 | SOURCEANDSINK | A - FL-Str.03_NK-KK-TK
Port_8621320_0 | SOURCEANDSINK | A - SL_NK-Str.02
Port_8622865_2 | SOURCEANDSINK | A - SL_NK-Str.02
Port_8621320_1 | SOURCEANDSINK | A - SL_NK-Str.02
Port_8621323_0 | SOURCEANDSINK | A - FL-Str.03_NK-KK-TK
Port_8622904_2 | SOURCEANDSINK | A - FL-Str.03_NK-KK-TK
Port_8621323_1 | SOURCEANDSINK | A - FL-Str.03_NK-KK-TK
Port_8621341_0 | SOURCEANDSINK | A - FL-Str.03_NK-KK-TK
Port_8626710_1 | SOURCEANDSINK | A - FL-Str.03_NK-KK-TK
Port_8621341_1 | SOURCEANDSINK | A - FL-Str.03_NK-KK-TK
Port_8621344_0 | SOURCEANDSINK | A - SL_NK-Str.02
Port_8626664_1 | SOURCEANDSINK | A - SL_NK-Str.02
Port_8621344_1 | SOURCEANDSINK | A - SL_NK-Str.02
Port_8621358_0 | SOURCEANDSINK | A - SL_NK-Str.01
Port_8623295_2 | SOURCEANDSINK | A - SL_NK-Str.01
Port_8621358_1 | SOURCEANDSINK | A - SL_NK-Str.01
Port_8621361_0 | SOURCEANDSINK | A - FL-Str.03_NK-KK-TK
Port_8623218_1 | SOURCEANDSINK | A - FL-Str.03_NK-KK-TK
Port_8621361_1 | SOURCEANDSINK | A - FL-Str.03_NK-KK-TK
Port_8621377_0 | SOURCEANDSINK | A - SL_NK-Str.01
Port_8623428_2 | SOURCEANDSINK | A - SL_NK-Str.01
Port_8621377_1 | SOURCEANDSINK | A - SL_NK-Str.01
Port_8621380_0 | SOURCEANDSINK | A - FL-Str.03_NK-KK-TK
Port_8623389_2 | SOURCEANDSINK | A - FL-Str.03_NK-KK-TK
Port_8621380_1 | SOURCEANDSINK | A - FL-Str.03_NK-KK-TK
Port_8621394_0 | SOURCEANDSINK | B - FL-Str.03_NK-KK-TK
Port_8623652_1 | SOURCEANDSINK | B - FL-Str.03_NK-KK-TK
Port_8621394_1 | SOURCEANDSINK | B - FL-Str.03_NK-KK-TK
Port_8621397_0 | SOURCEANDSINK | B - SL_NK-Str.01
Port_8623698_1 | SOURCEANDSINK | B - SL_NK-Str.01
Port_8621397_1 | SOURCEANDSINK | B - SL_NK-Str.01
Port_8621411_0 | SOURCEANDSINK | B - FL-Str.03_NK-KK-TK
Port_8623899_2 | SOURCEANDSINK | B - FL-Str.03_NK-KK-TK
Port_8621411_1 | SOURCEANDSINK | B - FL-Str.03_NK-KK-TK
Port_8621414_0 | SOURCEANDSINK | B - SL_NK-Str.01
Port_8623861_2 | SOURCEANDSINK | B - SL_NK-Str.01
Port_8621414_1 | SOURCEANDSINK | B - SL_NK-Str.01
Port_8621432_0 | SOURCEANDSINK | B - FL-Str.03_NK-KK-TK
Port_8624029_2 | SOURCEANDSINK | B - FL-Str.03_NK-KK-TK
Port_8621432_1 | SOURCEANDSINK | B - FL-Str.03_NK-KK-TK
Port_8621435_0 | SOURCEANDSINK | B - SL_NK-Str.02
Port_8623991_2 | SOURCEANDSINK | B - SL_NK-Str.02
Port_8621435_1 | SOURCEANDSINK | B - SL_NK-Str.02
Port_8621451_0 | SOURCEANDSINK | B - SL_NK-Str.02
Port_8622323_1 | SOURCEANDSINK | B - SL_NK-Str.02
Port_8621451_1 | SOURCEANDSINK | B - SL_NK-Str.02
Port_8621454_0 | SOURCEANDSINK | B - FL-Str.03_NK-KK-TK
Port_8622279_1 | SOURCEANDSINK | B - FL-Str.03_NK-KK-TK
Port_8621454_1 | SOURCEANDSINK | B - FL-Str.03_NK-KK-TK
Port_8621472_0 | SOURCEANDSINK | B - FL-Str.03_NK-KK-TK
Port_8622384_2 | SOURCEANDSINK | B - FL-Str.03_NK-KK-TK
Port_8621472_1 | SOURCEANDSINK | B - FL-Str.03_NK-KK-TK
Port_8621475_0 | SOURCEANDSINK | B - SL_NK-Str.02
Port_8622390_2 | SOURCEANDSINK | B - SL_NK-Str.02
Port_8621475_1 | SOURCEANDSINK | B - SL_NK-Str.02
Port_8621489_0 | SOURCEANDSINK | B - FL-Str.03_NK-KK-TK
Port_8622445_2 | SOURCEANDSINK | B - FL-Str.03_NK-KK-TK
Port_8621489_1 | SOURCEANDSINK | B - FL-Str.03_NK-KK-TK
Port_8621492_0 | SOURCEANDSINK | B - SL_NK-Str.02
Port_8622425_2 | SOURCEANDSINK | B - SL_NK-Str.02
Port_8621492_1 | SOURCEANDSINK | B - SL_NK-Str.02
Port_8621506_0 | SOURCEANDSINK | B - FL-Str.03_NK-KK-TK
Port_8622507_2 | SOURCEANDSINK | B - FL-Str.03_NK-KK-TK
Port_8621506_1 | SOURCEANDSINK | B - FL-Str.03_NK-KK-TK
Port_8621509_0 | SOURCEANDSINK | B - SL_NK-Str.02
Port_8622479_2 | SOURCEANDSINK | B - SL_NK-Str.02
Port_8621509_1 | SOURCEANDSINK | B - SL_NK-Str.02
Port_8621607_0 | SOURCEANDSINK | B - SL_NK-Str.02
Port_8621609_2 | SOURCEANDSINK | B - SL_NK-Str.02
Port_8621607_1 | SOURCEANDSINK | B - SL_NK-Str.02
Port_8622479_1 | SOURCEANDSINK | B - SL_NK-Str.02
Port_8621682_0 | SOURCEANDSINK | B - FL-Str.03_NK-KK-TK
Port_8622507_1 | SOURCEANDSINK | B - FL-Str.03_NK-KK-TK
Port_8621682_1 | SOURCEANDSINK | B - FL-Str.03_NK-KK-TK
Port_8621702_1 | SOURCEANDSINK | B - FL-Str.03_NK-KK-TK
Port_8621791_0 | SOURCEANDSINK | B - FL-Str.03_NK-KK-TK
Port_8621793_2 | SOURCEANDSINK | B - FL-Str.03_NK-KK-TK
Port_8621791_1 | SOURCEANDSINK | B - FL-Str.03_NK-KK-TK
Port_8622445_1 | SOURCEANDSINK | B - FL-Str.03_NK-KK-TK
Port_8621837_0 | SOURCEANDSINK | B - SL_NK-Str.02
Port_8621839_2 | SOURCEANDSINK | B - SL_NK-Str.02
Port_8621837_1 | SOURCEANDSINK | B - SL_NK-Str.02
Port_8622425_1 | SOURCEANDSINK | B - SL_NK-Str.02
Port_8621932_0 | SOURCEANDSINK | B - FL-Str.03_NK-KK-TK
Port_8621934_2 | SOURCEANDSINK | B - FL-Str.03_NK-KK-TK
Port_8621932_1 | SOURCEANDSINK | B - FL-Str.03_NK-KK-TK
Port_8622381_2 | SOURCEANDSINK | B - FL-Str.03_NK-KK-TK
Port_8621941_1 | SOURCEANDSINK | B - FL-Str.03_NK-KK-TK
Port_8622381_1 | SOURCEANDSINK | B - FL-Str.03_NK-KK-TK
Port_8621941_2 | SOURCEANDSINK | B - FL-Str.03_NK-KK-TK
Port_8622384_1 | SOURCEANDSINK | B - FL-Str.03_NK-KK-TK
Port_8621978_0 | SOURCEANDSINK | B - SL_NK-Str.02
Port_8621980_2 | SOURCEANDSINK | B - SL_NK-Str.02
Port_8621978_1 | SOURCEANDSINK | B - SL_NK-Str.02
Port_8622387_2 | SOURCEANDSINK | B - SL_NK-Str.02
Port_8621987_1 | SOURCEANDSINK | B - SL_NK-Str.02
Port_8622387_1 | SOURCEANDSINK | B - SL_NK-Str.02
Port_8621987_2 | SOURCEANDSINK | B - SL_NK-Str.02
Port_8622390_1 | SOURCEANDSINK | B - SL_NK-Str.02
Port_8622042_0 | SOURCEANDSINK | B - SL_NK-Str.02
Port_8622329_2 | SOURCEANDSINK | B - SL_NK-Str.02
Port_8622042_1 | SOURCEANDSINK | B - SL_NK-Str.02
Port_8622344_2 | SOURCEANDSINK | B - SL_NK-Str.02
Port_8622045_0 | SOURCEANDSINK | B - FL-Str.03_NK-KK-TK
Port_8622285_2 | SOURCEANDSINK | B - FL-Str.03_NK-KK-TK
Port_8622045_1 | SOURCEANDSINK | B - FL-Str.03_NK-KK-TK
Port_8622352_2 | SOURCEANDSINK | B - FL-Str.03_NK-KK-TK
Port_8622277_0 | SOURCEANDSINK | B - FL-Str.03_NK-KK-TK
Port_8622279_2 | SOURCEANDSINK | B - FL-Str.03_NK-KK-TK
Port_8622277_1 | SOURCEANDSINK | B - FL-Str.03_NK-KK-TK
Port_8622285_1 | SOURCEANDSINK | B - FL-Str.03_NK-KK-TK
Port_8622321_0 | SOURCEANDSINK | B - SL_NK-Str.02
Port_8622323_2 | SOURCEANDSINK | B - SL_NK-Str.02
Port_8622321_1 | SOURCEANDSINK | B - SL_NK-Str.02
Port_8622329_1 | SOURCEANDSINK | B - SL_NK-Str.02
Port_8622595_0 | SOURCEANDSINK | A - FL-Str.03_NK-KK-TK
Port_8622597_2 | SOURCEANDSINK | A - FL-Str.03_NK-KK-TK
Port_8622595_1 | SOURCEANDSINK | A - FL-Str.03_NK-KK-TK
Port_8622601_1 | SOURCEANDSINK | A - FL-Str.03_NK-KK-TK
Port_8622634_0 | SOURCEANDSINK | A - SL_NK-Str.02
Port_8622636_2 | SOURCEANDSINK | A - SL_NK-Str.02
Port_8622634_1 | SOURCEANDSINK | A - SL_NK-Str.02
Port_8622640_1 | SOURCEANDSINK | A - SL_NK-Str.02
Port_8622727_0 | SOURCEANDSINK | A - FL-Str.03_NK-KK-TK
Port_8622729_2 | SOURCEANDSINK | A - FL-Str.03_NK-KK-TK
Port_8622727_1 | SOURCEANDSINK | A - FL-Str.03_NK-KK-TK
Port_8622733_1 | SOURCEANDSINK | A - FL-Str.03_NK-KK-TK
Port_8622766_0 | SOURCEANDSINK | A - SL_NK-Str.02
Port_8622768_2 | SOURCEANDSINK | A - SL_NK-Str.02
Port_8622766_1 | SOURCEANDSINK | A - SL_NK-Str.02
Port_8634857_1 | SOURCEANDSINK | A - SL_NK-Str.02
Port_8622859_0 | SOURCEANDSINK | A - SL_NK-Str.02
Port_8622861_2 | SOURCEANDSINK | A - SL_NK-Str.02
Port_8622859_1 | SOURCEANDSINK | A - SL_NK-Str.02
Port_8622865_1 | SOURCEANDSINK | A - SL_NK-Str.02
Port_8622898_0 | SOURCEANDSINK | A - FL-Str.03_NK-KK-TK
Port_8622900_2 | SOURCEANDSINK | A - FL-Str.03_NK-KK-TK
Port_8622898_1 | SOURCEANDSINK | A - FL-Str.03_NK-KK-TK
Port_8622904_1 | SOURCEANDSINK | A - FL-Str.03_NK-KK-TK
Port_8623216_0 | SOURCEANDSINK | A - FL-Str.03_NK-KK-TK
Port_8623218_2 | SOURCEANDSINK | A - FL-Str.03_NK-KK-TK
Port_8623216_1 | SOURCEANDSINK | A - FL-Str.03_NK-KK-TK
Port_8623232_1 | SOURCEANDSINK | A - FL-Str.03_NK-KK-TK
Port_8623289_0 | SOURCEANDSINK | A - SL_NK-Str.01
Port_8623291_2 | SOURCEANDSINK | A - SL_NK-Str.01
Port_8623289_1 | SOURCEANDSINK | A - SL_NK-Str.01
Port_8623295_1 | SOURCEANDSINK | A - SL_NK-Str.01
Port_8623383_0 | SOURCEANDSINK | A - FL-Str.03_NK-KK-TK
Port_8623385_2 | SOURCEANDSINK | A - FL-Str.03_NK-KK-TK
Port_8623383_1 | SOURCEANDSINK | A - FL-Str.03_NK-KK-TK
Port_8623389_1 | SOURCEANDSINK | A - FL-Str.03_NK-KK-TK
Port_8623422_0 | SOURCEANDSINK | A - SL_NK-Str.01
Port_8624142_1 | SOURCEANDSINK | A - SL_NK-Str.01
Port_8623422_1 | SOURCEANDSINK | A - SL_NK-Str.01
Port_8623428_1 | SOURCEANDSINK | A - SL_NK-Str.01
Port_8623538_0 | SOURCEANDSINK | B - FL-Str.03_NK-KK-TK
Port_8623663_1 | SOURCEANDSINK | B - FL-Str.03_NK-KK-TK
Port_8623538_1 | SOURCEANDSINK | B - FL-Str.03_NK-KK-TK
Port_8623666_2 | SOURCEANDSINK | B - FL-Str.03_NK-KK-TK
Port_8623541_0 | SOURCEANDSINK | B - SL_NK-Str.01
Port_8624274_1 | SOURCEANDSINK | B - SL_NK-Str.01
Port_8623541_1 | SOURCEANDSINK | B - SL_NK-Str.01
Port_8623712_2 | SOURCEANDSINK | B - SL_NK-Str.01
Port_8623650_0 | SOURCEANDSINK | B - FL-Str.03_NK-KK-TK
Port_8623652_2 | SOURCEANDSINK | B - FL-Str.03_NK-KK-TK
Port_8623650_1 | SOURCEANDSINK | B - FL-Str.03_NK-KK-TK
Port_8623666_1 | SOURCEANDSINK | B - FL-Str.03_NK-KK-TK
Port_8623696_0 | SOURCEANDSINK | B - SL_NK-Str.01
Port_8623698_2 | SOURCEANDSINK | B - SL_NK-Str.01
Port_8623696_1 | SOURCEANDSINK | B - SL_NK-Str.01
Port_8623712_1 | SOURCEANDSINK | B - SL_NK-Str.01
Port_8623855_0 | SOURCEANDSINK | B - SL_NK-Str.01
Port_8623857_2 | SOURCEANDSINK | B - SL_NK-Str.01
Port_8623855_1 | SOURCEANDSINK | B - SL_NK-Str.01
Port_8623861_1 | SOURCEANDSINK | B - SL_NK-Str.01
Port_8623893_0 | SOURCEANDSINK | B - FL-Str.03_NK-KK-TK
Port_8623895_2 | SOURCEANDSINK | B - FL-Str.03_NK-KK-TK
Port_8623893_1 | SOURCEANDSINK | B - FL-Str.03_NK-KK-TK
Port_8623899_1 | SOURCEANDSINK | B - FL-Str.03_NK-KK-TK
Port_8623985_0 | SOURCEANDSINK | B - SL_NK-Str.02
Port_8623987_2 | SOURCEANDSINK | B - SL_NK-Str.02
Port_8623985_1 | SOURCEANDSINK | B - SL_NK-Str.02
Port_8623991_1 | SOURCEANDSINK | B - SL_NK-Str.02
Port_8624023_0 | SOURCEANDSINK | B - FL-Str.03_NK-KK-TK
Port_8624025_2 | SOURCEANDSINK | B - FL-Str.03_NK-KK-TK
Port_8624023_1 | SOURCEANDSINK | B - FL-Str.03_NK-KK-TK
Port_8624029_1 | SOURCEANDSINK | B - FL-Str.03_NK-KK-TK
Port_8624134_1 | SOURCEANDSINK | A - SL_NK-Str.01
Port_8624147_1 | SOURCEANDSINK | A - SL_NK-Str.01
Port_8624266_1 | SOURCEANDSINK | B - SL_NK-Str.01
Port_8624277_1 | SOURCEANDSINK | B - SL_NK-Str.01
Port_8624369_0 | SOURCEANDSINK | B - SL_NK-Str.01
Port_8624371_2 | SOURCEANDSINK | B - SL_NK-Str.01
Port_8624369_1 | SOURCEANDSINK | B - SL_NK-Str.01
Port_8624382_1 | SOURCEANDSINK | B - SL_NK-Str.01
Port_8624489_0 | SOURCEANDSINK | B - FL-Str.02_NK-KK-TK
Port_8625257_2 | SOURCEANDSINK | B - FL-Str.02_NK-KK-TK
Port_8624489_1 | SOURCEANDSINK | B - FL-Str.02_NK-KK-TK
Port_8624491_0 | SOURCEANDSINK | B - SL_NK-Str.02
Port_8624491_1 | SOURCEANDSINK | B - SL_NK-Str.02
Port_8625293_1 | SOURCEANDSINK | B - SL_NK-Str.02
Port_8624658_0 | SOURCEANDSINK | B - FL-Str.02_NK-KK-TK
Port_8625441_2 | SOURCEANDSINK | B - FL-Str.02_NK-KK-TK
Port_8624658_1 | SOURCEANDSINK | B - FL-Str.02_NK-KK-TK
Port_8624660_0 | SOURCEANDSINK | B - SL_NK-Str.02
Port_8625401_2 | SOURCEANDSINK | B - SL_NK-Str.02
Port_8624660_1 | SOURCEANDSINK | B - SL_NK-Str.02
Port_8624677_0 | SOURCEANDSINK | B - SL_NK-Str.02
Port_8625078_1 | SOURCEANDSINK | B - SL_NK-Str.02
Port_8624677_1 | SOURCEANDSINK | B - SL_NK-Str.02
Port_8624679_0 | SOURCEANDSINK | B - FL-Str.03_NK-KK-TK
Port_8625136_1 | SOURCEANDSINK | B - FL-Str.03_NK-KK-TK
Port_8624679_1 | SOURCEANDSINK | B - FL-Str.03_NK-KK-TK
Port_8624694_0 | SOURCEANDSINK | A - SL_NK-Str.02
Port_8624694_1 | SOURCEANDSINK | A - SL_NK-Str.02
Port_8625012_1 | SOURCEANDSINK | A - SL_NK-Str.02
Port_8624696_0 | SOURCEANDSINK | A - FL-Str.03_NK-KK-TK
Port_8624696_1 | SOURCEANDSINK | A - FL-Str.03_NK-KK-TK
Port_8624954_1 | SOURCEANDSINK | A - FL-Str.03_NK-KK-TK
Port_8624711_0 | SOURCEANDSINK | A - SL_NK-Str.02
Port_8624830_2 | SOURCEANDSINK | A - SL_NK-Str.02
Port_8624711_1 | SOURCEANDSINK | A - SL_NK-Str.02
Port_8624713_0 | SOURCEANDSINK | A - FL-Str.03_NK-KK-TK
Port_8624871_2 | SOURCEANDSINK | A - FL-Str.03_NK-KK-TK
Port_8624713_1 | SOURCEANDSINK | A - FL-Str.03_NK-KK-TK
Port_8624824_0 | SOURCEANDSINK | A - SL_NK-Str.02
Port_8624826_2 | SOURCEANDSINK | A - SL_NK-Str.02
Port_8624824_1 | SOURCEANDSINK | A - SL_NK-Str.02
Port_8624830_1 | SOURCEANDSINK | A - SL_NK-Str.02
Port_8624865_0 | SOURCEANDSINK | A - FL-Str.03_NK-KK-TK
Port_8624867_2 | SOURCEANDSINK | A - FL-Str.03_NK-KK-TK
Port_8624865_1 | SOURCEANDSINK | A - FL-Str.03_NK-KK-TK
Port_8624871_1 | SOURCEANDSINK | A - FL-Str.03_NK-KK-TK
Port_8624952_0 | SOURCEANDSINK | A - FL-Str.03_NK-KK-TK
Port_8624954_2 | SOURCEANDSINK | A - FL-Str.03_NK-KK-TK
Port_8624952_1 | SOURCEANDSINK | A - FL-Str.03_NK-KK-TK
Port_8624970_1 | SOURCEANDSINK | A - FL-Str.03_NK-KK-TK
Port_8625010_0 | SOURCEANDSINK | A - SL_NK-Str.02
Port_8625012_2 | SOURCEANDSINK | A - SL_NK-Str.02
Port_8625010_1 | SOURCEANDSINK | A - SL_NK-Str.02
Port_8625024_1 | SOURCEANDSINK | A - SL_NK-Str.02
Port_8625076_0 | SOURCEANDSINK | B - SL_NK-Str.02
Port_8625078_2 | SOURCEANDSINK | B - SL_NK-Str.02
Port_8625076_1 | SOURCEANDSINK | B - SL_NK-Str.02
Port_8625094_1 | SOURCEANDSINK | B - SL_NK-Str.02
Port_8625134_0 | SOURCEANDSINK | B - FL-Str.03_NK-KK-TK
Port_8625136_2 | SOURCEANDSINK | B - FL-Str.03_NK-KK-TK
Port_8625134_1 | SOURCEANDSINK | B - FL-Str.03_NK-KK-TK
Port_8625152_1 | SOURCEANDSINK | B - FL-Str.03_NK-KK-TK
Port_8625251_0 | SOURCEANDSINK | B - FL-Str.02_NK-KK-TK
Port_8625253_2 | SOURCEANDSINK | B - FL-Str.02_NK-KK-TK
Port_8625251_1 | SOURCEANDSINK | B - FL-Str.02_NK-KK-TK
Port_8625257_1 | SOURCEANDSINK | B - FL-Str.02_NK-KK-TK
Port_8625291_0 | SOURCEANDSINK | B - SL_NK-Str.02
Port_8625293_2 | SOURCEANDSINK | B - SL_NK-Str.02
Port_8625291_1 | SOURCEANDSINK | B - SL_NK-Str.02
Port_8625304_1 | SOURCEANDSINK | B - SL_NK-Str.02
Port_8625395_0 | SOURCEANDSINK | B - SL_NK-Str.02
Port_8625397_2 | SOURCEANDSINK | B - SL_NK-Str.02
Port_8625395_1 | SOURCEANDSINK | B - SL_NK-Str.02
Port_8625401_1 | SOURCEANDSINK | B - SL_NK-Str.02
Port_8625435_0 | SOURCEANDSINK | B - FL-Str.02_NK-KK-TK
Port_8625437_2 | SOURCEANDSINK | B - FL-Str.02_NK-KK-TK
Port_8625435_1 | SOURCEANDSINK | B - FL-Str.02_NK-KK-TK
Port_8625441_1 | SOURCEANDSINK | B - FL-Str.02_NK-KK-TK
Port_8625869_1 | SOURCEANDSINK | B - SL_NK-Str.02
Port_8625879_1 | SOURCEANDSINK | B - SL_NK-Str.02
Port_8625982_0 | SOURCEANDSINK | A - SL_NK-Str.02
Port_8626179_2 | SOURCEANDSINK | A - SL_NK-Str.02
Port_8625982_1 | SOURCEANDSINK | A - SL_NK-Str.02
Port_8625984_0 | SOURCEANDSINK | A - FL-Str.02_NK-KK-TK
Port_8626141_2 | SOURCEANDSINK | A - FL-Str.02_NK-KK-TK
Port_8625984_1 | SOURCEANDSINK | A - FL-Str.02_NK-KK-TK
Port_8626133_0 | SOURCEANDSINK | A - FL-Str.02_NK-KK-TK
Port_8626135_2 | SOURCEANDSINK | A - FL-Str.02_NK-KK-TK
Port_8626133_1 | SOURCEANDSINK | A - FL-Str.02_NK-KK-TK
Port_8626141_1 | SOURCEANDSINK | A - FL-Str.02_NK-KK-TK
Port_8626173_0 | SOURCEANDSINK | A - SL_NK-Str.02
Port_8626175_2 | SOURCEANDSINK | A - SL_NK-Str.02
Port_8626173_1 | SOURCEANDSINK | A - SL_NK-Str.02
Port_8626179_1 | SOURCEANDSINK | A - SL_NK-Str.02
Port_8626218_0 | SOURCEANDSINK | A - SL_NK-Str.02
Port_8626315_2 | SOURCEANDSINK | A - SL_NK-Str.02
Port_8626218_1 | SOURCEANDSINK | A - SL_NK-Str.02
Port_8626220_0 | SOURCEANDSINK | A - FL-Str.02_NK-KK-TK
Port_8626355_2 | SOURCEANDSINK | A - FL-Str.02_NK-KK-TK
Port_8626220_1 | SOURCEANDSINK | A - FL-Str.02_NK-KK-TK
Port_8626285_1 | SOURCEANDSINK | A - SL_NK-Str.02
Port_8634740_2 | SOURCEANDSINK | A - SL_NK-Str.02
Port_8626309_0 | SOURCEANDSINK | A - SL_NK-Str.02
Port_8634740_1 | SOURCEANDSINK | A - SL_NK-Str.02
Port_8626309_1 | SOURCEANDSINK | A - SL_NK-Str.02
Port_8626315_1 | SOURCEANDSINK | A - SL_NK-Str.02
Port_8626349_0 | SOURCEANDSINK | A - FL-Str.02_NK-KK-TK
Port_8634756_1 | SOURCEANDSINK | A - FL-Str.02_NK-KK-TK
Port_8626349_1 | SOURCEANDSINK | A - FL-Str.02_NK-KK-TK
Port_8626355_1 | SOURCEANDSINK | A - FL-Str.02_NK-KK-TK
Port_8626500_0 | SOURCEANDSINK | A - FL-Str.03_NK-KK-TK
Port_8626827_2 | SOURCEANDSINK | A - FL-Str.03_NK-KK-TK
Port_8626500_1 | SOURCEANDSINK | A - FL-Str.03_NK-KK-TK
Port_8626724_2 | SOURCEANDSINK | A - FL-Str.03_NK-KK-TK
Port_8626503_0 | SOURCEANDSINK | A - SL_NK-Str.02
Port_8626675_2 | SOURCEANDSINK | A - SL_NK-Str.02
Port_8626503_1 | SOURCEANDSINK | A - SL_NK-Str.02
Port_8626678_2 | SOURCEANDSINK | A - SL_NK-Str.02
Port_8626662_0 | SOURCEANDSINK | A - SL_NK-Str.02
Port_8626664_2 | SOURCEANDSINK | A - SL_NK-Str.02
Port_8626662_1 | SOURCEANDSINK | A - SL_NK-Str.02
Port_8626678_1 | SOURCEANDSINK | A - SL_NK-Str.02
Port_8626708_0 | SOURCEANDSINK | A - FL-Str.03_NK-KK-TK
Port_8626710_2 | SOURCEANDSINK | A - FL-Str.03_NK-KK-TK
Port_8626708_1 | SOURCEANDSINK | A - FL-Str.03_NK-KK-TK
Port_8626724_1 | SOURCEANDSINK | A - FL-Str.03_NK-KK-TK
Port_8626888_0 | SOURCEANDSINK | B - SL_TK
Port_8627084_1 | SOURCEANDSINK | B - SL_TK
Port_8626888_1 | SOURCEANDSINK | B - SL_TK
Port_8626890_0 | SOURCEANDSINK | B - FL-Str.02_NK-KK-TK
Port_8627039_1 | SOURCEANDSINK | B - FL-Str.02_NK-KK-TK
Port_8626890_1 | SOURCEANDSINK | B - FL-Str.02_NK-KK-TK
Port_8627037_0 | SOURCEANDSINK | B - FL-Str.02_NK-KK-TK
Port_8627039_2 | SOURCEANDSINK | B - FL-Str.02_NK-KK-TK
Port_8627037_1 | SOURCEANDSINK | B - FL-Str.02_NK-KK-TK
Port_8627052_1 | SOURCEANDSINK | B - FL-Str.02_NK-KK-TK
Port_8627052_2 | SOURCEANDSINK | B - FL-Str.02_NK-KK-TK
Port_8627540_0 | SOURCEANDSINK | B - FL-Str.02_NK-KK-TK
Port_8627082_0 | SOURCEANDSINK | B - SL_TK
Port_8627084_2 | SOURCEANDSINK | B - SL_TK
Port_8627082_1 | SOURCEANDSINK | B - SL_TK
Port_8627100_1 | SOURCEANDSINK | B - SL_TK
Port_8627147_0 | SOURCEANDSINK | B - FL-Str.02_NK-KK-TK
Port_8627149_6 | SOURCEANDSINK | B - FL-Str.02_NK-KK-TK
Port_8627147_1 | SOURCEANDSINK | B - FL-Str.02_NK-KK-TK
Port_8627164_1 | SOURCEANDSINK | B - FL-Str.02_NK-KK-TK
Port_8627149_5 | SOURCEANDSINK | B - FL-Str.02_NK-KK-TK
Port_8627150_1 | SOURCEANDSINK | B - FL-Str.02_NK-KK-TK
Port_8627150_0 | SOURCEANDSINK | B - FL-Str.02_NK-KK-TK
Port_8627193_0 | SOURCEANDSINK | B - SL_TK
Port_8627195_6 | SOURCEANDSINK | B - SL_TK
Port_8627193_1 | SOURCEANDSINK | B - SL_TK
Port_8627210_1 | SOURCEANDSINK | B - SL_TK
Port_8627195_5 | SOURCEANDSINK | B - SL_TK
Port_8627196_1 | SOURCEANDSINK | B - SL_TK
Port_8627196_0 | SOURCEANDSINK | B - SL_TK
Port_8627290_0 | SOURCEANDSINK | A - SL_TK
Port_8627292_2 | SOURCEANDSINK | A - SL_TK
Port_8627290_1 | SOURCEANDSINK | A - SL_TK
Port_8627306_1 | SOURCEANDSINK | A - SL_TK
Port_8627336_0 | SOURCEANDSINK | A - FL-Str.02_NK-KK-TK
Port_8627338_2 | SOURCEANDSINK | A - FL-Str.02_NK-KK-TK
Port_8627336_1 | SOURCEANDSINK | A - FL-Str.02_NK-KK-TK
Port_8627349_1 | SOURCEANDSINK | A - FL-Str.02_NK-KK-TK
Port_8627537_0 | SOURCEANDSINK | B - FL-Str.02_NK-KK-TK
Port_8627539_6 | SOURCEANDSINK | B - FL-Str.02_NK-KK-TK
Port_8627537_1 | SOURCEANDSINK | B - FL-Str.02_NK-KK-TK
Port_8627545_1 | SOURCEANDSINK | B - FL-Str.02_NK-KK-TK
Port_8627539_5 | SOURCEANDSINK | B - FL-Str.02_NK-KK-TK
Port_8627540_1 | SOURCEANDSINK | B - FL-Str.02_NK-KK-TK
Port_8627621_0 | SOURCEANDSINK | B - SL_NK-Str.01
Port_8627623_2 | SOURCEANDSINK | B - SL_NK-Str.01
Port_8627621_1 | SOURCEANDSINK | B - SL_NK-Str.01
Port_8627637_1 | SOURCEANDSINK | B - SL_NK-Str.01
Port_8627680_0 | SOURCEANDSINK | B - FL-Str.01_NK-KK-TK
Port_8627836_1 | SOURCEANDSINK | B - FL-Str.01_NK-KK-TK
Port_8627680_1 | SOURCEANDSINK | B - FL-Str.01_NK-KK-TK
Port_8627683_0 | SOURCEANDSINK | B - SL_KK
Port_8627798_1 | SOURCEANDSINK | B - SL_KK
Port_8627683_1 | SOURCEANDSINK | B - SL_KK
Port_8627796_0 | SOURCEANDSINK | B - SL_KK
Port_8627798_2 | SOURCEANDSINK | B - SL_KK
Port_8627796_1 | SOURCEANDSINK | B - SL_KK
Port_8627812_1 | SOURCEANDSINK | B - SL_KK
Port_8627809_2 | SOURCEANDSINK | B - SL_KK
Port_8628539_0 | SOURCEANDSINK | B - SL_KK
Port_8627834_0 | SOURCEANDSINK | B - FL-Str.01_NK-KK-TK
Port_8627836_2 | SOURCEANDSINK | B - FL-Str.01_NK-KK-TK
Port_8627834_1 | SOURCEANDSINK | B - FL-Str.01_NK-KK-TK
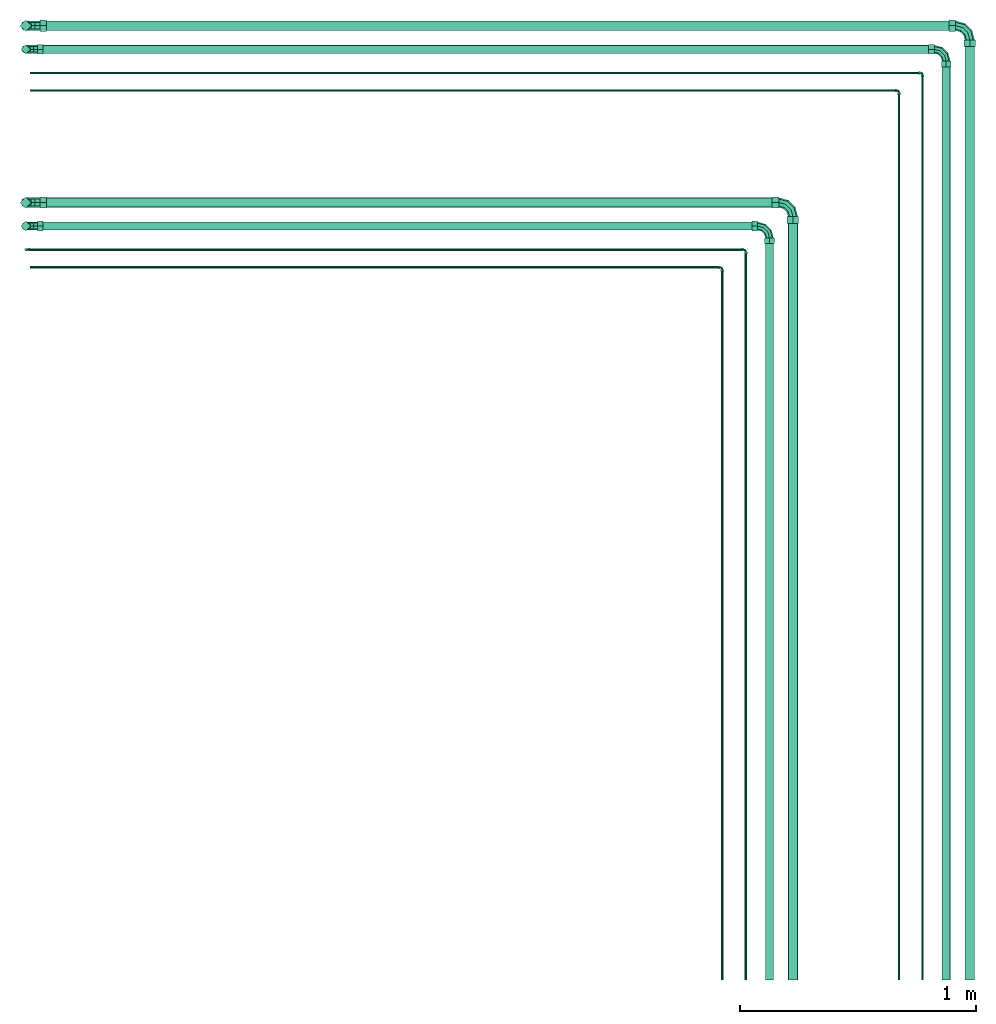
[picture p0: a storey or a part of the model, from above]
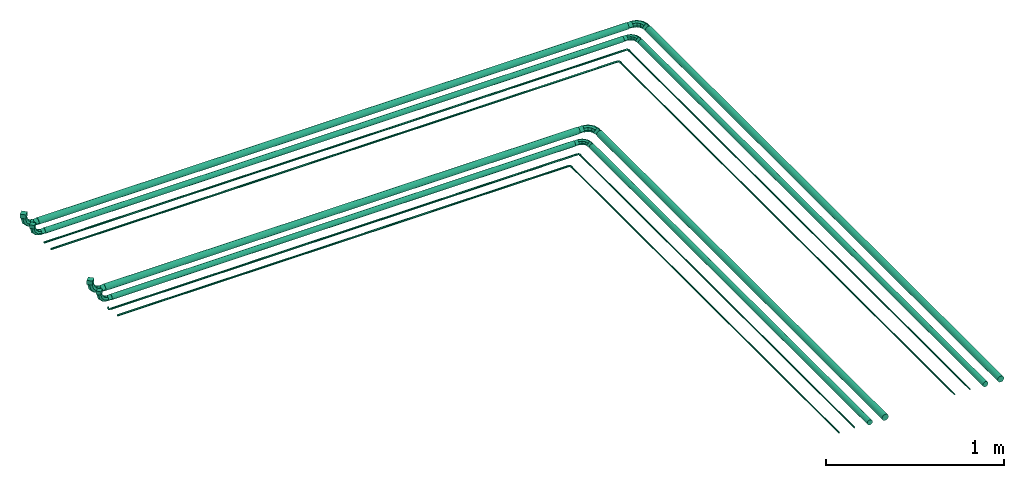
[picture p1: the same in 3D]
Properties of the parts of a building model (IFC2X3), part 5 of 7

# IfcDistributionPort (3410)
Name | FlowDirection | Group
Port_8627850_1 | SOURCEANDSINK | B - FL-Str.01_NK-KK-TK
Port_8627847_2 | SOURCEANDSINK | B - FL-Str.01_NK-KK-TK
Port_8628684_0 | SOURCEANDSINK | B - FL-Str.01_NK-KK-TK
Port_8628220_0 | SOURCEANDSINK | B - SL_KK
Port_8628407_1 | SOURCEANDSINK | B - SL_KK
Port_8628220_1 | SOURCEANDSINK | B - SL_KK
Port_8628222_0 | SOURCEANDSINK | B - FL-Str.01_NK-KK-TK
Port_8628373_1 | SOURCEANDSINK | B - FL-Str.01_NK-KK-TK
Port_8628222_1 | SOURCEANDSINK | B - FL-Str.01_NK-KK-TK
Port_8628371_0 | SOURCEANDSINK | B - FL-Str.01_NK-KK-TK
Port_8628373_2 | SOURCEANDSINK | B - FL-Str.01_NK-KK-TK
Port_8628371_1 | SOURCEANDSINK | B - FL-Str.01_NK-KK-TK
Port_8628695_1 | SOURCEANDSINK | B - FL-Str.01_NK-KK-TK
Port_8628405_0 | SOURCEANDSINK | B - SL_KK
Port_8628407_2 | SOURCEANDSINK | B - SL_KK
Port_8628405_1 | SOURCEANDSINK | B - SL_KK
Port_8628550_1 | SOURCEANDSINK | B - SL_KK
Port_8628536_0 | SOURCEANDSINK | B - SL_KK
Port_8628538_6 | SOURCEANDSINK | B - SL_KK
Port_8628536_1 | SOURCEANDSINK | B - SL_KK
Port_8628555_1 | SOURCEANDSINK | B - SL_KK
Port_8628538_5 | SOURCEANDSINK | B - SL_KK
Port_8628539_1 | SOURCEANDSINK | B - SL_KK
Port_8628681_0 | SOURCEANDSINK | B - FL-Str.01_NK-KK-TK
Port_8628683_6 | SOURCEANDSINK | B - FL-Str.01_NK-KK-TK
Port_8628681_1 | SOURCEANDSINK | B - FL-Str.01_NK-KK-TK
Port_8628700_1 | SOURCEANDSINK | B - FL-Str.01_NK-KK-TK
Port_8628683_5 | SOURCEANDSINK | B - FL-Str.01_NK-KK-TK
Port_8628684_1 | SOURCEANDSINK | B - FL-Str.01_NK-KK-TK
Port_8628792_0 | SOURCEANDSINK | A - SL_KK
Port_8628794_6 | SOURCEANDSINK | A - SL_KK
Port_8628792_1 | SOURCEANDSINK | A - SL_KK
Port_8628811_1 | SOURCEANDSINK | A - SL_KK
Port_8628794_5 | SOURCEANDSINK | A - SL_KK
Port_8628795_1 | SOURCEANDSINK | A - SL_KK
Port_8628795_0 | SOURCEANDSINK | A - SL_KK
Port_8628845_0 | SOURCEANDSINK | A - FL-Str.01_NK-KK-TK
Port_8628847_6 | SOURCEANDSINK | A - FL-Str.01_NK-KK-TK
Port_8628845_1 | SOURCEANDSINK | A - FL-Str.01_NK-KK-TK
Port_8628864_1 | SOURCEANDSINK | A - FL-Str.01_NK-KK-TK
Port_8628847_5 | SOURCEANDSINK | A - FL-Str.01_NK-KK-TK
Port_8628848_1 | SOURCEANDSINK | A - FL-Str.01_NK-KK-TK
Port_8628848_0 | SOURCEANDSINK | A - FL-Str.01_NK-KK-TK
Port_8629105_0 | SOURCEANDSINK | B - SL_KK
Port_8629107_6 | SOURCEANDSINK | B - SL_KK
Port_8629105_1 | SOURCEANDSINK | B - SL_KK
Port_8629114_1 | SOURCEANDSINK | B - SL_KK
Port_8629107_5 | SOURCEANDSINK | B - SL_KK
Port_8629108_1 | SOURCEANDSINK | B - SL_KK
Port_8629145_0 | SOURCEANDSINK | B - FL-Str.01_NK-KK-TK
Port_8629147_6 | SOURCEANDSINK | B - FL-Str.01_NK-KK-TK
Port_8629145_1 | SOURCEANDSINK | B - FL-Str.01_NK-KK-TK
Port_8629153_1 | SOURCEANDSINK | B - FL-Str.01_NK-KK-TK
Port_8629147_5 | SOURCEANDSINK | B - FL-Str.01_NK-KK-TK
Port_8629148_1 | SOURCEANDSINK | B - FL-Str.01_NK-KK-TK
Port_8629233_0 | SOURCEANDSINK | B - SL_KK
Port_8629340_1 | SOURCEANDSINK | B - SL_KK
Port_8629233_1 | SOURCEANDSINK | B - SL_KK
Port_8629236_0 | SOURCEANDSINK | B - FL-Str.01_NK-KK-TK
Port_8629304_1 | SOURCEANDSINK | B - FL-Str.01_NK-KK-TK
Port_8629236_1 | SOURCEANDSINK | B - FL-Str.01_NK-KK-TK
Port_8629302_0 | SOURCEANDSINK | B - FL-Str.01_NK-KK-TK
Port_8629304_2 | SOURCEANDSINK | B - FL-Str.01_NK-KK-TK
Port_8629302_1 | SOURCEANDSINK | B - FL-Str.01_NK-KK-TK
Port_8629315_1 | SOURCEANDSINK | B - FL-Str.01_NK-KK-TK
Port_8629338_0 | SOURCEANDSINK | B - SL_KK
Port_8629340_2 | SOURCEANDSINK | B - SL_KK
Port_8629338_1 | SOURCEANDSINK | B - SL_KK
Port_8629351_1 | SOURCEANDSINK | B - SL_KK
Port_8629655_0 | SOURCEANDSINK | B - FL-Str.02_NK-KK-TK
Port_8629657_6 | SOURCEANDSINK | B - FL-Str.02_NK-KK-TK
Port_8629655_1 | SOURCEANDSINK | B - FL-Str.02_NK-KK-TK
Port_8629672_1 | SOURCEANDSINK | B - FL-Str.02_NK-KK-TK
Port_8629657_5 | SOURCEANDSINK | B - FL-Str.02_NK-KK-TK
Port_8629658_1 | SOURCEANDSINK | B - FL-Str.02_NK-KK-TK
Port_8629658_0 | SOURCEANDSINK | B - FL-Str.02_NK-KK-TK
Port_8629699_0 | SOURCEANDSINK | B - SL_TK
Port_8629701_6 | SOURCEANDSINK | B - SL_TK
Port_8629699_1 | SOURCEANDSINK | B - SL_TK
Port_8629716_1 | SOURCEANDSINK | B - SL_TK
Port_8629701_5 | SOURCEANDSINK | B - SL_TK
Port_8629702_1 | SOURCEANDSINK | B - SL_TK
Port_8629702_0 | SOURCEANDSINK | B - SL_TK
Port_8629746_0 | SOURCEANDSINK | A - FL-Str.02_NK-KK-TK
Port_8629874_4 | SOURCEANDSINK | A - FL-Str.02_NK-KK-TK
Port_8629746_1 | SOURCEANDSINK | A - FL-Str.02_NK-KK-TK
Port_8629748_0 | SOURCEANDSINK | A - SL_TK
Port_8629830_4 | SOURCEANDSINK | A - SL_TK
Port_8629748_1 | SOURCEANDSINK | A - SL_TK
Port_8629828_0 | SOURCEANDSINK | A - SL_TK
Port_8629830_6 | SOURCEANDSINK | A - SL_TK
Port_8629828_1 | SOURCEANDSINK | A - SL_TK
Port_8629845_1 | SOURCEANDSINK | A - SL_TK
Port_8629830_5 | SOURCEANDSINK | A - SL_TK
Port_8629831_1 | SOURCEANDSINK | A - SL_TK
Port_8629831_0 | SOURCEANDSINK | A - SL_TK
Port_8629872_0 | SOURCEANDSINK | A - FL-Str.02_NK-KK-TK
Port_8629874_6 | SOURCEANDSINK | A - FL-Str.02_NK-KK-TK
Port_8629872_1 | SOURCEANDSINK | A - FL-Str.02_NK-KK-TK
Port_8629889_1 | SOURCEANDSINK | A - FL-Str.02_NK-KK-TK
Port_8629874_5 | SOURCEANDSINK | A - FL-Str.02_NK-KK-TK
Port_8629875_1 | SOURCEANDSINK | A - FL-Str.02_NK-KK-TK
Port_8629875_0 | SOURCEANDSINK | A - FL-Str.02_NK-KK-TK
Port_8629948_0 | SOURCEANDSINK | A - FL-Str.02_NK-KK-TK
Port_8630087_4 | SOURCEANDSINK | A - FL-Str.02_NK-KK-TK
Port_8629948_1 | SOURCEANDSINK | A - FL-Str.02_NK-KK-TK
Port_8629950_0 | SOURCEANDSINK | A - SL_TK
Port_8630043_4 | SOURCEANDSINK | A - SL_TK
Port_8629950_1 | SOURCEANDSINK | A - SL_TK
Port_8630041_0 | SOURCEANDSINK | A - SL_TK
Port_8630043_6 | SOURCEANDSINK | A - SL_TK
Port_8630041_1 | SOURCEANDSINK | A - SL_TK
Port_8630058_1 | SOURCEANDSINK | A - SL_TK
Port_8630043_5 | SOURCEANDSINK | A - SL_TK
Port_8630044_1 | SOURCEANDSINK | A - SL_TK
Port_8630044_0 | SOURCEANDSINK | A - SL_TK
Port_8630085_0 | SOURCEANDSINK | A - FL-Str.02_NK-KK-TK
Port_8630087_6 | SOURCEANDSINK | A - FL-Str.02_NK-KK-TK
Port_8630085_1 | SOURCEANDSINK | A - FL-Str.02_NK-KK-TK
Port_8630102_1 | SOURCEANDSINK | A - FL-Str.02_NK-KK-TK
Port_8630087_5 | SOURCEANDSINK | A - FL-Str.02_NK-KK-TK
Port_8630088_1 | SOURCEANDSINK | A - FL-Str.02_NK-KK-TK
Port_8630088_0 | SOURCEANDSINK | A - FL-Str.02_NK-KK-TK
Port_8630295_0 | SOURCEANDSINK | B - SL_KK
Port_8630337_1 | SOURCEANDSINK | B - SL_KK
Port_8630295_1 | SOURCEANDSINK | B - SL_KK
Port_8630335_0 | SOURCEANDSINK | B - SL_KK
Port_8630337_2 | SOURCEANDSINK | B - SL_KK
Port_8630335_1 | SOURCEANDSINK | B - SL_KK
Port_8630353_1 | SOURCEANDSINK | B - SL_KK
Port_8630543_0 | SOURCEANDSINK | A - SL_KK
Port_8630847_2 | SOURCEANDSINK | A - SL_KK
Port_8630543_1 | SOURCEANDSINK | A - SL_KK
Port_8630613_0 | SOURCEANDSINK | A - FL-Str.02_NK-KK-TK
Port_8630878_2 | SOURCEANDSINK | A - FL-Str.02_NK-KK-TK
Port_8630613_1 | SOURCEANDSINK | A - FL-Str.02_NK-KK-TK
Port_8630841_0 | SOURCEANDSINK | A - SL_KK
Port_8630843_2 | SOURCEANDSINK | A - SL_KK
Port_8630841_1 | SOURCEANDSINK | A - SL_KK
Port_8630847_1 | SOURCEANDSINK | A - SL_KK
Port_8630872_0 | SOURCEANDSINK | A - FL-Str.02_NK-KK-TK
Port_8630874_2 | SOURCEANDSINK | A - FL-Str.02_NK-KK-TK
Port_8630872_1 | SOURCEANDSINK | A - FL-Str.02_NK-KK-TK
Port_8630878_1 | SOURCEANDSINK | A - FL-Str.02_NK-KK-TK
Port_8630991_0 | SOURCEANDSINK | A - SL_KK
Port_8630993_2 | SOURCEANDSINK | A - SL_KK
Port_8630991_1 | SOURCEANDSINK | A - SL_KK
Port_8630997_1 | SOURCEANDSINK | A - SL_KK
Port_8631023_0 | SOURCEANDSINK | A - FL-Str.02_NK-KK-TK
Port_8631025_2 | SOURCEANDSINK | A - FL-Str.02_NK-KK-TK
Port_8631023_1 | SOURCEANDSINK | A - FL-Str.02_NK-KK-TK
Port_8631029_1 | SOURCEANDSINK | A - FL-Str.02_NK-KK-TK
Port_8631107_0 | SOURCEANDSINK | B - SL_KK
Port_8631140_1 | SOURCEANDSINK | B - SL_KK
Port_8631107_1 | SOURCEANDSINK | B - SL_KK
Port_8631138_0 | SOURCEANDSINK | B - SL_KK
Port_8631140_2 | SOURCEANDSINK | B - SL_KK
Port_8631138_1 | SOURCEANDSINK | B - SL_KK
Port_8631156_1 | SOURCEANDSINK | B - SL_KK
Port_8631173_0 | SOURCEANDSINK | B - FL-Str.01_NK-KK-TK
Port_8631253_1 | SOURCEANDSINK | B - FL-Str.01_NK-KK-TK
Port_8631173_1 | SOURCEANDSINK | B - FL-Str.01_NK-KK-TK
Port_8631176_0 | SOURCEANDSINK | B - SL_NK-Str.01
Port_8631304_1 | SOURCEANDSINK | B - SL_NK-Str.01
Port_8631176_1 | SOURCEANDSINK | B - SL_NK-Str.01
Port_8631251_0 | SOURCEANDSINK | B - FL-Str.01_NK-KK-TK
Port_8631255_2 | SOURCEANDSINK | B - FL-Str.01_NK-KK-TK
Port_8631251_1 | SOURCEANDSINK | B - FL-Str.01_NK-KK-TK
Port_8631271_1 | SOURCEANDSINK | B - FL-Str.01_NK-KK-TK
Port_8631253_2 | SOURCEANDSINK | B - FL-Str.01_NK-KK-TK
Port_8631255_1 | SOURCEANDSINK | B - FL-Str.01_NK-KK-TK
Port_8631302_0 | SOURCEANDSINK | B - SL_NK-Str.01
Port_8631306_2 | SOURCEANDSINK | B - SL_NK-Str.01
Port_8631302_1 | SOURCEANDSINK | B - SL_NK-Str.01
Port_8631321_1 | SOURCEANDSINK | B - SL_NK-Str.01
Port_8631304_2 | SOURCEANDSINK | B - SL_NK-Str.01
Port_8631306_1 | SOURCEANDSINK | B - SL_NK-Str.01
Port_8631348_0 | SOURCEANDSINK | B - FL-Str.01_NK-KK-TK
Port_8632260_2 | SOURCEANDSINK | B - FL-Str.01_NK-KK-TK
Port_8631348_1 | SOURCEANDSINK | B - FL-Str.01_NK-KK-TK
Port_8631351_0 | SOURCEANDSINK | B - SL_NK-Str.01
Port_8632301_2 | SOURCEANDSINK | B - SL_NK-Str.01
Port_8631351_1 | SOURCEANDSINK | B - SL_NK-Str.01
Port_8631371_0 | SOURCEANDSINK | B - FL-Str.01_NK-KK-TK
Port_8632068_1 | SOURCEANDSINK | B - FL-Str.01_NK-KK-TK
Port_8631371_1 | SOURCEANDSINK | B - FL-Str.01_NK-KK-TK
Port_8631374_0 | SOURCEANDSINK | B - SL_NK-Str.01
Port_8632118_1 | SOURCEANDSINK | B - SL_NK-Str.01
Port_8631374_1 | SOURCEANDSINK | B - SL_NK-Str.01
Port_8631388_0 | SOURCEANDSINK | A - SL_NK-Str.01
Port_8631909_2 | SOURCEANDSINK | A - SL_NK-Str.01
Port_8631388_1 | SOURCEANDSINK | A - SL_NK-Str.01
Port_8631391_0 | SOURCEANDSINK | A - FL-Str.01_NK-KK-TK
Port_8631951_2 | SOURCEANDSINK | A - FL-Str.01_NK-KK-TK
Port_8631391_1 | SOURCEANDSINK | A - FL-Str.01_NK-KK-TK
Port_8631415_0 | SOURCEANDSINK | A - FL-Str.01_NK-KK-TK
Port_8631702_1 | SOURCEANDSINK | A - FL-Str.01_NK-KK-TK
Port_8631415_1 | SOURCEANDSINK | A - FL-Str.01_NK-KK-TK
Port_8631418_0 | SOURCEANDSINK | A - SL_NK-Str.01
Port_8631761_2 | SOURCEANDSINK | A - SL_NK-Str.01
Port_8631418_1 | SOURCEANDSINK | A - SL_NK-Str.01
Port_8631434_0 | SOURCEANDSINK | A - SL_NK-Str.01
Port_8631544_1 | SOURCEANDSINK | A - SL_NK-Str.01
Port_8631434_1 | SOURCEANDSINK | A - SL_NK-Str.01
Port_8631437_0 | SOURCEANDSINK | A - FL-Str.01_NK-KK-TK
Port_8631594_1 | SOURCEANDSINK | A - FL-Str.01_NK-KK-TK
Port_8631437_1 | SOURCEANDSINK | A - FL-Str.01_NK-KK-TK
Port_8631542_0 | SOURCEANDSINK | A - SL_NK-Str.01
Port_8631546_2 | SOURCEANDSINK | A - SL_NK-Str.01
Port_8631542_1 | SOURCEANDSINK | A - SL_NK-Str.01
Port_8631561_1 | SOURCEANDSINK | A - SL_NK-Str.01
Port_8631544_2 | SOURCEANDSINK | A - SL_NK-Str.01
Port_8631546_1 | SOURCEANDSINK | A - SL_NK-Str.01
Port_8631592_0 | SOURCEANDSINK | A - FL-Str.01_NK-KK-TK
Port_8631596_2 | SOURCEANDSINK | A - FL-Str.01_NK-KK-TK
Port_8631592_1 | SOURCEANDSINK | A - FL-Str.01_NK-KK-TK
Port_8631611_1 | SOURCEANDSINK | A - FL-Str.01_NK-KK-TK
Port_8631594_2 | SOURCEANDSINK | A - FL-Str.01_NK-KK-TK
Port_8631596_1 | SOURCEANDSINK | A - FL-Str.01_NK-KK-TK
Port_8631700_0 | SOURCEANDSINK | A - FL-Str.01_NK-KK-TK
Port_8631704_2 | SOURCEANDSINK | A - FL-Str.01_NK-KK-TK
Port_8631700_1 | SOURCEANDSINK | A - FL-Str.01_NK-KK-TK
Port_8631719_1 | SOURCEANDSINK | A - FL-Str.01_NK-KK-TK
Port_8631702_2 | SOURCEANDSINK | A - FL-Str.01_NK-KK-TK
Port_8631704_1 | SOURCEANDSINK | A - FL-Str.01_NK-KK-TK
Port_8631751_0 | SOURCEANDSINK | A - SL_NK-Str.01
Port_8631755_2 | SOURCEANDSINK | A - SL_NK-Str.01
Port_8631751_1 | SOURCEANDSINK | A - SL_NK-Str.01
Port_8631761_1 | SOURCEANDSINK | A - SL_NK-Str.01
Port_8631753_2 | SOURCEANDSINK | A - SL_NK-Str.01
Port_8631755_1 | SOURCEANDSINK | A - SL_NK-Str.01
Port_8631900_0 | SOURCEANDSINK | A - SL_NK-Str.01
Port_8631904_2 | SOURCEANDSINK | A - SL_NK-Str.01
Port_8631900_1 | SOURCEANDSINK | A - SL_NK-Str.01
Port_8631909_1 | SOURCEANDSINK | A - SL_NK-Str.01
Port_8631902_2 | SOURCEANDSINK | A - SL_NK-Str.01
Port_8631904_1 | SOURCEANDSINK | A - SL_NK-Str.01
Port_8631942_0 | SOURCEANDSINK | A - FL-Str.01_NK-KK-TK
Port_8631946_2 | SOURCEANDSINK | A - FL-Str.01_NK-KK-TK
Port_8631942_1 | SOURCEANDSINK | A - FL-Str.01_NK-KK-TK
Port_8631951_1 | SOURCEANDSINK | A - FL-Str.01_NK-KK-TK
Port_8631944_2 | SOURCEANDSINK | A - FL-Str.01_NK-KK-TK
Port_8631946_1 | SOURCEANDSINK | A - FL-Str.01_NK-KK-TK
Port_8632066_0 | SOURCEANDSINK | B - FL-Str.01_NK-KK-TK
Port_8632070_2 | SOURCEANDSINK | B - FL-Str.01_NK-KK-TK
Port_8632066_1 | SOURCEANDSINK | B - FL-Str.01_NK-KK-TK
Port_8632085_1 | SOURCEANDSINK | B - FL-Str.01_NK-KK-TK
Port_8632068_2 | SOURCEANDSINK | B - FL-Str.01_NK-KK-TK
Port_8632070_1 | SOURCEANDSINK | B - FL-Str.01_NK-KK-TK
Port_8632116_0 | SOURCEANDSINK | B - SL_NK-Str.01
Port_8632120_2 | SOURCEANDSINK | B - SL_NK-Str.01
Port_8632116_1 | SOURCEANDSINK | B - SL_NK-Str.01
Port_8632135_1 | SOURCEANDSINK | B - SL_NK-Str.01
Port_8632118_2 | SOURCEANDSINK | B - SL_NK-Str.01
Port_8632120_1 | SOURCEANDSINK | B - SL_NK-Str.01
Port_8632251_0 | SOURCEANDSINK | B - FL-Str.01_NK-KK-TK
Port_8632255_2 | SOURCEANDSINK | B - FL-Str.01_NK-KK-TK
Port_8632251_1 | SOURCEANDSINK | B - FL-Str.01_NK-KK-TK
Port_8632260_1 | SOURCEANDSINK | B - FL-Str.01_NK-KK-TK
Port_8632253_2 | SOURCEANDSINK | B - FL-Str.01_NK-KK-TK
Port_8632255_1 | SOURCEANDSINK | B - FL-Str.01_NK-KK-TK
Port_8632292_0 | SOURCEANDSINK | B - SL_NK-Str.01
Port_8632296_2 | SOURCEANDSINK | B - SL_NK-Str.01
Port_8632292_1 | SOURCEANDSINK | B - SL_NK-Str.01
Port_8632301_1 | SOURCEANDSINK | B - SL_NK-Str.01
Port_8632294_2 | SOURCEANDSINK | B - SL_NK-Str.01
Port_8632296_1 | SOURCEANDSINK | B - SL_NK-Str.01
Port_8632410_0 | SOURCEANDSINK | A - FL-Str.02_NK-KK-TK
Port_8633158_1 | SOURCEANDSINK | A - FL-Str.02_NK-KK-TK
Port_8632410_1 | SOURCEANDSINK | A - FL-Str.02_NK-KK-TK
Port_8632413_0 | SOURCEANDSINK | A - SL_NK-Str.01
Port_8633110_1 | SOURCEANDSINK | A - SL_NK-Str.01
Port_8632413_1 | SOURCEANDSINK | A - SL_NK-Str.01
Port_8632427_0 | SOURCEANDSINK | B - FL-Str.02_NK-KK-TK
Port_8632539_1 | SOURCEANDSINK | B - FL-Str.02_NK-KK-TK
Port_8632427_1 | SOURCEANDSINK | B - FL-Str.02_NK-KK-TK
Port_8632430_0 | SOURCEANDSINK | B - SL_NK-Str.01
Port_8632590_2 | SOURCEANDSINK | B - SL_NK-Str.01
Port_8632430_1 | SOURCEANDSINK | B - SL_NK-Str.01
Port_8632537_0 | SOURCEANDSINK | B - FL-Str.02_NK-KK-TK
Port_8632539_2 | SOURCEANDSINK | B - FL-Str.02_NK-KK-TK
Port_8632537_1 | SOURCEANDSINK | B - FL-Str.02_NK-KK-TK
Port_8632553_1 | SOURCEANDSINK | B - FL-Str.02_NK-KK-TK
Port_8632584_0 | SOURCEANDSINK | B - SL_NK-Str.01
Port_8632586_2 | SOURCEANDSINK | B - SL_NK-Str.01
Port_8632584_1 | SOURCEANDSINK | B - SL_NK-Str.01
Port_8632590_1 | SOURCEANDSINK | B - SL_NK-Str.01
Port_8632693_0 | SOURCEANDSINK | A - SL_NK-Str.01
Port_8632830_1 | SOURCEANDSINK | A - SL_NK-Str.01
Port_8632693_1 | SOURCEANDSINK | A - SL_NK-Str.01
Port_8632696_0 | SOURCEANDSINK | A - FL-Str.02_NK-KK-TK
Port_8632784_1 | SOURCEANDSINK | A - FL-Str.02_NK-KK-TK
Port_8632696_1 | SOURCEANDSINK | A - FL-Str.02_NK-KK-TK
Port_8632782_0 | SOURCEANDSINK | A - FL-Str.02_NK-KK-TK
Port_8632784_2 | SOURCEANDSINK | A - FL-Str.02_NK-KK-TK
Port_8632782_1 | SOURCEANDSINK | A - FL-Str.02_NK-KK-TK
Port_8632798_1 | SOURCEANDSINK | A - FL-Str.02_NK-KK-TK
Port_8632828_0 | SOURCEANDSINK | A - SL_NK-Str.01
Port_8632830_2 | SOURCEANDSINK | A - SL_NK-Str.01
Port_8632828_1 | SOURCEANDSINK | A - SL_NK-Str.01
Port_8632844_1 | SOURCEANDSINK | A - SL_NK-Str.01
Port_8632865_0 | SOURCEANDSINK | B - SL_NK-Str.01
Port_8632992_2 | SOURCEANDSINK | B - SL_NK-Str.01
Port_8632865_1 | SOURCEANDSINK | B - SL_NK-Str.01
Port_8632868_0 | SOURCEANDSINK | B - FL-Str.02_NK-KK-TK
Port_8632957_2 | SOURCEANDSINK | B - FL-Str.02_NK-KK-TK
Port_8632868_1 | SOURCEANDSINK | B - FL-Str.02_NK-KK-TK
Port_8632951_0 | SOURCEANDSINK | B - FL-Str.02_NK-KK-TK
Port_8632953_2 | SOURCEANDSINK | B - FL-Str.02_NK-KK-TK
Port_8632951_1 | SOURCEANDSINK | B - FL-Str.02_NK-KK-TK
Port_8632957_1 | SOURCEANDSINK | B - FL-Str.02_NK-KK-TK
Port_8632986_0 | SOURCEANDSINK | B - SL_NK-Str.01
Port_8632988_2 | SOURCEANDSINK | B - SL_NK-Str.01
Port_8632986_1 | SOURCEANDSINK | B - SL_NK-Str.01
Port_8632992_1 | SOURCEANDSINK | B - SL_NK-Str.01
Port_8633108_0 | SOURCEANDSINK | A - SL_NK-Str.01
Port_8633110_2 | SOURCEANDSINK | A - SL_NK-Str.01
Port_8633108_1 | SOURCEANDSINK | A - SL_NK-Str.01
Port_8633124_1 | SOURCEANDSINK | A - SL_NK-Str.01
Port_8633156_0 | SOURCEANDSINK | A - FL-Str.02_NK-KK-TK
Port_8633158_2 | SOURCEANDSINK | A - FL-Str.02_NK-KK-TK
Port_8633156_1 | SOURCEANDSINK | A - FL-Str.02_NK-KK-TK
Port_8633172_1 | SOURCEANDSINK | A - FL-Str.02_NK-KK-TK
Port_8633215_0 | SOURCEANDSINK | A - SL_NK-Str.01
Port_8633556_1 | SOURCEANDSINK | A - SL_NK-Str.01
Port_8633215_1 | SOURCEANDSINK | A - SL_NK-Str.01
Port_8633217_0 | SOURCEANDSINK | A - FL-Str.02_NK-KK-TK
Port_8633627_1 | SOURCEANDSINK | A - FL-Str.02_NK-KK-TK
Port_8633217_1 | SOURCEANDSINK | A - FL-Str.02_NK-KK-TK
Port_8633364_0 | SOURCEANDSINK | A - SL_NK-Str.01
Port_8633567_2 | SOURCEANDSINK | A - SL_NK-Str.01
Port_8633364_1 | SOURCEANDSINK | A - SL_NK-Str.01
Port_8633570_2 | SOURCEANDSINK | A - SL_NK-Str.01
Port_8633466_0 | SOURCEANDSINK | A - FL-Str.02_NK-KK-TK
Port_8633636_1 | SOURCEANDSINK | A - FL-Str.02_NK-KK-TK
Port_8633466_1 | SOURCEANDSINK | A - FL-Str.02_NK-KK-TK
Port_8633639_2 | SOURCEANDSINK | A - FL-Str.02_NK-KK-TK
Port_8633468_0 | SOURCEANDSINK | A - SL_NK-Str.01
Port_8633567_1 | SOURCEANDSINK | A - SL_NK-Str.01
Port_8633468_1 | SOURCEANDSINK | A - SL_NK-Str.01
Port_8633476_1 | SOURCEANDSINK | A - SL_NK-Str.01
Port_8633554_0 | SOURCEANDSINK | A - SL_NK-Str.01
Port_8633556_2 | SOURCEANDSINK | A - SL_NK-Str.01
Port_8633554_1 | SOURCEANDSINK | A - SL_NK-Str.01
Port_8633570_1 | SOURCEANDSINK | A - SL_NK-Str.01
Port_8633625_0 | SOURCEANDSINK | A - FL-Str.02_NK-KK-TK
Port_8633627_2 | SOURCEANDSINK | A - FL-Str.02_NK-KK-TK
Port_8633625_1 | SOURCEANDSINK | A - FL-Str.02_NK-KK-TK
Port_8633639_1 | SOURCEANDSINK | A - FL-Str.02_NK-KK-TK
Port_8633664_0 | SOURCEANDSINK | B - SL_NK-Str.01
Port_8633679_2 | SOURCEANDSINK | B - SL_NK-Str.01
Port_8633664_1 | SOURCEANDSINK | B - SL_NK-Str.01
Port_8633682_2 | SOURCEANDSINK | B - SL_NK-Str.01
Port_8633667_0 | SOURCEANDSINK | B - FL-Str.02_NK-KK-TK
Port_8633708_1 | SOURCEANDSINK | B - FL-Str.02_NK-KK-TK
Port_8633667_1 | SOURCEANDSINK | B - FL-Str.02_NK-KK-TK
Port_8633711_2 | SOURCEANDSINK | B - FL-Str.02_NK-KK-TK
Port_8633669_0 | SOURCEANDSINK | B - SL_NK-Str.01
Port_8633679_1 | SOURCEANDSINK | B - SL_NK-Str.01
Port_8633669_1 | SOURCEANDSINK | B - SL_NK-Str.01
Port_8633716_1 | SOURCEANDSINK | B - SL_NK-Str.01
Port_8633673_0 | SOURCEANDSINK | B - SL_NK-Str.01
Port_8633673_1 | SOURCEANDSINK | B - SL_NK-Str.01
Port_8633682_1 | SOURCEANDSINK | B - SL_NK-Str.01
Port_8633685_0 | SOURCEANDSINK | B - FL-Str.02_NK-KK-TK
Port_8633685_1 | SOURCEANDSINK | B - FL-Str.02_NK-KK-TK
Port_8633711_1 | SOURCEANDSINK | B - FL-Str.02_NK-KK-TK
Port_8634067_0 | SOURCEANDSINK | A - FL-Str.01_NK-KK-TK
Port_8634474_2 | SOURCEANDSINK | A - FL-Str.01_NK-KK-TK
Port_8634067_1 | SOURCEANDSINK | A - FL-Str.01_NK-KK-TK
Port_8634479_2 | SOURCEANDSINK | A - FL-Str.01_NK-KK-TK
Port_8634070_0 | SOURCEANDSINK | A - SL_KK
Port_8634355_2 | SOURCEANDSINK | A - SL_KK
Port_8634070_1 | SOURCEANDSINK | A - SL_KK
Port_8634360_2 | SOURCEANDSINK | A - SL_KK
Port_8634119_1 | SOURCEANDSINK | A - FL-Str.01_NK-KK-TK
Port_8634463_1 | SOURCEANDSINK | A - FL-Str.01_NK-KK-TK
Port_8634135_1 | SOURCEANDSINK | A - SL_KK
Port_8634344_1 | SOURCEANDSINK | A - SL_KK
Port_8634314_0 | SOURCEANDSINK | A - SL_KK
Port_8634316_2 | SOURCEANDSINK | A - SL_KK
Port_8634314_1 | SOURCEANDSINK | A - SL_KK
Port_8634355_1 | SOURCEANDSINK | A - SL_KK
Port_8634342_0 | SOURCEANDSINK | A - SL_KK
Port_8634344_2 | SOURCEANDSINK | A - SL_KK
Port_8634342_1 | SOURCEANDSINK | A - SL_KK
Port_8634360_1 | SOURCEANDSINK | A - SL_KK
Port_8634382_0 | SOURCEANDSINK | A - FL-Str.01_NK-KK-TK
Port_8634384_2 | SOURCEANDSINK | A - FL-Str.01_NK-KK-TK
Port_8634382_1 | SOURCEANDSINK | A - FL-Str.01_NK-KK-TK
Port_8634474_1 | SOURCEANDSINK | A - FL-Str.01_NK-KK-TK
Port_8634461_0 | SOURCEANDSINK | A - FL-Str.01_NK-KK-TK
Port_8634463_2 | SOURCEANDSINK | A - FL-Str.01_NK-KK-TK
Port_8634461_1 | SOURCEANDSINK | A - FL-Str.01_NK-KK-TK
Port_8634479_1 | SOURCEANDSINK | A - FL-Str.01_NK-KK-TK
Port_8679507_0 | SOURCEANDSINK | B - FL-Str.04_NK
Port_8679840_1 | SOURCEANDSINK | B - FL-Str.04_NK
Port_8679507_1 | SOURCEANDSINK | B - FL-Str.04_NK
Port_8679535_0 | SOURCEANDSINK | B - FL-Str.04_NK
Port_8679840_2 | SOURCEANDSINK | B - FL-Str.04_NK
Port_8679535_1 | SOURCEANDSINK | B - FL-Str.04_NK
Port_8679629_1 | SOURCEANDSINK | B - FL-Str.04_NK
Port_8679567_0 | SOURCEANDSINK | B - FL-Str.04_NK
Port_8680529_2 | SOURCEANDSINK | B - FL-Str.04_NK
Port_8679567_1 | SOURCEANDSINK | B - FL-Str.04_NK
Port_8680534_2 | SOURCEANDSINK | B - FL-Str.04_NK
Port_8679627_0 | SOURCEANDSINK | B - FL-Str.04_NK
Port_8679629_2 | SOURCEANDSINK | B - FL-Str.04_NK
Port_8679627_1 | SOURCEANDSINK | B - FL-Str.04_NK
Port_8680529_1 | SOURCEANDSINK | B - FL-Str.04_NK
Port_8679820_0 | SOURCEANDSINK | B - FL-Str.04_NK
Port_8680520_1 | SOURCEANDSINK | B - FL-Str.04_NK
Port_8679820_1 | SOURCEANDSINK | B - FL-Str.04_NK
Port_8680025_0 | SOURCEANDSINK | B - SL_NK-Str.03
Port_8680497_2 | SOURCEANDSINK | B - SL_NK-Str.03
Port_8680025_1 | SOURCEANDSINK | B - SL_NK-Str.03
Port_8680056_0 | SOURCEANDSINK | B - SL_NK-Str.03
Port_8680107_2 | SOURCEANDSINK | B - SL_NK-Str.03
Port_8680056_1 | SOURCEANDSINK | B - SL_NK-Str.03
Port_8680110_2 | SOURCEANDSINK | B - SL_NK-Str.03
Port_8680059_0 | SOURCEANDSINK | B - SL_NK-Str.03
Port_8680067_2 | SOURCEANDSINK | B - SL_NK-Str.03
Port_8680059_1 | SOURCEANDSINK | B - SL_NK-Str.03
Port_8680493_1 | SOURCEANDSINK | B - SL_NK-Str.03
Port_8680061_0 | SOURCEANDSINK | B - SL_NK-Str.03
Port_8680110_1 | SOURCEANDSINK | B - SL_NK-Str.03
Port_8680061_1 | SOURCEANDSINK | B - SL_NK-Str.03
Port_8680067_1 | SOURCEANDSINK | B - SL_NK-Str.03
Port_8680091_0 | SOURCEANDSINK | B - SL_NK-Str.03
Port_8680107_1 | SOURCEANDSINK | B - SL_NK-Str.03
Port_8680091_1 | SOURCEANDSINK | B - SL_NK-Str.03
Port_8680134_0 | SOURCEANDSINK | A - FL-Str.04_NK
Port_8680641_2 | SOURCEANDSINK | A - FL-Str.04_NK
Port_8680134_1 | SOURCEANDSINK | A - FL-Str.04_NK
Port_8680160_0 | SOURCEANDSINK | A - FL-Str.04_NK
Port_8680208_1 | SOURCEANDSINK | A - FL-Str.04_NK
Port_8680160_1 | SOURCEANDSINK | A - FL-Str.04_NK
Port_8680185_0 | SOURCEANDSINK | A - FL-Str.04_NK
Port_8680208_2 | SOURCEANDSINK | A - FL-Str.04_NK
Port_8680185_1 | SOURCEANDSINK | A - FL-Str.04_NK
Port_8680211_2 | SOURCEANDSINK | A - FL-Str.04_NK
Port_8680188_0 | SOURCEANDSINK | A - FL-Str.04_NK
Port_8680193_2 | SOURCEANDSINK | A - FL-Str.04_NK
Port_8680188_1 | SOURCEANDSINK | A - FL-Str.04_NK
Port_8680637_1 | SOURCEANDSINK | A - FL-Str.04_NK
Port_8680190_0 | SOURCEANDSINK | A - FL-Str.04_NK
Port_8680211_1 | SOURCEANDSINK | A - FL-Str.04_NK
Port_8680190_1 | SOURCEANDSINK | A - FL-Str.04_NK
Port_8680193_1 | SOURCEANDSINK | A - FL-Str.04_NK
Port_8680231_0 | SOURCEANDSINK | A - SL_NK-Str.03
Port_8680582_1 | SOURCEANDSINK | A - SL_NK-Str.03
Port_8680231_1 | SOURCEANDSINK | A - SL_NK-Str.03
Port_8680261_0 | SOURCEANDSINK | A - SL_NK-Str.03
Port_8680309_1 | SOURCEANDSINK | A - SL_NK-Str.03
Port_8680261_1 | SOURCEANDSINK | A - SL_NK-Str.03
Port_8680286_0 | SOURCEANDSINK | A - SL_NK-Str.03
Port_8680309_2 | SOURCEANDSINK | A - SL_NK-Str.03
Port_8680286_1 | SOURCEANDSINK | A - SL_NK-Str.03
Port_8680312_2 | SOURCEANDSINK | A - SL_NK-Str.03
Port_8680289_0 | SOURCEANDSINK | A - SL_NK-Str.03
Port_8680591_2 | SOURCEANDSINK | A - SL_NK-Str.03
Port_8680289_1 | SOURCEANDSINK | A - SL_NK-Str.03
Port_8680596_2 | SOURCEANDSINK | A - SL_NK-Str.03
Port_8680291_0 | SOURCEANDSINK | A - SL_NK-Str.03
Port_8680312_1 | SOURCEANDSINK | A - SL_NK-Str.03
Port_8680291_1 | SOURCEANDSINK | A - SL_NK-Str.03
Port_8680591_1 | SOURCEANDSINK | A - SL_NK-Str.03
Port_8680491_0 | SOURCEANDSINK | B - SL_NK-Str.03
Port_8680493_2 | SOURCEANDSINK | B - SL_NK-Str.03
Port_8680491_1 | SOURCEANDSINK | B - SL_NK-Str.03
Port_8680497_1 | SOURCEANDSINK | B - SL_NK-Str.03
Port_8680518_0 | SOURCEANDSINK | B - FL-Str.04_NK
Port_8680520_2 | SOURCEANDSINK | B - FL-Str.04_NK
Port_8680518_1 | SOURCEANDSINK | B - FL-Str.04_NK
Port_8680534_1 | SOURCEANDSINK | B - FL-Str.04_NK
Port_8680580_0 | SOURCEANDSINK | A - SL_NK-Str.03
Port_8680582_2 | SOURCEANDSINK | A - SL_NK-Str.03
Port_8680580_1 | SOURCEANDSINK | A - SL_NK-Str.03
Port_8680596_1 | SOURCEANDSINK | A - SL_NK-Str.03
Port_8680635_0 | SOURCEANDSINK | A - FL-Str.04_NK
Port_8680637_2 | SOURCEANDSINK | A - FL-Str.04_NK
Port_8680635_1 | SOURCEANDSINK | A - FL-Str.04_NK
Port_8680641_1 | SOURCEANDSINK | A - FL-Str.04_NK
Port_10081993_0 | SOURCEANDSINK | B - Druckleitung Gaskühler
Port_10082034_2 | SOURCEANDSINK | B - Druckleitung Gaskühler
Port_10081993_1 | SOURCEANDSINK | B - Druckleitung Gaskühler
Port_10082039_1 | SOURCEANDSINK | B - Druckleitung Gaskühler
Port_10082054_0 | SOURCEANDSINK | B - Druckleitung Gaskühler
Port_10082099_2 | SOURCEANDSINK | B - Druckleitung Gaskühler
Port_10082054_1 | SOURCEANDSINK | B - Druckleitung Gaskühler
Port_10082104_2 | SOURCEANDSINK | B - Druckleitung Gaskühler
Port_10082160_0 | SOURCEANDSINK | A - Kondensatleitung Gaskühler
Port_10082179_2 | SOURCEANDSINK | A - Kondensatleitung Gaskühler
Port_10082160_1 | SOURCEANDSINK | A - Kondensatleitung Gaskühler
Port_10082182_2 | SOURCEANDSINK | A - Kondensatleitung Gaskühler
Port_10082199_0 | SOURCEANDSINK | A - Druckleitung Gaskühler
Port_10082314_2 | SOURCEANDSINK | A - Druckleitung Gaskühler
Port_10082199_1 | SOURCEANDSINK | A - Druckleitung Gaskühler
Port_10082317_2 | SOURCEANDSINK | A - Druckleitung Gaskühler
Port_10082240_0 | SOURCEANDSINK | A - Druckleitung Gaskühler
Port_10082267_1 | SOURCEANDSINK | A - Druckleitung Gaskühler
Port_10082240_1 | SOURCEANDSINK | A - Druckleitung Gaskühler
Port_10082314_1 | SOURCEANDSINK | A - Druckleitung Gaskühler
Port_10082267_2 | SOURCEANDSINK | A - Druckleitung Gaskühler
Port_10082269_1 | SOURCEANDSINK | A - Druckleitung Gaskühler
Port_10082317_1 | SOURCEANDSINK | A - Druckleitung Gaskühler
Port_10082319_2 | SOURCEANDSINK | A - Druckleitung Gaskühler

# IfcDoor: Kühlraumdrehtür B12A:AKR Drehflügel 1000 (2)
In: EG_Produktion_FFB
Type - ParameterTakesPrecedence: no; Sizeable: no; Material: Edelstahl, gebürstet, <Unnamed>, RAL 9002, PVC, hart, Edelstahl
OverallHeight: 2175 mm; OverallWidth: 1150 mm; Classification: 334 Außenwandöffnungen (Uniformat)
Pset Bauphysik - OQ_Typ gem. Bauphysik: U = 0,20 W/(m²/K)
Pset_Tür - H_TÜ_Nassraum-Feuchtraum: yes; H_TÜ_EE_Tür-auf-Taster: no; H_TÜ_Fluchtweg: yes; H_TÜ_EE_autom-Türantrieb: no; H_TÜ_EE_Bewegungssensor: no; Beschreibung: Kühlraumdrehtür / Außentür; Ebene: EG_Produktion_FFB; Breite [mm]: 1000 mm; Höhe [mm]: 2100 mm; Funktion: Außen; Baugruppenkennzeichen: 334; Familie: Kühlraumdrehtür B12A; OQ_Typ gem. Bauphysik: U = 0,20 W/(m²/K); H_TÜ_DIN-rl: l
Pset_FM-Vivantes - Baujahr: 1; Prüfpflicht: yes; Prüfintervall: 1; Sammelobjekt: yes; rechn. Lebensdauer: 1; Familie und Typ: Kühlraumdrehtür B12A: AKR Drehflügel 1000; Klasse: 471; Bezeichnung: Kühlraumdrehtür als Außentür 1500; AKS: i.b.; Standort: i.b.; Hersteller: i.b.; Hersteller-Typ: i.b.; Seriennummer: i.b.; Gewährleistungsgeber: 1; Betriebsstatus: i.b.; technischer Zustand: i.b.; Eigentümer: i.b.; Bemerkung: i.b.
BaseQuantities - Height: 2100 mm; Width: 1000 mm; Area: 2.1 m2
Name (Kühlraumdrehtür B12A:AKR Drehflügel 1000:...) | H_TÜ_Türnummer
5147127 | T.01.00.049_3
5147223 | T.01.00.051_3

# IfcDoor: Kühlraumdrehtür D8 mit Fenster:Betriebsraum Drehflügel 1500, Kühlraumdrehtür D8 mit Fenster:Betriebsraum Drehflügel 1500:4933550
In: EG_Produktion_FFB
Type - OperationType: DOUBLE_SWING_LEFT; ParameterTakesPrecedence: no; Sizeable: no; Material: Edelstahl, gebürstet, <Unnamed>, RAL 9002, ARC_Glas, PVC, hart, Edelstahl
Type - Kühlraumdrehtür D8 mit Fenster:Betriebsraum Drehflügel 1500:4933550:1 - PanelOperation: DOUBLE_ACTING
OverallHeight: 2175 mm; OverallWidth: 1650 mm; Classification: 344 Innenwandöffnungen (Uniformat)
Pset Bauphysik - OQ_Typ gem. Bauphysik: -
Pset_Tür - Funktion: Innen; H_TÜ_Fluchtweg: no; H_TÜ_Nassraum-Feuchtraum: yes; H_TÜ_EE_Tür-auf-Taster: no; H_TÜ_EE_autom-Türantrieb: no; H_TÜ_EE_Bewegungssensor: no; Beschreibung: Betriebsraumdrehtür mit Fenster; Ebene: EG_Produktion_FFB; H_TÜ_Türnummer: T.01.00.F10_3; Breite [mm]: 1500 mm; Höhe [mm]: 2100 mm; Baugruppenkennzeichen: 344; Familie: Kühlraumdrehtür D8 mit Fenster; OQ_Typ gem. Bauphysik: -; H_TÜ_DIN-rl: r
Pset_FM-Vivantes - Baujahr: 1; Prüfpflicht: yes; Prüfintervall: 1; Sammelobjekt: yes; rechn. Lebensdauer: 1; Familie und Typ: Kühlraumdrehtür D8 mit Fenster: Betriebsraum Drehflügel 1500; Klasse: 471; Bezeichnung: Betriebsraumdrehtür mit Fenster 1500; AKS: i.b.; Standort: i.b.; Hersteller: i.b.; Hersteller-Typ: i.b.; Seriennummer: i.b.; Gewährleistungsgeber: 1; Betriebsstatus: i.b.; technischer Zustand: i.b.; Eigentümer: i.b.; Bemerkung: i.b.
BaseQuantities - Height: 2100 mm; Width: 1500 mm; Area: 3.15 m2

# IfcDoor: Kühlraumdrehtür D8 mit Fenster:KR Drehflügel 1200 (4)
In: EG_Produktion_FFB
Type - ParameterTakesPrecedence: no; Sizeable: no; Material: Edelstahl, gebürstet, <Unnamed>, RAL 9002, ARC_Glas, PVC, hart, Edelstahl
OverallHeight: 2175 mm; OverallWidth: 1350 mm; Classification: 344 Innenwandöffnungen (Uniformat)
Pset Bauphysik - OQ_Typ gem. Bauphysik: U = 0,30 W/(m²/K)
Pset_Tür - Funktion: Innen; H_TÜ_Nassraum-Feuchtraum: yes; H_TÜ_EE_Tür-auf-Taster: no; Beschreibung: Kühlraumdrehtür mit Fenster; Ebene: EG_Produktion_FFB; Breite [mm]: 1200 mm; Höhe [mm]: 2100 mm; Baugruppenkennzeichen: 344; Familie: Kühlraumdrehtür D8 mit Fenster; OQ_Typ gem. Bauphysik: U = 0,30 W/(m²/K); H_TÜ_DIN-rl: r; H_TÜ_EE_autom-Türantrieb: no; H_TÜ_EE_Bewegungssensor: no
Pset_FM-Vivantes - Baujahr: 1; Prüfpflicht: yes; Prüfintervall: 1; Sammelobjekt: yes; rechn. Lebensdauer: 1; Familie und Typ: Kühlraumdrehtür D8 mit Fenster: KR Drehflügel 1200; Klasse: 471; Bezeichnung: Kühlraumdrehtür mit Fenster 1200; AKS: i.b.; Standort: i.b.; Hersteller: i.b.; Hersteller-Typ: i.b.; Seriennummer: i.b.; Gewährleistungsgeber: 1; Betriebsstatus: i.b.; technischer Zustand: i.b.; Eigentümer: i.b.; Bemerkung: i.b.
BaseQuantities - Height: 2100 mm; Width: 1200 mm; Area: 2.52 m2
Name (Kühlraumdrehtür D8 mit Fenster:KR Drehflügel 1200:...) | H_TÜ_Fluchtweg | H_TÜ_Türnummer
4481677 | no | T.01.00.050.1_3
4482274 | yes | T.01.00.057_3
4489256 | no | T.01.00.052_1
4489310 | no | T.01.00.054_2

# IfcDoor: Kühlraumdrehtür D8 mit Fenster:KR Drehflügel 1500, Kühlraumdrehtür D8 mit Fenster:KR Drehflügel 1500:4489210
In: EG_Produktion_FFB
Type - OperationType: DOUBLE_SWING_LEFT; ParameterTakesPrecedence: no; Sizeable: no; Material: Edelstahl, gebürstet, <Unnamed>, RAL 9002, ARC_Glas, PVC, hart, Edelstahl
Type - Kühlraumdrehtür D8 mit Fenster:KR Drehflügel 1500:4489210:1 - PanelOperation: DOUBLE_ACTING
OverallHeight: 2175 mm; OverallWidth: 1650 mm; Classification: 344 Innenwandöffnungen (Uniformat)
Pset Bauphysik - OQ_Typ gem. Bauphysik: U = 0,30 W/(m²/K)
Pset_Tür - Funktion: Innen; H_TÜ_Fluchtweg: no; H_TÜ_Nassraum-Feuchtraum: yes; H_TÜ_EE_Tür-auf-Taster: no; H_TÜ_EE_autom-Türantrieb: no; H_TÜ_EE_Bewegungssensor: no; Beschreibung: Kühlraumdrehtür mit Fenster; Ebene: EG_Produktion_FFB; H_TÜ_Türnummer: T.01.00.F10_1; Breite [mm]: 1500 mm; Höhe [mm]: 2100 mm; Baugruppenkennzeichen: 344; Familie: Kühlraumdrehtür D8 mit Fenster; OQ_Typ gem. Bauphysik: U = 0,30 W/(m²/K); H_TÜ_DIN-rl: r
Pset_FM-Vivantes - Baujahr: 1; Prüfpflicht: yes; Prüfintervall: 1; Sammelobjekt: yes; rechn. Lebensdauer: 1; Familie und Typ: Kühlraumdrehtür D8 mit Fenster: KR Drehflügel 1500; Klasse: 471; Bezeichnung: Kühlraumdrehtür mit Fenster 1500; AKS: i.b.; Standort: i.b.; Hersteller: i.b.; Hersteller-Typ: i.b.; Seriennummer: i.b.; Gewährleistungsgeber: 1; Betriebsstatus: i.b.; technischer Zustand: i.b.; Eigentümer: i.b.; Bemerkung: i.b.
BaseQuantities - Height: 2100 mm; Width: 1500 mm; Area: 3.15 m2

# IfcDoor: Kühlraumdrehtür D8:KR Drehflügel 1000 (2)
In: EG_Produktion_FFB
Type - ParameterTakesPrecedence: no; Sizeable: no; Material: Edelstahl, gebürstet, <Unnamed>, RAL 9002, PVC, hart, Edelstahl
Classification: 344 Innenwandöffnungen (Uniformat)
Pset Bauphysik - OQ_Typ gem. Bauphysik: U = 0,30 W/(m²/K)
Pset_Tür - Funktion: Innen; H_TÜ_Nassraum-Feuchtraum: yes; H_TÜ_EE_Tür-auf-Taster: no; H_TÜ_Fluchtweg: yes; Beschreibung: Kühlraumdrehtür; Ebene: EG_Produktion_FFB; Breite [mm]: 1000 mm; Höhe [mm]: 2100 mm; Baugruppenkennzeichen: 344; Familie: Kühlraumdrehtür D8; OQ_Typ gem. Bauphysik: U = 0,30 W/(m²/K); H_TÜ_DIN-rl: l
Pset_FM-Vivantes - Baujahr: 1; Prüfpflicht: yes; Prüfintervall: 1; Sammelobjekt: yes; rechn. Lebensdauer: 1; Familie und Typ: Kühlraumdrehtür D8: KR Drehflügel 1000; Klasse: 471; Bezeichnung: Kühlraumdrehtür 1000; AKS: i.b.; Standort: i.b.; Hersteller: i.b.; Hersteller-Typ: i.b.; Seriennummer: i.b.; Gewährleistungsgeber: 1; Betriebsstatus: i.b.; technischer Zustand: i.b.; Eigentümer: i.b.; Bemerkung: i.b.
BaseQuantities - Height: 2100 mm; Width: 1000 mm; Area: 2.1 m2
Name (Kühlraumdrehtür D8:KR Drehflügel 1000:...) | OverallHeight (mm) | OverallWidth (mm) | H_TÜ_EE_autom-Türantrieb = H_TÜ_EE_Bewegungssensor | H_TÜ_Türnummer
5145265 | 2460 | 1220 | no | T.01.00.049_6
5193680 | 2175 | 1150 | yes | T.01.00.050_3

# IfcDoor: Kühlraumdrehtür D8:KR Drehflügel 1200, Kühlraumdrehtür D8:KR Drehflügel 1200:4843533
In: EG_Produktion_FFB
Type - ParameterTakesPrecedence: no; Sizeable: no; Material: Edelstahl, gebürstet, <Unnamed>, RAL 9002, PVC, hart, Edelstahl
OverallHeight: 2175 mm; OverallWidth: 1350 mm; Classification: 344 Innenwandöffnungen (Uniformat)
Pset Bauphysik - OQ_Typ gem. Bauphysik: U = 0,30 W/(m²/K)
Pset_Tür - Funktion: Innen; H_TÜ_Nassraum-Feuchtraum: yes; H_TÜ_EE_Tür-auf-Taster: no; H_TÜ_Fluchtweg: yes; H_TÜ_EE_autom-Türantrieb: no; H_TÜ_EE_Bewegungssensor: no; Beschreibung: Kühlraumdrehtür; Ebene: EG_Produktion_FFB; H_TÜ_Türnummer: T.01.00.F05_1; Breite [mm]: 1200 mm; Höhe [mm]: 2100 mm; Baugruppenkennzeichen: 344; Familie: Kühlraumdrehtür D8; OQ_Typ gem. Bauphysik: U = 0,30 W/(m²/K); H_TÜ_DIN-rl: r
Pset_FM-Vivantes - Baujahr: 1; Prüfpflicht: yes; Prüfintervall: 1; Sammelobjekt: yes; rechn. Lebensdauer: 1; Familie und Typ: Kühlraumdrehtür D8: KR Drehflügel 1200; Klasse: 471; Bezeichnung: Kühlraumdrehtür 1200; AKS: i.b.; Standort: i.b.; Hersteller: i.b.; Hersteller-Typ: i.b.; Seriennummer: i.b.; Gewährleistungsgeber: 1; Betriebsstatus: i.b.; technischer Zustand: i.b.; Eigentümer: i.b.; Bemerkung: i.b.
BaseQuantities - Height: 2100 mm; Width: 1200 mm; Area: 2.52 m2

# IfcDoor: Kühlraumschiebetür:KR Schiebetür 1200x2100, Kühlraumschiebetür:KR Schiebetür 1200x2100:4933706
In: EG_Produktion_FFB
Type - ParameterTakesPrecedence: no; Sizeable: no; Material: Kunststoff, undurchsichtig schwarz, Edelstahl, RAL 9002, PVC, hart
OverallHeight: 2120 mm; OverallWidth: 1240 mm; Classification: 344 Innenwandöffnungen (Uniformat)
Pset Bauphysik - OQ_Typ gem. Bauphysik: U = 0,30 W/(m²/K)
Pset_Tür - Funktion: Innen; H_TÜ_Fluchtweg: no; H_TÜ_Nassraum-Feuchtraum: yes; H_TÜ_EE_Tür-auf-Taster: no; H_TÜ_EE_autom-Türantrieb: no; H_TÜ_EE_Bewegungssensor: no; Beschreibung: Kühlraumschiebetür; Ebene: EG_Produktion_FFB; H_TÜ_Türnummer: T.01.00.F10_2; Breite [mm]: 1200 mm; Höhe [mm]: 2100 mm; Baugruppenkennzeichen: 344; Familie: Kühlraumschiebetür; OQ_Typ gem. Bauphysik: U = 0,30 W/(m²/K); H_TÜ_DIN-rl: l
Pset_FM-Vivantes - Baujahr: 1; Prüfpflicht: yes; Prüfintervall: 1; Sammelobjekt: yes; rechn. Lebensdauer: 1; Familie und Typ: Kühlraumschiebetür: KR Schiebetür 1200x2100; Klasse: 471; Bezeichnung: Kühlraumschiebetür 1200; AKS: i.b.; Standort: i.b.; Hersteller: i.b.; Hersteller-Typ: i.b.; Seriennummer: i.b.; Gewährleistungsgeber: 1; Betriebsstatus: i.b.; technischer Zustand: i.b.; Eigentümer: i.b.; Bemerkung: i.b.
BaseQuantities - Height: 2100 mm; Width: 1200 mm; Area: 2.52 m2

# IfcDoor: Kühlraumschiebetür:KR Schiebetür 1500x2100 (11)
In: EG_Produktion_FFB
Type - ParameterTakesPrecedence: no; Sizeable: no; Material: Kunststoff, undurchsichtig schwarz, Edelstahl, RAL 9002, PVC, hart
Classification: 344 Innenwandöffnungen (Uniformat)
Pset Bauphysik - OQ_Typ gem. Bauphysik: U = 0,30 W/(m²/K)
Pset_Tür - Beschreibung: Kühlraumschiebetür; Ebene: EG_Produktion_FFB; Breite [mm]: 1500 mm; Höhe [mm]: 2100 mm; Funktion: Innen; Baugruppenkennzeichen: 344; Familie: Kühlraumschiebetür; OQ_Typ gem. Bauphysik: U = 0,30 W/(m²/K); H_TÜ_EE_autom-Türantrieb: yes; H_TÜ_EE_Bewegungssensor: yes; H_TÜ_EE_Tür-auf-Taster: yes; H_TÜ_Fluchtweg: no; H_TÜ_Nassraum-Feuchtraum: yes
Pset_FM-Vivantes - Baujahr: 1; Prüfpflicht: yes; Prüfintervall: 1; Sammelobjekt: yes; rechn. Lebensdauer: 1; Familie und Typ: Kühlraumschiebetür: KR Schiebetür 1500x2100; Klasse: 471; Bezeichnung: Kühlraumschiebetür 1500; AKS: i.b.; Standort: i.b.; Hersteller: i.b.; Hersteller-Typ: i.b.; Seriennummer: i.b.; Gewährleistungsgeber: 1; Betriebsstatus: i.b.; technischer Zustand: i.b.; Eigentümer: i.b.; Bemerkung: i.b.
BaseQuantities - Height: 2100 mm; Width: 1500 mm; Area: 3.15 m2
Name (Kühlraumschiebetür:KR Schiebetür 1500x2100:...) | OverallHeight (mm) | OverallWidth (mm) | H_TÜ_Türnummer | H_TÜ_DIN-rl
4269601 | 2520 | 3434 | T.01.00.051_5 | l
4270014 | 2120 | 1540 | T.01.00.055.4_1 | r
4270104 | 2120 | 1540 | T.01.00.051.3_1 | r
4270653 | 2120 | 1540 | T.01.00.055_4 | r
4270819 | 2520 | 3434 | T.01.00.051_4 | l
4270945 | 2120 | 1540 | T.01.00.055_3 | l
4271085 | 2120 | 1540 | T.01.00.055_5 | r
4271211 | 2120 | 1540 | T.01.00.057_2 | l
4481837 | 2120 | 1540 | T.01.00.055_6 | r
4487657 | 2120 | 1540 | T.01.00.055.3_3 | r
4487733 | 2120 | 1540 | T.01.00.055.1_3 | r

# IfcDoor: Schnellauftor:Schnellauftor 2,0m (4)
In: EG_Produktion_FFB
Type - ParameterTakesPrecedence: no; Sizeable: no; Material: Fabric - Curtain - RiteHite - Blue, Metal - Aluminum - RiteHite - Powder Coat - Black
OverallHeight: 2100 mm; OverallWidth: 2000 mm; Classification: 344 Innenwandöffnungen (Uniformat)
Pset Bauphysik - OQ_Typ gem. Bauphysik: -
Pset_Tür - Funktion: Innen; H_TÜ_EE_autom-Türantrieb: yes; H_TÜ_EE_Bewegungssensor: yes; H_TÜ_Nassraum-Feuchtraum: yes; H_TÜ_EE_Tür-auf-Taster: no; Beschreibung: Schnellauftor; Ebene: EG_Produktion_FFB; Breite [mm]: 2000 mm; Höhe [mm]: 2100 mm; Baugruppenkennzeichen: 344; Familie: Schnellauftor; OQ_Typ gem. Bauphysik: -; H_TÜ_DIN-rl: -
Pset_FM-Vivantes - Baujahr: 1; Prüfpflicht: yes; Prüfintervall: 1; Sammelobjekt: yes; rechn. Lebensdauer: 1; Familie und Typ: Schnellauftor: Schnellauftor 2,0m; Klasse: 471; Bezeichnung: Schnellauftor 2000; AKS: i.b.; Standort: i.b.; Hersteller: i.b.; Hersteller-Typ: i.b.; Seriennummer: i.b.; Gewährleistungsgeber: 1; Betriebsstatus: i.b.; technischer Zustand: i.b.; Eigentümer: i.b.; Bemerkung: i.b.
BaseQuantities - Height: 2100 mm; Width: 2000 mm; Area: 4.2 m2
Name (Schnellauftor:Schnellauftor 2,0m:...) | H_TÜ_Fluchtweg | H_TÜ_Türnummer
4271770 | no | T.01.00.057_4
4271840 | no | T.01.00.050_4
4276960 | yes | T.01.00.055_8
4486701 | no | T.01.00.049_5

# IfcDoor: Schnellauftor:Schnellauftor 2,5m, Schnellauftor:Schnellauftor 2,5m:4271981
In: EG_Produktion_FFB
Type - ParameterTakesPrecedence: no; Sizeable: no; Material: Fabric - Curtain - RiteHite - Blue, Metal - Aluminum - RiteHite - Powder Coat - Black
OverallHeight: 3188.2 mm; OverallWidth: 3342.35 mm; Classification: 344 Innenwandöffnungen (Uniformat)
Pset Bauphysik - OQ_Typ gem. Bauphysik: -
Pset_Tür - Funktion: Innen; H_TÜ_EE_autom-Türantrieb: yes; H_TÜ_EE_Bewegungssensor: yes; H_TÜ_Nassraum-Feuchtraum: yes; H_TÜ_EE_Tür-auf-Taster: no; H_TÜ_Fluchtweg: yes; Beschreibung: Schnellauftor; Ebene: EG_Produktion_FFB; H_TÜ_Türnummer: T.01.00.049_7; Breite [mm]: 2500 mm; Höhe [mm]: 2100 mm; Baugruppenkennzeichen: 344; Familie: Schnellauftor; OQ_Typ gem. Bauphysik: -; H_TÜ_DIN-rl: -
Pset_FM-Vivantes - Baujahr: 1; Prüfpflicht: yes; Prüfintervall: 1; Sammelobjekt: yes; rechn. Lebensdauer: 1; Familie und Typ: Schnellauftor: Schnellauftor 2,5m; Klasse: 471; Bezeichnung: Schnellauftor 2500; AKS: i.b.; Standort: i.b.; Hersteller: i.b.; Hersteller-Typ: i.b.; Seriennummer: i.b.; Gewährleistungsgeber: 1; Betriebsstatus: i.b.; technischer Zustand: i.b.; Eigentümer: i.b.; Bemerkung: i.b.
BaseQuantities - Height: 2100 mm; Width: 2500 mm; Area: 5.25 m2

# IfcDoor: Schnellauftor:Schnellauftor Isoliert 2,0m (3)
In: EG_Produktion_FFB
Type - ParameterTakesPrecedence: no; Sizeable: no; Material: Fabric - Curtain - RiteHite - Blue, Metal - Aluminum - RiteHite - Powder Coat - Black
OverallHeight: 2100 mm; OverallWidth: 2000 mm; Classification: 344 Innenwandöffnungen (Uniformat)
Pset Bauphysik - OQ_Typ gem. Bauphysik: U = 1,52 W/(m²/K)
Pset_Tür - Funktion: Innen; H_TÜ_EE_autom-Türantrieb: yes; H_TÜ_EE_Bewegungssensor: yes; H_TÜ_Nassraum-Feuchtraum: yes; Beschreibung: Schnellauftor; Ebene: EG_Produktion_FFB; Breite [mm]: 2000 mm; Höhe [mm]: 2100 mm; Baugruppenkennzeichen: 344; Familie: Schnellauftor; OQ_Typ gem. Bauphysik: U = 1,52 W/(m²/K); H_TÜ_DIN-rl: -; H_TÜ_EE_Tür-auf-Taster: no
Pset_FM-Vivantes - Baujahr: 1; Prüfpflicht: yes; Prüfintervall: 1; Sammelobjekt: yes; rechn. Lebensdauer: 1; Familie und Typ: Schnellauftor: Schnellauftor Isoliert 2,0m; Klasse: 471; Bezeichnung: Schnellauftor isoliert 2000; AKS: i.b.; Standort: i.b.; Hersteller: i.b.; Hersteller-Typ: i.b.; Seriennummer: i.b.; Gewährleistungsgeber: 1; Betriebsstatus: i.b.; technischer Zustand: i.b.; Eigentümer: i.b.; Bemerkung: i.b.
BaseQuantities - Height: 2100 mm; Width: 2000 mm; Area: 4.2 m2
Name (Schnellauftor:Schnellauftor Isoliert 2,0m:...) | H_TÜ_Türnummer | H_TÜ_Fluchtweg
4271632 | T.01.00.050_1 | yes
4271696 | T.01.00.042.2_1 | no
4936017 | T.01.00.050_2 | no

# IfcDoor: Tiefkühlraumschiebetür:TKR Schiebetür 1500x2100 (4)
In: EG_Produktion_FFB
Type - ParameterTakesPrecedence: no; Sizeable: no; Material: Kunststoff, undurchsichtig schwarz, Edelstahl, RAL 9002, PVC, hart
OverallHeight: 2370 mm; OverallWidth: 1540 mm; Classification: 344 Innenwandöffnungen (Uniformat)
Pset Bauphysik - OQ_Typ gem. Bauphysik: U = 0,20 W/(m²/K)
Pset_Tür - Funktion: Innen; H_TÜ_EE_autom-Türantrieb: yes; H_TÜ_EE_Bewegungssensor: yes; H_TÜ_EE_Tür-auf-Taster: yes; H_TÜ_Fluchtweg: no; H_TÜ_Nassraum-Feuchtraum: yes; Beschreibung: Tiefkühlraumschiebetür; Ebene: EG_Produktion_FFB; Breite [mm]: 1500 mm; Höhe [mm]: 2100 mm; Baugruppenkennzeichen: 344; Familie: Tiefkühlraumschiebetür; OQ_Typ gem. Bauphysik: U = 0,20 W/(m²/K)
Pset_FM-Vivantes - Baujahr: 1; Prüfpflicht: yes; Prüfintervall: 1; Sammelobjekt: yes; rechn. Lebensdauer: 1; Familie und Typ: Tiefkühlraumschiebetür: TKR Schiebetür 1500x2100; Klasse: 471; Bezeichnung: Tiefkühlraumschiebetür 1500; AKS: i.b.; Standort: i.b.; Hersteller: i.b.; Hersteller-Typ: i.b.; Seriennummer: i.b.; Gewährleistungsgeber: 1; Betriebsstatus: i.b.; technischer Zustand: i.b.; Eigentümer: i.b.; Bemerkung: i.b.
BaseQuantities - Height: 2100 mm; Width: 1500 mm; Area: 3.15 m2
Name (Tiefkühlraumschiebetür:TKR Schiebetür 1500x2100:...) | H_TÜ_Türnummer | H_TÜ_DIN-rl
4269685 | T.01.00.051.2_1 | r
4269725 | T.01.00.051.4_1 | r
4269771 | T.01.00.055.5_1 | r
4482146 | T.01.00.055_7 | l

# IfcEnergyConversionDevice: Kältetechnik_Verdampfer:Verdampfer A Klimakühlung (13)
In: EG_Produktion_FFB
Type - Material: <Unnamed>
Pset_FM-Vivantes - Baujahr: 1; Prüfpflicht: yes; Prüfintervall: 1; Sammelobjekt: yes; rechn. Lebensdauer: 1; fahrbar: no; Familie und Typ: Kältetechnik_Verdampfer: Verdampfer A Klimakühlung; Klasse: 471; Bezeichnung: Verdampfer A Klimakühlung; AKS: i.b.; Standort: i.b.; Hersteller: i.b.; Hersteller-Typ: i.b.; Seriennummer: i.b.; Gewährleistungsgeber: 1; Betriebsstatus: i.b.; technischer Zustand: i.b.; Eigentümer: i.b.; Bemerkung: i.b.
Name (Kältetechnik_Verdampfer:Verdampfer A Klimakühlung:...)
5143160
5143203
5143227
5143228
5143268
5143444
5143575
5143665
5143673
5144117
5144118
5144119
5144147

# IfcEnergyConversionDevice: Kältetechnik_Verdampfer:Verdampfer A Normalkühlung (23)
In: EG_Produktion_FFB
Type - Material: <Unnamed>
Pset_FM-Vivantes - Baujahr: 1; Prüfpflicht: yes; Prüfintervall: 1; Sammelobjekt: yes; rechn. Lebensdauer: 1; fahrbar: no; Familie und Typ: Kältetechnik_Verdampfer: Verdampfer A Normalkühlung; Klasse: 471; Bezeichnung: Verdampfer A Normalkühlung; AKS: i.b.; Standort: i.b.; Hersteller: i.b.; Hersteller-Typ: i.b.; Seriennummer: i.b.; Gewährleistungsgeber: 1; Betriebsstatus: i.b.; technischer Zustand: i.b.; Eigentümer: i.b.; Bemerkung: i.b.
Name (Kältetechnik_Verdampfer:Verdampfer A Normalkühlung:...)
5125915 | Group: K_Rücklauf 1; K_Vorlauf 2
5139542
5140140
5140294
5140409
5140547
5140553
5140563
5140571
5140577
5140982
5141345
5141511
5141585
5141593
5141601
5141922
5141998
5142081
5142082
5142135
5142507
5142508

# IfcEnergyConversionDevice: Kältetechnik_Verdampfer:Verdampfer A Tiefkühlung (5)
In: EG_Produktion_FFB
Type - Material: <Unnamed>
Pset_FM-Vivantes - Baujahr: 1; Prüfpflicht: yes; Prüfintervall: 1; Sammelobjekt: yes; rechn. Lebensdauer: 1; fahrbar: no; Familie und Typ: Kältetechnik_Verdampfer: Verdampfer A Tiefkühlung; Klasse: 471; Bezeichnung: Verdampfer A Tiefkühlung; AKS: i.b.; Standort: i.b.; Hersteller: i.b.; Hersteller-Typ: i.b.; Seriennummer: i.b.; Gewährleistungsgeber: 1; Betriebsstatus: i.b.; technischer Zustand: i.b.; Eigentümer: i.b.; Bemerkung: i.b.
Name (Kältetechnik_Verdampfer:Verdampfer A Tiefkühlung:...)
5140974
5141258
5141259
5141310
5141311

# IfcEnergyConversionDevice: Kältetechnik_Verdampfer:Verdampfer B Klimakühlung (13)
In: EG_Produktion_FFB
Type - Material: <Unnamed>
Pset_FM-Vivantes - Baujahr: 1; Prüfpflicht: yes; Prüfintervall: 1; Sammelobjekt: yes; rechn. Lebensdauer: 1; fahrbar: no; Familie und Typ: Kältetechnik_Verdampfer: Verdampfer B Klimakühlung; Klasse: 471; Bezeichnung: Verdampfer B Klimakühlung; AKS: i.b.; Standort: i.b.; Hersteller: i.b.; Hersteller-Typ: i.b.; Seriennummer: i.b.; Gewährleistungsgeber: 1; Betriebsstatus: i.b.; technischer Zustand: i.b.; Eigentümer: i.b.; Bemerkung: i.b.
Name (Kältetechnik_Verdampfer:Verdampfer B Klimakühlung:...)
5142534
5142905
5142951
5143086
5143334
5143445
5143817
5143825
5143833
5144114
5144115
5144116
5144148

# IfcEnergyConversionDevice: Kältetechnik_Verdampfer:Verdampfer B Normalkühlung (23)
In: EG_Produktion_FFB
Type - Material: <Unnamed>
Pset_FM-Vivantes - Baujahr: 1; Prüfpflicht: yes; Prüfintervall: 1; Sammelobjekt: yes; rechn. Lebensdauer: 1; fahrbar: no; Familie und Typ: Kältetechnik_Verdampfer: Verdampfer B Normalkühlung; Klasse: 471; Bezeichnung: Verdampfer B Normalkühlung; AKS: i.b.; Standort: i.b.; Hersteller: i.b.; Hersteller-Typ: i.b.; Seriennummer: i.b.; Gewährleistungsgeber: 1; Betriebsstatus: i.b.; technischer Zustand: i.b.; Eigentümer: i.b.; Bemerkung: i.b.
Name (Kältetechnik_Verdampfer:Verdampfer B Normalkühlung:...)
5139601
5139609
5139617
5140737
5140738
5140739
5140740
5140776
5140777
5140803
5141008
5141451
5141537
5141887
5141888
5141889
5142062
5142063
5142105
5142106
5142229
5142267
5142391

# IfcEnergyConversionDevice: Kältetechnik_Verdampfer:Verdampfer B Tiefkühlung (5)
In: EG_Produktion_FFB
Type - Material: <Unnamed>
Pset_FM-Vivantes - Baujahr: 1; Prüfpflicht: yes; Prüfintervall: 1; Sammelobjekt: yes; rechn. Lebensdauer: 1; fahrbar: no; Familie und Typ: Kältetechnik_Verdampfer: Verdampfer B Tiefkühlung; Klasse: 471; Bezeichnung: Verdampfer B Tiefkühlung; AKS: i.b.; Standort: i.b.; Hersteller: i.b.; Hersteller-Typ: i.b.; Seriennummer: i.b.; Gewährleistungsgeber: 1; Betriebsstatus: i.b.; technischer Zustand: i.b.; Eigentümer: i.b.; Bemerkung: i.b.
Name (Kältetechnik_Verdampfer:Verdampfer B Tiefkühlung:...)
5140856
5141046
5141189
5141293
5141294

# IfcEnergyConversionDevice: Luftschleieranlage:Luftschleieranlage (5)
In: EG_Produktion_FFB
Type - Material: <Unnamed>
Pset_FM-Vivantes - Baujahr: 1; Prüfpflicht: yes; Prüfintervall: 1; Sammelobjekt: yes; rechn. Lebensdauer: 1; Familie und Typ: Luftschleieranlage: Luftschleieranlage; fahrbar: no; Klasse: 471; Bezeichnung: Luftschleieranlage; AKS: i.b.; Standort: i.b.; Hersteller: i.b.; Hersteller-Typ: i.b.; Seriennummer: i.b.; Gewährleistungsgeber: 1; Betriebsstatus: i.b.; technischer Zustand: i.b.; Eigentümer: i.b.; Bemerkung: i.b.
Name (Luftschleieranlage:Luftschleieranlage:...)
4995352
4996613
4998122
4998209
5007093

# IfcFlowFitting: Bogen Kupfer:Allgemein (529)
Type - Material: <Unnamed>
Pset_FM-Vivantes - Baujahr: 1; Prüfpflicht: yes; Prüfintervall: 1; Sammelobjekt: yes; rechn. Lebensdauer: 1; Familie und Typ: Bogen Kupfer: Allgemein; Klasse: 471; Bezeichnung: Bogen - allgemein: Standard; AKS: i.b.; Standort: i.b.; Hersteller: i.b.; Hersteller-Typ: i.b.; Seriennummer: i.b.; Gewährleistungsgeber: 1; Betriebsstatus: i.b.; technischer Zustand: i.b.; Eigentümer: i.b.; Bemerkung: i.b.
Name (Bogen Kupfer:Allgemein:...) | In | Group
8579201 | EG_Produktion_FFB | A - Kondensatleitung Gaskühler
8579219 | EG_Produktion_FFB | A - Kondensatleitung Gaskühler
8579222 | EG_Produktion_FFB | A - Kondensatleitung Gaskühler
8579228 | EG_Produktion_FFB | A - Kondensatleitung Gaskühler
8579231 | EG_Produktion_FFB | A - Kondensatleitung Gaskühler
8579261 | EG_Produktion_FFB | A - Druckleitung Gaskühler
8579264 | EG_Produktion_FFB | A - Druckleitung Gaskühler
8579298 | Wartung_FFB | B - Kondensatleitung Gaskühler
8579301 | Wartung_FFB | B - Druckleitung Gaskühler
8579306 | Wartung_FFB | B - Kondensatleitung Gaskühler
8579310 | Wartung_FFB | B - Kondensatleitung Gaskühler
8579315 | Wartung_FFB | B - Druckleitung Gaskühler
8579328 | Wartung_FFB | B - Kondensatleitung Gaskühler
8579331 | Wartung_FFB | B - Druckleitung Gaskühler
8579347 | EG_Produktion_FFB | B - Kondensatleitung Gaskühler
8579366 | EG_Produktion_FFB | B - Druckleitung Gaskühler
8579521 | EG_Produktion_FFB | A - FL-Str.01_NK-KK-TK
8579539 | EG_Produktion_FFB | B - FL-Str.01_NK-KK-TK
8579911 | EG_Technik_FFB | A - FL-Str.03_NK-KK-TK
8579918 | EG_Technik_FFB | B - FL-Str.03_NK-KK-TK
8579931 | EG_Technik_FFB | B - FL-Str.03_NK-KK-TK
8579934 | EG_Produktion_FFB | B - FL-Str.03_NK-KK-TK
8579937 | EG_Technik_FFB | A - FL-Str.03_NK-KK-TK
8580535 | Wartung_FFB | B - Druckleitung Gaskühler
8580556 | EG_Produktion_FFB | A - Druckleitung Gaskühler
8580561 | EG_Produktion_FFB | A - Druckleitung Gaskühler
8580668 | EG_Produktion_FFB | B - Kondensatleitung Gaskühler
8580673 | EG_Produktion_FFB | B - Kondensatleitung Gaskühler
8582994 | EG_Produktion_FFB | A - SL_KK
8586461 | EG_Produktion_FFB | B - SL_KK
8588616 | EG_Technik_FFB | B - SL_NK-Str.02
8588627 | EG_Technik_FFB | A - SL_NK-Str.02
8588643 | EG_Technik_FFB | B - SL_NK-Str.02
8588653 | EG_Technik_FFB | A - SL_NK-Str.02
8593114 | EG_Produktion_FFB | B - SL_TK
8593478 | EG_Produktion_FFB | A - FL-Str.02_NK-KK-TK
8593483 | EG_Produktion_FFB | A - SL_TK
8593493 | EG_Produktion_FFB | B - FL-Str.02_NK-KK-TK
8593503 | EG_Produktion_FFB | B - SL_NK-Str.01
8593508 | EG_Produktion_FFB | B - SL_NK-Str.01
8593513 | EG_Produktion_FFB | B - FL-Str.02_NK-KK-TK
8593518 | EG_Produktion_FFB | B - FL-Str.02_NK-KK-TK
8593521 | EG_Produktion_FFB | B - SL_TK
8593526 | EG_Produktion_FFB | B - SL_TK
8593531 | EG_Produktion_FFB | A - SL_TK
8593539 | EG_Produktion_FFB | A - FL-Str.02_NK-KK-TK
8593544 | EG_Produktion_FFB | A - FL-Str.02_NK-KK-TK
8593547 | EG_Produktion_FFB | A - SL_NK-Str.01
8593552 | EG_Produktion_FFB | A - SL_NK-Str.01
8593915 | EG_Produktion_FFB | B - SL_NK-Str.01
8594525 | EG_Produktion_FFB | A - SL_NK-Str.01
8597248 | EG_Produktion_FFB | A - Druckleitung Gaskühler
8597337 | EG_Produktion_FFB | A - Druckleitung Gaskühler
8597342 | EG_Produktion_FFB | A - Druckleitung Gaskühler
8597350 | EG_Produktion_FFB | A - Kondensatleitung Gaskühler
8597353 | EG_Produktion_FFB | A - Kondensatleitung Gaskühler
8599460 | EG_Produktion_FFB | B - SL_NK-Str.02
8599680 | EG_Produktion_FFB | B - SL_NK-Str.02
8599793 | EG_Produktion_FFB | A - FL-Str.03_NK-KK-TK
8599949 | EG_Produktion_FFB | A - SL_NK-Str.02
8601363 | EG_Produktion_FFB | A - FL-Str.03_NK-KK-TK
8602807 | EG_Produktion_FFB | B - FL-Str.02_NK-KK-TK
8603874 | EG_Produktion_FFB | A - FL-Str.02_NK-KK-TK
8603936 | EG_Produktion_FFB | B - FL-Str.02_NK-KK-TK
8603959 | EG_Produktion_FFB | B - SL_KK
8603968 | EG_Produktion_FFB | B - SL_KK
8603973 | EG_Produktion_FFB | B - SL_KK
8603996 | EG_Produktion_FFB | B - FL-Str.01_NK-KK-TK
8604005 | EG_Produktion_FFB | B - FL-Str.01_NK-KK-TK
8604010 | EG_Produktion_FFB | B - FL-Str.01_NK-KK-TK
8604033 | EG_Produktion_FFB | A - SL_KK
8604042 | EG_Produktion_FFB | A - SL_KK
8604047 | EG_Produktion_FFB | A - SL_KK
8604070 | EG_Produktion_FFB | A - FL-Str.01_NK-KK-TK
8604079 | EG_Produktion_FFB | A - FL-Str.01_NK-KK-TK
8604084 | EG_Produktion_FFB | A - FL-Str.01_NK-KK-TK
8604268 | EG_Produktion_FFB | A - FL-Str.01_NK-KK-TK
8604295 | EG_Produktion_FFB | A - SL_KK
8604647 | EG_Produktion_FFB | B - FL-Str.02_NK-KK-TK
8604825 | EG_Produktion_FFB | A - FL-Str.01_NK-KK-TK
8604955 | EG_Produktion_FFB | A - SL_NK-Str.01
8605028 | EG_Produktion_FFB | B - FL-Str.01_NK-KK-TK
8605081 | EG_Produktion_FFB | B - SL_NK-Str.01
8605151 | EG_Produktion_FFB | A - FL-Str.02_NK-KK-TK
8605362 | EG_Produktion_FFB | B - FL-Str.01_NK-KK-TK
8605394 | EG_Produktion_FFB | B - SL_KK
8605836 | EG_Produktion_FFB | B - SL_KK
8605863 | EG_Produktion_FFB | B - FL-Str.01_NK-KK-TK
8605917 | EG_Produktion_FFB | B - FL-Str.01_NK-KK-TK
8606108 | EG_Produktion_FFB | B - FL-Str.01_NK-KK-TK
8606241 | EG_Produktion_FFB | B - SL_KK
8606268 | EG_Produktion_FFB | B - FL-Str.01_NK-KK-TK
8607254 | EG_Produktion_FFB | B - FL-Str.03_NK-KK-TK
8607298 | EG_Produktion_FFB | B - SL_NK-Str.02
8607309 | EG_Produktion_FFB | B - SL_NK-Str.02
8607369 | EG_Produktion_FFB | B - FL-Str.03_NK-KK-TK
8607627 | EG_Produktion_FFB | A - SL_NK-Str.02
8607684 | EG_Produktion_FFB | A - FL-Str.03_NK-KK-TK
8607831 | EG_Produktion_FFB | A - SL_NK-Str.02
8607858 | EG_Produktion_FFB | A - FL-Str.03_NK-KK-TK
8607885 | EG_Produktion_FFB | B - SL_NK-Str.02
8607912 | EG_Produktion_FFB | B - FL-Str.03_NK-KK-TK
8608065 | EG_Produktion_FFB | B - FL-Str.03_NK-KK-TK
8608092 | EG_Produktion_FFB | B - SL_NK-Str.02
8608119 | EG_Produktion_FFB | A - SL_NK-Str.02
8608146 | EG_Produktion_FFB | A - FL-Str.03_NK-KK-TK
8608233 | EG_Produktion_FFB | B - SL_NK-Str.02
8608344 | EG_Produktion_FFB | A - SL_NK-Str.02
8608347 | EG_Produktion_FFB | A - SL_NK-Str.02
8608410 | EG_Produktion_FFB | A - SL_NK-Str.02
8608473 | EG_Produktion_FFB | A - SL_NK-Str.02
8608476 | EG_Produktion_FFB | A - SL_NK-Str.02
8608668 | EG_Produktion_FFB | A - FL-Str.03_NK-KK-TK
8608671 | EG_Produktion_FFB | A - FL-Str.03_NK-KK-TK
8609159 | EG_Produktion_FFB | A - SL_NK-Str.01
8609162 | EG_Produktion_FFB | A - SL_NK-Str.01
8609194 | EG_Produktion_FFB | A - FL-Str.02_NK-KK-TK
8609450 | EG_Produktion_FFB | B - FL-Str.02_NK-KK-TK
8609735 | EG_Produktion_FFB | B - FL-Str.02_NK-KK-TK
8609768 | EG_Produktion_FFB | B - SL_TK
8609859 | EG_Produktion_FFB | A - SL_TK
8609870 | EG_Produktion_FFB | A - SL_TK
8609943 | EG_Produktion_FFB | A - FL-Str.02_NK-KK-TK
8610105 | EG_Produktion_FFB | B - SL_TK
8610116 | EG_Produktion_FFB | B - SL_TK
8610195 | EG_Produktion_FFB | B - FL-Str.02_NK-KK-TK
8610339 | EG_Produktion_FFB | A - SL_NK-Str.01
8610375 | EG_Produktion_FFB | A - FL-Str.02_NK-KK-TK
8610408 | EG_Produktion_FFB | A - SL_TK
8610546 | EG_Produktion_FFB | B - FL-Str.02_NK-KK-TK
8610573 | EG_Produktion_FFB | B - SL_NK-Str.01
8611056 | EG_Produktion_FFB | A - SL_NK-Str.01
8611189 | EG_Produktion_FFB | A - FL-Str.02_NK-KK-TK
8611226 | EG_Produktion_FFB | A - SL_NK-Str.01
8611322 | EG_Produktion_FFB | A - SL_NK-Str.01
8611453 | EG_Produktion_FFB | B - SL_NK-Str.01
8611527 | EG_Produktion_FFB | B - SL_NK-Str.01
8611577 | EG_Produktion_FFB | B - SL_KK
8611641 | EG_Produktion_FFB | A - SL_KK
8611868 | EG_Produktion_FFB | A - FL-Str.01_NK-KK-TK
8611879 | EG_Produktion_FFB | A - FL-Str.01_NK-KK-TK
8611933 | EG_Produktion_FFB | B - FL-Str.01_NK-KK-TK
8611993 | EG_Produktion_FFB | B - FL-Str.01_NK-KK-TK
8613344 | EG_Produktion_FFB | B - SL_NK-Str.01
8613398 | EG_Produktion_FFB | A - SL_NK-Str.01
8614885 | EG_Produktion_FFB | B - FL-Str.02_NK-KK-TK
8614898 | EG_Produktion_FFB | B - FL-Str.02_NK-KK-TK
8614943 | EG_Produktion_FFB | B - SL_NK-Str.01
8614991 | EG_Produktion_FFB | A - SL_NK-Str.01
8615039 | EG_Produktion_FFB | A - FL-Str.02_NK-KK-TK
8615066 | EG_Produktion_FFB | A - SL_NK-Str.01
8615071 | EG_Produktion_FFB | A - SL_NK-Str.01
8615094 | EG_Produktion_FFB | A - FL-Str.02_NK-KK-TK
8615099 | EG_Produktion_FFB | A - FL-Str.02_NK-KK-TK
8615108 | EG_Produktion_FFB | B - SL_NK-Str.01
8615111 | EG_Produktion_FFB | B - SL_NK-Str.01
8615116 | EG_Produktion_FFB | B - FL-Str.02_NK-KK-TK
8615621 | EG_Produktion_FFB | A - SL_TK
8616141 | EG_Produktion_FFB | A - FL-Str.02_NK-KK-TK
8616207 | EG_Produktion_FFB | A - SL_KK
8616849 | EG_Produktion_FFB | B - SL_KK
8617827 | EG_Produktion_FFB | A - SL_KK
8617835 | EG_Produktion_FFB | A - FL-Str.01_NK-KK-TK
8617877 | EG_Produktion_FFB | A - FL-Str.01_NK-KK-TK
8617880 | EG_Produktion_FFB | A - FL-Str.01_NK-KK-TK
8617913 | EG_Produktion_FFB | A - SL_KK
8617916 | EG_Produktion_FFB | A - SL_KK
8618031 | EG_Produktion_FFB | A - FL-Str.01_NK-KK-TK
8618034 | EG_Produktion_FFB | A - FL-Str.01_NK-KK-TK
8618078 | EG_Produktion_FFB | A - SL_NK-Str.01
8618081 | EG_Produktion_FFB | A - SL_NK-Str.01
8618212 | EG_Produktion_FFB | B - SL_NK-Str.01
8618215 | EG_Produktion_FFB | B - SL_NK-Str.01
8618256 | EG_Produktion_FFB | B - FL-Str.01_NK-KK-TK
8618259 | EG_Produktion_FFB | B - FL-Str.01_NK-KK-TK
8618690 | EG_Produktion_FFB | B - FL-Str.01_NK-KK-TK
8618696 | EG_Produktion_FFB | B - FL-Str.01_NK-KK-TK
8618699 | EG_Produktion_FFB | B - FL-Str.01_NK-KK-TK
8618707 | EG_Produktion_FFB | B - SL_KK
8618712 | EG_Produktion_FFB | B - SL_KK
8618715 | EG_Produktion_FFB | B - SL_KK
8618804 | EG_Produktion_FFB | B - SL_KK
8618807 | EG_Produktion_FFB | B - FL-Str.01_NK-KK-TK
8619064 | EG_Produktion_FFB | B - FL-Str.01_NK-KK-TK
8619068 | EG_Produktion_FFB | B - FL-Str.01_NK-KK-TK
8619094 | EG_Produktion_FFB | B - SL_KK
8619098 | EG_Produktion_FFB | B - SL_KK
8619275 | EG_Produktion_FFB | A - FL-Str.01_NK-KK-TK
8619284 | EG_Produktion_FFB | A - FL-Str.01_NK-KK-TK
8619289 | EG_Produktion_FFB | A - FL-Str.01_NK-KK-TK
8619313 | EG_Produktion_FFB | A - SL_KK
8619322 | EG_Produktion_FFB | A - SL_KK
8619327 | EG_Produktion_FFB | A - SL_KK
8619381 | EG_Produktion_FFB | B - FL-Str.01_NK-KK-TK
8619390 | EG_Produktion_FFB | B - FL-Str.01_NK-KK-TK
8619395 | EG_Produktion_FFB | B - FL-Str.01_NK-KK-TK
8619418 | EG_Produktion_FFB | B - SL_KK
8619427 | EG_Produktion_FFB | B - SL_KK
8619432 | EG_Produktion_FFB | B - SL_KK
8619521 | EG_Produktion_FFB | A - FL-Str.01_NK-KK-TK
8619525 | EG_Produktion_FFB | A - FL-Str.01_NK-KK-TK
8619551 | EG_Produktion_FFB | A - SL_KK
8619555 | EG_Produktion_FFB | A - SL_KK
8619661 | EG_Produktion_FFB | B - FL-Str.01_NK-KK-TK
8619665 | EG_Produktion_FFB | B - FL-Str.01_NK-KK-TK
8619711 | EG_Produktion_FFB | B - SL_KK
8619715 | EG_Produktion_FFB | B - SL_KK
8619771 | EG_Produktion_FFB | A - FL-Str.01_NK-KK-TK
8619780 | EG_Produktion_FFB | A - FL-Str.01_NK-KK-TK
8619785 | EG_Produktion_FFB | A - FL-Str.01_NK-KK-TK
8619809 | EG_Produktion_FFB | A - SL_KK
8619818 | EG_Produktion_FFB | A - SL_KK
8619823 | EG_Produktion_FFB | A - SL_KK
8619890 | EG_Produktion_FFB | B - SL_KK
8619894 | EG_Produktion_FFB | B - SL_KK
8619921 | EG_Produktion_FFB | B - FL-Str.01_NK-KK-TK
8619925 | EG_Produktion_FFB | B - FL-Str.01_NK-KK-TK
8620088 | EG_Produktion_FFB | B - SL_KK
8620097 | EG_Produktion_FFB | B - SL_KK
8620102 | EG_Produktion_FFB | B - SL_KK
8620141 | EG_Produktion_FFB | B - FL-Str.01_NK-KK-TK
8620150 | EG_Produktion_FFB | B - FL-Str.01_NK-KK-TK
8620155 | EG_Produktion_FFB | B - FL-Str.01_NK-KK-TK
8620226 | EG_Produktion_FFB | A - SL_KK
8620235 | EG_Produktion_FFB | A - SL_KK
8620240 | EG_Produktion_FFB | A - SL_KK
8620264 | EG_Produktion_FFB | A - FL-Str.01_NK-KK-TK
8620273 | EG_Produktion_FFB | A - FL-Str.01_NK-KK-TK
8620278 | EG_Produktion_FFB | A - FL-Str.01_NK-KK-TK
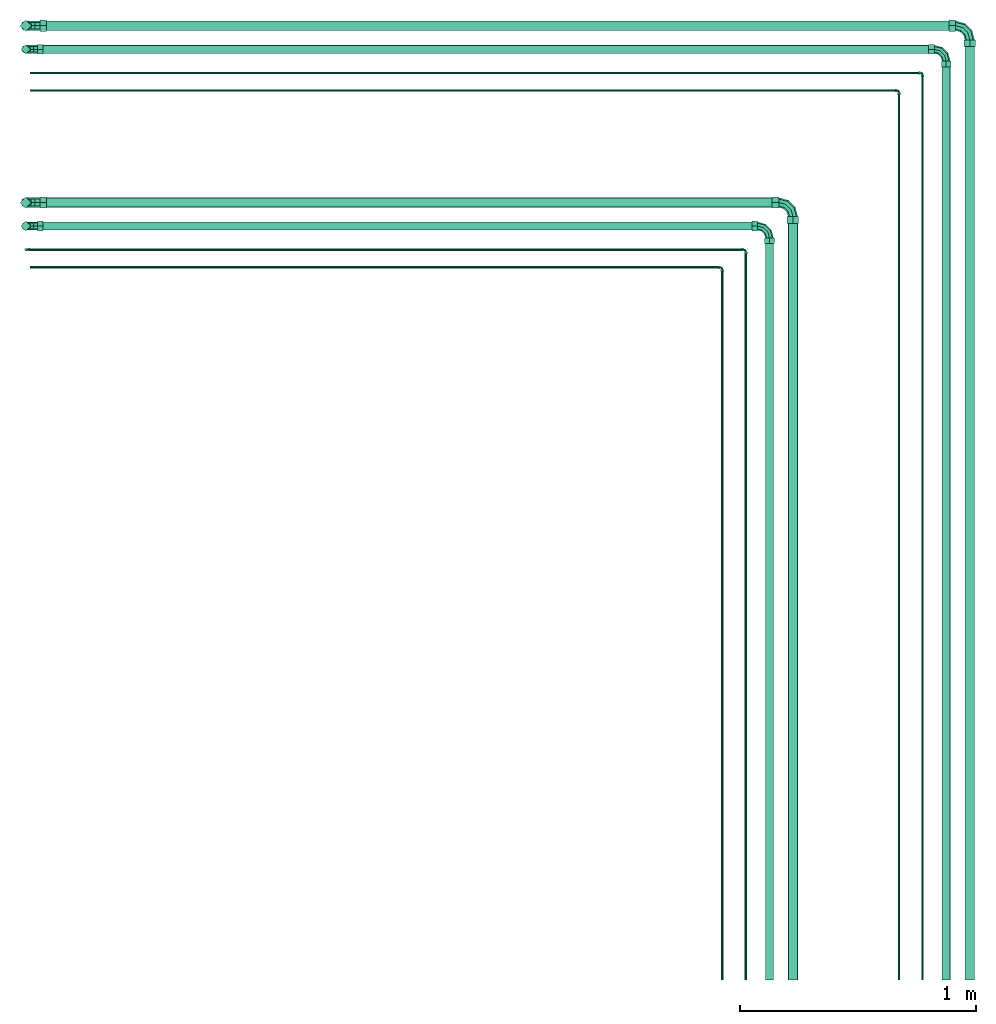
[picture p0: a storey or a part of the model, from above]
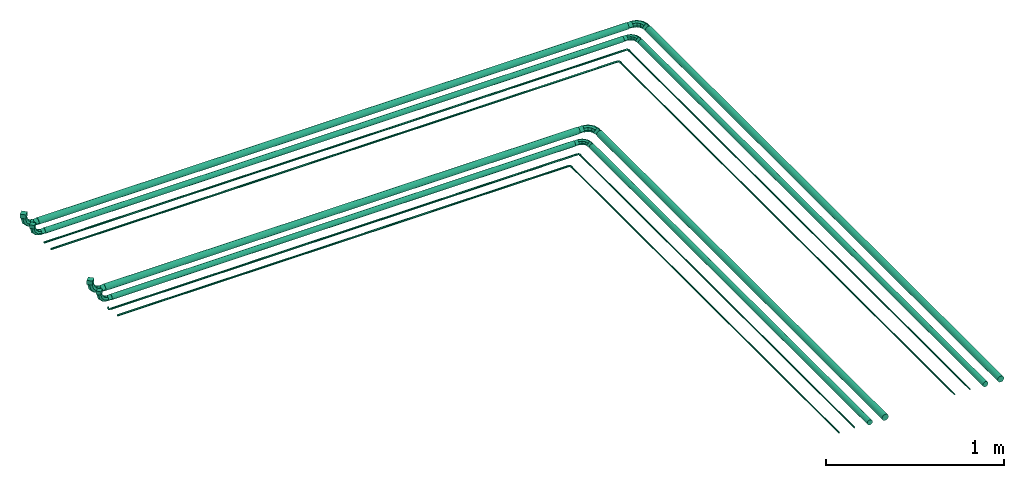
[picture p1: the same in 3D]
Properties of the parts of a building model (IFC2X3), part 6 of 7

# IfcFlowFitting: Bogen Kupfer:Allgemein (529)
Name (Bogen Kupfer:Allgemein:...) | In | Group
8620365 | EG_Produktion_FFB | B - FL-Str.01_NK-KK-TK
8620374 | EG_Produktion_FFB | B - FL-Str.01_NK-KK-TK
8620377 | EG_Produktion_FFB | B - FL-Str.01_NK-KK-TK
8620401 | EG_Produktion_FFB | B - SL_KK
8620410 | EG_Produktion_FFB | B - SL_KK
8620413 | EG_Produktion_FFB | B - SL_KK
8620518 | EG_Produktion_FFB | A - SL_KK
8620523 | EG_Produktion_FFB | A - SL_KK
8620548 | EG_Produktion_FFB | A - FL-Str.01_NK-KK-TK
8620557 | EG_Produktion_FFB | A - FL-Str.01_NK-KK-TK
8620562 | EG_Produktion_FFB | A - FL-Str.01_NK-KK-TK
8620706 | EG_Produktion_FFB | A - SL_KK
8620717 | EG_Produktion_FFB | A - SL_KK
8620742 | EG_Produktion_FFB | A - FL-Str.01_NK-KK-TK
8620753 | EG_Produktion_FFB | A - FL-Str.01_NK-KK-TK
8620900 | EG_Produktion_FFB | A - FL-Str.01_NK-KK-TK
8620911 | EG_Produktion_FFB | A - FL-Str.01_NK-KK-TK
8620935 | EG_Produktion_FFB | A - SL_KK
8620946 | EG_Produktion_FFB | A - SL_KK
8621123 | EG_Produktion_FFB | B - SL_KK
8621143 | EG_Produktion_FFB | B - SL_KK
8621154 | EG_Produktion_FFB | B - SL_KK
8621157 | EG_Produktion_FFB | B - SL_KK
8621181 | EG_Produktion_FFB | B - FL-Str.01_NK-KK-TK
8621192 | EG_Produktion_FFB | B - FL-Str.01_NK-KK-TK
8621195 | EG_Produktion_FFB | B - FL-Str.01_NK-KK-TK
8621609 | EG_Produktion_FFB | B - SL_NK-Str.02
8621697 | EG_Produktion_FFB | B - FL-Str.03_NK-KK-TK
8621702 | EG_Produktion_FFB | B - FL-Str.03_NK-KK-TK
8621793 | EG_Produktion_FFB | B - FL-Str.03_NK-KK-TK
8621839 | EG_Produktion_FFB | B - SL_NK-Str.02
8621934 | EG_Produktion_FFB | B - FL-Str.03_NK-KK-TK
8621941 | EG_Produktion_FFB | B - FL-Str.03_NK-KK-TK
8621980 | EG_Produktion_FFB | B - SL_NK-Str.02
8621987 | EG_Produktion_FFB | B - SL_NK-Str.02
8622279 | EG_Produktion_FFB | B - FL-Str.03_NK-KK-TK
8622285 | EG_Produktion_FFB | B - FL-Str.03_NK-KK-TK
8622323 | EG_Produktion_FFB | B - SL_NK-Str.02
8622329 | EG_Produktion_FFB | B - SL_NK-Str.02
8622344 | EG_Produktion_FFB | B - SL_NK-Str.02
8622347 | EG_Produktion_FFB | B - SL_NK-Str.02
8622352 | EG_Produktion_FFB | B - FL-Str.03_NK-KK-TK
8622355 | EG_Produktion_FFB | B - FL-Str.03_NK-KK-TK
8622425 | EG_Produktion_FFB | B - SL_NK-Str.02
8622445 | EG_Produktion_FFB | B - FL-Str.03_NK-KK-TK
8622479 | EG_Produktion_FFB | B - SL_NK-Str.02
8622507 | EG_Produktion_FFB | B - FL-Str.03_NK-KK-TK
8622597 | EG_Produktion_FFB | A - FL-Str.03_NK-KK-TK
8622601 | EG_Produktion_FFB | A - FL-Str.03_NK-KK-TK
8622636 | EG_Produktion_FFB | A - SL_NK-Str.02
8622640 | EG_Produktion_FFB | A - SL_NK-Str.02
8622729 | EG_Produktion_FFB | A - FL-Str.03_NK-KK-TK
8622733 | EG_Produktion_FFB | A - FL-Str.03_NK-KK-TK
8622768 | EG_Produktion_FFB | A - SL_NK-Str.02
8622861 | EG_Produktion_FFB | A - SL_NK-Str.02
8622865 | EG_Produktion_FFB | A - SL_NK-Str.02
8622900 | EG_Produktion_FFB | A - FL-Str.03_NK-KK-TK
8622904 | EG_Produktion_FFB | A - FL-Str.03_NK-KK-TK
8623218 | EG_Produktion_FFB | A - FL-Str.03_NK-KK-TK
8623227 | EG_Produktion_FFB | A - FL-Str.03_NK-KK-TK
8623232 | EG_Produktion_FFB | A - FL-Str.03_NK-KK-TK
8623291 | EG_Produktion_FFB | A - SL_NK-Str.01
8623295 | EG_Produktion_FFB | A - SL_NK-Str.01
8623385 | EG_Produktion_FFB | A - FL-Str.03_NK-KK-TK
8623389 | EG_Produktion_FFB | A - FL-Str.03_NK-KK-TK
8623428 | EG_Produktion_FFB | A - SL_NK-Str.01
8623603 | EG_Produktion_FFB | B - FL-Str.03_NK-KK-TK
8623652 | EG_Produktion_FFB | B - FL-Str.03_NK-KK-TK
8623663 | EG_Produktion_FFB | B - FL-Str.03_NK-KK-TK
8623666 | EG_Produktion_FFB | B - FL-Str.03_NK-KK-TK
8623698 | EG_Produktion_FFB | B - SL_NK-Str.01
8623712 | EG_Produktion_FFB | B - SL_NK-Str.01
8623857 | EG_Produktion_FFB | B - SL_NK-Str.01
8623861 | EG_Produktion_FFB | B - SL_NK-Str.01
8623895 | EG_Produktion_FFB | B - FL-Str.03_NK-KK-TK
8623899 | EG_Produktion_FFB | B - FL-Str.03_NK-KK-TK
8623987 | EG_Produktion_FFB | B - SL_NK-Str.02
8623991 | EG_Produktion_FFB | B - SL_NK-Str.02
8624025 | EG_Produktion_FFB | B - FL-Str.03_NK-KK-TK
8624029 | EG_Produktion_FFB | B - FL-Str.03_NK-KK-TK
8624142 | EG_Produktion_FFB | A - SL_NK-Str.01
8624147 | EG_Produktion_FFB | A - SL_NK-Str.01
8624274 | EG_Produktion_FFB | B - SL_NK-Str.01
8624277 | EG_Produktion_FFB | B - SL_NK-Str.01
8624371 | EG_Produktion_FFB | B - SL_NK-Str.01
8624382 | EG_Produktion_FFB | B - SL_NK-Str.01
8624826 | EG_Produktion_FFB | A - SL_NK-Str.02
8624830 | EG_Produktion_FFB | A - SL_NK-Str.02
8624867 | EG_Produktion_FFB | A - FL-Str.03_NK-KK-TK
8624871 | EG_Produktion_FFB | A - FL-Str.03_NK-KK-TK
8624954 | EG_Produktion_FFB | A - FL-Str.03_NK-KK-TK
8624965 | EG_Produktion_FFB | A - FL-Str.03_NK-KK-TK
8624970 | EG_Produktion_FFB | A - FL-Str.03_NK-KK-TK
8625012 | EG_Produktion_FFB | A - SL_NK-Str.02
8625021 | EG_Produktion_FFB | A - SL_NK-Str.02
8625024 | EG_Produktion_FFB | A - SL_NK-Str.02
8625078 | EG_Produktion_FFB | B - SL_NK-Str.02
8625089 | EG_Produktion_FFB | B - SL_NK-Str.02
8625094 | EG_Produktion_FFB | B - SL_NK-Str.02
8625136 | EG_Produktion_FFB | B - FL-Str.03_NK-KK-TK
8625147 | EG_Produktion_FFB | B - FL-Str.03_NK-KK-TK
8625152 | EG_Produktion_FFB | B - FL-Str.03_NK-KK-TK
8625253 | EG_Produktion_FFB | B - FL-Str.02_NK-KK-TK
8625257 | EG_Produktion_FFB | B - FL-Str.02_NK-KK-TK
8625293 | EG_Produktion_FFB | B - SL_NK-Str.02
8625304 | EG_Produktion_FFB | B - SL_NK-Str.02
8625397 | EG_Produktion_FFB | B - SL_NK-Str.02
8625401 | EG_Produktion_FFB | B - SL_NK-Str.02
8625437 | EG_Produktion_FFB | B - FL-Str.02_NK-KK-TK
8625441 | EG_Produktion_FFB | B - FL-Str.02_NK-KK-TK
8625879 | EG_Produktion_FFB | B - SL_NK-Str.02
8626135 | EG_Produktion_FFB | A - FL-Str.02_NK-KK-TK
8626141 | EG_Produktion_FFB | A - FL-Str.02_NK-KK-TK
8626175 | EG_Produktion_FFB | A - SL_NK-Str.02
8626179 | EG_Produktion_FFB | A - SL_NK-Str.02
8626315 | EG_Produktion_FFB | A - SL_NK-Str.02
8626355 | EG_Produktion_FFB | A - FL-Str.02_NK-KK-TK
8626664 | EG_Produktion_FFB | A - SL_NK-Str.02
8626675 | EG_Produktion_FFB | A - SL_NK-Str.02
8626678 | EG_Produktion_FFB | A - SL_NK-Str.02
8626710 | EG_Produktion_FFB | A - FL-Str.03_NK-KK-TK
8626724 | EG_Produktion_FFB | A - FL-Str.03_NK-KK-TK
8626827 | EG_Produktion_FFB | A - FL-Str.03_NK-KK-TK
8627039 | EG_Produktion_FFB | B - FL-Str.02_NK-KK-TK
8627052 | EG_Produktion_FFB | B - FL-Str.02_NK-KK-TK
8627084 | EG_Produktion_FFB | B - SL_TK
8627095 | EG_Produktion_FFB | B - SL_TK
8627100 | EG_Produktion_FFB | B - SL_TK
8627161 | EG_Produktion_FFB | B - FL-Str.02_NK-KK-TK
8627164 | EG_Produktion_FFB | B - FL-Str.02_NK-KK-TK
8627207 | EG_Produktion_FFB | B - SL_TK
8627210 | EG_Produktion_FFB | B - SL_TK
8627292 | EG_Produktion_FFB | A - SL_TK
8627301 | EG_Produktion_FFB | A - SL_TK
8627306 | EG_Produktion_FFB | A - SL_TK
8627338 | EG_Produktion_FFB | A - FL-Str.02_NK-KK-TK
8627349 | EG_Produktion_FFB | A - FL-Str.02_NK-KK-TK
8627545 | EG_Produktion_FFB | B - FL-Str.02_NK-KK-TK
8627590 | EG_Produktion_FFB | B - FL-Str.02_NK-KK-TK
8627623 | EG_Produktion_FFB | B - SL_NK-Str.01
8627632 | EG_Produktion_FFB | B - SL_NK-Str.01
8627637 | EG_Produktion_FFB | B - SL_NK-Str.01
8627798 | EG_Produktion_FFB | B - SL_KK
8627809 | EG_Produktion_FFB | B - SL_KK
8627812 | EG_Produktion_FFB | B - SL_KK
8627836 | EG_Produktion_FFB | B - FL-Str.01_NK-KK-TK
8627847 | EG_Produktion_FFB | B - FL-Str.01_NK-KK-TK
8627850 | EG_Produktion_FFB | B - FL-Str.01_NK-KK-TK
8628373 | EG_Produktion_FFB | B - FL-Str.01_NK-KK-TK
8628407 | EG_Produktion_FFB | B - SL_KK
8628550 | EG_Produktion_FFB | B - SL_KK
8628555 | EG_Produktion_FFB | B - SL_KK
8628597 | EG_Produktion_FFB | B - SL_KK
8628695 | EG_Produktion_FFB | B - FL-Str.01_NK-KK-TK
8628700 | EG_Produktion_FFB | B - FL-Str.01_NK-KK-TK
8628752 | EG_Produktion_FFB | B - FL-Str.01_NK-KK-TK
8628806 | EG_Produktion_FFB | A - SL_KK
8628811 | EG_Produktion_FFB | A - SL_KK
8628859 | EG_Produktion_FFB | A - FL-Str.01_NK-KK-TK
8628864 | EG_Produktion_FFB | A - FL-Str.01_NK-KK-TK
8629114 | EG_Produktion_FFB | B - SL_KK
8629153 | EG_Produktion_FFB | B - FL-Str.01_NK-KK-TK
8629304 | EG_Produktion_FFB | B - FL-Str.01_NK-KK-TK
8629315 | EG_Produktion_FFB | B - FL-Str.01_NK-KK-TK
8629340 | EG_Produktion_FFB | B - SL_KK
8629351 | EG_Produktion_FFB | B - SL_KK
8629669 | EG_Produktion_FFB | B - FL-Str.02_NK-KK-TK
8629672 | EG_Produktion_FFB | B - FL-Str.02_NK-KK-TK
8629713 | EG_Produktion_FFB | B - SL_TK
8629716 | EG_Produktion_FFB | B - SL_TK
8629842 | EG_Produktion_FFB | A - SL_TK
8629845 | EG_Produktion_FFB | A - SL_TK
8629886 | EG_Produktion_FFB | A - FL-Str.02_NK-KK-TK
8629889 | EG_Produktion_FFB | A - FL-Str.02_NK-KK-TK
8630055 | EG_Produktion_FFB | A - SL_TK
8630058 | EG_Produktion_FFB | A - SL_TK
8630099 | EG_Produktion_FFB | A - FL-Str.02_NK-KK-TK
8630102 | EG_Produktion_FFB | A - FL-Str.02_NK-KK-TK
8630337 | EG_Produktion_FFB | B - SL_KK
8630348 | EG_Produktion_FFB | B - SL_KK
8630353 | EG_Produktion_FFB | B - SL_KK
8630491 | EG_Produktion_FFB | A - SL_KK
8630843 | EG_Produktion_FFB | A - SL_KK
8630847 | EG_Produktion_FFB | A - SL_KK
8630874 | EG_Produktion_FFB | A - FL-Str.02_NK-KK-TK
8630878 | EG_Produktion_FFB | A - FL-Str.02_NK-KK-TK
8630993 | EG_Produktion_FFB | A - SL_KK
8630997 | EG_Produktion_FFB | A - SL_KK
8631025 | EG_Produktion_FFB | A - FL-Str.02_NK-KK-TK
8631029 | EG_Produktion_FFB | A - FL-Str.02_NK-KK-TK
8631140 | EG_Produktion_FFB | B - SL_KK
8631151 | EG_Produktion_FFB | B - SL_KK
8631156 | EG_Produktion_FFB | B - SL_KK
8631253 | EG_Produktion_FFB | B - FL-Str.01_NK-KK-TK
8631266 | EG_Produktion_FFB | B - FL-Str.01_NK-KK-TK
8631271 | EG_Produktion_FFB | B - FL-Str.01_NK-KK-TK
8631304 | EG_Produktion_FFB | B - SL_NK-Str.01
8631316 | EG_Produktion_FFB | B - SL_NK-Str.01
8631321 | EG_Produktion_FFB | B - SL_NK-Str.01
8631544 | EG_Produktion_FFB | A - SL_NK-Str.01
8631556 | EG_Produktion_FFB | A - SL_NK-Str.01
8631561 | EG_Produktion_FFB | A - SL_NK-Str.01
8631594 | EG_Produktion_FFB | A - FL-Str.01_NK-KK-TK
8631606 | EG_Produktion_FFB | A - FL-Str.01_NK-KK-TK
8631611 | EG_Produktion_FFB | A - FL-Str.01_NK-KK-TK
8631702 | EG_Produktion_FFB | A - FL-Str.01_NK-KK-TK
8631714 | EG_Produktion_FFB | A - FL-Str.01_NK-KK-TK
8631719 | EG_Produktion_FFB | A - FL-Str.01_NK-KK-TK
8631753 | EG_Produktion_FFB | A - SL_NK-Str.01
8631761 | EG_Produktion_FFB | A - SL_NK-Str.01
8631902 | EG_Produktion_FFB | A - SL_NK-Str.01
8631909 | EG_Produktion_FFB | A - SL_NK-Str.01
8631944 | EG_Produktion_FFB | A - FL-Str.01_NK-KK-TK
8631951 | EG_Produktion_FFB | A - FL-Str.01_NK-KK-TK
8632068 | EG_Produktion_FFB | B - FL-Str.01_NK-KK-TK
8632080 | EG_Produktion_FFB | B - FL-Str.01_NK-KK-TK
8632085 | EG_Produktion_FFB | B - FL-Str.01_NK-KK-TK
8632118 | EG_Produktion_FFB | B - SL_NK-Str.01
8632130 | EG_Produktion_FFB | B - SL_NK-Str.01
8632135 | EG_Produktion_FFB | B - SL_NK-Str.01
8632253 | EG_Produktion_FFB | B - FL-Str.01_NK-KK-TK
8632260 | EG_Produktion_FFB | B - FL-Str.01_NK-KK-TK
8632294 | EG_Produktion_FFB | B - SL_NK-Str.01
8632301 | EG_Produktion_FFB | B - SL_NK-Str.01
8632539 | EG_Produktion_FFB | B - FL-Str.02_NK-KK-TK
8632548 | EG_Produktion_FFB | B - FL-Str.02_NK-KK-TK
8632553 | EG_Produktion_FFB | B - FL-Str.02_NK-KK-TK
8632586 | EG_Produktion_FFB | B - SL_NK-Str.01
8632590 | EG_Produktion_FFB | B - SL_NK-Str.01
8632784 | EG_Produktion_FFB | A - FL-Str.02_NK-KK-TK
8632793 | EG_Produktion_FFB | A - FL-Str.02_NK-KK-TK
8632798 | EG_Produktion_FFB | A - FL-Str.02_NK-KK-TK
8632830 | EG_Produktion_FFB | A - SL_NK-Str.01
8632839 | EG_Produktion_FFB | A - SL_NK-Str.01
8632844 | EG_Produktion_FFB | A - SL_NK-Str.01
8632953 | EG_Produktion_FFB | B - FL-Str.02_NK-KK-TK
8632957 | EG_Produktion_FFB | B - FL-Str.02_NK-KK-TK
8632988 | EG_Produktion_FFB | B - SL_NK-Str.01
8632992 | EG_Produktion_FFB | B - SL_NK-Str.01
8633110 | EG_Produktion_FFB | A - SL_NK-Str.01
8633119 | EG_Produktion_FFB | A - SL_NK-Str.01
8633124 | EG_Produktion_FFB | A - SL_NK-Str.01
8633158 | EG_Produktion_FFB | A - FL-Str.02_NK-KK-TK
8633167 | EG_Produktion_FFB | A - FL-Str.02_NK-KK-TK
8633172 | EG_Produktion_FFB | A - FL-Str.02_NK-KK-TK
8633476 | EG_Produktion_FFB | A - SL_NK-Str.01
8633556 | EG_Produktion_FFB | A - SL_NK-Str.01
8633567 | EG_Produktion_FFB | A - SL_NK-Str.01
8633570 | EG_Produktion_FFB | A - SL_NK-Str.01
8633627 | EG_Produktion_FFB | A - FL-Str.02_NK-KK-TK
8633636 | EG_Produktion_FFB | A - FL-Str.02_NK-KK-TK
8633639 | EG_Produktion_FFB | A - FL-Str.02_NK-KK-TK
8633679 | EG_Produktion_FFB | B - SL_NK-Str.01
8633682 | EG_Produktion_FFB | B - SL_NK-Str.01
8633708 | EG_Produktion_FFB | B - FL-Str.02_NK-KK-TK
8633711 | EG_Produktion_FFB | B - FL-Str.02_NK-KK-TK
8633716 | EG_Produktion_FFB | B - SL_NK-Str.01
8634316 | EG_Produktion_FFB | A - SL_KK
8634344 | EG_Produktion_FFB | A - SL_KK
8634355 | EG_Produktion_FFB | A - SL_KK
8634360 | EG_Produktion_FFB | A - SL_KK
8634384 | EG_Produktion_FFB | A - FL-Str.01_NK-KK-TK
8634463 | EG_Produktion_FFB | A - FL-Str.01_NK-KK-TK
8634474 | EG_Produktion_FFB | A - FL-Str.01_NK-KK-TK
8634479 | EG_Produktion_FFB | A - FL-Str.01_NK-KK-TK
8634740 | EG_Produktion_FFB | A - SL_NK-Str.02
8634753 | EG_Produktion_FFB | A - FL-Str.02_NK-KK-TK
8634756 | EG_Produktion_FFB | A - FL-Str.02_NK-KK-TK
8634841 | EG_Produktion_FFB | A - SL_NK-Str.02
8634857 | EG_Produktion_FFB | A - SL_NK-Str.02
8679629 | EG_Technik_FFB | B - FL-Str.04_NK
8679840 | EG_Technik_FFB | B - FL-Str.04_NK
8680067 | EG_Produktion_FFB | B - SL_NK-Str.03
8680107 | EG_Technik_FFB | B - SL_NK-Str.03
8680110 | EG_Produktion_FFB | B - SL_NK-Str.03
8680193 | EG_Produktion_FFB | A - FL-Str.04_NK
8680208 | EG_Technik_FFB | A - FL-Str.04_NK
8680211 | EG_Produktion_FFB | A - FL-Str.04_NK
8680309 | EG_Technik_FFB | A - SL_NK-Str.03
8680312 | EG_Produktion_FFB | A - SL_NK-Str.03
8680493 | EG_Produktion_FFB | B - SL_NK-Str.03
8680497 | EG_Produktion_FFB | B - SL_NK-Str.03
8680520 | EG_Produktion_FFB | B - FL-Str.04_NK
8680529 | EG_Produktion_FFB | B - FL-Str.04_NK
8680534 | EG_Produktion_FFB | B - FL-Str.04_NK
8680582 | EG_Produktion_FFB | A - SL_NK-Str.03
8680591 | EG_Produktion_FFB | A - SL_NK-Str.03
8680596 | EG_Produktion_FFB | A - SL_NK-Str.03
8680637 | EG_Produktion_FFB | A - FL-Str.04_NK
8680641 | EG_Produktion_FFB | A - FL-Str.04_NK
10082034 | EG_Produktion_FFB | B - Druckleitung Gaskühler
10082039 | EG_Produktion_FFB | B - Druckleitung Gaskühler
10082099 | EG_Produktion_FFB | B - Druckleitung Gaskühler
10082104 | EG_Produktion_FFB | B - Druckleitung Gaskühler
10082179 | EG_Produktion_FFB | A - Kondensatleitung Gaskühler
10082182 | EG_Produktion_FFB | A - Kondensatleitung Gaskühler
10082267 | EG_Produktion_FFB | A - Druckleitung Gaskühler
10082274 | EG_Produktion_FFB | A - Druckleitung Gaskühler
10082314 | EG_Produktion_FFB | A - Druckleitung Gaskühler
10082317 | EG_Produktion_FFB | A - Druckleitung Gaskühler

# IfcFlowFitting: T-Stück Kupfer:Allgemein (150)
In: EG_Produktion_FFB
Type - Material: <Unnamed>
Pset_FM-Vivantes - Baujahr: 1; Prüfpflicht: yes; Prüfintervall: 1; Sammelobjekt: yes; rechn. Lebensdauer: 1; Familie und Typ: T-Stück Kupfer: Allgemein; Klasse: 471; Bezeichnung: T-Stück - allgemein: Standard; AKS: i.b.; Standort: i.b.; Hersteller: i.b.; Hersteller-Typ: i.b.; Seriennummer: i.b.; Gewährleistungsgeber: 1; Betriebsstatus: i.b.; technischer Zustand: i.b.; Eigentümer: i.b.; Bemerkung: i.b.
Name (T-Stück Kupfer:Allgemein:...) | Group
8579404 | A - FL-Str.01_NK-KK-TK
8579409 | A - FL-Str.01_NK-KK-TK
8579415 | A - FL-Str.01_NK-KK-TK
8579424 | A - FL-Str.01_NK-KK-TK
8579433 | A - FL-Str.01_NK-KK-TK
8579450 | A - FL-Str.01_NK-KK-TK
8579456 | A - FL-Str.01_NK-KK-TK
8579462 | A - FL-Str.01_NK-KK-TK
8579498 | A - FL-Str.01_NK-KK-TK
8579504 | A - FL-Str.01_NK-KK-TK
8579584 | B - FL-Str.01_NK-KK-TK
8579612 | B - FL-Str.01_NK-KK-TK
8579618 | B - FL-Str.01_NK-KK-TK
8579627 | B - FL-Str.01_NK-KK-TK
8579633 | B - FL-Str.01_NK-KK-TK
8579642 | B - FL-Str.01_NK-KK-TK
8579648 | B - FL-Str.01_NK-KK-TK
8579654 | B - FL-Str.01_NK-KK-TK
8579660 | B - FL-Str.01_NK-KK-TK
8579666 | B - FL-Str.01_NK-KK-TK
8579672 | B - FL-Str.01_NK-KK-TK
8579699 | B - FL-Str.01_NK-KK-TK
8579743 | A - FL-Str.03_NK-KK-TK
8579750 | A - FL-Str.03_NK-KK-TK
8579756 | A - FL-Str.03_NK-KK-TK
8579762 | A - FL-Str.03_NK-KK-TK
8579768 | A - FL-Str.03_NK-KK-TK
8579802 | B - FL-Str.03_NK-KK-TK
8579812 | B - FL-Str.03_NK-KK-TK
8579818 | B - FL-Str.03_NK-KK-TK
8579827 | B - FL-Str.03_NK-KK-TK
8579833 | B - FL-Str.03_NK-KK-TK
8579839 | B - FL-Str.03_NK-KK-TK
8579845 | B - FL-Str.03_NK-KK-TK
8579876 | B - FL-Str.02_NK-KK-TK
8579901 | A - FL-Str.02_NK-KK-TK
8579949 | A - FL-Str.02_NK-KK-TK
8579955 | B - FL-Str.02_NK-KK-TK
8579964 | B - FL-Str.02_NK-KK-TK
8579984 | A - FL-Str.02_NK-KK-TK
8580008 | B - FL-Str.02_NK-KK-TK
8580017 | A - FL-Str.02_NK-KK-TK
8580026 | B - FL-Str.02_NK-KK-TK
8580062 | A - FL-Str.02_NK-KK-TK
8580074 | B - FL-Str.02_NK-KK-TK
8580083 | A - FL-Str.02_NK-KK-TK
8580119 | B - FL-Str.02_NK-KK-TK
8580128 | A - FL-Str.02_NK-KK-TK
8580140 | A - FL-Str.02_NK-KK-TK
8580892 | B - FL-Str.02_NK-KK-TK
8583607 | A - SL_KK
8583716 | A - SL_KK
8583914 | A - SL_KK
8583937 | A - SL_KK
8584008 | A - SL_KK
8584294 | A - SL_KK
8584319 | A - SL_KK
8585072 | B - SL_KK
8585100 | B - SL_KK
8585136 | B - SL_KK
8585142 | B - SL_KK
8585148 | B - SL_KK
8585154 | B - SL_KK
8585160 | B - SL_KK
8585184 | B - SL_KK
8585993 | B - SL_KK
8586322 | B - SL_KK
8586600 | A - SL_NK-Str.02
8586619 | A - SL_NK-Str.02
8586625 | A - SL_NK-Str.02
8586659 | B - SL_NK-Str.02
8586669 | B - SL_NK-Str.02
8586675 | B - SL_NK-Str.02
8586696 | B - SL_NK-Str.02
8586702 | B - SL_NK-Str.02
8586895 | B - SL_NK-Str.01
8586904 | A - SL_NK-Str.01
8586961 | A - SL_NK-Str.01
8586970 | B - SL_NK-Str.01
8587733 | A - SL_NK-Str.01
8587913 | B - SL_NK-Str.01
8589758 | A - SL_TK
8589853 | B - SL_TK
8589890 | B - SL_TK
8590502 | B - SL_NK-Str.01
8590802 | A - SL_NK-Str.01
8591841 | B - SL_NK-Str.01
8591985 | B - SL_NK-Str.01
8592016 | B - SL_NK-Str.01
8592218 | A - SL_NK-Str.01
8592619 | A - SL_NK-Str.01
8592661 | A - SL_NK-Str.01
8598239 | A - SL_KK
8599456 | B - SL_NK-Str.02
8599463 | A - SL_NK-Str.02
8599636 | B - SL_NK-Str.02
8599756 | A - FL-Str.03_NK-KK-TK
8599907 | A - SL_NK-Str.02
8600074 | A - SL_NK-Str.02
8600181 | A - SL_NK-Str.02
8600290 | A - FL-Str.03_NK-KK-TK
8602810 | B - FL-Str.02_NK-KK-TK
8602826 | A - FL-Str.02_NK-KK-TK
8602864 | A - FL-Str.02_NK-KK-TK
8603341 | A - SL_NK-Str.01
8603353 | B - SL_NK-Str.01
8606888 | A - FL-Str.01_NK-KK-TK
8606911 | A - SL_KK
8606939 | A - SL_KK
8606993 | A - FL-Str.01_NK-KK-TK
8610850 | A - SL_NK-Str.01
8610894 | A - FL-Str.02_NK-KK-TK
8611044 | B - SL_NK-Str.01
8611050 | A - SL_NK-Str.01
8611175 | A - FL-Str.02_NK-KK-TK
8611212 | A - SL_NK-Str.01
8612145 | B - FL-Str.02_NK-KK-TK
8612234 | B - FL-Str.02_NK-KK-TK
8612295 | B - SL_NK-Str.01
8612431 | A - SL_NK-Str.01
8612504 | A - FL-Str.02_NK-KK-TK
8612680 | A - SL_NK-Str.01
8612711 | A - FL-Str.02_NK-KK-TK
8613188 | B - SL_NK-Str.01
8613691 | B - SL_NK-Str.01
8613736 | B - FL-Str.02_NK-KK-TK
8613854 | B - SL_NK-Str.01
8614003 | B - FL-Str.02_NK-KK-TK
8615572 | A - SL_TK
8617865 | A - FL-Str.01_NK-KK-TK
8617901 | A - SL_KK
8618019 | A - FL-Str.01_NK-KK-TK
8618066 | A - SL_NK-Str.01
8618200 | B - SL_NK-Str.01
8618244 | B - FL-Str.01_NK-KK-TK
8627149 | B - FL-Str.02_NK-KK-TK
8627195 | B - SL_TK
8627539 | B - FL-Str.02_NK-KK-TK
8628538 | B - SL_KK
8628683 | B - FL-Str.01_NK-KK-TK
8628794 | A - SL_KK
8628847 | A - FL-Str.01_NK-KK-TK
8629107 | B - SL_KK
8629147 | B - FL-Str.01_NK-KK-TK
8629657 | B - FL-Str.02_NK-KK-TK
8629701 | B - SL_TK
8629830 | A - SL_TK
8629874 | A - FL-Str.02_NK-KK-TK
8630043 | A - SL_TK
8630087 | A - FL-Str.02_NK-KK-TK

# IfcFlowFitting: Übergang Kupfer:Allgemein (18)
In: EG_Produktion_FFB
Type - Material: <Unnamed>
Pset_FM-Vivantes - Baujahr: 1; Prüfpflicht: yes; Prüfintervall: 1; Sammelobjekt: yes; rechn. Lebensdauer: 1; Familie und Typ: Übergang Kupfer: Allgemein; Klasse: 471; Bezeichnung: Übergang - allgemein: Standard; AKS: i.b.; Standort: i.b.; Hersteller: i.b.; Hersteller-Typ: i.b.; Seriennummer: i.b.; Gewährleistungsgeber: 1; Betriebsstatus: i.b.; technischer Zustand: i.b.; Eigentümer: i.b.; Bemerkung: i.b.
Name (Übergang Kupfer:Allgemein:...) | Group
8622381 | B - FL-Str.03_NK-KK-TK
8622384 | B - FL-Str.03_NK-KK-TK
8622387 | B - SL_NK-Str.02
8622390 | B - SL_NK-Str.02
8631255 | B - FL-Str.01_NK-KK-TK
8631306 | B - SL_NK-Str.01
8631546 | A - SL_NK-Str.01
8631596 | A - FL-Str.01_NK-KK-TK
8631704 | A - FL-Str.01_NK-KK-TK
8631755 | A - SL_NK-Str.01
8631904 | A - SL_NK-Str.01
8631946 | A - FL-Str.01_NK-KK-TK
8632070 | B - FL-Str.01_NK-KK-TK
8632120 | B - SL_NK-Str.01
8632255 | B - FL-Str.01_NK-KK-TK
8632296 | B - SL_NK-Str.01
10082269 | A - Druckleitung Gaskühler
10082319 | A - Druckleitung Gaskühler

# IfcFlowSegment: Rohrtypen:Kupfer - isoliert (851)
Pset_FM-Vivantes - Baujahr: 1; Prüfpflicht: yes; Prüfintervall: 1; Sammelobjekt: yes; rechn. Lebensdauer: 1; Familie und Typ: Rohrtypen: Kupfer - isoliert; Klasse: 471; Bezeichnung: Kleinkälte; AKS: i.b.; Standort: i.b.; Hersteller: i.b.; Hersteller-Typ: i.b.; Seriennummer: i.b.; Gewährleistungsgeber: 1; Betriebsstatus: i.b.; technischer Zustand: i.b.; Eigentümer: i.b.; Bemerkung: i.b.
Name (Rohrtypen:Kupfer - isoliert:...) | In | Group
8579189 | EG_Produktion_FFB | A - Kondensatleitung Gaskühler
8579192 | EG_Produktion_FFB | A - Kondensatleitung Gaskühler
8579195 | EG_Produktion_FFB | A - Kondensatleitung Gaskühler
8579204 | EG_Produktion_FFB | A - Kondensatleitung Gaskühler
8579207 | EG_Produktion_FFB | A - Kondensatleitung Gaskühler
8579213 | EG_Produktion_FFB | A - Kondensatleitung Gaskühler
8579216 | EG_Produktion_FFB | A - Kondensatleitung Gaskühler
8579225 | EG_Produktion_FFB | A - Kondensatleitung Gaskühler
8579234 | EG_Produktion_FFB | A - Druckleitung Gaskühler
8579237 | EG_Produktion_FFB | A - Druckleitung Gaskühler
8579240 | EG_Produktion_FFB | A - Druckleitung Gaskühler
8579243 | EG_Produktion_FFB | A - Druckleitung Gaskühler
8579246 | EG_Produktion_FFB | A - Druckleitung Gaskühler
8579249 | EG_Produktion_FFB | A - Druckleitung Gaskühler
8579252 | EG_Produktion_FFB | A - Druckleitung Gaskühler
8579255 | EG_Produktion_FFB | A - Druckleitung Gaskühler
8579279 | Wartung_FFB | B - Kondensatleitung Gaskühler
8579282 | Wartung_FFB | B - Druckleitung Gaskühler
8579285 | Wartung_FFB | B - Kondensatleitung Gaskühler
8579288 | Wartung_FFB | B - Druckleitung Gaskühler
8579291 | Wartung_FFB | B - Kondensatleitung Gaskühler
8579294 | Wartung_FFB | B - Druckleitung Gaskühler
8579304 | Wartung_FFB | B - Kondensatleitung Gaskühler
8579313 | Wartung_FFB | B - Druckleitung Gaskühler
8579322 | EG_Produktion_FFB | B - Druckleitung Gaskühler
8579325 | EG_Produktion_FFB | B - Kondensatleitung Gaskühler
8579337 | EG_Produktion_FFB | B - Kondensatleitung Gaskühler
8579340 | EG_Produktion_FFB | B - Druckleitung Gaskühler
8579342 | EG_Produktion_FFB | B - Kondensatleitung Gaskühler
8579345 | EG_Produktion_FFB | B - Kondensatleitung Gaskühler
8579357 | EG_Produktion_FFB | B - Druckleitung Gaskühler
8579360 | EG_Produktion_FFB | B - Druckleitung Gaskühler
8579369 | EG_Produktion_FFB | A - FL-Str.01_NK-KK-TK
8579399 | EG_Produktion_FFB | A - FL-Str.01_NK-KK-TK
8579410 | EG_Produktion_FFB | A - FL-Str.01_NK-KK-TK
8579416 | EG_Produktion_FFB | A - FL-Str.01_NK-KK-TK
8579425 | EG_Produktion_FFB | A - FL-Str.01_NK-KK-TK
8579434 | EG_Produktion_FFB | A - FL-Str.01_NK-KK-TK
8579451 | EG_Produktion_FFB | A - FL-Str.01_NK-KK-TK
8579457 | EG_Produktion_FFB | A - FL-Str.01_NK-KK-TK
8579463 | EG_Produktion_FFB | A - FL-Str.01_NK-KK-TK
8579499 | EG_Produktion_FFB | A - FL-Str.01_NK-KK-TK
8579505 | EG_Produktion_FFB | A - FL-Str.01_NK-KK-TK
8579513 | EG_Produktion_FFB | A - FL-Str.01_NK-KK-TK
8579516 | EG_Produktion_FFB | A - FL-Str.01_NK-KK-TK
8579519 | EG_Produktion_FFB | A - FL-Str.01_NK-KK-TK
8579531 | EG_Produktion_FFB | B - FL-Str.01_NK-KK-TK
8579534 | EG_Produktion_FFB | B - FL-Str.01_NK-KK-TK
8579537 | EG_Produktion_FFB | B - FL-Str.01_NK-KK-TK
8579567 | EG_Produktion_FFB | B - FL-Str.01_NK-KK-TK
8579585 | EG_Produktion_FFB | B - FL-Str.01_NK-KK-TK
8579613 | EG_Produktion_FFB | B - FL-Str.01_NK-KK-TK
8579619 | EG_Produktion_FFB | B - FL-Str.01_NK-KK-TK
8579628 | EG_Produktion_FFB | B - FL-Str.01_NK-KK-TK
8579634 | EG_Produktion_FFB | B - FL-Str.01_NK-KK-TK
8579643 | EG_Produktion_FFB | B - FL-Str.01_NK-KK-TK
8579649 | EG_Produktion_FFB | B - FL-Str.01_NK-KK-TK
8579655 | EG_Produktion_FFB | B - FL-Str.01_NK-KK-TK
8579661 | EG_Produktion_FFB | B - FL-Str.01_NK-KK-TK
8579667 | EG_Produktion_FFB | B - FL-Str.01_NK-KK-TK
8579673 | EG_Produktion_FFB | B - FL-Str.01_NK-KK-TK
8579700 | EG_Produktion_FFB | B - FL-Str.01_NK-KK-TK
8579705 | EG_Produktion_FFB | A - FL-Str.03_NK-KK-TK
8579741 | EG_Produktion_FFB | A - FL-Str.03_NK-KK-TK
8579751 | EG_Produktion_FFB | A - FL-Str.03_NK-KK-TK
8579757 | EG_Produktion_FFB | A - FL-Str.03_NK-KK-TK
8579763 | EG_Produktion_FFB | A - FL-Str.03_NK-KK-TK
8579769 | EG_Produktion_FFB | A - FL-Str.03_NK-KK-TK
8579774 | EG_Produktion_FFB | B - FL-Str.03_NK-KK-TK
8579803 | EG_Produktion_FFB | B - FL-Str.03_NK-KK-TK
8579813 | EG_Produktion_FFB | B - FL-Str.03_NK-KK-TK
8579819 | EG_Produktion_FFB | B - FL-Str.03_NK-KK-TK
8579828 | EG_Produktion_FFB | B - FL-Str.03_NK-KK-TK
8579834 | EG_Produktion_FFB | B - FL-Str.03_NK-KK-TK
8579840 | EG_Produktion_FFB | B - FL-Str.03_NK-KK-TK
8579846 | EG_Produktion_FFB | B - FL-Str.03_NK-KK-TK
8579868 | EG_Produktion_FFB | A - FL-Str.03_NK-KK-TK
8579877 | EG_Produktion_FFB | B - FL-Str.02_NK-KK-TK
8579902 | EG_Produktion_FFB | A - FL-Str.02_NK-KK-TK
8579907 | EG_Technik_FFB | A - FL-Str.03_NK-KK-TK
8579916 | EG_Technik_FFB | B - FL-Str.03_NK-KK-TK
8579921 | EG_Produktion_FFB | B - FL-Str.03_NK-KK-TK
8579923 | EG_Technik_FFB | B - FL-Str.03_NK-KK-TK
8579926 | EG_Produktion_FFB | A - FL-Str.03_NK-KK-TK
8579928 | EG_Technik_FFB | A - FL-Str.03_NK-KK-TK
8579950 | EG_Produktion_FFB | A - FL-Str.02_NK-KK-TK
8579956 | EG_Produktion_FFB | B - FL-Str.02_NK-KK-TK
8579965 | EG_Produktion_FFB | B - FL-Str.02_NK-KK-TK
8579985 | EG_Produktion_FFB | A - FL-Str.02_NK-KK-TK
8580009 | EG_Produktion_FFB | B - FL-Str.02_NK-KK-TK
8580018 | EG_Produktion_FFB | A - FL-Str.02_NK-KK-TK
8580027 | EG_Produktion_FFB | B - FL-Str.02_NK-KK-TK
8580063 | EG_Produktion_FFB | A - FL-Str.02_NK-KK-TK
8580075 | EG_Produktion_FFB | B - FL-Str.02_NK-KK-TK
8580084 | EG_Produktion_FFB | A - FL-Str.02_NK-KK-TK
8580120 | EG_Produktion_FFB | B - FL-Str.02_NK-KK-TK
8580129 | EG_Produktion_FFB | A - FL-Str.02_NK-KK-TK
8580141 | EG_Produktion_FFB | A - FL-Str.02_NK-KK-TK
8580893 | EG_Produktion_FFB | B - FL-Str.02_NK-KK-TK
8582813 | EG_Produktion_FFB | A - SL_KK
8582850 | EG_Produktion_FFB | A - SL_KK
8582853 | EG_Produktion_FFB | A - SL_KK
8582856 | EG_Produktion_FFB | A - SL_KK
8583608 | EG_Produktion_FFB | A - SL_KK
8583717 | EG_Produktion_FFB | A - SL_KK
8583915 | EG_Produktion_FFB | A - SL_KK
8583938 | EG_Produktion_FFB | A - SL_KK
8584009 | EG_Produktion_FFB | A - SL_KK
8584295 | EG_Produktion_FFB | A - SL_KK
8584320 | EG_Produktion_FFB | A - SL_KK
8585101 | EG_Produktion_FFB | B - SL_KK
8585107 | EG_Produktion_FFB | B - SL_KK
8585122 | EG_Produktion_FFB | B - SL_KK
8585137 | EG_Produktion_FFB | B - SL_KK
8585143 | EG_Produktion_FFB | B - SL_KK
8585149 | EG_Produktion_FFB | B - SL_KK
8585155 | EG_Produktion_FFB | B - SL_KK
8585161 | EG_Produktion_FFB | B - SL_KK
8585185 | EG_Produktion_FFB | B - SL_KK
8585994 | EG_Produktion_FFB | B - SL_KK
8586323 | EG_Produktion_FFB | B - SL_KK
8586417 | EG_Produktion_FFB | B - SL_KK
8586420 | EG_Produktion_FFB | B - SL_KK
8586423 | EG_Produktion_FFB | B - SL_KK
8586614 | EG_Produktion_FFB | A - SL_NK-Str.02
8586620 | EG_Produktion_FFB | A - SL_NK-Str.02
8586626 | EG_Produktion_FFB | A - SL_NK-Str.02
8586660 | EG_Produktion_FFB | B - SL_NK-Str.02
8586670 | EG_Produktion_FFB | B - SL_NK-Str.02
8586676 | EG_Produktion_FFB | B - SL_NK-Str.02
8586691 | EG_Produktion_FFB | B - SL_NK-Str.02
8586697 | EG_Produktion_FFB | B - SL_NK-Str.02
8586703 | EG_Produktion_FFB | B - SL_NK-Str.02
8586725 | EG_Produktion_FFB | A - SL_NK-Str.02
8586734 | EG_Produktion_FFB | B - SL_NK-Str.01
8586759 | EG_Produktion_FFB | A - SL_NK-Str.01
8586839 | EG_Produktion_FFB | A - SL_NK-Str.01
8586896 | EG_Produktion_FFB | B - SL_NK-Str.01
8586941 | EG_Produktion_FFB | B - SL_NK-Str.01
8586950 | EG_Produktion_FFB | A - SL_NK-Str.01
8587938 | EG_Technik_FFB | A - SL_NK-Str.02
8587947 | EG_Technik_FFB | B - SL_NK-Str.02
8587952 | EG_Produktion_FFB | B - SL_NK-Str.02
8587954 | EG_Technik_FFB | B - SL_NK-Str.02
8587957 | EG_Produktion_FFB | A - SL_NK-Str.02
8587959 | EG_Technik_FFB | A - SL_NK-Str.02
8589466 | EG_Produktion_FFB | B - SL_TK
8589527 | EG_Produktion_FFB | A - SL_TK
8589759 | EG_Produktion_FFB | A - SL_TK
8589854 | EG_Produktion_FFB | B - SL_TK
8589891 | EG_Produktion_FFB | B - SL_TK
8590503 | EG_Produktion_FFB | B - SL_NK-Str.01
8590803 | EG_Produktion_FFB | A - SL_NK-Str.01
8591842 | EG_Produktion_FFB | B - SL_NK-Str.01
8591986 | EG_Produktion_FFB | B - SL_NK-Str.01
8592017 | EG_Produktion_FFB | B - SL_NK-Str.01
8592219 | EG_Produktion_FFB | A - SL_NK-Str.01
8592620 | EG_Produktion_FFB | A - SL_NK-Str.01
8592662 | EG_Produktion_FFB | A - SL_NK-Str.01
8593001 | EG_Produktion_FFB | A - SL_NK-Str.01
8593004 | EG_Produktion_FFB | A - SL_NK-Str.01
8593007 | EG_Produktion_FFB | B - SL_NK-Str.01
8593010 | EG_Produktion_FFB | B - SL_NK-Str.01
8593013 | EG_Produktion_FFB | A - FL-Str.02_NK-KK-TK
8593016 | EG_Produktion_FFB | A - FL-Str.02_NK-KK-TK
8593019 | EG_Produktion_FFB | B - FL-Str.02_NK-KK-TK
8593022 | EG_Produktion_FFB | B - FL-Str.02_NK-KK-TK
8593052 | EG_Produktion_FFB | A - SL_TK
8593055 | EG_Produktion_FFB | A - SL_TK
8593058 | EG_Produktion_FFB | B - SL_TK
8593061 | EG_Produktion_FFB | B - SL_TK
8593085 | EG_Produktion_FFB | B - FL-Str.02_NK-KK-TK
8593088 | EG_Produktion_FFB | B - SL_NK-Str.01
8593090 | EG_Produktion_FFB | B - SL_TK
8593135 | EG_Produktion_FFB | A - SL_NK-Str.01
8593137 | EG_Produktion_FFB | A - SL_TK
8593230 | EG_Produktion_FFB | A - FL-Str.02_NK-KK-TK
8595055 | EG_Produktion_FFB | A - SL_NK-Str.02
8596979 | EG_Produktion_FFB | A - Druckleitung Gaskühler
8597207 | EG_Produktion_FFB | A - Kondensatleitung Gaskühler
8597209 | EG_Produktion_FFB | A - Druckleitung Gaskühler
8598240 | EG_Produktion_FFB | A - SL_KK
8599349 | EG_Produktion_FFB | A - FL-Str.03_NK-KK-TK
8599352 | EG_Produktion_FFB | A - FL-Str.03_NK-KK-TK
8599355 | EG_Produktion_FFB | A - FL-Str.03_NK-KK-TK
8599358 | EG_Produktion_FFB | A - FL-Str.03_NK-KK-TK
8599361 | EG_Produktion_FFB | A - FL-Str.03_NK-KK-TK
8599364 | EG_Produktion_FFB | A - FL-Str.03_NK-KK-TK
8599367 | EG_Produktion_FFB | A - FL-Str.03_NK-KK-TK
8599369 | EG_Produktion_FFB | A - FL-Str.03_NK-KK-TK
8599373 | EG_Produktion_FFB | A - FL-Str.03_NK-KK-TK
8599376 | EG_Produktion_FFB | B - FL-Str.03_NK-KK-TK
8599379 | EG_Produktion_FFB | B - FL-Str.03_NK-KK-TK
8599382 | EG_Produktion_FFB | B - FL-Str.03_NK-KK-TK
8599385 | EG_Produktion_FFB | B - FL-Str.03_NK-KK-TK
8599388 | EG_Produktion_FFB | B - FL-Str.03_NK-KK-TK
8599391 | EG_Produktion_FFB | B - FL-Str.03_NK-KK-TK
8599394 | EG_Produktion_FFB | B - FL-Str.03_NK-KK-TK
8599400 | EG_Produktion_FFB | A - SL_NK-Str.02
8599403 | EG_Produktion_FFB | A - SL_NK-Str.02
8599406 | EG_Produktion_FFB | A - SL_NK-Str.02
8599409 | EG_Produktion_FFB | A - SL_NK-Str.02
8599412 | EG_Produktion_FFB | A - SL_NK-Str.02
8599414 | EG_Produktion_FFB | A - SL_NK-Str.02
8599418 | EG_Produktion_FFB | A - SL_NK-Str.02
8599421 | EG_Produktion_FFB | B - SL_NK-Str.02
8599423 | EG_Produktion_FFB | B - SL_NK-Str.02
8599426 | EG_Produktion_FFB | B - SL_NK-Str.02
8599429 | EG_Produktion_FFB | B - SL_NK-Str.02
8599432 | EG_Produktion_FFB | B - SL_NK-Str.02
8599435 | EG_Produktion_FFB | B - SL_NK-Str.02
8599438 | EG_Produktion_FFB | B - SL_NK-Str.02
8599441 | EG_Produktion_FFB | B - SL_NK-Str.02
8599444 | EG_Produktion_FFB | B - SL_NK-Str.02
8599447 | EG_Produktion_FFB | A - SL_NK-Str.02
8599454 | EG_Produktion_FFB | A - SL_NK-Str.02
8599464 | EG_Produktion_FFB | A - SL_NK-Str.02
8599475 | EG_Produktion_FFB | A - SL_NK-Str.02
8599637 | EG_Produktion_FFB | B - SL_NK-Str.02
8600075 | EG_Produktion_FFB | A - SL_NK-Str.02
8600182 | EG_Produktion_FFB | A - SL_NK-Str.02
8600291 | EG_Produktion_FFB | A - FL-Str.03_NK-KK-TK
8602648 | EG_Produktion_FFB | A - FL-Str.01_NK-KK-TK
8602651 | EG_Produktion_FFB | A - FL-Str.01_NK-KK-TK
8602654 | EG_Produktion_FFB | A - FL-Str.01_NK-KK-TK
8602657 | EG_Produktion_FFB | A - FL-Str.01_NK-KK-TK
8602660 | EG_Produktion_FFB | A - FL-Str.01_NK-KK-TK
8602667 | EG_Produktion_FFB | A - FL-Str.01_NK-KK-TK
8602675 | EG_Produktion_FFB | A - FL-Str.01_NK-KK-TK
8602678 | EG_Produktion_FFB | A - FL-Str.01_NK-KK-TK
8602681 | EG_Produktion_FFB | A - FL-Str.01_NK-KK-TK
8602684 | EG_Produktion_FFB | A - FL-Str.01_NK-KK-TK
8602687 | EG_Produktion_FFB | A - FL-Str.01_NK-KK-TK
8602690 | EG_Produktion_FFB | A - FL-Str.01_NK-KK-TK
8602696 | EG_Produktion_FFB | A - FL-Str.01_NK-KK-TK
8602700 | EG_Produktion_FFB | A - FL-Str.01_NK-KK-TK
8602705 | EG_Produktion_FFB | A - FL-Str.01_NK-KK-TK
8602708 | EG_Produktion_FFB | A - SL_KK
8602720 | EG_Produktion_FFB | B - FL-Str.01_NK-KK-TK
8602723 | EG_Produktion_FFB | B - FL-Str.01_NK-KK-TK
8602726 | EG_Produktion_FFB | B - FL-Str.01_NK-KK-TK
8602729 | EG_Produktion_FFB | B - FL-Str.01_NK-KK-TK
8602738 | EG_Produktion_FFB | B - FL-Str.01_NK-KK-TK
8602741 | EG_Produktion_FFB | B - FL-Str.01_NK-KK-TK
8602744 | EG_Produktion_FFB | B - FL-Str.01_NK-KK-TK
8602747 | EG_Produktion_FFB | B - FL-Str.01_NK-KK-TK
8602750 | EG_Produktion_FFB | B - FL-Str.01_NK-KK-TK
8602753 | EG_Produktion_FFB | B - FL-Str.01_NK-KK-TK
8602756 | EG_Produktion_FFB | B - FL-Str.01_NK-KK-TK
8602762 | EG_Produktion_FFB | B - FL-Str.01_NK-KK-TK
8602766 | EG_Produktion_FFB | B - FL-Str.01_NK-KK-TK
8602774 | EG_Produktion_FFB | B - FL-Str.01_NK-KK-TK
8602781 | EG_Produktion_FFB | B - FL-Str.01_NK-KK-TK
8602786 | EG_Produktion_FFB | B - FL-Str.01_NK-KK-TK
8602790 | EG_Produktion_FFB | B - FL-Str.01_NK-KK-TK
8602798 | EG_Produktion_FFB | B - FL-Str.02_NK-KK-TK
8602801 | EG_Produktion_FFB | B - FL-Str.02_NK-KK-TK
8602804 | EG_Produktion_FFB | B - FL-Str.02_NK-KK-TK
8602811 | EG_Produktion_FFB | B - FL-Str.02_NK-KK-TK
8602816 | EG_Produktion_FFB | A - FL-Str.02_NK-KK-TK
8602820 | EG_Produktion_FFB | A - FL-Str.02_NK-KK-TK
8602827 | EG_Produktion_FFB | A - FL-Str.02_NK-KK-TK
8602832 | EG_Produktion_FFB | A - FL-Str.02_NK-KK-TK
8602834 | EG_Produktion_FFB | B - FL-Str.02_NK-KK-TK
8602837 | EG_Produktion_FFB | A - FL-Str.02_NK-KK-TK
8602843 | EG_Produktion_FFB | B - FL-Str.02_NK-KK-TK
8602847 | EG_Produktion_FFB | B - FL-Str.02_NK-KK-TK
8602852 | EG_Produktion_FFB | A - FL-Str.02_NK-KK-TK
8602855 | EG_Produktion_FFB | A - FL-Str.02_NK-KK-TK
8602861 | EG_Produktion_FFB | A - FL-Str.02_NK-KK-TK
8602865 | EG_Produktion_FFB | A - FL-Str.02_NK-KK-TK
8602871 | EG_Produktion_FFB | B - FL-Str.02_NK-KK-TK
8602874 | EG_Produktion_FFB | A - FL-Str.02_NK-KK-TK
8602877 | EG_Produktion_FFB | B - FL-Str.02_NK-KK-TK
8602883 | EG_Produktion_FFB | B - FL-Str.02_NK-KK-TK
8602886 | EG_Produktion_FFB | B - FL-Str.02_NK-KK-TK
8602895 | EG_Produktion_FFB | A - FL-Str.02_NK-KK-TK
8602901 | EG_Produktion_FFB | A - FL-Str.02_NK-KK-TK
8602913 | EG_Produktion_FFB | B - FL-Str.02_NK-KK-TK
8602916 | EG_Produktion_FFB | A - FL-Str.02_NK-KK-TK
8602919 | EG_Produktion_FFB | A - FL-Str.02_NK-KK-TK
8602925 | EG_Produktion_FFB | A - FL-Str.02_NK-KK-TK
8602934 | EG_Produktion_FFB | B - FL-Str.02_NK-KK-TK
8602937 | EG_Produktion_FFB | B - FL-Str.02_NK-KK-TK
8602940 | EG_Produktion_FFB | B - FL-Str.02_NK-KK-TK
8602955 | EG_Produktion_FFB | A - FL-Str.02_NK-KK-TK
8602958 | EG_Produktion_FFB | B - FL-Str.02_NK-KK-TK
8602961 | EG_Produktion_FFB | A - FL-Str.02_NK-KK-TK
8602972 | EG_Produktion_FFB | A - FL-Str.02_NK-KK-TK
8602981 | EG_Produktion_FFB | B - FL-Str.02_NK-KK-TK
8602998 | EG_Produktion_FFB | A - SL_KK
8603000 | EG_Produktion_FFB | A - SL_KK
8603002 | EG_Produktion_FFB | A - SL_KK
8603004 | EG_Produktion_FFB | A - SL_KK
8603007 | EG_Produktion_FFB | A - SL_KK
8603009 | EG_Produktion_FFB | A - SL_KK
8603012 | EG_Produktion_FFB | A - SL_KK
8603020 | EG_Produktion_FFB | A - SL_KK
8603023 | EG_Produktion_FFB | A - SL_KK
8603026 | EG_Produktion_FFB | A - SL_KK
8603032 | EG_Produktion_FFB | A - SL_KK
8603035 | EG_Produktion_FFB | A - FL-Str.01_NK-KK-TK
8603039 | EG_Produktion_FFB | A - SL_KK
8603050 | EG_Produktion_FFB | B - SL_KK
8603053 | EG_Produktion_FFB | B - SL_KK
8603056 | EG_Produktion_FFB | B - SL_KK
8603065 | EG_Produktion_FFB | B - SL_KK
8603068 | EG_Produktion_FFB | B - SL_KK
8603071 | EG_Produktion_FFB | B - SL_KK
8603077 | EG_Produktion_FFB | B - SL_KK
8603081 | EG_Produktion_FFB | B - SL_KK
8603086 | EG_Produktion_FFB | B - SL_KK
8603090 | EG_Produktion_FFB | B - SL_KK
8603099 | EG_Produktion_FFB | B - SL_KK
8603102 | EG_Produktion_FFB | B - SL_KK
8603104 | EG_Produktion_FFB | B - SL_KK
8603110 | EG_Produktion_FFB | A - SL_NK-Str.01
8603114 | EG_Produktion_FFB | A - SL_NK-Str.01
8603121 | EG_Produktion_FFB | B - SL_NK-Str.01
8603143 | EG_Produktion_FFB | B - SL_TK
8603148 | EG_Produktion_FFB | A - SL_TK
8603153 | EG_Produktion_FFB | B - SL_TK
8603156 | EG_Produktion_FFB | B - SL_TK
8603159 | EG_Produktion_FFB | B - SL_TK
8603168 | EG_Produktion_FFB | A - SL_TK
8603174 | EG_Produktion_FFB | A - SL_TK
8603183 | EG_Produktion_FFB | B - SL_NK-Str.01
8603186 | EG_Produktion_FFB | A - SL_NK-Str.01
8603189 | EG_Produktion_FFB | A - SL_TK
8603195 | EG_Produktion_FFB | A - SL_TK
8603204 | EG_Produktion_FFB | B - SL_TK
8603207 | EG_Produktion_FFB | B - SL_TK
8603210 | EG_Produktion_FFB | B - SL_TK
8603219 | EG_Produktion_FFB | A - SL_NK-Str.01
8603222 | EG_Produktion_FFB | B - SL_NK-Str.01
8603225 | EG_Produktion_FFB | A - SL_NK-Str.01
8603236 | EG_Produktion_FFB | A - SL_NK-Str.01
8603243 | EG_Produktion_FFB | B - SL_NK-Str.01
8603259 | EG_Produktion_FFB | B - SL_NK-Str.01
8603264 | EG_Produktion_FFB | A - SL_NK-Str.01
8603270 | EG_Produktion_FFB | B - SL_NK-Str.01
8603286 | EG_Produktion_FFB | B - SL_NK-Str.01
8603289 | EG_Produktion_FFB | B - SL_NK-Str.01
8603294 | EG_Produktion_FFB | A - SL_NK-Str.01
8603297 | EG_Produktion_FFB | A - SL_NK-Str.01
8603309 | EG_Produktion_FFB | B - SL_NK-Str.01
8603312 | EG_Produktion_FFB | B - SL_NK-Str.01
8603315 | EG_Produktion_FFB | B - SL_NK-Str.01
8603318 | EG_Produktion_FFB | A - SL_NK-Str.01
8603321 | EG_Produktion_FFB | A - SL_NK-Str.01
8603324 | EG_Produktion_FFB | A - SL_NK-Str.01
8603342 | EG_Produktion_FFB | A - SL_NK-Str.01
8603354 | EG_Produktion_FFB | B - SL_NK-Str.01
8603864 | EG_Produktion_FFB | A - FL-Str.02_NK-KK-TK
8603926 | EG_Produktion_FFB | B - FL-Str.02_NK-KK-TK
8603957 | EG_Produktion_FFB | B - SL_KK
8603994 | EG_Produktion_FFB | B - FL-Str.01_NK-KK-TK
8604031 | EG_Produktion_FFB | A - SL_KK
8604068 | EG_Produktion_FFB | A - FL-Str.01_NK-KK-TK
8604266 | EG_Produktion_FFB | A - FL-Str.01_NK-KK-TK
8604293 | EG_Produktion_FFB | A - SL_KK
8604366 | EG_Produktion_FFB | B - FL-Str.01_NK-KK-TK
8604450 | EG_Produktion_FFB | B - FL-Str.01_NK-KK-TK
8604477 | EG_Produktion_FFB | B - SL_KK
8604544 | EG_Produktion_FFB | A - SL_KK
8604571 | EG_Produktion_FFB | A - FL-Str.01_NK-KK-TK
8604598 | EG_Produktion_FFB | B - SL_KK
8604645 | EG_Produktion_FFB | B - FL-Str.02_NK-KK-TK
8604698 | EG_Produktion_FFB | B - SL_KK
8604745 | EG_Produktion_FFB | A - SL_KK
8604814 | EG_Produktion_FFB | A - FL-Str.01_NK-KK-TK
8604944 | EG_Produktion_FFB | A - SL_NK-Str.01
8605017 | EG_Produktion_FFB | B - FL-Str.01_NK-KK-TK
8605070 | EG_Produktion_FFB | B - SL_NK-Str.01
8605149 | EG_Produktion_FFB | A - FL-Str.02_NK-KK-TK
8605202 | EG_Produktion_FFB | B - SL_KK
8605260 | EG_Produktion_FFB | B - FL-Str.01_NK-KK-TK
8605352 | EG_Produktion_FFB | B - FL-Str.01_NK-KK-TK
8605384 | EG_Produktion_FFB | B - SL_KK
8605476 | EG_Produktion_FFB | A - FL-Str.01_NK-KK-TK
8605508 | EG_Produktion_FFB | A - SL_KK
8605670 | EG_Produktion_FFB | A - FL-Str.01_NK-KK-TK
8605702 | EG_Produktion_FFB | A - SL_KK
8605834 | EG_Produktion_FFB | B - SL_KK
8605861 | EG_Produktion_FFB | B - FL-Str.01_NK-KK-TK
8605888 | EG_Produktion_FFB | B - SL_KK
8605915 | EG_Produktion_FFB | B - FL-Str.01_NK-KK-TK
8606002 | EG_Produktion_FFB | A - SL_KK
8606029 | EG_Produktion_FFB | A - FL-Str.01_NK-KK-TK
8606106 | EG_Produktion_FFB | B - FL-Str.01_NK-KK-TK
8606172 | EG_Produktion_FFB | B - SL_KK
8606239 | EG_Produktion_FFB | B - SL_KK
8606266 | EG_Produktion_FFB | B - FL-Str.01_NK-KK-TK
8606353 | EG_Produktion_FFB | A - FL-Str.01_NK-KK-TK
8606380 | EG_Produktion_FFB | A - SL_KK
8606487 | EG_Produktion_FFB | B - SL_KK
8606514 | EG_Produktion_FFB | B - FL-Str.01_NK-KK-TK
8606541 | EG_Produktion_FFB | A - SL_KK
8606568 | EG_Produktion_FFB | A - FL-Str.01_NK-KK-TK
8606696 | EG_Produktion_FFB | A - SL_KK
8606699 | EG_Produktion_FFB | A - FL-Str.01_NK-KK-TK
8606889 | EG_Produktion_FFB | A - FL-Str.01_NK-KK-TK
8606940 | EG_Produktion_FFB | A - SL_KK
8606994 | EG_Produktion_FFB | A - FL-Str.01_NK-KK-TK
8607185 | EG_Produktion_FFB | A - FL-Str.03_NK-KK-TK
8607252 | EG_Produktion_FFB | B - FL-Str.03_NK-KK-TK
8607296 | EG_Produktion_FFB | B - SL_NK-Str.02
8607367 | EG_Produktion_FFB | B - FL-Str.03_NK-KK-TK
8607511 | EG_Produktion_FFB | B - SL_NK-Str.02
8607568 | EG_Produktion_FFB | B - FL-Str.03_NK-KK-TK
8607625 | EG_Produktion_FFB | A - SL_NK-Str.02
8607682 | EG_Produktion_FFB | A - FL-Str.03_NK-KK-TK
8607829 | EG_Produktion_FFB | A - SL_NK-Str.02
8607856 | EG_Produktion_FFB | A - FL-Str.03_NK-KK-TK
8607883 | EG_Produktion_FFB | B - SL_NK-Str.02
8607910 | EG_Produktion_FFB | B - FL-Str.03_NK-KK-TK
8608063 | EG_Produktion_FFB | B - FL-Str.03_NK-KK-TK
8608090 | EG_Produktion_FFB | B - SL_NK-Str.02
8608117 | EG_Produktion_FFB | A - SL_NK-Str.02
8608144 | EG_Produktion_FFB | A - FL-Str.03_NK-KK-TK
8608231 | EG_Produktion_FFB | B - SL_NK-Str.02
8608275 | EG_Produktion_FFB | B - FL-Str.03_NK-KK-TK
8608336 | EG_Produktion_FFB | A - SL_NK-Str.02
8608399 | EG_Produktion_FFB | A - SL_NK-Str.02
8608465 | EG_Produktion_FFB | A - SL_NK-Str.02
8608633 | EG_Produktion_FFB | A - FL-Str.03_NK-KK-TK
8608660 | EG_Produktion_FFB | A - FL-Str.03_NK-KK-TK
8608766 | EG_Produktion_FFB | B - SL_NK-Str.02
8608801 | EG_Produktion_FFB | B - FL-Str.03_NK-KK-TK
8608904 | EG_Produktion_FFB | B - FL-Str.03_NK-KK-TK
8608941 | EG_Produktion_FFB | B - SL_NK-Str.02
8609151 | EG_Produktion_FFB | A - SL_NK-Str.01
8609184 | EG_Produktion_FFB | A - FL-Str.02_NK-KK-TK
8609356 | EG_Produktion_FFB | B - SL_TK
8609383 | EG_Produktion_FFB | B - SL_NK-Str.01
8609416 | EG_Produktion_FFB | B - FL-Str.02_NK-KK-TK
8609448 | EG_Produktion_FFB | B - FL-Str.02_NK-KK-TK
8609515 | EG_Produktion_FFB | A - FL-Str.02_NK-KK-TK
8609544 | EG_Produktion_FFB | A - SL_NK-Str.01
8609724 | EG_Produktion_FFB | B - FL-Str.02_NK-KK-TK
8609757 | EG_Produktion_FFB | B - SL_TK
8609790 | EG_Produktion_FFB | B - SL_NK-Str.01
8609857 | EG_Produktion_FFB | A - SL_TK
8609932 | EG_Produktion_FFB | A - FL-Str.02_NK-KK-TK
8610025 | EG_Produktion_FFB | A - SL_NK-Str.01
8610052 | EG_Produktion_FFB | A - FL-Str.02_NK-KK-TK
8610103 | EG_Produktion_FFB | B - SL_TK
8610184 | EG_Produktion_FFB | B - FL-Str.02_NK-KK-TK
8610337 | EG_Produktion_FFB | A - SL_NK-Str.01
8610364 | EG_Produktion_FFB | A - FL-Str.02_NK-KK-TK
8610397 | EG_Produktion_FFB | A - SL_TK
8610430 | EG_Produktion_FFB | A - FL-Str.02_NK-KK-TK
8610457 | EG_Produktion_FFB | A - SL_NK-Str.01
8610544 | EG_Produktion_FFB | B - FL-Str.02_NK-KK-TK
8610571 | EG_Produktion_FFB | B - SL_NK-Str.01
8610976 | EG_Produktion_FFB | A - FL-Str.02_NK-KK-TK
8610985 | EG_Produktion_FFB | A - SL_NK-Str.01
8610993 | EG_Produktion_FFB | A - FL-Str.02_NK-KK-TK
8610996 | EG_Produktion_FFB | A - FL-Str.02_NK-KK-TK
8611000 | EG_Produktion_FFB | B - FL-Str.02_NK-KK-TK
8611002 | EG_Produktion_FFB | B - FL-Str.02_NK-KK-TK
8611008 | EG_Produktion_FFB | B - FL-Str.02_NK-KK-TK
8611011 | EG_Produktion_FFB | A - SL_NK-Str.01
8611013 | EG_Produktion_FFB | A - SL_NK-Str.01
8611016 | EG_Produktion_FFB | A - SL_NK-Str.01
8611020 | EG_Produktion_FFB | B - SL_NK-Str.01
8611022 | EG_Produktion_FFB | B - SL_NK-Str.01
8611025 | EG_Produktion_FFB | B - SL_NK-Str.01
8611029 | EG_Produktion_FFB | A - SL_NK-Str.01
8611032 | EG_Produktion_FFB | A - SL_NK-Str.01
8611045 | EG_Produktion_FFB | B - SL_NK-Str.01
8611051 | EG_Produktion_FFB | A - SL_NK-Str.01
8611173 | EG_Produktion_FFB | A - FL-Str.02_NK-KK-TK
8611176 | EG_Produktion_FFB | A - FL-Str.02_NK-KK-TK
8611210 | EG_Produktion_FFB | A - SL_NK-Str.01
8611213 | EG_Produktion_FFB | A - SL_NK-Str.01
8611320 | EG_Produktion_FFB | A - SL_NK-Str.01
8611407 | EG_Produktion_FFB | B - FL-Str.02_NK-KK-TK
8611451 | EG_Produktion_FFB | B - SL_NK-Str.01
8611478 | EG_Produktion_FFB | B - SL_NK-Str.01
8611525 | EG_Produktion_FFB | B - SL_NK-Str.01
8611575 | EG_Produktion_FFB | B - SL_KK
8611628 | EG_Produktion_FFB | A - SL_KK
8611683 | EG_Produktion_FFB | A - FL-Str.01_NK-KK-TK
8611750 | EG_Produktion_FFB | B - FL-Str.01_NK-KK-TK
8611817 | EG_Produktion_FFB | A - FL-Str.01_NK-KK-TK
8611866 | EG_Produktion_FFB | A - FL-Str.01_NK-KK-TK
8611931 | EG_Produktion_FFB | B - FL-Str.01_NK-KK-TK
8611980 | EG_Produktion_FFB | B - FL-Str.01_NK-KK-TK
8612143 | EG_Produktion_FFB | B - FL-Str.02_NK-KK-TK
8612146 | EG_Produktion_FFB | B - FL-Str.02_NK-KK-TK
8612293 | EG_Produktion_FFB | B - SL_NK-Str.01
8612296 | EG_Produktion_FFB | B - SL_NK-Str.01
8612429 | EG_Produktion_FFB | A - SL_NK-Str.01
8612432 | EG_Produktion_FFB | A - SL_NK-Str.01
8612502 | EG_Produktion_FFB | A - FL-Str.02_NK-KK-TK
8612505 | EG_Produktion_FFB | A - FL-Str.02_NK-KK-TK
8613124 | EG_Produktion_FFB | B - SL_NK-Str.01
8613189 | EG_Produktion_FFB | B - SL_NK-Str.01
8613334 | EG_Produktion_FFB | B - SL_NK-Str.01
8613388 | EG_Produktion_FFB | A - SL_NK-Str.01
8613485 | EG_Produktion_FFB | B - SL_NK-Str.01
8613689 | EG_Produktion_FFB | B - SL_NK-Str.01
8613692 | EG_Produktion_FFB | B - SL_NK-Str.01
8613734 | EG_Produktion_FFB | B - FL-Str.02_NK-KK-TK
8613737 | EG_Produktion_FFB | B - FL-Str.02_NK-KK-TK
8613855 | EG_Produktion_FFB | B - SL_NK-Str.01
8614004 | EG_Produktion_FFB | B - FL-Str.02_NK-KK-TK
8614428 | EG_Produktion_FFB | A - FL-Str.02_NK-KK-TK
8614468 | EG_Produktion_FFB | A - SL_NK-Str.01
8614490 | EG_Produktion_FFB | B - FL-Str.02_NK-KK-TK
8614603 | EG_Produktion_FFB | B - SL_NK-Str.01
8614632 | EG_Produktion_FFB | A - FL-Str.02_NK-KK-TK
8614671 | EG_Produktion_FFB | A - SL_NK-Str.01
8614846 | EG_Produktion_FFB | B - FL-Str.02_NK-KK-TK
8614848 | EG_Produktion_FFB | A - FL-Str.02_NK-KK-TK
8614852 | EG_Produktion_FFB | B - SL_NK-Str.01
8614854 | EG_Produktion_FFB | A - SL_NK-Str.01
8614883 | EG_Produktion_FFB | B - FL-Str.02_NK-KK-TK
8614928 | EG_Produktion_FFB | B - SL_NK-Str.01
8614976 | EG_Produktion_FFB | A - SL_NK-Str.01
8615024 | EG_Produktion_FFB | A - FL-Str.02_NK-KK-TK
8615449 | EG_Produktion_FFB | A - SL_TK
8615570 | EG_Produktion_FFB | A - SL_TK
8615573 | EG_Produktion_FFB | A - SL_TK
8616180 | EG_Produktion_FFB | A - SL_KK
8616638 | EG_Produktion_FFB | B - FL-Str.01_NK-KK-TK
8616690 | EG_Produktion_FFB | B - SL_KK
8616827 | EG_Produktion_FFB | B - FL-Str.01_NK-KK-TK
8616830 | EG_Produktion_FFB | B - SL_KK
8617131 | EG_Produktion_FFB | B - FL-Str.01_NK-KK-TK
8617134 | EG_Produktion_FFB | B - SL_KK
8617386 | EG_Produktion_FFB | B - FL-Str.01_NK-KK-TK
8617389 | EG_Produktion_FFB | B - SL_KK
8617764 | EG_Produktion_FFB | A - SL_KK
8617805 | EG_Produktion_FFB | A - FL-Str.01_NK-KK-TK
8617863 | EG_Produktion_FFB | A - FL-Str.01_NK-KK-TK
8617866 | EG_Produktion_FFB | A - FL-Str.01_NK-KK-TK
8617899 | EG_Produktion_FFB | A - SL_KK
8617902 | EG_Produktion_FFB | A - SL_KK
8618017 | EG_Produktion_FFB | A - FL-Str.01_NK-KK-TK
8618020 | EG_Produktion_FFB | A - FL-Str.01_NK-KK-TK
8618064 | EG_Produktion_FFB | A - SL_NK-Str.01
8618067 | EG_Produktion_FFB | A - SL_NK-Str.01
8618198 | EG_Produktion_FFB | B - SL_NK-Str.01
8618201 | EG_Produktion_FFB | B - SL_NK-Str.01
8618242 | EG_Produktion_FFB | B - FL-Str.01_NK-KK-TK
8618245 | EG_Produktion_FFB | B - FL-Str.01_NK-KK-TK
8618365 | EG_Produktion_FFB | A - FL-Str.02_NK-KK-TK
8618600 | EG_Produktion_FFB | B - SL_KK
8618620 | EG_Produktion_FFB | B - FL-Str.01_NK-KK-TK
8618681 | EG_Produktion_FFB | B - SL_KK
8618684 | EG_Produktion_FFB | B - FL-Str.01_NK-KK-TK
8618788 | EG_Produktion_FFB | B - FL-Str.01_NK-KK-TK
8618791 | EG_Produktion_FFB | B - SL_KK
8619062 | EG_Produktion_FFB | B - FL-Str.01_NK-KK-TK
8619092 | EG_Produktion_FFB | B - SL_KK
8619117 | EG_Produktion_FFB | A - FL-Str.01_NK-KK-TK
8619120 | EG_Produktion_FFB | A - SL_KK
8619136 | EG_Produktion_FFB | B - FL-Str.01_NK-KK-TK
8619139 | EG_Produktion_FFB | B - SL_KK
8619153 | EG_Produktion_FFB | A - FL-Str.01_NK-KK-TK
8619156 | EG_Produktion_FFB | A - SL_KK
8619170 | EG_Produktion_FFB | B - FL-Str.01_NK-KK-TK
8619173 | EG_Produktion_FFB | B - SL_KK
8619273 | EG_Produktion_FFB | A - FL-Str.01_NK-KK-TK
8619311 | EG_Produktion_FFB | A - SL_KK
8619379 | EG_Produktion_FFB | B - FL-Str.01_NK-KK-TK
8619416 | EG_Produktion_FFB | B - SL_KK
8619452 | EG_Produktion_FFB | A - FL-Str.01_NK-KK-TK
8619455 | EG_Produktion_FFB | A - SL_KK
8619519 | EG_Produktion_FFB | A - FL-Str.01_NK-KK-TK
8619549 | EG_Produktion_FFB | A - SL_KK
8619659 | EG_Produktion_FFB | B - FL-Str.01_NK-KK-TK
8619709 | EG_Produktion_FFB | B - SL_KK
8619769 | EG_Produktion_FFB | A - FL-Str.01_NK-KK-TK
8619807 | EG_Produktion_FFB | A - SL_KK
8619888 | EG_Produktion_FFB | B - SL_KK
8619919 | EG_Produktion_FFB | B - FL-Str.01_NK-KK-TK
8619947 | EG_Produktion_FFB | B - FL-Str.01_NK-KK-TK
8619950 | EG_Produktion_FFB | B - SL_KK
8619968 | EG_Produktion_FFB | A - FL-Str.01_NK-KK-TK
8619971 | EG_Produktion_FFB | A - SL_KK
8619993 | EG_Produktion_FFB | B - FL-Str.01_NK-KK-TK
8619996 | EG_Produktion_FFB | B - SL_KK
8620086 | EG_Produktion_FFB | B - SL_KK
8620139 | EG_Produktion_FFB | B - FL-Str.01_NK-KK-TK
8620224 | EG_Produktion_FFB | A - SL_KK
8620262 | EG_Produktion_FFB | A - FL-Str.01_NK-KK-TK
8620363 | EG_Produktion_FFB | B - FL-Str.01_NK-KK-TK
8620399 | EG_Produktion_FFB | B - SL_KK
8620446 | EG_Produktion_FFB | A - FL-Str.01_NK-KK-TK
8620507 | EG_Produktion_FFB | A - SL_KK
8620546 | EG_Produktion_FFB | A - FL-Str.01_NK-KK-TK
8620637 | EG_Produktion_FFB | A - FL-Str.01_NK-KK-TK
8620640 | EG_Produktion_FFB | A - SL_KK
8620704 | EG_Produktion_FFB | A - SL_KK
8620740 | EG_Produktion_FFB | A - FL-Str.01_NK-KK-TK
8620775 | EG_Produktion_FFB | A - FL-Str.01_NK-KK-TK
8620778 | EG_Produktion_FFB | A - SL_KK
8620792 | EG_Produktion_FFB | B - SL_KK
8620795 | EG_Produktion_FFB | B - FL-Str.01_NK-KK-TK
8620898 | EG_Produktion_FFB | A - FL-Str.01_NK-KK-TK
8620933 | EG_Produktion_FFB | A - SL_KK
8621003 | EG_Produktion_FFB | B - SL_KK
8621006 | EG_Produktion_FFB | B - FL-Str.01_NK-KK-TK
8621141 | EG_Produktion_FFB | B - SL_KK
8621179 | EG_Produktion_FFB | B - FL-Str.01_NK-KK-TK
8621264 | EG_Produktion_FFB | A - SL_NK-Str.02
8621267 | EG_Produktion_FFB | A - FL-Str.03_NK-KK-TK
8621301 | EG_Produktion_FFB | A - SL_NK-Str.02
8621304 | EG_Produktion_FFB | A - FL-Str.03_NK-KK-TK
8621320 | EG_Produktion_FFB | A - SL_NK-Str.02
8621323 | EG_Produktion_FFB | A - FL-Str.03_NK-KK-TK
8621341 | EG_Produktion_FFB | A - FL-Str.03_NK-KK-TK
8621344 | EG_Produktion_FFB | A - SL_NK-Str.02
8621358 | EG_Produktion_FFB | A - SL_NK-Str.01
8621361 | EG_Produktion_FFB | A - FL-Str.03_NK-KK-TK
8621377 | EG_Produktion_FFB | A - SL_NK-Str.01
8621380 | EG_Produktion_FFB | A - FL-Str.03_NK-KK-TK
8621394 | EG_Produktion_FFB | B - FL-Str.03_NK-KK-TK
8621397 | EG_Produktion_FFB | B - SL_NK-Str.01
8621411 | EG_Produktion_FFB | B - FL-Str.03_NK-KK-TK
8621414 | EG_Produktion_FFB | B - SL_NK-Str.01
8621432 | EG_Produktion_FFB | B - FL-Str.03_NK-KK-TK
8621435 | EG_Produktion_FFB | B - SL_NK-Str.02
8621451 | EG_Produktion_FFB | B - SL_NK-Str.02
8621454 | EG_Produktion_FFB | B - FL-Str.03_NK-KK-TK
8621472 | EG_Produktion_FFB | B - FL-Str.03_NK-KK-TK
8621475 | EG_Produktion_FFB | B - SL_NK-Str.02
8621489 | EG_Produktion_FFB | B - FL-Str.03_NK-KK-TK
8621492 | EG_Produktion_FFB | B - SL_NK-Str.02
8621506 | EG_Produktion_FFB | B - FL-Str.03_NK-KK-TK
8621509 | EG_Produktion_FFB | B - SL_NK-Str.02
8621607 | EG_Produktion_FFB | B - SL_NK-Str.02
8621682 | EG_Produktion_FFB | B - FL-Str.03_NK-KK-TK
8621791 | EG_Produktion_FFB | B - FL-Str.03_NK-KK-TK
8621837 | EG_Produktion_FFB | B - SL_NK-Str.02
8621932 | EG_Produktion_FFB | B - FL-Str.03_NK-KK-TK
8621978 | EG_Produktion_FFB | B - SL_NK-Str.02
8622042 | EG_Produktion_FFB | B - SL_NK-Str.02
8622045 | EG_Produktion_FFB | B - FL-Str.03_NK-KK-TK
8622277 | EG_Produktion_FFB | B - FL-Str.03_NK-KK-TK
8622321 | EG_Produktion_FFB | B - SL_NK-Str.02
8622595 | EG_Produktion_FFB | A - FL-Str.03_NK-KK-TK
8622634 | EG_Produktion_FFB | A - SL_NK-Str.02
8622727 | EG_Produktion_FFB | A - FL-Str.03_NK-KK-TK
8622766 | EG_Produktion_FFB | A - SL_NK-Str.02
8622859 | EG_Produktion_FFB | A - SL_NK-Str.02
8622898 | EG_Produktion_FFB | A - FL-Str.03_NK-KK-TK
8623216 | EG_Produktion_FFB | A - FL-Str.03_NK-KK-TK
8623289 | EG_Produktion_FFB | A - SL_NK-Str.01
8623383 | EG_Produktion_FFB | A - FL-Str.03_NK-KK-TK
8623422 | EG_Produktion_FFB | A - SL_NK-Str.01
8623538 | EG_Produktion_FFB | B - FL-Str.03_NK-KK-TK
8623541 | EG_Produktion_FFB | B - SL_NK-Str.01
8623650 | EG_Produktion_FFB | B - FL-Str.03_NK-KK-TK
8623696 | EG_Produktion_FFB | B - SL_NK-Str.01
8623855 | EG_Produktion_FFB | B - SL_NK-Str.01
8623893 | EG_Produktion_FFB | B - FL-Str.03_NK-KK-TK
8623985 | EG_Produktion_FFB | B - SL_NK-Str.02
8624023 | EG_Produktion_FFB | B - FL-Str.03_NK-KK-TK
8624134 | EG_Produktion_FFB | A - SL_NK-Str.01
8624266 | EG_Produktion_FFB | B - SL_NK-Str.01
8624369 | EG_Produktion_FFB | B - SL_NK-Str.01
8624489 | EG_Produktion_FFB | B - FL-Str.02_NK-KK-TK
8624491 | EG_Produktion_FFB | B - SL_NK-Str.02
8624658 | EG_Produktion_FFB | B - FL-Str.02_NK-KK-TK
8624660 | EG_Produktion_FFB | B - SL_NK-Str.02
8624677 | EG_Produktion_FFB | B - SL_NK-Str.02
8624679 | EG_Produktion_FFB | B - FL-Str.03_NK-KK-TK
8624694 | EG_Produktion_FFB | A - SL_NK-Str.02
8624696 | EG_Produktion_FFB | A - FL-Str.03_NK-KK-TK
8624711 | EG_Produktion_FFB | A - SL_NK-Str.02
8624713 | EG_Produktion_FFB | A - FL-Str.03_NK-KK-TK
8624824 | EG_Produktion_FFB | A - SL_NK-Str.02
8624865 | EG_Produktion_FFB | A - FL-Str.03_NK-KK-TK
8624952 | EG_Produktion_FFB | A - FL-Str.03_NK-KK-TK
8625010 | EG_Produktion_FFB | A - SL_NK-Str.02
8625076 | EG_Produktion_FFB | B - SL_NK-Str.02
8625134 | EG_Produktion_FFB | B - FL-Str.03_NK-KK-TK
8625251 | EG_Produktion_FFB | B - FL-Str.02_NK-KK-TK
8625291 | EG_Produktion_FFB | B - SL_NK-Str.02
8625395 | EG_Produktion_FFB | B - SL_NK-Str.02
8625435 | EG_Produktion_FFB | B - FL-Str.02_NK-KK-TK
8625869 | EG_Produktion_FFB | B - SL_NK-Str.02
8625982 | EG_Produktion_FFB | A - SL_NK-Str.02
8625984 | EG_Produktion_FFB | A - FL-Str.02_NK-KK-TK
8626133 | EG_Produktion_FFB | A - FL-Str.02_NK-KK-TK
8626173 | EG_Produktion_FFB | A - SL_NK-Str.02
8626218 | EG_Produktion_FFB | A - SL_NK-Str.02
8626220 | EG_Produktion_FFB | A - FL-Str.02_NK-KK-TK
8626285 | EG_Produktion_FFB | A - SL_NK-Str.02
8626309 | EG_Produktion_FFB | A - SL_NK-Str.02
8626349 | EG_Produktion_FFB | A - FL-Str.02_NK-KK-TK
8626500 | EG_Produktion_FFB | A - FL-Str.03_NK-KK-TK
8626503 | EG_Produktion_FFB | A - SL_NK-Str.02
8626662 | EG_Produktion_FFB | A - SL_NK-Str.02
8626708 | EG_Produktion_FFB | A - FL-Str.03_NK-KK-TK
8626888 | EG_Produktion_FFB | B - SL_TK
8626890 | EG_Produktion_FFB | B - FL-Str.02_NK-KK-TK
8627037 | EG_Produktion_FFB | B - FL-Str.02_NK-KK-TK
8627082 | EG_Produktion_FFB | B - SL_TK
8627147 | EG_Produktion_FFB | B - FL-Str.02_NK-KK-TK
8627150 | EG_Produktion_FFB | B - FL-Str.02_NK-KK-TK
8627193 | EG_Produktion_FFB | B - SL_TK
8627196 | EG_Produktion_FFB | B - SL_TK
8627290 | EG_Produktion_FFB | A - SL_TK
8627336 | EG_Produktion_FFB | A - FL-Str.02_NK-KK-TK
8627537 | EG_Produktion_FFB | B - FL-Str.02_NK-KK-TK
8627540 | EG_Produktion_FFB | B - FL-Str.02_NK-KK-TK
8627621 | EG_Produktion_FFB | B - SL_NK-Str.01
8627680 | EG_Produktion_FFB | B - FL-Str.01_NK-KK-TK
8627683 | EG_Produktion_FFB | B - SL_KK
8627796 | EG_Produktion_FFB | B - SL_KK
8627834 | EG_Produktion_FFB | B - FL-Str.01_NK-KK-TK
8628220 | EG_Produktion_FFB | B - SL_KK
8628222 | EG_Produktion_FFB | B - FL-Str.01_NK-KK-TK
8628371 | EG_Produktion_FFB | B - FL-Str.01_NK-KK-TK
8628405 | EG_Produktion_FFB | B - SL_KK
8628536 | EG_Produktion_FFB | B - SL_KK
8628539 | EG_Produktion_FFB | B - SL_KK
8628681 | EG_Produktion_FFB | B - FL-Str.01_NK-KK-TK
8628684 | EG_Produktion_FFB | B - FL-Str.01_NK-KK-TK
8628792 | EG_Produktion_FFB | A - SL_KK
8628795 | EG_Produktion_FFB | A - SL_KK
8628845 | EG_Produktion_FFB | A - FL-Str.01_NK-KK-TK
8628848 | EG_Produktion_FFB | A - FL-Str.01_NK-KK-TK
8629105 | EG_Produktion_FFB | B - SL_KK
8629108 | EG_Produktion_FFB | B - SL_KK
8629145 | EG_Produktion_FFB | B - FL-Str.01_NK-KK-TK
8629148 | EG_Produktion_FFB | B - FL-Str.01_NK-KK-TK
8629233 | EG_Produktion_FFB | B - SL_KK
8629236 | EG_Produktion_FFB | B - FL-Str.01_NK-KK-TK
8629302 | EG_Produktion_FFB | B - FL-Str.01_NK-KK-TK
8629338 | EG_Produktion_FFB | B - SL_KK
8629655 | EG_Produktion_FFB | B - FL-Str.02_NK-KK-TK
8629658 | EG_Produktion_FFB | B - FL-Str.02_NK-KK-TK
8629699 | EG_Produktion_FFB | B - SL_TK
8629702 | EG_Produktion_FFB | B - SL_TK
8629746 | EG_Produktion_FFB | A - FL-Str.02_NK-KK-TK
8629748 | EG_Produktion_FFB | A - SL_TK
8629828 | EG_Produktion_FFB | A - SL_TK
8629831 | EG_Produktion_FFB | A - SL_TK
8629872 | EG_Produktion_FFB | A - FL-Str.02_NK-KK-TK
8629875 | EG_Produktion_FFB | A - FL-Str.02_NK-KK-TK
8629948 | EG_Produktion_FFB | A - FL-Str.02_NK-KK-TK
8629950 | EG_Produktion_FFB | A - SL_TK
8630041 | EG_Produktion_FFB | A - SL_TK
8630044 | EG_Produktion_FFB | A - SL_TK
8630085 | EG_Produktion_FFB | A - FL-Str.02_NK-KK-TK
8630088 | EG_Produktion_FFB | A - FL-Str.02_NK-KK-TK
8630295 | EG_Produktion_FFB | B - SL_KK
8630335 | EG_Produktion_FFB | B - SL_KK
8630543 | EG_Produktion_FFB | A - SL_KK
8630613 | EG_Produktion_FFB | A - FL-Str.02_NK-KK-TK
8630841 | EG_Produktion_FFB | A - SL_KK
8630872 | EG_Produktion_FFB | A - FL-Str.02_NK-KK-TK
8630991 | EG_Produktion_FFB | A - SL_KK
8631023 | EG_Produktion_FFB | A - FL-Str.02_NK-KK-TK
8631107 | EG_Produktion_FFB | B - SL_KK
8631138 | EG_Produktion_FFB | B - SL_KK
8631173 | EG_Produktion_FFB | B - FL-Str.01_NK-KK-TK
8631176 | EG_Produktion_FFB | B - SL_NK-Str.01
8631251 | EG_Produktion_FFB | B - FL-Str.01_NK-KK-TK
8631302 | EG_Produktion_FFB | B - SL_NK-Str.01
8631348 | EG_Produktion_FFB | B - FL-Str.01_NK-KK-TK
8631351 | EG_Produktion_FFB | B - SL_NK-Str.01
8631371 | EG_Produktion_FFB | B - FL-Str.01_NK-KK-TK
8631374 | EG_Produktion_FFB | B - SL_NK-Str.01
8631388 | EG_Produktion_FFB | A - SL_NK-Str.01
8631391 | EG_Produktion_FFB | A - FL-Str.01_NK-KK-TK
8631415 | EG_Produktion_FFB | A - FL-Str.01_NK-KK-TK
8631418 | EG_Produktion_FFB | A - SL_NK-Str.01
8631434 | EG_Produktion_FFB | A - SL_NK-Str.01
8631437 | EG_Produktion_FFB | A - FL-Str.01_NK-KK-TK
8631542 | EG_Produktion_FFB | A - SL_NK-Str.01
8631592 | EG_Produktion_FFB | A - FL-Str.01_NK-KK-TK
8631700 | EG_Produktion_FFB | A - FL-Str.01_NK-KK-TK
8631751 | EG_Produktion_FFB | A - SL_NK-Str.01
8631900 | EG_Produktion_FFB | A - SL_NK-Str.01
8631942 | EG_Produktion_FFB | A - FL-Str.01_NK-KK-TK
8632066 | EG_Produktion_FFB | B - FL-Str.01_NK-KK-TK
8632116 | EG_Produktion_FFB | B - SL_NK-Str.01
8632251 | EG_Produktion_FFB | B - FL-Str.01_NK-KK-TK
8632292 | EG_Produktion_FFB | B - SL_NK-Str.01
8632410 | EG_Produktion_FFB | A - FL-Str.02_NK-KK-TK
8632413 | EG_Produktion_FFB | A - SL_NK-Str.01
8632427 | EG_Produktion_FFB | B - FL-Str.02_NK-KK-TK
8632430 | EG_Produktion_FFB | B - SL_NK-Str.01
8632537 | EG_Produktion_FFB | B - FL-Str.02_NK-KK-TK
8632584 | EG_Produktion_FFB | B - SL_NK-Str.01
8632693 | EG_Produktion_FFB | A - SL_NK-Str.01
8632696 | EG_Produktion_FFB | A - FL-Str.02_NK-KK-TK
8632782 | EG_Produktion_FFB | A - FL-Str.02_NK-KK-TK
8632828 | EG_Produktion_FFB | A - SL_NK-Str.01
8632865 | EG_Produktion_FFB | B - SL_NK-Str.01
8632868 | EG_Produktion_FFB | B - FL-Str.02_NK-KK-TK
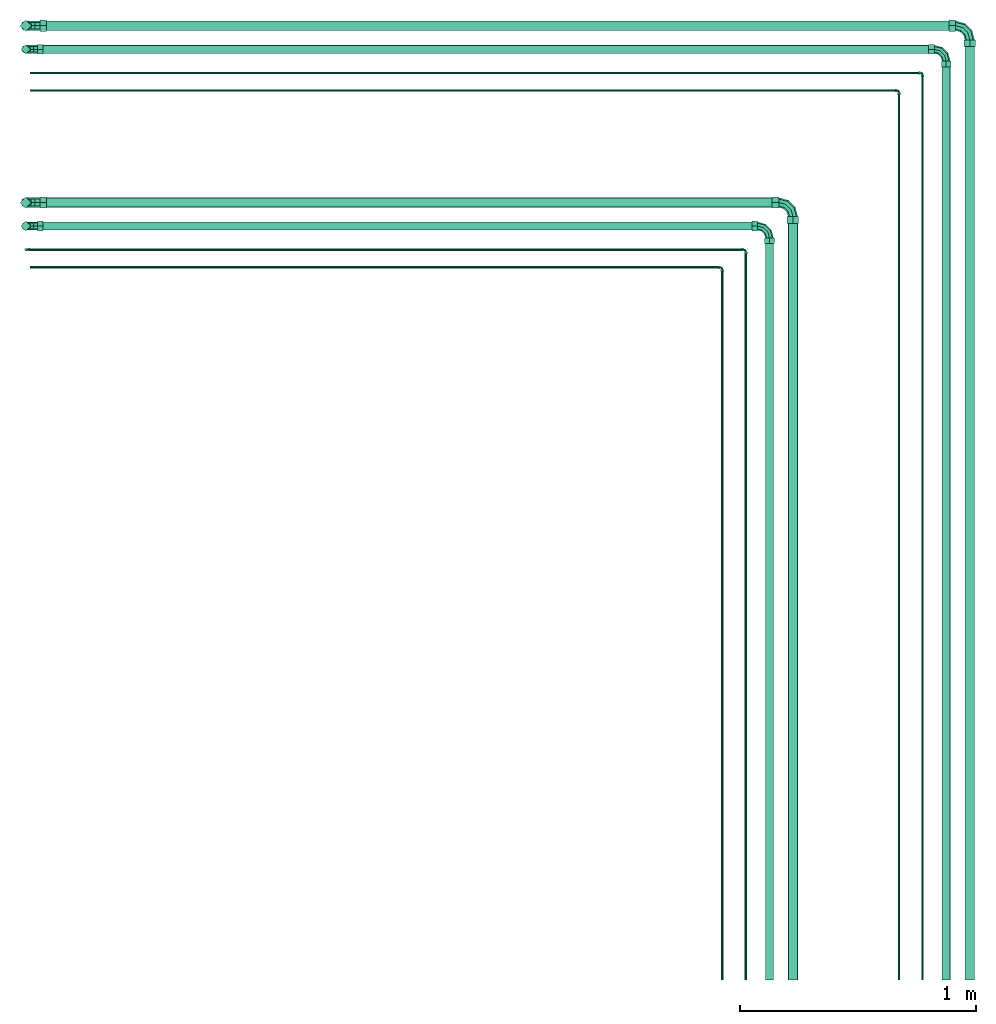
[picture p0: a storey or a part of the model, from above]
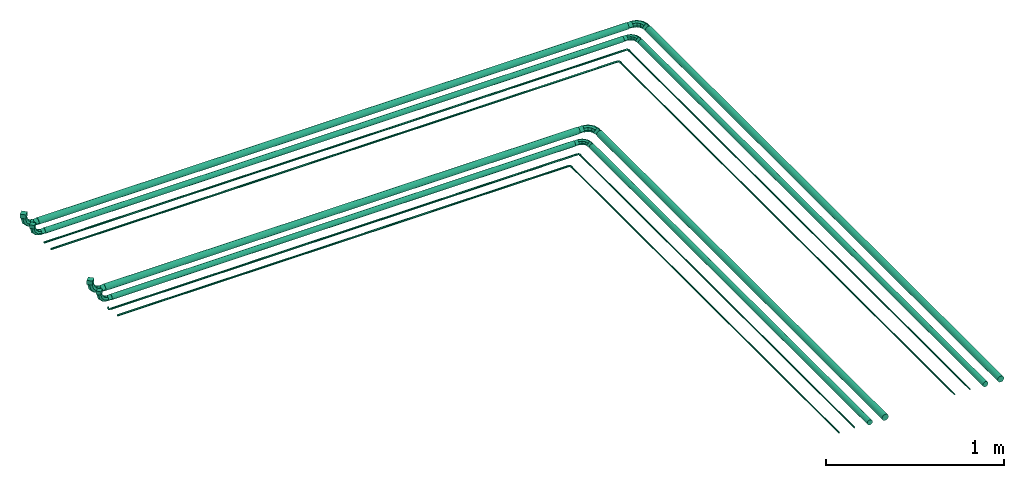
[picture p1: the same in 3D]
Properties of the parts of a building model (IFC2X3), part 7 of 7

# IfcFlowSegment: Rohrtypen:Kupfer - isoliert (851)
Name (Rohrtypen:Kupfer - isoliert:...) | In | Group
8632951 | EG_Produktion_FFB | B - FL-Str.02_NK-KK-TK
8632986 | EG_Produktion_FFB | B - SL_NK-Str.01
8633108 | EG_Produktion_FFB | A - SL_NK-Str.01
8633156 | EG_Produktion_FFB | A - FL-Str.02_NK-KK-TK
8633215 | EG_Produktion_FFB | A - SL_NK-Str.01
8633217 | EG_Produktion_FFB | A - FL-Str.02_NK-KK-TK
8633364 | EG_Produktion_FFB | A - SL_NK-Str.01
8633466 | EG_Produktion_FFB | A - FL-Str.02_NK-KK-TK
8633468 | EG_Produktion_FFB | A - SL_NK-Str.01
8633554 | EG_Produktion_FFB | A - SL_NK-Str.01
8633625 | EG_Produktion_FFB | A - FL-Str.02_NK-KK-TK
8633664 | EG_Produktion_FFB | B - SL_NK-Str.01
8633667 | EG_Produktion_FFB | B - FL-Str.02_NK-KK-TK
8633669 | EG_Produktion_FFB | B - SL_NK-Str.01
8633673 | EG_Produktion_FFB | B - SL_NK-Str.01
8633685 | EG_Produktion_FFB | B - FL-Str.02_NK-KK-TK
8634067 | EG_Produktion_FFB | A - FL-Str.01_NK-KK-TK
8634070 | EG_Produktion_FFB | A - SL_KK
8634119 | EG_Produktion_FFB | A - FL-Str.01_NK-KK-TK
8634135 | EG_Produktion_FFB | A - SL_KK
8634314 | EG_Produktion_FFB | A - SL_KK
8634342 | EG_Produktion_FFB | A - SL_KK
8634382 | EG_Produktion_FFB | A - FL-Str.01_NK-KK-TK
8634461 | EG_Produktion_FFB | A - FL-Str.01_NK-KK-TK
8679507 | EG_Technik_FFB | B - FL-Str.04_NK
8679535 | EG_Technik_FFB | B - FL-Str.04_NK
8679567 | EG_Produktion_FFB | B - FL-Str.04_NK
8679627 | EG_Produktion_FFB | B - FL-Str.04_NK
8679820 | EG_Produktion_FFB | B - FL-Str.04_NK
8680025 | EG_Produktion_FFB | B - SL_NK-Str.03
8680056 | EG_Technik_FFB | B - SL_NK-Str.03
8680059 | EG_Produktion_FFB | B - SL_NK-Str.03
8680061 | EG_Produktion_FFB | B - SL_NK-Str.03
8680091 | EG_Technik_FFB | B - SL_NK-Str.03
8680134 | EG_Produktion_FFB | A - FL-Str.04_NK
8680160 | EG_Technik_FFB | A - FL-Str.04_NK
8680185 | EG_Technik_FFB | A - FL-Str.04_NK
8680188 | EG_Produktion_FFB | A - FL-Str.04_NK
8680190 | EG_Produktion_FFB | A - FL-Str.04_NK
8680231 | EG_Produktion_FFB | A - SL_NK-Str.03
8680261 | EG_Technik_FFB | A - SL_NK-Str.03
8680286 | EG_Technik_FFB | A - SL_NK-Str.03
8680289 | EG_Produktion_FFB | A - SL_NK-Str.03
8680291 | EG_Produktion_FFB | A - SL_NK-Str.03
8680491 | EG_Produktion_FFB | B - SL_NK-Str.03
8680518 | EG_Produktion_FFB | B - FL-Str.04_NK
8680580 | EG_Produktion_FFB | A - SL_NK-Str.03
8680635 | EG_Produktion_FFB | A - FL-Str.04_NK
10081993 | EG_Produktion_FFB | B - Druckleitung Gaskühler
10082054 | EG_Produktion_FFB | B - Druckleitung Gaskühler
10082160 | EG_Produktion_FFB | A - Kondensatleitung Gaskühler
10082199 | EG_Produktion_FFB | A - Druckleitung Gaskühler
10082240 | EG_Produktion_FFB | A - Druckleitung Gaskühler

# IfcOpeningElement: Opening (64)
In: EG_Produktion_FFB
Name | Depth (mm) | Height (mm) | Width (mm)
Basiswand:Kühlzellen Paneelwand 120:4480336 | 120 | 3500 | 2800
Basiswand:Kühlzellen Paneelwand 120:5146188 | 120 | 3650 | 3060
Basiswand:Kühlzellen Paneelwand 120:5146348 | 120 | 3650 | 3060
Basiswand:Kühlzellen Paneelwand 120:5146624 | 120 | 3650 | 3060
Basiswand:Kühlzellen Paneelwand 120:5146830 | 120 | 3650 | 3060
2 x Basiswand:Kühlzellen Paneelwand 120:4266675 | 3048 | 2120 | 1540
2 x Basiswand:Kühlzellen Paneelwand 120:4266675 | 3048 | 250 | 1540
Basiswand:Kühlzellen Paneelwand 120:4266994 | 3048 | 2100 | 2000
Basiswand:Kühlzellen Paneelwand 120:4266994 | 3048 | 250 | 2000
Tiefkühlraumschiebetür:TKR Schiebetür 1500x2100:4269771:1 | 140 | 1540 | 2370
Tiefkühlraumschiebetür:TKR Schiebetür 1500x2100:4269725:1 | 140 | 1540 | 2370
Tiefkühlraumschiebetür:TKR Schiebetür 1500x2100:4482146:1 | 140 | 1540 | 2370
Basiswand:Kühlzellen Paneelwand 120:4267833 | 3048 | 2120 | 1540
Basiswand:Kühlzellen Paneelwand 120:4267833 | 3048 | 250 | 1540
Basiswand:Kühlzellen Paneelwand 120:4267937 | 3048 | 2120 | 1540
Basiswand:Kühlzellen Paneelwand 120:4267937 | 3048 | 250 | 1540
Basiswand:Kühlzellen Paneelwand 120:4268046 | 3048 | 2120 | 1540
Basiswand:Kühlzellen Paneelwand 120:4268046 | 3048 | 250 | 1540
Basiswand:Kühlzellen Paneelwand 120:4268621 | 3048 | 2120 | 1540
Basiswand:Kühlzellen Paneelwand 120:4268621 | 3048 | 250 | 1540
Basiswand:Kühlzellen Paneelwand 120:4268622 | 3048 | 2120 | 1540
Basiswand:Kühlzellen Paneelwand 120:4268622 | 3048 | 250 | 1540
Basiswand:Kühlzellen Paneelwand 120:4268623 | 3048 | 2120 | 1540
Basiswand:Kühlzellen Paneelwand 120:4268623 | 3048 | 250 | 1540
Basiswand:Kühlzellen Paneelwand 120:4268624 | 3048 | 2120 | 1540
Basiswand:Kühlzellen Paneelwand 120:4268624 | 3048 | 250 | 1540
Basiswand:Kühlzellen Paneelwand 120:4268649 | 3048 | 2100 | 2000
Basiswand:Kühlzellen Paneelwand 120:4268649 | 3048 | 250 | 2000
2 x Basiswand:Kühlzellen Paneelwand 120:4268956 | 3048 | 2100 | 2000
2 x Basiswand:Kühlzellen Paneelwand 120:4268956 | 3048 | 250 | 2000
Basiswand:Kühlzellen Paneelwand 120:4269063 | 3048 | 2175 | 1350
Basiswand:Kühlzellen Paneelwand 120:4269063 | 3048 | 250 | 1350
2 x Basiswand:Kühlzellen Paneelwand 120:4269106 | 3048 | 2100 | 2000
2 x Basiswand:Kühlzellen Paneelwand 120:4269106 | 3048 | 250 | 2000
Basiswand:Kühlzellen Paneelwand 120:4269106 | 3048 | 2175 | 1350
Basiswand:Kühlzellen Paneelwand 120:4269106 | 3048 | 250 | 1350
Basiswand:Kühlzellen Paneelwand 120:4269148 | 3048 | 2175 | 1350
Basiswand:Kühlzellen Paneelwand 120:4269148 | 3048 | 250 | 1350
Basiswand:Kühlzellen Paneelwand 120:4269409 | 3048 | 2100 | 2000
Basiswand:Kühlzellen Paneelwand 120:4269409 | 3048 | 250 | 2000
Tiefkühlraumschiebetür:TKR Schiebetür 1500x2100:4269685:1 | 140 | 2370 | 1540
Basiswand:Kühlzellen Paneelwand 140:4510115 | 3048 | 2370 | 1540
Basiswand:Kühlzellen Paneelwand 120:4479276 | 3048 | 2120 | 1240
Basiswand:Kühlzellen Paneelwand 120:4479276 | 3048 | 250 | 1240
Basiswand:Kühlzellen Paneelwand 120:4479276 | 3048 | 2175 | 1650
Basiswand:Kühlzellen Paneelwand 120:4479276 | 3048 | 250 | 1650
2 x Basiswand:Kühlzellen Paneelwand 120:4479560 | 3048 | 2175 | 1350
2 x Basiswand:Kühlzellen Paneelwand 120:4479560 | 3048 | 250 | 1350
Basiswand:Kühlzellen Paneelwand 120:4479695 | 3048 | 2175 | 1650
Basiswand:Kühlzellen Paneelwand 120:4479695 | 3048 | 250 | 1650
Basiswand:Kühlzellen Paneelwand 120:4480336 | 3048 | 2175 | 1150
Basiswand:Kühlzellen Paneelwand 120:4480336 | 3048 | 250 | 1150
Basiswand:Kühlzellen Paneelwand 120:4745924 | 3048 | 2175 | 1150
Basiswand:Kühlzellen Paneelwand 120:4745924 | 3048 | 250 | 1150
Basiswand:Kühlzellen Paneelwand 120:5095105 | 3048 | 2175 | 1150
Basiswand:Kühlzellen Paneelwand 120:5095105 | 3048 | 250 | 1150

# IfcWall: Basiswand:Kühlzellen Paneelwand 120 (3)
In: EG_Produktion_FFB
Type - PredefinedType: STANDARD; Material: GPG_Paneelwand 120 mm
Pset Bauphysik - OQ_Typ gem. Bauphysik: Pos. 1.7; U = 0,21 W/(m²/K)
Pset_FM-Vivantes - Baujahr: 1; Prüfpflicht: yes; Prüfintervall: 1; Sammelobjekt: yes; rechn. Lebensdauer: 1; Familie und Typ: Basiswand: Kühlzellen Paneelwand 120; Klasse: 471; Bezeichnung: Kühlzellen Paneelwand 120; AKS: i.b.; Standort: i.b.; Hersteller: i.b.; Hersteller-Typ: i.b.; Seriennummer: i.b.; Gewährleistungsgeber: 1; Betriebsstatus: i.b.; technischer Zustand: i.b.; Eigentümer: i.b.; Bemerkung: i.b.
Name (Basiswand:Kühlzellen Paneelwand 120:...) | Length (mm) | NetVolume (m3)
4266673 | 11277.2 | 4.87872
4267785 | 2660 | 1.09878
4512051 | 12620 | 5.33865

# IfcWall: Basiswand:Kühlzellen Paneelwand 140 (2)
In: EG_Produktion_FFB
Type - PredefinedType: STANDARD; Material: GPG_Paneelwand 140 mm
Pset Bauphysik - OQ_Typ gem. Bauphysik: Pos. 1.8; U = 0,18 W/(m²/K)
Pset_FM-Vivantes - Baujahr: 1; Prüfpflicht: yes; Prüfintervall: 1; Sammelobjekt: yes; rechn. Lebensdauer: 1; Familie und Typ: Basiswand: Kühlzellen Paneelwand 140; Klasse: 471; Bezeichnung: Kühlzellen Paneelwand 140; AKS: i.b.; Standort: i.b.; Hersteller: i.b.; Hersteller-Typ: i.b.; Seriennummer: i.b.; Gewährleistungsgeber: 1; Betriebsstatus: i.b.; technischer Zustand: i.b.; Eigentümer: i.b.; Bemerkung: i.b.
Name (Basiswand:Kühlzellen Paneelwand 140:...) | Length (mm) | NetVolume (m3)
4267288 | 6067.91 | 3.6104
4512797 | 4415 | 2.13532

# IfcWallStandardCase: Basiswand:Kühlzellen Paneelwand 120 (110)
In: EG_Produktion_FFB
Type - PredefinedType: STANDARD; Material: GPG_Paneelwand 120 mm
BaseQuantities - Width: 120 mm
Pset Bauphysik - OQ_Typ gem. Bauphysik: Pos. 1.7; U = 0,21 W/(m²/K)
Pset_FM-Vivantes - Familie und Typ: Basiswand: Kühlzellen Paneelwand 120; Klasse: 471; Bezeichnung: Kühlzellen Paneelwand 120; AKS: i.b.; Standort: i.b.; Hersteller: i.b.; Hersteller-Typ: i.b.; Seriennummer: i.b.; Baujahr: 1; Gewährleistungsgeber: 1; Betriebsstatus: i.b.; Prüfpflicht: yes; Prüfintervall: 1; Sammelobjekt: yes; rechn. Lebensdauer: 1; technischer Zustand: i.b.; Eigentümer: i.b.; Bemerkung: i.b.
Name (Basiswand:Kühlzellen Paneelwand 120:...) | Height (mm) | Length (mm) | GrossFootprintArea (m2) | GrossVolume (m3) | GrossSideArea (m2) = NetSideArea (m2) | NetVolume (m3)
4266672 | 3450 | 16105 | 1.9326 | 6.66747 | 55.5622 | 6.66747
4266674 | 3450 | 4495 | 0.5394 | 1.86093 | 15.5077 | 1.86093
4266675 | 3450 | 14862.1 | 1.78345 | 5.27695 | 43.9746 | 5.27695
4266700 | 3250 | 620 | 0.0744 | 0.2418 | 2.015 | 0.2418
4266701 | 3250 | 1920 | 0.2304 | 0.7488 | 6.24 | 0.7488
4266702 | 3250 | 620 | 0.0744 | 0.2418 | 2.015 | 0.2418
4266703 | 3250 | 1920 | 0.2304 | 0.7488 | 6.24 | 0.7488
4266722 | 3250 | 620 | 0.0744 | 0.2418 | 2.015 | 0.2418
4266723 | 3250 | 1920 | 0.2304 | 0.7488 | 6.24 | 0.7488
4266724 | 3250 | 620 | 0.0744 | 0.2418 | 2.015 | 0.2418
4266725 | 3250 | 1920 | 0.2304 | 0.7488 | 6.24 | 0.7488
4266750 | 3250 | 625 | 0.075 | 0.24375 | 2.03125 | 0.24375
4266751 | 3250 | 1970 | 0.2364 | 0.7683 | 6.4025 | 0.7683
4266752 | 3250 | 505 | 0.0606 | 0.19695 | 1.64125 | 0.19695
4266994 | 4158 | 7134.85 | 0.845414 | 2.99601 | 24.9667 | 2.95123
4267833 | 3450 | 3857.91 | 0.462949 | 1.1592 | 9.65998 | 1.1592
4267937 | 3450 | 4640 | 0.5568 | 1.48298 | 12.3582 | 1.48298
4268046 | 3250 | 4500 | 0.54 | 1.31702 | 10.9752 | 1.31702
4268599 | 3250 | 580 | 0.0696 | 0.2262 | 1.885 | 0.2262
4268600 | 3250 | 580 | 0.0696 | 0.2262 | 1.885 | 0.2262
4268601 | 3250 | 580 | 0.0696 | 0.2262 | 1.885 | 0.2262
4268602 | 3250 | 580 | 0.0696 | 0.2262 | 1.885 | 0.2262
4268621 | 3450 | 7930 | 0.9516 | 2.84504 | 23.7087 | 2.84504
4268622 | 3450 | 10080 | 1.2096 | 3.73514 | 31.1262 | 3.73514
4268623 | 3450 | 7930 | 0.9516 | 2.84504 | 23.7087 | 2.84504
4268624 | 3450 | 10080 | 1.2096 | 3.73514 | 31.1262 | 3.73514
4268647 | 3250 | 16015 | 1.9218 | 6.24585 | 52.0488 | 6.24585
4268648 | 3450 | 3690 | 0.4428 | 1.52766 | 12.7305 | 1.52766
4268649 | 3450 | 21630 | 2.5956 | 8.39082 | 69.9235 | 8.39082
4268956 | 3450 | 25720 | 3.0864 | 9.52008 | 79.334 | 9.52008
4269063 | 3450 | 19620 | 2.3544 | 7.72983 | 64.4153 | 7.72983
4269106 | 3450 | 15220 | 1.8264 | 4.78023 | 39.8352 | 4.78023
4269148 | 3450 | 6860 | 0.8232 | 2.44719 | 20.3933 | 2.44719
4269222 | 3250 | 620 | 0.0744 | 0.2418 | 2.015 | 0.2418
4269223 | 3250 | 620 | 0.0744 | 0.2418 | 2.015 | 0.2418
4269224 | 3250 | 620 | 0.0744 | 0.2418 | 2.015 | 0.2418
4269225 | 3250 | 620 | 0.0744 | 0.2418 | 2.015 | 0.2418
4269248 | 3250 | 520 | 0.0624 | 0.2028 | 1.69 | 0.2028
4269249 | 3250 | 3320 | 0.3984 | 1.2948 | 10.79 | 1.2948
4269250 | 3250 | 520 | 0.0624 | 0.2028 | 1.69 | 0.2028
4269251 | 3250 | 3320 | 0.3984 | 1.2948 | 10.79 | 1.2948
4269270 | 3250 | 620 | 0.0744 | 0.2418 | 2.015 | 0.2418
4269271 | 3250 | 620 | 0.0744 | 0.2418 | 2.015 | 0.2418
4269272 | 3250 | 620 | 0.0744 | 0.2418 | 2.015 | 0.2418
4269273 | 3250 | 620 | 0.0744 | 0.2418 | 2.015 | 0.2418
4269409 | 3450 | 13445 | 1.6134 | 5.00223 | 41.6853 | 5.00223
4479276 | 3450 | 7475 | 0.897 | 2.26184 | 18.8487 | 2.26184
4479277 | 3450 | 6500 | 0.78 | 2.691 | 22.425 | 2.691
4479560 | 4250 | 9480 | 1.1376 | 4.0491 | 33.7425 | 4.0491
4479695 | 4250 | 9023.3 | 1.0828 | 4.12173 | 34.3478 | 4.12173
4480077 | 4250 | 1530 | 0.1836 | 0.7803 | 6.5025 | 0.7803
4480110 | 4250 | 920 | 0.1104 | 0.4692 | 3.91 | 0.4692
4480245 | 4250 | 1430 | 0.1716 | 0.7293 | 6.0775 | 0.7293
4480336 | 4250 | 5532.71 | 0.661996 | 1.39503 | 11.6253 | 1.38683
4500319 | 4250 | 1328.22 | 0.157457 | 0.677391 | 5.64493 | 0.669192
4510408 | 3450 | 6500 | 0.78 | 2.691 | 22.425 | 2.691
4512455 | 3450 | 8094.9 | 0.971388 | 3.35129 | 27.9274 | 3.35129
4513250 | 3250 | 11610 | 1.3932 | 4.5279 | 37.7325 | 4.5279
4547134 | 3450 | 740 | 0.0888 | 0.30636 | 2.553 | 0.30636
4547214 | 3450 | 620 | 0.0744 | 0.25668 | 2.139 | 0.25668
4547310 | 3450 | 500 | 0.06 | 0.207 | 1.725 | 0.207
4745924 | 3450 | 4600 | 0.552 | 1.56975 | 13.0813 | 1.56975
5095105 | 4250 | 2000.36 | 0.238115 | 0.685536 | 5.7128 | 0.677337
5144328 | 3250 | 1520 | 0.1824 | 0.5928 | 4.94 | 0.5928
5144451 | 3250 | 1300 | 0.156 | 0.507 | 4.225 | 0.507
5146041 | 4000 | 654.573 | 0.0776008 | 0.314195 | 2.61829 | 0.310403
5146188 | 4000 | 4240 | 0.507852 | 0.87852 | 7.321 | 0.874728
5146275 | 4000 | 1258.78 | 0.151054 | 0.604216 | 5.03514 | 0.604216
5146348 | 4000 | 4130 | 0.4956 | 0.82572 | 6.881 | 0.82572
5146349 | 4000 | 2399.9 | 0.286059 | 1.15195 | 9.5996 | 1.14424
5146624 | 4000 | 4540 | 0.5448 | 1.02252 | 8.521 | 1.02252
5146830 | 4000 | 5715.12 | 0.685814 | 1.58658 | 13.2215 | 1.58658
5146896 | 4000 | 2300.61 | 0.274143 | 1.10429 | 9.20242 | 1.09657
5147819 | 4000 | 1379.21 | 0.165505 | 0.66202 | 5.51683 | 0.66202
5152133 | 3250 | 470 | 0.0564 | 0.1833 | 1.5275 | 0.1833
5152134 | 3250 | 600 | 0.072 | 0.234 | 1.95 | 0.234
5152292 | 3250 | 420 | 0.0504 | 0.1638 | 1.365 | 0.1638
5152293 | 3250 | 600 | 0.072 | 0.234 | 1.95 | 0.234
5152398 | 3250 | 640 | 0.0768 | 0.2496 | 2.08 | 0.2496
5152470 | 3250 | 350 | 0.042 | 0.1365 | 1.1375 | 0.1365
5152621 | 3250 | 350 | 0.042 | 0.1365 | 1.1375 | 0.1365
5152746 | 3250 | 540 | 0.0648 | 0.2106 | 1.755 | 0.2106
5152747 | 3250 | 300 | 0.036 | 0.117 | 0.975 | 0.117
5152748 | 3250 | 300 | 0.036 | 0.117 | 0.975 | 0.117
5153117 | 3450 | 450 | 0.054 | 0.1863 | 1.5525 | 0.1863
5153118 | 3450 | 480 | 0.0576 | 0.19872 | 1.656 | 0.19872
5153119 | 3450 | 330 | 0.0396 | 0.13662 | 1.1385 | 0.13662
5153510 | 4158 | 1100 | 0.132 | 0.548856 | 4.5738 | 0.548856
5153540 | 4158 | 330 | 0.0396 | 0.164657 | 1.37214 | 0.164657
5153935 | 3250 | 520 | 0.0624 | 0.2028 | 1.69 | 0.2028
5153936 | 3250 | 350 | 0.042 | 0.1365 | 1.1375 | 0.1365
5153937 | 3250 | 470 | 0.0564 | 0.1833 | 1.5275 | 0.1833
5153938 | 3250 | 520 | 0.0624 | 0.2028 | 1.69 | 0.2028
5153939 | 3250 | 350 | 0.042 | 0.1365 | 1.1375 | 0.1365
5153940 | 3250 | 470 | 0.0564 | 0.1833 | 1.5275 | 0.1833
5153941 | 3250 | 470 | 0.0564 | 0.1833 | 1.5275 | 0.1833
5153942 | 3250 | 350 | 0.042 | 0.1365 | 1.1375 | 0.1365
5154451 | 3250 | 540 | 0.0648 | 0.2106 | 1.755 | 0.2106
5154452 | 3250 | 300 | 0.036 | 0.117 | 0.975 | 0.117
5154453 | 3250 | 300 | 0.036 | 0.117 | 0.975 | 0.117
5165258 | 4250 | 1116.27 | 0.132023 | 0.569298 | 4.74415 | 0.561099
5173736 | 3450 | 420 | 0.0504 | 0.17388 | 1.449 | 0.17388
5173737 | 3450 | 420 | 0.0504 | 0.17388 | 1.449 | 0.17388
5183410 | 3450 | 470 | 0.0564 | 0.19458 | 1.6215 | 0.19458
5183411 | 3450 | 330 | 0.0396 | 0.13662 | 1.1385 | 0.13662
6511469 | 3450 | 5610 | 0.6732 | 2.32254 | 19.3545 | 2.32254
6615888 | 3450 | 300 | 0.036 | 0.1242 | 1.035 | 0.1242
7909195 | 3450 | 420 | 0.0504 | 0.17388 | 1.449 | 0.17388
7909196 | 3450 | 420 | 0.0504 | 0.17388 | 1.449 | 0.17388
7909241 | 3450 | 300 | 0.036 | 0.1242 | 1.035 | 0.1242

# IfcWallStandardCase: Basiswand:Kühlzellen Paneelwand 140 (9)
In: EG_Produktion_FFB
Type - PredefinedType: STANDARD; Material: GPG_Paneelwand 140 mm
BaseQuantities - Width: 140 mm
Pset Bauphysik - OQ_Typ gem. Bauphysik: Pos. 1.8; U = 0,18 W/(m²/K)
Pset_FM-Vivantes - Baujahr: 1; Prüfpflicht: yes; Prüfintervall: 1; Sammelobjekt: yes; rechn. Lebensdauer: 1; Familie und Typ: Basiswand: Kühlzellen Paneelwand 140; Klasse: 471; Bezeichnung: Kühlzellen Paneelwand 140; AKS: i.b.; Standort: i.b.; Hersteller: i.b.; Hersteller-Typ: i.b.; Seriennummer: i.b.; Gewährleistungsgeber: 1; Betriebsstatus: i.b.; technischer Zustand: i.b.; Eigentümer: i.b.; Bemerkung: i.b.
Name (Basiswand:Kühlzellen Paneelwand 140:...) | Height (mm) | Length (mm) | GrossFootprintArea (m2) | GrossVolume (m3) | GrossSideArea (m2) = NetSideArea (m2) | NetVolume (m3)
4267087 | 3250 | 7977.91 | 1.11691 | 3.11898 | 22.2784 | 3.11898
4267155 | 3250 | 16135 | 2.2589 | 7.34143 | 52.4388 | 7.34143
4267411 | 3250 | 5927.91 | 0.829907 | 2.18623 | 15.6159 | 2.18623
4267506 | 3250 | 2530 | 0.3528 | 1.15115 | 8.2225 | 1.1466
4267572 | 3450 | 4140 | 0.5796 | 1.48865 | 10.6332 | 1.48865
4510115 | 3250 | 11590 | 1.6226 | 4.76248 | 34.0177 | 4.76248
4512991 | 3250 | 2510 | 0.3514 | 1.14205 | 8.1575 | 1.14205
5151895 | 3250 | 560 | 0.0784 | 0.2548 | 1.82 | 0.2548
5151896 | 3250 | 1070.1 | 0.149814 | 0.486897 | 3.47784 | 0.486897

# IfcWindow: Entrauchungsluke Typ RWA12 elektrisch:Entrauchungsluke (8)
In: EG_Produktion_FFB
Type - ParameterTakesPrecedence: no; Sizeable: no; Material: Aluminium, Edelstahl, gebürstet, RAL 9002, PVC, hart, Edelstahl, <Unnamed>
OverallHeight: 1506 mm; OverallWidth: 1506 mm
Pset_FM-Vivantes - Baujahr: 1; Prüfpflicht: yes; Prüfintervall: 1; Sammelobjekt: yes; rechn. Lebensdauer: 1; fahrbar: no; Familie und Typ: Entrauchungsluke Typ RWA12 elektrisch: Entrauchungsluke; Klasse: 471; Bezeichnung: Entrauchungsluke; AKS: i.b.; Standort: i.b.; Hersteller: i.b.; Hersteller-Typ: i.b.; Seriennummer: i.b.; Gewährleistungsgeber: 1; Betriebsstatus: i.b.; technischer Zustand: i.b.; Eigentümer: i.b.; Bemerkung: i.b.
Name (Entrauchungsluke Typ RWA12 elektrisch:Entrauchungsluke:...)
5174337
5182999
5183019
5183037
5183059
5183079
5183097
7426801
